VERSION 5.8 ;
BUSBITCHARS "[]" ;
DIVIDERCHAR "/" ;
UNITS
    DATABASE MICRONS 1000 ;
END UNITS

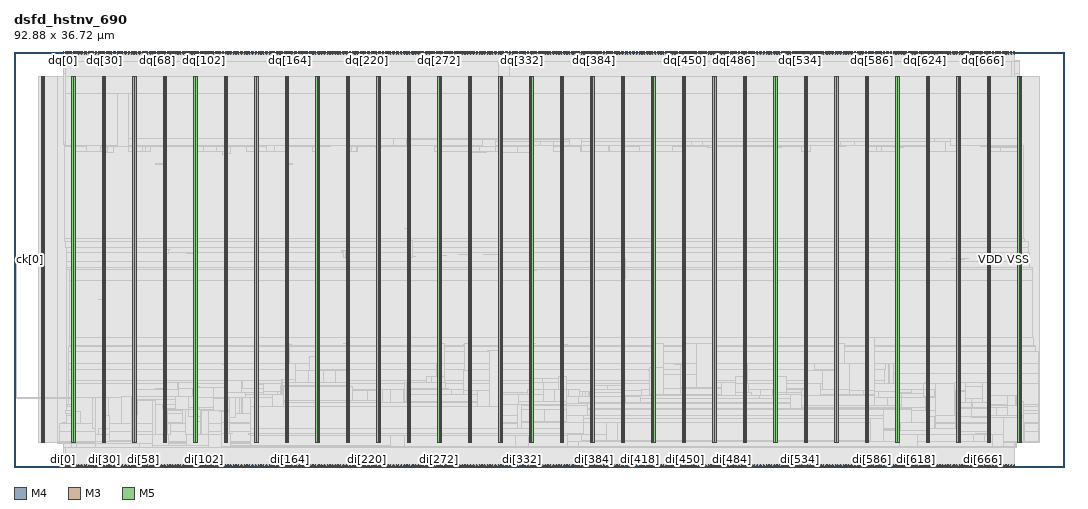
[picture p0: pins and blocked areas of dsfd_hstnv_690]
MACRO dsfd_hstnv_690
  FOREIGN dsfd_hstnv_690 0 0 ;
  CLASS BLOCK ;
  SIZE 92.88 BY 36.72 ;
  PIN ck[0]
    DIRECTION INPUT ;
    USE SIGNAL ;
    PORT
      LAYER M4 ;
        RECT  0 18.384 0.192 18.408 ;
    END
    PORT
      LAYER M4 ;
        RECT  0.156 18.384 0.275 18.408 ;
    END
  END ck[0]
  PIN di[0]
    DIRECTION INPUT ;
    USE SIGNAL ;
    PORT
      LAYER M3 ;
        RECT  4.356 0 4.374 0.144 ;
    END
  END di[0]
  PIN di[100]
    DIRECTION INPUT ;
    USE SIGNAL ;
    PORT
      LAYER M3 ;
        RECT  16.596 0 16.614 0.144 ;
    END
  END di[100]
  PIN di[101]
    DIRECTION INPUT ;
    USE SIGNAL ;
    PORT
      LAYER M5 ;
        RECT  16.704 0 16.728 0.192 ;
    END
  END di[101]
  PIN di[102]
    DIRECTION INPUT ;
    USE SIGNAL ;
    PORT
      LAYER M3 ;
        RECT  16.812 0 16.83 0.144 ;
    END
  END di[102]
  PIN di[103]
    DIRECTION INPUT ;
    USE SIGNAL ;
    PORT
      LAYER M5 ;
        RECT  16.944 0 16.968 0.192 ;
    END
  END di[103]
  PIN di[104]
    DIRECTION INPUT ;
    USE SIGNAL ;
    PORT
      LAYER M3 ;
        RECT  17.064 0 17.082 0.144 ;
    END
  END di[104]
  PIN di[105]
    DIRECTION INPUT ;
    USE SIGNAL ;
    PORT
      LAYER M5 ;
        RECT  17.184 0 17.208 0.192 ;
    END
  END di[105]
  PIN di[106]
    DIRECTION INPUT ;
    USE SIGNAL ;
    PORT
      LAYER M3 ;
        RECT  17.316 0 17.334 0.144 ;
    END
  END di[106]
  PIN di[107]
    DIRECTION INPUT ;
    USE SIGNAL ;
    PORT
      LAYER M5 ;
        RECT  17.424 0 17.448 0.192 ;
    END
  END di[107]
  PIN di[108]
    DIRECTION INPUT ;
    USE SIGNAL ;
    PORT
      LAYER M3 ;
        RECT  17.568 0 17.586 0.144 ;
    END
  END di[108]
  PIN di[109]
    DIRECTION INPUT ;
    USE SIGNAL ;
    PORT
      LAYER M5 ;
        RECT  17.664 0 17.688 0.192 ;
    END
  END di[109]
  PIN di[10]
    DIRECTION INPUT ;
    USE SIGNAL ;
    PORT
      LAYER M3 ;
        RECT  5.58 0 5.598 0.144 ;
    END
  END di[10]
  PIN di[110]
    DIRECTION INPUT ;
    USE SIGNAL ;
    PORT
      LAYER M3 ;
        RECT  17.784 0 17.802 0.144 ;
    END
  END di[110]
  PIN di[111]
    DIRECTION INPUT ;
    USE SIGNAL ;
    PORT
      LAYER M5 ;
        RECT  17.904 0 17.928 0.192 ;
    END
  END di[111]
  PIN di[112]
    DIRECTION INPUT ;
    USE SIGNAL ;
    PORT
      LAYER M3 ;
        RECT  18.036 0 18.054 0.144 ;
    END
  END di[112]
  PIN di[113]
    DIRECTION INPUT ;
    USE SIGNAL ;
    PORT
      LAYER M5 ;
        RECT  18.144 0 18.168 0.192 ;
    END
  END di[113]
  PIN di[114]
    DIRECTION INPUT ;
    USE SIGNAL ;
    PORT
      LAYER M3 ;
        RECT  18.288 0 18.306 0.144 ;
    END
  END di[114]
  PIN di[115]
    DIRECTION INPUT ;
    USE SIGNAL ;
    PORT
      LAYER M5 ;
        RECT  18.432 0 18.456 0.192 ;
    END
  END di[115]
  PIN di[116]
    DIRECTION INPUT ;
    USE SIGNAL ;
    PORT
      LAYER M3 ;
        RECT  18.54 0 18.558 0.144 ;
    END
  END di[116]
  PIN di[117]
    DIRECTION INPUT ;
    USE SIGNAL ;
    PORT
      LAYER M5 ;
        RECT  18.672 0 18.696 0.192 ;
    END
  END di[117]
  PIN di[118]
    DIRECTION INPUT ;
    USE SIGNAL ;
    PORT
      LAYER M3 ;
        RECT  18.792 0 18.81 0.144 ;
    END
  END di[118]
  PIN di[119]
    DIRECTION INPUT ;
    USE SIGNAL ;
    PORT
      LAYER M5 ;
        RECT  18.912 0 18.936 0.192 ;
    END
  END di[119]
  PIN di[11]
    DIRECTION INPUT ;
    USE SIGNAL ;
    PORT
      LAYER M5 ;
        RECT  5.712 0 5.736 0.192 ;
    END
  END di[11]
  PIN di[120]
    DIRECTION INPUT ;
    USE SIGNAL ;
    PORT
      LAYER M3 ;
        RECT  19.008 0 19.026 0.144 ;
    END
  END di[120]
  PIN di[121]
    DIRECTION INPUT ;
    USE SIGNAL ;
    PORT
      LAYER M5 ;
        RECT  19.152 0 19.176 0.192 ;
    END
  END di[121]
  PIN di[122]
    DIRECTION INPUT ;
    USE SIGNAL ;
    PORT
      LAYER M3 ;
        RECT  19.26 0 19.278 0.144 ;
    END
  END di[122]
  PIN di[123]
    DIRECTION INPUT ;
    USE SIGNAL ;
    PORT
      LAYER M5 ;
        RECT  19.392 0 19.416 0.192 ;
    END
  END di[123]
  PIN di[124]
    DIRECTION INPUT ;
    USE SIGNAL ;
    PORT
      LAYER M3 ;
        RECT  19.512 0 19.53 0.144 ;
    END
  END di[124]
  PIN di[125]
    DIRECTION INPUT ;
    USE SIGNAL ;
    PORT
      LAYER M5 ;
        RECT  19.632 0 19.656 0.192 ;
    END
  END di[125]
  PIN di[126]
    DIRECTION INPUT ;
    USE SIGNAL ;
    PORT
      LAYER M3 ;
        RECT  19.764 0 19.782 0.144 ;
    END
  END di[126]
  PIN di[127]
    DIRECTION INPUT ;
    USE SIGNAL ;
    PORT
      LAYER M5 ;
        RECT  19.872 0 19.896 0.192 ;
    END
  END di[127]
  PIN di[128]
    DIRECTION INPUT ;
    USE SIGNAL ;
    PORT
      LAYER M3 ;
        RECT  20.016 0 20.034 0.144 ;
    END
  END di[128]
  PIN di[129]
    DIRECTION INPUT ;
    USE SIGNAL ;
    PORT
      LAYER M5 ;
        RECT  20.112 0 20.136 0.192 ;
    END
  END di[129]
  PIN di[12]
    DIRECTION INPUT ;
    USE SIGNAL ;
    PORT
      LAYER M3 ;
        RECT  5.832 0 5.85 0.144 ;
    END
  END di[12]
  PIN di[130]
    DIRECTION INPUT ;
    USE SIGNAL ;
    PORT
      LAYER M3 ;
        RECT  20.232 0 20.25 0.144 ;
    END
  END di[130]
  PIN di[131]
    DIRECTION INPUT ;
    USE SIGNAL ;
    PORT
      LAYER M5 ;
        RECT  20.352 0 20.376 0.192 ;
    END
  END di[131]
  PIN di[132]
    DIRECTION INPUT ;
    USE SIGNAL ;
    PORT
      LAYER M3 ;
        RECT  20.484 0 20.502 0.144 ;
    END
  END di[132]
  PIN di[133]
    DIRECTION INPUT ;
    USE SIGNAL ;
    PORT
      LAYER M5 ;
        RECT  20.592 0 20.616 0.192 ;
    END
  END di[133]
  PIN di[134]
    DIRECTION INPUT ;
    USE SIGNAL ;
    PORT
      LAYER M3 ;
        RECT  20.736 0 20.754 0.144 ;
    END
  END di[134]
  PIN di[135]
    DIRECTION INPUT ;
    USE SIGNAL ;
    PORT
      LAYER M5 ;
        RECT  20.832 0 20.856 0.192 ;
    END
  END di[135]
  PIN di[136]
    DIRECTION INPUT ;
    USE SIGNAL ;
    PORT
      LAYER M3 ;
        RECT  20.988 0 21.006 0.144 ;
    END
  END di[136]
  PIN di[137]
    DIRECTION INPUT ;
    USE SIGNAL ;
    PORT
      LAYER M5 ;
        RECT  21.072 0 21.096 0.192 ;
    END
  END di[137]
  PIN di[138]
    DIRECTION INPUT ;
    USE SIGNAL ;
    PORT
      LAYER M3 ;
        RECT  21.204 0 21.222 0.144 ;
    END
  END di[138]
  PIN di[139]
    DIRECTION INPUT ;
    USE SIGNAL ;
    PORT
      LAYER M5 ;
        RECT  21.36 0 21.384 0.192 ;
    END
  END di[139]
  PIN di[13]
    DIRECTION INPUT ;
    USE SIGNAL ;
    PORT
      LAYER M5 ;
        RECT  5.952 0 5.976 0.192 ;
    END
  END di[13]
  PIN di[140]
    DIRECTION INPUT ;
    USE SIGNAL ;
    PORT
      LAYER M3 ;
        RECT  21.456 0 21.474 0.144 ;
    END
  END di[140]
  PIN di[141]
    DIRECTION INPUT ;
    USE SIGNAL ;
    PORT
      LAYER M5 ;
        RECT  21.6 0 21.624 0.192 ;
    END
  END di[141]
  PIN di[142]
    DIRECTION INPUT ;
    USE SIGNAL ;
    PORT
      LAYER M3 ;
        RECT  21.708 0 21.726 0.144 ;
    END
  END di[142]
  PIN di[143]
    DIRECTION INPUT ;
    USE SIGNAL ;
    PORT
      LAYER M5 ;
        RECT  21.84 0 21.864 0.192 ;
    END
  END di[143]
  PIN di[144]
    DIRECTION INPUT ;
    USE SIGNAL ;
    PORT
      LAYER M3 ;
        RECT  21.96 0 21.978 0.144 ;
    END
  END di[144]
  PIN di[145]
    DIRECTION INPUT ;
    USE SIGNAL ;
    PORT
      LAYER M5 ;
        RECT  22.08 0 22.104 0.192 ;
    END
  END di[145]
  PIN di[146]
    DIRECTION INPUT ;
    USE SIGNAL ;
    PORT
      LAYER M3 ;
        RECT  22.212 0 22.23 0.144 ;
    END
  END di[146]
  PIN di[147]
    DIRECTION INPUT ;
    USE SIGNAL ;
    PORT
      LAYER M5 ;
        RECT  22.32 0 22.344 0.192 ;
    END
  END di[147]
  PIN di[148]
    DIRECTION INPUT ;
    USE SIGNAL ;
    PORT
      LAYER M3 ;
        RECT  22.428 0 22.446 0.144 ;
    END
  END di[148]
  PIN di[149]
    DIRECTION INPUT ;
    USE SIGNAL ;
    PORT
      LAYER M5 ;
        RECT  22.56 0 22.584 0.192 ;
    END
  END di[149]
  PIN di[14]
    DIRECTION INPUT ;
    USE SIGNAL ;
    PORT
      LAYER M3 ;
        RECT  6.084 0 6.102 0.144 ;
    END
  END di[14]
  PIN di[150]
    DIRECTION INPUT ;
    USE SIGNAL ;
    PORT
      LAYER M3 ;
        RECT  22.68 0 22.698 0.144 ;
    END
  END di[150]
  PIN di[151]
    DIRECTION INPUT ;
    USE SIGNAL ;
    PORT
      LAYER M5 ;
        RECT  22.8 0 22.824 0.192 ;
    END
  END di[151]
  PIN di[152]
    DIRECTION INPUT ;
    USE SIGNAL ;
    PORT
      LAYER M3 ;
        RECT  22.932 0 22.95 0.144 ;
    END
  END di[152]
  PIN di[153]
    DIRECTION INPUT ;
    USE SIGNAL ;
    PORT
      LAYER M5 ;
        RECT  23.04 0 23.064 0.192 ;
    END
  END di[153]
  PIN di[154]
    DIRECTION INPUT ;
    USE SIGNAL ;
    PORT
      LAYER M3 ;
        RECT  23.184 0 23.202 0.144 ;
    END
  END di[154]
  PIN di[155]
    DIRECTION INPUT ;
    USE SIGNAL ;
    PORT
      LAYER M5 ;
        RECT  23.28 0 23.304 0.192 ;
    END
  END di[155]
  PIN di[156]
    DIRECTION INPUT ;
    USE SIGNAL ;
    PORT
      LAYER M3 ;
        RECT  23.4 0 23.418 0.144 ;
    END
  END di[156]
  PIN di[157]
    DIRECTION INPUT ;
    USE SIGNAL ;
    PORT
      LAYER M5 ;
        RECT  23.52 0 23.544 0.192 ;
    END
  END di[157]
  PIN di[158]
    DIRECTION INPUT ;
    USE SIGNAL ;
    PORT
      LAYER M3 ;
        RECT  23.652 0 23.67 0.144 ;
    END
  END di[158]
  PIN di[159]
    DIRECTION INPUT ;
    USE SIGNAL ;
    PORT
      LAYER M5 ;
        RECT  23.76 0 23.784 0.192 ;
    END
  END di[159]
  PIN di[15]
    DIRECTION INPUT ;
    USE SIGNAL ;
    PORT
      LAYER M5 ;
        RECT  6.192 0 6.216 0.192 ;
    END
  END di[15]
  PIN di[160]
    DIRECTION INPUT ;
    USE SIGNAL ;
    PORT
      LAYER M3 ;
        RECT  23.904 0 23.922 0.144 ;
    END
  END di[160]
  PIN di[161]
    DIRECTION INPUT ;
    USE SIGNAL ;
    PORT
      LAYER M5 ;
        RECT  24.048 0 24.072 0.192 ;
    END
  END di[161]
  PIN di[162]
    DIRECTION INPUT ;
    USE SIGNAL ;
    PORT
      LAYER M3 ;
        RECT  24.156 0 24.174 0.144 ;
    END
  END di[162]
  PIN di[163]
    DIRECTION INPUT ;
    USE SIGNAL ;
    PORT
      LAYER M5 ;
        RECT  24.288 0 24.312 0.192 ;
    END
  END di[163]
  PIN di[164]
    DIRECTION INPUT ;
    USE SIGNAL ;
    PORT
      LAYER M3 ;
        RECT  24.408 0 24.426 0.144 ;
    END
  END di[164]
  PIN di[165]
    DIRECTION INPUT ;
    USE SIGNAL ;
    PORT
      LAYER M5 ;
        RECT  24.528 0 24.552 0.192 ;
    END
  END di[165]
  PIN di[166]
    DIRECTION INPUT ;
    USE SIGNAL ;
    PORT
      LAYER M3 ;
        RECT  24.624 0 24.642 0.144 ;
    END
  END di[166]
  PIN di[167]
    DIRECTION INPUT ;
    USE SIGNAL ;
    PORT
      LAYER M5 ;
        RECT  24.768 0 24.792 0.192 ;
    END
  END di[167]
  PIN di[168]
    DIRECTION INPUT ;
    USE SIGNAL ;
    PORT
      LAYER M3 ;
        RECT  24.876 0 24.894 0.144 ;
    END
  END di[168]
  PIN di[169]
    DIRECTION INPUT ;
    USE SIGNAL ;
    PORT
      LAYER M5 ;
        RECT  25.008 0 25.032 0.192 ;
    END
  END di[169]
  PIN di[16]
    DIRECTION INPUT ;
    USE SIGNAL ;
    PORT
      LAYER M3 ;
        RECT  6.336 0 6.354 0.144 ;
    END
  END di[16]
  PIN di[170]
    DIRECTION INPUT ;
    USE SIGNAL ;
    PORT
      LAYER M3 ;
        RECT  25.128 0 25.146 0.144 ;
    END
  END di[170]
  PIN di[171]
    DIRECTION INPUT ;
    USE SIGNAL ;
    PORT
      LAYER M5 ;
        RECT  25.248 0 25.272 0.192 ;
    END
  END di[171]
  PIN di[172]
    DIRECTION INPUT ;
    USE SIGNAL ;
    PORT
      LAYER M3 ;
        RECT  25.38 0 25.398 0.144 ;
    END
  END di[172]
  PIN di[173]
    DIRECTION INPUT ;
    USE SIGNAL ;
    PORT
      LAYER M5 ;
        RECT  25.488 0 25.512 0.192 ;
    END
  END di[173]
  PIN di[174]
    DIRECTION INPUT ;
    USE SIGNAL ;
    PORT
      LAYER M3 ;
        RECT  25.632 0 25.65 0.144 ;
    END
  END di[174]
  PIN di[175]
    DIRECTION INPUT ;
    USE SIGNAL ;
    PORT
      LAYER M5 ;
        RECT  25.728 0 25.752 0.192 ;
    END
  END di[175]
  PIN di[176]
    DIRECTION INPUT ;
    USE SIGNAL ;
    PORT
      LAYER M3 ;
        RECT  25.848 0 25.866 0.144 ;
    END
  END di[176]
  PIN di[177]
    DIRECTION INPUT ;
    USE SIGNAL ;
    PORT
      LAYER M5 ;
        RECT  25.968 0 25.992 0.192 ;
    END
  END di[177]
  PIN di[178]
    DIRECTION INPUT ;
    USE SIGNAL ;
    PORT
      LAYER M3 ;
        RECT  26.1 0 26.118 0.144 ;
    END
  END di[178]
  PIN di[179]
    DIRECTION INPUT ;
    USE SIGNAL ;
    PORT
      LAYER M5 ;
        RECT  26.208 0 26.232 0.192 ;
    END
  END di[179]
  PIN di[17]
    DIRECTION INPUT ;
    USE SIGNAL ;
    PORT
      LAYER M5 ;
        RECT  6.432 0 6.456 0.192 ;
    END
  END di[17]
  PIN di[180]
    DIRECTION INPUT ;
    USE SIGNAL ;
    PORT
      LAYER M3 ;
        RECT  26.352 0 26.37 0.144 ;
    END
  END di[180]
  PIN di[181]
    DIRECTION INPUT ;
    USE SIGNAL ;
    PORT
      LAYER M5 ;
        RECT  26.448 0 26.472 0.192 ;
    END
  END di[181]
  PIN di[182]
    DIRECTION INPUT ;
    USE SIGNAL ;
    PORT
      LAYER M3 ;
        RECT  26.604 0 26.622 0.144 ;
    END
  END di[182]
  PIN di[183]
    DIRECTION INPUT ;
    USE SIGNAL ;
    PORT
      LAYER M5 ;
        RECT  26.688 0 26.712 0.192 ;
    END
  END di[183]
  PIN di[184]
    DIRECTION INPUT ;
    USE SIGNAL ;
    PORT
      LAYER M3 ;
        RECT  26.82 0 26.838 0.144 ;
    END
  END di[184]
  PIN di[185]
    DIRECTION INPUT ;
    USE SIGNAL ;
    PORT
      LAYER M5 ;
        RECT  26.976 0 27 0.192 ;
    END
  END di[185]
  PIN di[186]
    DIRECTION INPUT ;
    USE SIGNAL ;
    PORT
      LAYER M3 ;
        RECT  27.072 0 27.09 0.144 ;
    END
  END di[186]
  PIN di[187]
    DIRECTION INPUT ;
    USE SIGNAL ;
    PORT
      LAYER M5 ;
        RECT  27.216 0 27.24 0.192 ;
    END
  END di[187]
  PIN di[188]
    DIRECTION INPUT ;
    USE SIGNAL ;
    PORT
      LAYER M3 ;
        RECT  27.324 0 27.342 0.144 ;
    END
  END di[188]
  PIN di[189]
    DIRECTION INPUT ;
    USE SIGNAL ;
    PORT
      LAYER M5 ;
        RECT  27.456 0 27.48 0.192 ;
    END
  END di[189]
  PIN di[18]
    DIRECTION INPUT ;
    USE SIGNAL ;
    PORT
      LAYER M3 ;
        RECT  6.552 0 6.57 0.144 ;
    END
  END di[18]
  PIN di[190]
    DIRECTION INPUT ;
    USE SIGNAL ;
    PORT
      LAYER M3 ;
        RECT  27.576 0 27.594 0.144 ;
    END
  END di[190]
  PIN di[191]
    DIRECTION INPUT ;
    USE SIGNAL ;
    PORT
      LAYER M5 ;
        RECT  27.696 0 27.72 0.192 ;
    END
  END di[191]
  PIN di[192]
    DIRECTION INPUT ;
    USE SIGNAL ;
    PORT
      LAYER M3 ;
        RECT  27.828 0 27.846 0.144 ;
    END
  END di[192]
  PIN di[193]
    DIRECTION INPUT ;
    USE SIGNAL ;
    PORT
      LAYER M5 ;
        RECT  27.936 0 27.96 0.192 ;
    END
  END di[193]
  PIN di[194]
    DIRECTION INPUT ;
    USE SIGNAL ;
    PORT
      LAYER M3 ;
        RECT  28.044 0 28.062 0.144 ;
    END
  END di[194]
  PIN di[195]
    DIRECTION INPUT ;
    USE SIGNAL ;
    PORT
      LAYER M5 ;
        RECT  28.176 0 28.2 0.192 ;
    END
  END di[195]
  PIN di[196]
    DIRECTION INPUT ;
    USE SIGNAL ;
    PORT
      LAYER M3 ;
        RECT  28.296 0 28.314 0.144 ;
    END
  END di[196]
  PIN di[197]
    DIRECTION INPUT ;
    USE SIGNAL ;
    PORT
      LAYER M5 ;
        RECT  28.416 0 28.44 0.192 ;
    END
  END di[197]
  PIN di[198]
    DIRECTION INPUT ;
    USE SIGNAL ;
    PORT
      LAYER M3 ;
        RECT  28.548 0 28.566 0.144 ;
    END
  END di[198]
  PIN di[199]
    DIRECTION INPUT ;
    USE SIGNAL ;
    PORT
      LAYER M5 ;
        RECT  28.656 0 28.68 0.192 ;
    END
  END di[199]
  PIN di[19]
    DIRECTION INPUT ;
    USE SIGNAL ;
    PORT
      LAYER M5 ;
        RECT  6.672 0 6.696 0.192 ;
    END
  END di[19]
  PIN di[1]
    DIRECTION INPUT ;
    USE SIGNAL ;
    PORT
      LAYER M5 ;
        RECT  4.512 0 4.536 0.192 ;
    END
  END di[1]
  PIN di[200]
    DIRECTION INPUT ;
    USE SIGNAL ;
    PORT
      LAYER M3 ;
        RECT  28.8 0 28.818 0.144 ;
    END
  END di[200]
  PIN di[201]
    DIRECTION INPUT ;
    USE SIGNAL ;
    PORT
      LAYER M5 ;
        RECT  28.896 0 28.92 0.192 ;
    END
  END di[201]
  PIN di[202]
    DIRECTION INPUT ;
    USE SIGNAL ;
    PORT
      LAYER M3 ;
        RECT  29.016 0 29.034 0.144 ;
    END
  END di[202]
  PIN di[203]
    DIRECTION INPUT ;
    USE SIGNAL ;
    PORT
      LAYER M5 ;
        RECT  29.136 0 29.16 0.192 ;
    END
  END di[203]
  PIN di[204]
    DIRECTION INPUT ;
    USE SIGNAL ;
    PORT
      LAYER M3 ;
        RECT  29.268 0 29.286 0.144 ;
    END
  END di[204]
  PIN di[205]
    DIRECTION INPUT ;
    USE SIGNAL ;
    PORT
      LAYER M5 ;
        RECT  29.376 0 29.4 0.192 ;
    END
  END di[205]
  PIN di[206]
    DIRECTION INPUT ;
    USE SIGNAL ;
    PORT
      LAYER M3 ;
        RECT  29.52 0 29.538 0.144 ;
    END
  END di[206]
  PIN di[207]
    DIRECTION INPUT ;
    USE SIGNAL ;
    PORT
      LAYER M5 ;
        RECT  29.664 0 29.688 0.192 ;
    END
  END di[207]
  PIN di[208]
    DIRECTION INPUT ;
    USE SIGNAL ;
    PORT
      LAYER M3 ;
        RECT  29.772 0 29.79 0.144 ;
    END
  END di[208]
  PIN di[209]
    DIRECTION INPUT ;
    USE SIGNAL ;
    PORT
      LAYER M5 ;
        RECT  29.904 0 29.928 0.192 ;
    END
  END di[209]
  PIN di[20]
    DIRECTION INPUT ;
    USE SIGNAL ;
    PORT
      LAYER M3 ;
        RECT  6.804 0 6.822 0.144 ;
    END
  END di[20]
  PIN di[210]
    DIRECTION INPUT ;
    USE SIGNAL ;
    PORT
      LAYER M3 ;
        RECT  30.024 0 30.042 0.144 ;
    END
  END di[210]
  PIN di[211]
    DIRECTION INPUT ;
    USE SIGNAL ;
    PORT
      LAYER M5 ;
        RECT  30.144 0 30.168 0.192 ;
    END
  END di[211]
  PIN di[212]
    DIRECTION INPUT ;
    USE SIGNAL ;
    PORT
      LAYER M3 ;
        RECT  30.24 0 30.258 0.144 ;
    END
  END di[212]
  PIN di[213]
    DIRECTION INPUT ;
    USE SIGNAL ;
    PORT
      LAYER M5 ;
        RECT  30.384 0 30.408 0.192 ;
    END
  END di[213]
  PIN di[214]
    DIRECTION INPUT ;
    USE SIGNAL ;
    PORT
      LAYER M3 ;
        RECT  30.492 0 30.51 0.144 ;
    END
  END di[214]
  PIN di[215]
    DIRECTION INPUT ;
    USE SIGNAL ;
    PORT
      LAYER M5 ;
        RECT  30.624 0 30.648 0.192 ;
    END
  END di[215]
  PIN di[216]
    DIRECTION INPUT ;
    USE SIGNAL ;
    PORT
      LAYER M3 ;
        RECT  30.744 0 30.762 0.144 ;
    END
  END di[216]
  PIN di[217]
    DIRECTION INPUT ;
    USE SIGNAL ;
    PORT
      LAYER M5 ;
        RECT  30.864 0 30.888 0.192 ;
    END
  END di[217]
  PIN di[218]
    DIRECTION INPUT ;
    USE SIGNAL ;
    PORT
      LAYER M3 ;
        RECT  30.996 0 31.014 0.144 ;
    END
  END di[218]
  PIN di[219]
    DIRECTION INPUT ;
    USE SIGNAL ;
    PORT
      LAYER M5 ;
        RECT  31.104 0 31.128 0.192 ;
    END
  END di[219]
  PIN di[21]
    DIRECTION INPUT ;
    USE SIGNAL ;
    PORT
      LAYER M5 ;
        RECT  6.912 0 6.936 0.192 ;
    END
  END di[21]
  PIN di[220]
    DIRECTION INPUT ;
    USE SIGNAL ;
    PORT
      LAYER M3 ;
        RECT  31.248 0 31.266 0.144 ;
    END
  END di[220]
  PIN di[221]
    DIRECTION INPUT ;
    USE SIGNAL ;
    PORT
      LAYER M5 ;
        RECT  31.344 0 31.368 0.192 ;
    END
  END di[221]
  PIN di[222]
    DIRECTION INPUT ;
    USE SIGNAL ;
    PORT
      LAYER M3 ;
        RECT  31.464 0 31.482 0.144 ;
    END
  END di[222]
  PIN di[223]
    DIRECTION INPUT ;
    USE SIGNAL ;
    PORT
      LAYER M5 ;
        RECT  31.584 0 31.608 0.192 ;
    END
  END di[223]
  PIN di[224]
    DIRECTION INPUT ;
    USE SIGNAL ;
    PORT
      LAYER M3 ;
        RECT  31.716 0 31.734 0.144 ;
    END
  END di[224]
  PIN di[225]
    DIRECTION INPUT ;
    USE SIGNAL ;
    PORT
      LAYER M5 ;
        RECT  31.824 0 31.848 0.192 ;
    END
  END di[225]
  PIN di[226]
    DIRECTION INPUT ;
    USE SIGNAL ;
    PORT
      LAYER M3 ;
        RECT  31.968 0 31.986 0.144 ;
    END
  END di[226]
  PIN di[227]
    DIRECTION INPUT ;
    USE SIGNAL ;
    PORT
      LAYER M5 ;
        RECT  32.064 0 32.088 0.192 ;
    END
  END di[227]
  PIN di[228]
    DIRECTION INPUT ;
    USE SIGNAL ;
    PORT
      LAYER M3 ;
        RECT  32.22 0 32.238 0.144 ;
    END
  END di[228]
  PIN di[229]
    DIRECTION INPUT ;
    USE SIGNAL ;
    PORT
      LAYER M5 ;
        RECT  32.304 0 32.328 0.192 ;
    END
  END di[229]
  PIN di[22]
    DIRECTION INPUT ;
    USE SIGNAL ;
    PORT
      LAYER M3 ;
        RECT  7.056 0 7.074 0.144 ;
    END
  END di[22]
  PIN di[230]
    DIRECTION INPUT ;
    USE SIGNAL ;
    PORT
      LAYER M3 ;
        RECT  32.436 0 32.454 0.144 ;
    END
  END di[230]
  PIN di[231]
    DIRECTION INPUT ;
    USE SIGNAL ;
    PORT
      LAYER M5 ;
        RECT  32.592 0 32.616 0.192 ;
    END
  END di[231]
  PIN di[232]
    DIRECTION INPUT ;
    USE SIGNAL ;
    PORT
      LAYER M3 ;
        RECT  32.688 0 32.706 0.144 ;
    END
  END di[232]
  PIN di[233]
    DIRECTION INPUT ;
    USE SIGNAL ;
    PORT
      LAYER M5 ;
        RECT  32.832 0 32.856 0.192 ;
    END
  END di[233]
  PIN di[234]
    DIRECTION INPUT ;
    USE SIGNAL ;
    PORT
      LAYER M3 ;
        RECT  32.94 0 32.958 0.144 ;
    END
  END di[234]
  PIN di[235]
    DIRECTION INPUT ;
    USE SIGNAL ;
    PORT
      LAYER M5 ;
        RECT  33.072 0 33.096 0.192 ;
    END
  END di[235]
  PIN di[236]
    DIRECTION INPUT ;
    USE SIGNAL ;
    PORT
      LAYER M3 ;
        RECT  33.192 0 33.21 0.144 ;
    END
  END di[236]
  PIN di[237]
    DIRECTION INPUT ;
    USE SIGNAL ;
    PORT
      LAYER M5 ;
        RECT  33.312 0 33.336 0.192 ;
    END
  END di[237]
  PIN di[238]
    DIRECTION INPUT ;
    USE SIGNAL ;
    PORT
      LAYER M3 ;
        RECT  33.444 0 33.462 0.144 ;
    END
  END di[238]
  PIN di[239]
    DIRECTION INPUT ;
    USE SIGNAL ;
    PORT
      LAYER M5 ;
        RECT  33.552 0 33.576 0.192 ;
    END
  END di[239]
  PIN di[23]
    DIRECTION INPUT ;
    USE SIGNAL ;
    PORT
      LAYER M5 ;
        RECT  7.2 0 7.224 0.192 ;
    END
  END di[23]
  PIN di[240]
    DIRECTION INPUT ;
    USE SIGNAL ;
    PORT
      LAYER M3 ;
        RECT  33.66 0 33.678 0.144 ;
    END
  END di[240]
  PIN di[241]
    DIRECTION INPUT ;
    USE SIGNAL ;
    PORT
      LAYER M5 ;
        RECT  33.792 0 33.816 0.192 ;
    END
  END di[241]
  PIN di[242]
    DIRECTION INPUT ;
    USE SIGNAL ;
    PORT
      LAYER M3 ;
        RECT  33.912 0 33.93 0.144 ;
    END
  END di[242]
  PIN di[243]
    DIRECTION INPUT ;
    USE SIGNAL ;
    PORT
      LAYER M5 ;
        RECT  34.032 0 34.056 0.192 ;
    END
  END di[243]
  PIN di[244]
    DIRECTION INPUT ;
    USE SIGNAL ;
    PORT
      LAYER M3 ;
        RECT  34.164 0 34.182 0.144 ;
    END
  END di[244]
  PIN di[245]
    DIRECTION INPUT ;
    USE SIGNAL ;
    PORT
      LAYER M5 ;
        RECT  34.272 0 34.296 0.192 ;
    END
  END di[245]
  PIN di[246]
    DIRECTION INPUT ;
    USE SIGNAL ;
    PORT
      LAYER M3 ;
        RECT  34.416 0 34.434 0.144 ;
    END
  END di[246]
  PIN di[247]
    DIRECTION INPUT ;
    USE SIGNAL ;
    PORT
      LAYER M5 ;
        RECT  34.512 0 34.536 0.192 ;
    END
  END di[247]
  PIN di[248]
    DIRECTION INPUT ;
    USE SIGNAL ;
    PORT
      LAYER M3 ;
        RECT  34.632 0 34.65 0.144 ;
    END
  END di[248]
  PIN di[249]
    DIRECTION INPUT ;
    USE SIGNAL ;
    PORT
      LAYER M5 ;
        RECT  34.752 0 34.776 0.192 ;
    END
  END di[249]
  PIN di[24]
    DIRECTION INPUT ;
    USE SIGNAL ;
    PORT
      LAYER M3 ;
        RECT  7.308 0 7.326 0.144 ;
    END
  END di[24]
  PIN di[250]
    DIRECTION INPUT ;
    USE SIGNAL ;
    PORT
      LAYER M3 ;
        RECT  34.884 0 34.902 0.144 ;
    END
  END di[250]
  PIN di[251]
    DIRECTION INPUT ;
    USE SIGNAL ;
    PORT
      LAYER M5 ;
        RECT  34.992 0 35.016 0.192 ;
    END
  END di[251]
  PIN di[252]
    DIRECTION INPUT ;
    USE SIGNAL ;
    PORT
      LAYER M3 ;
        RECT  35.136 0 35.154 0.144 ;
    END
  END di[252]
  PIN di[253]
    DIRECTION INPUT ;
    USE SIGNAL ;
    PORT
      LAYER M5 ;
        RECT  35.28 0 35.304 0.192 ;
    END
  END di[253]
  PIN di[254]
    DIRECTION INPUT ;
    USE SIGNAL ;
    PORT
      LAYER M3 ;
        RECT  35.388 0 35.406 0.144 ;
    END
  END di[254]
  PIN di[255]
    DIRECTION INPUT ;
    USE SIGNAL ;
    PORT
      LAYER M5 ;
        RECT  35.52 0 35.544 0.192 ;
    END
  END di[255]
  PIN di[256]
    DIRECTION INPUT ;
    USE SIGNAL ;
    PORT
      LAYER M3 ;
        RECT  35.64 0 35.658 0.144 ;
    END
  END di[256]
  PIN di[257]
    DIRECTION INPUT ;
    USE SIGNAL ;
    PORT
      LAYER M5 ;
        RECT  35.76 0 35.784 0.192 ;
    END
  END di[257]
  PIN di[258]
    DIRECTION INPUT ;
    USE SIGNAL ;
    PORT
      LAYER M3 ;
        RECT  35.856 0 35.874 0.144 ;
    END
  END di[258]
  PIN di[259]
    DIRECTION INPUT ;
    USE SIGNAL ;
    PORT
      LAYER M5 ;
        RECT  36 0 36.024 0.192 ;
    END
  END di[259]
  PIN di[25]
    DIRECTION INPUT ;
    USE SIGNAL ;
    PORT
      LAYER M5 ;
        RECT  7.44 0 7.464 0.192 ;
    END
  END di[25]
  PIN di[260]
    DIRECTION INPUT ;
    USE SIGNAL ;
    PORT
      LAYER M3 ;
        RECT  36.108 0 36.126 0.144 ;
    END
  END di[260]
  PIN di[261]
    DIRECTION INPUT ;
    USE SIGNAL ;
    PORT
      LAYER M5 ;
        RECT  36.24 0 36.264 0.192 ;
    END
  END di[261]
  PIN di[262]
    DIRECTION INPUT ;
    USE SIGNAL ;
    PORT
      LAYER M3 ;
        RECT  36.36 0 36.378 0.144 ;
    END
  END di[262]
  PIN di[263]
    DIRECTION INPUT ;
    USE SIGNAL ;
    PORT
      LAYER M5 ;
        RECT  36.48 0 36.504 0.192 ;
    END
  END di[263]
  PIN di[264]
    DIRECTION INPUT ;
    USE SIGNAL ;
    PORT
      LAYER M3 ;
        RECT  36.612 0 36.63 0.144 ;
    END
  END di[264]
  PIN di[265]
    DIRECTION INPUT ;
    USE SIGNAL ;
    PORT
      LAYER M5 ;
        RECT  36.72 0 36.744 0.192 ;
    END
  END di[265]
  PIN di[266]
    DIRECTION INPUT ;
    USE SIGNAL ;
    PORT
      LAYER M3 ;
        RECT  36.864 0 36.882 0.144 ;
    END
  END di[266]
  PIN di[267]
    DIRECTION INPUT ;
    USE SIGNAL ;
    PORT
      LAYER M5 ;
        RECT  36.96 0 36.984 0.192 ;
    END
  END di[267]
  PIN di[268]
    DIRECTION INPUT ;
    USE SIGNAL ;
    PORT
      LAYER M3 ;
        RECT  37.08 0 37.098 0.144 ;
    END
  END di[268]
  PIN di[269]
    DIRECTION INPUT ;
    USE SIGNAL ;
    PORT
      LAYER M5 ;
        RECT  37.2 0 37.224 0.192 ;
    END
  END di[269]
  PIN di[26]
    DIRECTION INPUT ;
    USE SIGNAL ;
    PORT
      LAYER M3 ;
        RECT  7.56 0 7.578 0.144 ;
    END
  END di[26]
  PIN di[270]
    DIRECTION INPUT ;
    USE SIGNAL ;
    PORT
      LAYER M3 ;
        RECT  37.332 0 37.35 0.144 ;
    END
  END di[270]
  PIN di[271]
    DIRECTION INPUT ;
    USE SIGNAL ;
    PORT
      LAYER M5 ;
        RECT  37.44 0 37.464 0.192 ;
    END
  END di[271]
  PIN di[272]
    DIRECTION INPUT ;
    USE SIGNAL ;
    PORT
      LAYER M3 ;
        RECT  37.584 0 37.602 0.144 ;
    END
  END di[272]
  PIN di[273]
    DIRECTION INPUT ;
    USE SIGNAL ;
    PORT
      LAYER M5 ;
        RECT  37.68 0 37.704 0.192 ;
    END
  END di[273]
  PIN di[274]
    DIRECTION INPUT ;
    USE SIGNAL ;
    PORT
      LAYER M3 ;
        RECT  37.836 0 37.854 0.144 ;
    END
  END di[274]
  PIN di[275]
    DIRECTION INPUT ;
    USE SIGNAL ;
    PORT
      LAYER M5 ;
        RECT  37.92 0 37.944 0.192 ;
    END
  END di[275]
  PIN di[276]
    DIRECTION INPUT ;
    USE SIGNAL ;
    PORT
      LAYER M3 ;
        RECT  38.052 0 38.07 0.144 ;
    END
  END di[276]
  PIN di[277]
    DIRECTION INPUT ;
    USE SIGNAL ;
    PORT
      LAYER M5 ;
        RECT  38.208 0 38.232 0.192 ;
    END
  END di[277]
  PIN di[278]
    DIRECTION INPUT ;
    USE SIGNAL ;
    PORT
      LAYER M3 ;
        RECT  38.304 0 38.322 0.144 ;
    END
  END di[278]
  PIN di[279]
    DIRECTION INPUT ;
    USE SIGNAL ;
    PORT
      LAYER M5 ;
        RECT  38.448 0 38.472 0.192 ;
    END
  END di[279]
  PIN di[27]
    DIRECTION INPUT ;
    USE SIGNAL ;
    PORT
      LAYER M5 ;
        RECT  7.68 0 7.704 0.192 ;
    END
  END di[27]
  PIN di[280]
    DIRECTION INPUT ;
    USE SIGNAL ;
    PORT
      LAYER M3 ;
        RECT  38.556 0 38.574 0.144 ;
    END
  END di[280]
  PIN di[281]
    DIRECTION INPUT ;
    USE SIGNAL ;
    PORT
      LAYER M5 ;
        RECT  38.688 0 38.712 0.192 ;
    END
  END di[281]
  PIN di[282]
    DIRECTION INPUT ;
    USE SIGNAL ;
    PORT
      LAYER M3 ;
        RECT  38.808 0 38.826 0.144 ;
    END
  END di[282]
  PIN di[283]
    DIRECTION INPUT ;
    USE SIGNAL ;
    PORT
      LAYER M5 ;
        RECT  38.928 0 38.952 0.192 ;
    END
  END di[283]
  PIN di[284]
    DIRECTION INPUT ;
    USE SIGNAL ;
    PORT
      LAYER M3 ;
        RECT  39.06 0 39.078 0.144 ;
    END
  END di[284]
  PIN di[285]
    DIRECTION INPUT ;
    USE SIGNAL ;
    PORT
      LAYER M5 ;
        RECT  39.168 0 39.192 0.192 ;
    END
  END di[285]
  PIN di[286]
    DIRECTION INPUT ;
    USE SIGNAL ;
    PORT
      LAYER M3 ;
        RECT  39.276 0 39.294 0.144 ;
    END
  END di[286]
  PIN di[287]
    DIRECTION INPUT ;
    USE SIGNAL ;
    PORT
      LAYER M5 ;
        RECT  39.408 0 39.432 0.192 ;
    END
  END di[287]
  PIN di[288]
    DIRECTION INPUT ;
    USE SIGNAL ;
    PORT
      LAYER M3 ;
        RECT  39.528 0 39.546 0.144 ;
    END
  END di[288]
  PIN di[289]
    DIRECTION INPUT ;
    USE SIGNAL ;
    PORT
      LAYER M5 ;
        RECT  39.648 0 39.672 0.192 ;
    END
  END di[289]
  PIN di[28]
    DIRECTION INPUT ;
    USE SIGNAL ;
    PORT
      LAYER M3 ;
        RECT  7.776 0 7.794 0.144 ;
    END
  END di[28]
  PIN di[290]
    DIRECTION INPUT ;
    USE SIGNAL ;
    PORT
      LAYER M3 ;
        RECT  39.78 0 39.798 0.144 ;
    END
  END di[290]
  PIN di[291]
    DIRECTION INPUT ;
    USE SIGNAL ;
    PORT
      LAYER M5 ;
        RECT  39.888 0 39.912 0.192 ;
    END
  END di[291]
  PIN di[292]
    DIRECTION INPUT ;
    USE SIGNAL ;
    PORT
      LAYER M3 ;
        RECT  40.032 0 40.05 0.144 ;
    END
  END di[292]
  PIN di[293]
    DIRECTION INPUT ;
    USE SIGNAL ;
    PORT
      LAYER M5 ;
        RECT  40.128 0 40.152 0.192 ;
    END
  END di[293]
  PIN di[294]
    DIRECTION INPUT ;
    USE SIGNAL ;
    PORT
      LAYER M3 ;
        RECT  40.248 0 40.266 0.144 ;
    END
  END di[294]
  PIN di[295]
    DIRECTION INPUT ;
    USE SIGNAL ;
    PORT
      LAYER M5 ;
        RECT  40.368 0 40.392 0.192 ;
    END
  END di[295]
  PIN di[296]
    DIRECTION INPUT ;
    USE SIGNAL ;
    PORT
      LAYER M3 ;
        RECT  40.5 0 40.518 0.144 ;
    END
  END di[296]
  PIN di[297]
    DIRECTION INPUT ;
    USE SIGNAL ;
    PORT
      LAYER M5 ;
        RECT  40.608 0 40.632 0.192 ;
    END
  END di[297]
  PIN di[298]
    DIRECTION INPUT ;
    USE SIGNAL ;
    PORT
      LAYER M3 ;
        RECT  40.752 0 40.77 0.144 ;
    END
  END di[298]
  PIN di[299]
    DIRECTION INPUT ;
    USE SIGNAL ;
    PORT
      LAYER M5 ;
        RECT  40.896 0 40.92 0.192 ;
    END
  END di[299]
  PIN di[29]
    DIRECTION INPUT ;
    USE SIGNAL ;
    PORT
      LAYER M5 ;
        RECT  7.92 0 7.944 0.192 ;
    END
  END di[29]
  PIN di[2]
    DIRECTION INPUT ;
    USE SIGNAL ;
    PORT
      LAYER M3 ;
        RECT  4.608 0 4.626 0.144 ;
    END
  END di[2]
  PIN di[300]
    DIRECTION INPUT ;
    USE SIGNAL ;
    PORT
      LAYER M3 ;
        RECT  41.004 0 41.022 0.144 ;
    END
  END di[300]
  PIN di[301]
    DIRECTION INPUT ;
    USE SIGNAL ;
    PORT
      LAYER M5 ;
        RECT  41.136 0 41.16 0.192 ;
    END
  END di[301]
  PIN di[302]
    DIRECTION INPUT ;
    USE SIGNAL ;
    PORT
      LAYER M3 ;
        RECT  41.256 0 41.274 0.144 ;
    END
  END di[302]
  PIN di[303]
    DIRECTION INPUT ;
    USE SIGNAL ;
    PORT
      LAYER M5 ;
        RECT  41.376 0 41.4 0.192 ;
    END
  END di[303]
  PIN di[304]
    DIRECTION INPUT ;
    USE SIGNAL ;
    PORT
      LAYER M3 ;
        RECT  41.472 0 41.49 0.144 ;
    END
  END di[304]
  PIN di[305]
    DIRECTION INPUT ;
    USE SIGNAL ;
    PORT
      LAYER M5 ;
        RECT  41.616 0 41.64 0.192 ;
    END
  END di[305]
  PIN di[306]
    DIRECTION INPUT ;
    USE SIGNAL ;
    PORT
      LAYER M3 ;
        RECT  41.724 0 41.742 0.144 ;
    END
  END di[306]
  PIN di[307]
    DIRECTION INPUT ;
    USE SIGNAL ;
    PORT
      LAYER M5 ;
        RECT  41.856 0 41.88 0.192 ;
    END
  END di[307]
  PIN di[308]
    DIRECTION INPUT ;
    USE SIGNAL ;
    PORT
      LAYER M3 ;
        RECT  41.976 0 41.994 0.144 ;
    END
  END di[308]
  PIN di[309]
    DIRECTION INPUT ;
    USE SIGNAL ;
    PORT
      LAYER M5 ;
        RECT  42.096 0 42.12 0.192 ;
    END
  END di[309]
  PIN di[30]
    DIRECTION INPUT ;
    USE SIGNAL ;
    PORT
      LAYER M3 ;
        RECT  8.028 0 8.046 0.144 ;
    END
  END di[30]
  PIN di[310]
    DIRECTION INPUT ;
    USE SIGNAL ;
    PORT
      LAYER M3 ;
        RECT  42.228 0 42.246 0.144 ;
    END
  END di[310]
  PIN di[311]
    DIRECTION INPUT ;
    USE SIGNAL ;
    PORT
      LAYER M5 ;
        RECT  42.336 0 42.36 0.192 ;
    END
  END di[311]
  PIN di[312]
    DIRECTION INPUT ;
    USE SIGNAL ;
    PORT
      LAYER M3 ;
        RECT  42.48 0 42.498 0.144 ;
    END
  END di[312]
  PIN di[313]
    DIRECTION INPUT ;
    USE SIGNAL ;
    PORT
      LAYER M5 ;
        RECT  42.576 0 42.6 0.192 ;
    END
  END di[313]
  PIN di[314]
    DIRECTION INPUT ;
    USE SIGNAL ;
    PORT
      LAYER M3 ;
        RECT  42.696 0 42.714 0.144 ;
    END
  END di[314]
  PIN di[315]
    DIRECTION INPUT ;
    USE SIGNAL ;
    PORT
      LAYER M5 ;
        RECT  42.816 0 42.84 0.192 ;
    END
  END di[315]
  PIN di[316]
    DIRECTION INPUT ;
    USE SIGNAL ;
    PORT
      LAYER M3 ;
        RECT  42.948 0 42.966 0.144 ;
    END
  END di[316]
  PIN di[317]
    DIRECTION INPUT ;
    USE SIGNAL ;
    PORT
      LAYER M5 ;
        RECT  43.056 0 43.08 0.192 ;
    END
  END di[317]
  PIN di[318]
    DIRECTION INPUT ;
    USE SIGNAL ;
    PORT
      LAYER M3 ;
        RECT  43.2 0 43.218 0.144 ;
    END
  END di[318]
  PIN di[319]
    DIRECTION INPUT ;
    USE SIGNAL ;
    PORT
      LAYER M5 ;
        RECT  43.296 0 43.32 0.192 ;
    END
  END di[319]
  PIN di[31]
    DIRECTION INPUT ;
    USE SIGNAL ;
    PORT
      LAYER M5 ;
        RECT  8.16 0 8.184 0.192 ;
    END
  END di[31]
  PIN di[320]
    DIRECTION INPUT ;
    USE SIGNAL ;
    PORT
      LAYER M3 ;
        RECT  43.452 0 43.47 0.144 ;
    END
  END di[320]
  PIN di[321]
    DIRECTION INPUT ;
    USE SIGNAL ;
    PORT
      LAYER M5 ;
        RECT  43.536 0 43.56 0.192 ;
    END
  END di[321]
  PIN di[322]
    DIRECTION INPUT ;
    USE SIGNAL ;
    PORT
      LAYER M3 ;
        RECT  43.668 0 43.686 0.144 ;
    END
  END di[322]
  PIN di[323]
    DIRECTION INPUT ;
    USE SIGNAL ;
    PORT
      LAYER M5 ;
        RECT  43.824 0 43.848 0.192 ;
    END
  END di[323]
  PIN di[324]
    DIRECTION INPUT ;
    USE SIGNAL ;
    PORT
      LAYER M3 ;
        RECT  43.92 0 43.938 0.144 ;
    END
  END di[324]
  PIN di[325]
    DIRECTION INPUT ;
    USE SIGNAL ;
    PORT
      LAYER M5 ;
        RECT  44.064 0 44.088 0.192 ;
    END
  END di[325]
  PIN di[326]
    DIRECTION INPUT ;
    USE SIGNAL ;
    PORT
      LAYER M3 ;
        RECT  44.172 0 44.19 0.144 ;
    END
  END di[326]
  PIN di[327]
    DIRECTION INPUT ;
    USE SIGNAL ;
    PORT
      LAYER M5 ;
        RECT  44.304 0 44.328 0.192 ;
    END
  END di[327]
  PIN di[328]
    DIRECTION INPUT ;
    USE SIGNAL ;
    PORT
      LAYER M3 ;
        RECT  44.424 0 44.442 0.144 ;
    END
  END di[328]
  PIN di[329]
    DIRECTION INPUT ;
    USE SIGNAL ;
    PORT
      LAYER M5 ;
        RECT  44.544 0 44.568 0.192 ;
    END
  END di[329]
  PIN di[32]
    DIRECTION INPUT ;
    USE SIGNAL ;
    PORT
      LAYER M3 ;
        RECT  8.28 0 8.298 0.144 ;
    END
  END di[32]
  PIN di[330]
    DIRECTION INPUT ;
    USE SIGNAL ;
    PORT
      LAYER M3 ;
        RECT  44.676 0 44.694 0.144 ;
    END
  END di[330]
  PIN di[331]
    DIRECTION INPUT ;
    USE SIGNAL ;
    PORT
      LAYER M5 ;
        RECT  44.784 0 44.808 0.192 ;
    END
  END di[331]
  PIN di[332]
    DIRECTION INPUT ;
    USE SIGNAL ;
    PORT
      LAYER M3 ;
        RECT  44.892 0 44.91 0.144 ;
    END
  END di[332]
  PIN di[333]
    DIRECTION INPUT ;
    USE SIGNAL ;
    PORT
      LAYER M5 ;
        RECT  45.024 0 45.048 0.192 ;
    END
  END di[333]
  PIN di[334]
    DIRECTION INPUT ;
    USE SIGNAL ;
    PORT
      LAYER M3 ;
        RECT  45.144 0 45.162 0.144 ;
    END
  END di[334]
  PIN di[335]
    DIRECTION INPUT ;
    USE SIGNAL ;
    PORT
      LAYER M5 ;
        RECT  45.264 0 45.288 0.192 ;
    END
  END di[335]
  PIN di[336]
    DIRECTION INPUT ;
    USE SIGNAL ;
    PORT
      LAYER M3 ;
        RECT  45.396 0 45.414 0.144 ;
    END
  END di[336]
  PIN di[337]
    DIRECTION INPUT ;
    USE SIGNAL ;
    PORT
      LAYER M5 ;
        RECT  45.504 0 45.528 0.192 ;
    END
  END di[337]
  PIN di[338]
    DIRECTION INPUT ;
    USE SIGNAL ;
    PORT
      LAYER M3 ;
        RECT  45.648 0 45.666 0.144 ;
    END
  END di[338]
  PIN di[339]
    DIRECTION INPUT ;
    USE SIGNAL ;
    PORT
      LAYER M5 ;
        RECT  45.744 0 45.768 0.192 ;
    END
  END di[339]
  PIN di[33]
    DIRECTION INPUT ;
    USE SIGNAL ;
    PORT
      LAYER M5 ;
        RECT  8.4 0 8.424 0.192 ;
    END
  END di[33]
  PIN di[340]
    DIRECTION INPUT ;
    USE SIGNAL ;
    PORT
      LAYER M3 ;
        RECT  45.864 0 45.882 0.144 ;
    END
  END di[340]
  PIN di[341]
    DIRECTION INPUT ;
    USE SIGNAL ;
    PORT
      LAYER M5 ;
        RECT  45.984 0 46.008 0.192 ;
    END
  END di[341]
  PIN di[342]
    DIRECTION INPUT ;
    USE SIGNAL ;
    PORT
      LAYER M3 ;
        RECT  46.116 0 46.134 0.144 ;
    END
  END di[342]
  PIN di[343]
    DIRECTION INPUT ;
    USE SIGNAL ;
    PORT
      LAYER M5 ;
        RECT  46.224 0 46.248 0.192 ;
    END
  END di[343]
  PIN di[344]
    DIRECTION INPUT ;
    USE SIGNAL ;
    PORT
      LAYER M3 ;
        RECT  46.368 0 46.386 0.144 ;
    END
  END di[344]
  PIN di[345]
    DIRECTION INPUT ;
    USE SIGNAL ;
    PORT
      LAYER M5 ;
        RECT  46.512 0 46.536 0.192 ;
    END
  END di[345]
  PIN di[346]
    DIRECTION INPUT ;
    USE SIGNAL ;
    PORT
      LAYER M3 ;
        RECT  46.62 0 46.638 0.144 ;
    END
  END di[346]
  PIN di[347]
    DIRECTION INPUT ;
    USE SIGNAL ;
    PORT
      LAYER M5 ;
        RECT  46.752 0 46.776 0.192 ;
    END
  END di[347]
  PIN di[348]
    DIRECTION INPUT ;
    USE SIGNAL ;
    PORT
      LAYER M3 ;
        RECT  46.872 0 46.89 0.144 ;
    END
  END di[348]
  PIN di[349]
    DIRECTION INPUT ;
    USE SIGNAL ;
    PORT
      LAYER M5 ;
        RECT  46.992 0 47.016 0.192 ;
    END
  END di[349]
  PIN di[34]
    DIRECTION INPUT ;
    USE SIGNAL ;
    PORT
      LAYER M3 ;
        RECT  8.532 0 8.55 0.144 ;
    END
  END di[34]
  PIN di[350]
    DIRECTION INPUT ;
    USE SIGNAL ;
    PORT
      LAYER M3 ;
        RECT  47.088 0 47.106 0.144 ;
    END
  END di[350]
  PIN di[351]
    DIRECTION INPUT ;
    USE SIGNAL ;
    PORT
      LAYER M5 ;
        RECT  47.232 0 47.256 0.192 ;
    END
  END di[351]
  PIN di[352]
    DIRECTION INPUT ;
    USE SIGNAL ;
    PORT
      LAYER M3 ;
        RECT  47.34 0 47.358 0.144 ;
    END
  END di[352]
  PIN di[353]
    DIRECTION INPUT ;
    USE SIGNAL ;
    PORT
      LAYER M5 ;
        RECT  47.472 0 47.496 0.192 ;
    END
  END di[353]
  PIN di[354]
    DIRECTION INPUT ;
    USE SIGNAL ;
    PORT
      LAYER M3 ;
        RECT  47.592 0 47.61 0.144 ;
    END
  END di[354]
  PIN di[355]
    DIRECTION INPUT ;
    USE SIGNAL ;
    PORT
      LAYER M5 ;
        RECT  47.712 0 47.736 0.192 ;
    END
  END di[355]
  PIN di[356]
    DIRECTION INPUT ;
    USE SIGNAL ;
    PORT
      LAYER M3 ;
        RECT  47.844 0 47.862 0.144 ;
    END
  END di[356]
  PIN di[357]
    DIRECTION INPUT ;
    USE SIGNAL ;
    PORT
      LAYER M5 ;
        RECT  47.952 0 47.976 0.192 ;
    END
  END di[357]
  PIN di[358]
    DIRECTION INPUT ;
    USE SIGNAL ;
    PORT
      LAYER M3 ;
        RECT  48.096 0 48.114 0.144 ;
    END
  END di[358]
  PIN di[359]
    DIRECTION INPUT ;
    USE SIGNAL ;
    PORT
      LAYER M5 ;
        RECT  48.192 0 48.216 0.192 ;
    END
  END di[359]
  PIN di[35]
    DIRECTION INPUT ;
    USE SIGNAL ;
    PORT
      LAYER M5 ;
        RECT  8.64 0 8.664 0.192 ;
    END
  END di[35]
  PIN di[360]
    DIRECTION INPUT ;
    USE SIGNAL ;
    PORT
      LAYER M3 ;
        RECT  48.312 0 48.33 0.144 ;
    END
  END di[360]
  PIN di[361]
    DIRECTION INPUT ;
    USE SIGNAL ;
    PORT
      LAYER M5 ;
        RECT  48.432 0 48.456 0.192 ;
    END
  END di[361]
  PIN di[362]
    DIRECTION INPUT ;
    USE SIGNAL ;
    PORT
      LAYER M3 ;
        RECT  48.564 0 48.582 0.144 ;
    END
  END di[362]
  PIN di[363]
    DIRECTION INPUT ;
    USE SIGNAL ;
    PORT
      LAYER M5 ;
        RECT  48.672 0 48.696 0.192 ;
    END
  END di[363]
  PIN di[364]
    DIRECTION INPUT ;
    USE SIGNAL ;
    PORT
      LAYER M3 ;
        RECT  48.816 0 48.834 0.144 ;
    END
  END di[364]
  PIN di[365]
    DIRECTION INPUT ;
    USE SIGNAL ;
    PORT
      LAYER M5 ;
        RECT  48.912 0 48.936 0.192 ;
    END
  END di[365]
  PIN di[366]
    DIRECTION INPUT ;
    USE SIGNAL ;
    PORT
      LAYER M3 ;
        RECT  49.068 0 49.086 0.144 ;
    END
  END di[366]
  PIN di[367]
    DIRECTION INPUT ;
    USE SIGNAL ;
    PORT
      LAYER M5 ;
        RECT  49.152 0 49.176 0.192 ;
    END
  END di[367]
  PIN di[368]
    DIRECTION INPUT ;
    USE SIGNAL ;
    PORT
      LAYER M3 ;
        RECT  49.284 0 49.302 0.144 ;
    END
  END di[368]
  PIN di[369]
    DIRECTION INPUT ;
    USE SIGNAL ;
    PORT
      LAYER M5 ;
        RECT  49.44 0 49.464 0.192 ;
    END
  END di[369]
  PIN di[36]
    DIRECTION INPUT ;
    USE SIGNAL ;
    PORT
      LAYER M3 ;
        RECT  8.784 0 8.802 0.144 ;
    END
  END di[36]
  PIN di[370]
    DIRECTION INPUT ;
    USE SIGNAL ;
    PORT
      LAYER M3 ;
        RECT  49.536 0 49.554 0.144 ;
    END
  END di[370]
  PIN di[371]
    DIRECTION INPUT ;
    USE SIGNAL ;
    PORT
      LAYER M5 ;
        RECT  49.68 0 49.704 0.192 ;
    END
  END di[371]
  PIN di[372]
    DIRECTION INPUT ;
    USE SIGNAL ;
    PORT
      LAYER M3 ;
        RECT  49.788 0 49.806 0.144 ;
    END
  END di[372]
  PIN di[373]
    DIRECTION INPUT ;
    USE SIGNAL ;
    PORT
      LAYER M5 ;
        RECT  49.92 0 49.944 0.192 ;
    END
  END di[373]
  PIN di[374]
    DIRECTION INPUT ;
    USE SIGNAL ;
    PORT
      LAYER M3 ;
        RECT  50.04 0 50.058 0.144 ;
    END
  END di[374]
  PIN di[375]
    DIRECTION INPUT ;
    USE SIGNAL ;
    PORT
      LAYER M5 ;
        RECT  50.16 0 50.184 0.192 ;
    END
  END di[375]
  PIN di[376]
    DIRECTION INPUT ;
    USE SIGNAL ;
    PORT
      LAYER M3 ;
        RECT  50.292 0 50.31 0.144 ;
    END
  END di[376]
  PIN di[377]
    DIRECTION INPUT ;
    USE SIGNAL ;
    PORT
      LAYER M5 ;
        RECT  50.4 0 50.424 0.192 ;
    END
  END di[377]
  PIN di[378]
    DIRECTION INPUT ;
    USE SIGNAL ;
    PORT
      LAYER M3 ;
        RECT  50.508 0 50.526 0.144 ;
    END
  END di[378]
  PIN di[379]
    DIRECTION INPUT ;
    USE SIGNAL ;
    PORT
      LAYER M5 ;
        RECT  50.64 0 50.664 0.192 ;
    END
  END di[379]
  PIN di[37]
    DIRECTION INPUT ;
    USE SIGNAL ;
    PORT
      LAYER M5 ;
        RECT  8.88 0 8.904 0.192 ;
    END
  END di[37]
  PIN di[380]
    DIRECTION INPUT ;
    USE SIGNAL ;
    PORT
      LAYER M3 ;
        RECT  50.76 0 50.778 0.144 ;
    END
  END di[380]
  PIN di[381]
    DIRECTION INPUT ;
    USE SIGNAL ;
    PORT
      LAYER M5 ;
        RECT  50.88 0 50.904 0.192 ;
    END
  END di[381]
  PIN di[382]
    DIRECTION INPUT ;
    USE SIGNAL ;
    PORT
      LAYER M3 ;
        RECT  51.012 0 51.03 0.144 ;
    END
  END di[382]
  PIN di[383]
    DIRECTION INPUT ;
    USE SIGNAL ;
    PORT
      LAYER M5 ;
        RECT  51.12 0 51.144 0.192 ;
    END
  END di[383]
  PIN di[384]
    DIRECTION INPUT ;
    USE SIGNAL ;
    PORT
      LAYER M3 ;
        RECT  51.264 0 51.282 0.144 ;
    END
  END di[384]
  PIN di[385]
    DIRECTION INPUT ;
    USE SIGNAL ;
    PORT
      LAYER M5 ;
        RECT  51.36 0 51.384 0.192 ;
    END
  END di[385]
  PIN di[386]
    DIRECTION INPUT ;
    USE SIGNAL ;
    PORT
      LAYER M3 ;
        RECT  51.48 0 51.498 0.144 ;
    END
  END di[386]
  PIN di[387]
    DIRECTION INPUT ;
    USE SIGNAL ;
    PORT
      LAYER M5 ;
        RECT  51.6 0 51.624 0.192 ;
    END
  END di[387]
  PIN di[388]
    DIRECTION INPUT ;
    USE SIGNAL ;
    PORT
      LAYER M3 ;
        RECT  51.732 0 51.75 0.144 ;
    END
  END di[388]
  PIN di[389]
    DIRECTION INPUT ;
    USE SIGNAL ;
    PORT
      LAYER M5 ;
        RECT  51.84 0 51.864 0.192 ;
    END
  END di[389]
  PIN di[38]
    DIRECTION INPUT ;
    USE SIGNAL ;
    PORT
      LAYER M3 ;
        RECT  9 0 9.018 0.144 ;
    END
  END di[38]
  PIN di[390]
    DIRECTION INPUT ;
    USE SIGNAL ;
    PORT
      LAYER M3 ;
        RECT  51.984 0 52.002 0.144 ;
    END
  END di[390]
  PIN di[391]
    DIRECTION INPUT ;
    USE SIGNAL ;
    PORT
      LAYER M5 ;
        RECT  52.128 0 52.152 0.192 ;
    END
  END di[391]
  PIN di[392]
    DIRECTION INPUT ;
    USE SIGNAL ;
    PORT
      LAYER M3 ;
        RECT  52.236 0 52.254 0.144 ;
    END
  END di[392]
  PIN di[393]
    DIRECTION INPUT ;
    USE SIGNAL ;
    PORT
      LAYER M5 ;
        RECT  52.368 0 52.392 0.192 ;
    END
  END di[393]
  PIN di[394]
    DIRECTION INPUT ;
    USE SIGNAL ;
    PORT
      LAYER M3 ;
        RECT  52.488 0 52.506 0.144 ;
    END
  END di[394]
  PIN di[395]
    DIRECTION INPUT ;
    USE SIGNAL ;
    PORT
      LAYER M5 ;
        RECT  52.608 0 52.632 0.192 ;
    END
  END di[395]
  PIN di[396]
    DIRECTION INPUT ;
    USE SIGNAL ;
    PORT
      LAYER M3 ;
        RECT  52.704 0 52.722 0.144 ;
    END
  END di[396]
  PIN di[397]
    DIRECTION INPUT ;
    USE SIGNAL ;
    PORT
      LAYER M5 ;
        RECT  52.848 0 52.872 0.192 ;
    END
  END di[397]
  PIN di[398]
    DIRECTION INPUT ;
    USE SIGNAL ;
    PORT
      LAYER M3 ;
        RECT  52.956 0 52.974 0.144 ;
    END
  END di[398]
  PIN di[399]
    DIRECTION INPUT ;
    USE SIGNAL ;
    PORT
      LAYER M5 ;
        RECT  53.088 0 53.112 0.192 ;
    END
  END di[399]
  PIN di[39]
    DIRECTION INPUT ;
    USE SIGNAL ;
    PORT
      LAYER M5 ;
        RECT  9.12 0 9.144 0.192 ;
    END
  END di[39]
  PIN di[3]
    DIRECTION INPUT ;
    USE SIGNAL ;
    PORT
      LAYER M5 ;
        RECT  4.752 0 4.776 0.192 ;
    END
  END di[3]
  PIN di[400]
    DIRECTION INPUT ;
    USE SIGNAL ;
    PORT
      LAYER M3 ;
        RECT  53.208 0 53.226 0.144 ;
    END
  END di[400]
  PIN di[401]
    DIRECTION INPUT ;
    USE SIGNAL ;
    PORT
      LAYER M5 ;
        RECT  53.328 0 53.352 0.192 ;
    END
  END di[401]
  PIN di[402]
    DIRECTION INPUT ;
    USE SIGNAL ;
    PORT
      LAYER M3 ;
        RECT  53.46 0 53.478 0.144 ;
    END
  END di[402]
  PIN di[403]
    DIRECTION INPUT ;
    USE SIGNAL ;
    PORT
      LAYER M5 ;
        RECT  53.568 0 53.592 0.192 ;
    END
  END di[403]
  PIN di[404]
    DIRECTION INPUT ;
    USE SIGNAL ;
    PORT
      LAYER M3 ;
        RECT  53.712 0 53.73 0.144 ;
    END
  END di[404]
  PIN di[405]
    DIRECTION INPUT ;
    USE SIGNAL ;
    PORT
      LAYER M5 ;
        RECT  53.808 0 53.832 0.192 ;
    END
  END di[405]
  PIN di[406]
    DIRECTION INPUT ;
    USE SIGNAL ;
    PORT
      LAYER M3 ;
        RECT  53.928 0 53.946 0.144 ;
    END
  END di[406]
  PIN di[407]
    DIRECTION INPUT ;
    USE SIGNAL ;
    PORT
      LAYER M5 ;
        RECT  54.048 0 54.072 0.192 ;
    END
  END di[407]
  PIN di[408]
    DIRECTION INPUT ;
    USE SIGNAL ;
    PORT
      LAYER M3 ;
        RECT  54.18 0 54.198 0.144 ;
    END
  END di[408]
  PIN di[409]
    DIRECTION INPUT ;
    USE SIGNAL ;
    PORT
      LAYER M5 ;
        RECT  54.288 0 54.312 0.192 ;
    END
  END di[409]
  PIN di[40]
    DIRECTION INPUT ;
    USE SIGNAL ;
    PORT
      LAYER M3 ;
        RECT  9.252 0 9.27 0.144 ;
    END
  END di[40]
  PIN di[410]
    DIRECTION INPUT ;
    USE SIGNAL ;
    PORT
      LAYER M3 ;
        RECT  54.432 0 54.45 0.144 ;
    END
  END di[410]
  PIN di[411]
    DIRECTION INPUT ;
    USE SIGNAL ;
    PORT
      LAYER M5 ;
        RECT  54.528 0 54.552 0.192 ;
    END
  END di[411]
  PIN di[412]
    DIRECTION INPUT ;
    USE SIGNAL ;
    PORT
      LAYER M3 ;
        RECT  54.684 0 54.702 0.144 ;
    END
  END di[412]
  PIN di[413]
    DIRECTION INPUT ;
    USE SIGNAL ;
    PORT
      LAYER M5 ;
        RECT  54.768 0 54.792 0.192 ;
    END
  END di[413]
  PIN di[414]
    DIRECTION INPUT ;
    USE SIGNAL ;
    PORT
      LAYER M3 ;
        RECT  54.9 0 54.918 0.144 ;
    END
  END di[414]
  PIN di[415]
    DIRECTION INPUT ;
    USE SIGNAL ;
    PORT
      LAYER M5 ;
        RECT  55.056 0 55.08 0.192 ;
    END
  END di[415]
  PIN di[416]
    DIRECTION INPUT ;
    USE SIGNAL ;
    PORT
      LAYER M3 ;
        RECT  55.152 0 55.17 0.144 ;
    END
  END di[416]
  PIN di[417]
    DIRECTION INPUT ;
    USE SIGNAL ;
    PORT
      LAYER M5 ;
        RECT  55.296 0 55.32 0.192 ;
    END
  END di[417]
  PIN di[418]
    DIRECTION INPUT ;
    USE SIGNAL ;
    PORT
      LAYER M3 ;
        RECT  55.404 0 55.422 0.144 ;
    END
  END di[418]
  PIN di[419]
    DIRECTION INPUT ;
    USE SIGNAL ;
    PORT
      LAYER M5 ;
        RECT  55.536 0 55.56 0.192 ;
    END
  END di[419]
  PIN di[41]
    DIRECTION INPUT ;
    USE SIGNAL ;
    PORT
      LAYER M5 ;
        RECT  9.36 0 9.384 0.192 ;
    END
  END di[41]
  PIN di[420]
    DIRECTION INPUT ;
    USE SIGNAL ;
    PORT
      LAYER M3 ;
        RECT  55.656 0 55.674 0.144 ;
    END
  END di[420]
  PIN di[421]
    DIRECTION INPUT ;
    USE SIGNAL ;
    PORT
      LAYER M5 ;
        RECT  55.776 0 55.8 0.192 ;
    END
  END di[421]
  PIN di[422]
    DIRECTION INPUT ;
    USE SIGNAL ;
    PORT
      LAYER M3 ;
        RECT  55.908 0 55.926 0.144 ;
    END
  END di[422]
  PIN di[423]
    DIRECTION INPUT ;
    USE SIGNAL ;
    PORT
      LAYER M5 ;
        RECT  56.016 0 56.04 0.192 ;
    END
  END di[423]
  PIN di[424]
    DIRECTION INPUT ;
    USE SIGNAL ;
    PORT
      LAYER M3 ;
        RECT  56.124 0 56.142 0.144 ;
    END
  END di[424]
  PIN di[425]
    DIRECTION INPUT ;
    USE SIGNAL ;
    PORT
      LAYER M5 ;
        RECT  56.256 0 56.28 0.192 ;
    END
  END di[425]
  PIN di[426]
    DIRECTION INPUT ;
    USE SIGNAL ;
    PORT
      LAYER M3 ;
        RECT  56.376 0 56.394 0.144 ;
    END
  END di[426]
  PIN di[427]
    DIRECTION INPUT ;
    USE SIGNAL ;
    PORT
      LAYER M5 ;
        RECT  56.496 0 56.52 0.192 ;
    END
  END di[427]
  PIN di[428]
    DIRECTION INPUT ;
    USE SIGNAL ;
    PORT
      LAYER M3 ;
        RECT  56.628 0 56.646 0.144 ;
    END
  END di[428]
  PIN di[429]
    DIRECTION INPUT ;
    USE SIGNAL ;
    PORT
      LAYER M5 ;
        RECT  56.736 0 56.76 0.192 ;
    END
  END di[429]
  PIN di[42]
    DIRECTION INPUT ;
    USE SIGNAL ;
    PORT
      LAYER M3 ;
        RECT  9.504 0 9.522 0.144 ;
    END
  END di[42]
  PIN di[430]
    DIRECTION INPUT ;
    USE SIGNAL ;
    PORT
      LAYER M3 ;
        RECT  56.88 0 56.898 0.144 ;
    END
  END di[430]
  PIN di[431]
    DIRECTION INPUT ;
    USE SIGNAL ;
    PORT
      LAYER M5 ;
        RECT  56.976 0 57 0.192 ;
    END
  END di[431]
  PIN di[432]
    DIRECTION INPUT ;
    USE SIGNAL ;
    PORT
      LAYER M3 ;
        RECT  57.096 0 57.114 0.144 ;
    END
  END di[432]
  PIN di[433]
    DIRECTION INPUT ;
    USE SIGNAL ;
    PORT
      LAYER M5 ;
        RECT  57.216 0 57.24 0.192 ;
    END
  END di[433]
  PIN di[434]
    DIRECTION INPUT ;
    USE SIGNAL ;
    PORT
      LAYER M3 ;
        RECT  57.348 0 57.366 0.144 ;
    END
  END di[434]
  PIN di[435]
    DIRECTION INPUT ;
    USE SIGNAL ;
    PORT
      LAYER M5 ;
        RECT  57.456 0 57.48 0.192 ;
    END
  END di[435]
  PIN di[436]
    DIRECTION INPUT ;
    USE SIGNAL ;
    PORT
      LAYER M3 ;
        RECT  57.6 0 57.618 0.144 ;
    END
  END di[436]
  PIN di[437]
    DIRECTION INPUT ;
    USE SIGNAL ;
    PORT
      LAYER M5 ;
        RECT  57.744 0 57.768 0.192 ;
    END
  END di[437]
  PIN di[438]
    DIRECTION INPUT ;
    USE SIGNAL ;
    PORT
      LAYER M3 ;
        RECT  57.852 0 57.87 0.144 ;
    END
  END di[438]
  PIN di[439]
    DIRECTION INPUT ;
    USE SIGNAL ;
    PORT
      LAYER M5 ;
        RECT  57.984 0 58.008 0.192 ;
    END
  END di[439]
  PIN di[43]
    DIRECTION INPUT ;
    USE SIGNAL ;
    PORT
      LAYER M5 ;
        RECT  9.6 0 9.624 0.192 ;
    END
  END di[43]
  PIN di[440]
    DIRECTION INPUT ;
    USE SIGNAL ;
    PORT
      LAYER M3 ;
        RECT  58.104 0 58.122 0.144 ;
    END
  END di[440]
  PIN di[441]
    DIRECTION INPUT ;
    USE SIGNAL ;
    PORT
      LAYER M5 ;
        RECT  58.224 0 58.248 0.192 ;
    END
  END di[441]
  PIN di[442]
    DIRECTION INPUT ;
    USE SIGNAL ;
    PORT
      LAYER M3 ;
        RECT  58.32 0 58.338 0.144 ;
    END
  END di[442]
  PIN di[443]
    DIRECTION INPUT ;
    USE SIGNAL ;
    PORT
      LAYER M5 ;
        RECT  58.464 0 58.488 0.192 ;
    END
  END di[443]
  PIN di[444]
    DIRECTION INPUT ;
    USE SIGNAL ;
    PORT
      LAYER M3 ;
        RECT  58.572 0 58.59 0.144 ;
    END
  END di[444]
  PIN di[445]
    DIRECTION INPUT ;
    USE SIGNAL ;
    PORT
      LAYER M5 ;
        RECT  58.704 0 58.728 0.192 ;
    END
  END di[445]
  PIN di[446]
    DIRECTION INPUT ;
    USE SIGNAL ;
    PORT
      LAYER M3 ;
        RECT  58.824 0 58.842 0.144 ;
    END
  END di[446]
  PIN di[447]
    DIRECTION INPUT ;
    USE SIGNAL ;
    PORT
      LAYER M5 ;
        RECT  58.944 0 58.968 0.192 ;
    END
  END di[447]
  PIN di[448]
    DIRECTION INPUT ;
    USE SIGNAL ;
    PORT
      LAYER M3 ;
        RECT  59.076 0 59.094 0.144 ;
    END
  END di[448]
  PIN di[449]
    DIRECTION INPUT ;
    USE SIGNAL ;
    PORT
      LAYER M5 ;
        RECT  59.184 0 59.208 0.192 ;
    END
  END di[449]
  PIN di[44]
    DIRECTION INPUT ;
    USE SIGNAL ;
    PORT
      LAYER M3 ;
        RECT  9.756 0 9.774 0.144 ;
    END
  END di[44]
  PIN di[450]
    DIRECTION INPUT ;
    USE SIGNAL ;
    PORT
      LAYER M3 ;
        RECT  59.328 0 59.346 0.144 ;
    END
  END di[450]
  PIN di[451]
    DIRECTION INPUT ;
    USE SIGNAL ;
    PORT
      LAYER M5 ;
        RECT  59.424 0 59.448 0.192 ;
    END
  END di[451]
  PIN di[452]
    DIRECTION INPUT ;
    USE SIGNAL ;
    PORT
      LAYER M3 ;
        RECT  59.544 0 59.562 0.144 ;
    END
  END di[452]
  PIN di[453]
    DIRECTION INPUT ;
    USE SIGNAL ;
    PORT
      LAYER M5 ;
        RECT  59.664 0 59.688 0.192 ;
    END
  END di[453]
  PIN di[454]
    DIRECTION INPUT ;
    USE SIGNAL ;
    PORT
      LAYER M3 ;
        RECT  59.796 0 59.814 0.144 ;
    END
  END di[454]
  PIN di[455]
    DIRECTION INPUT ;
    USE SIGNAL ;
    PORT
      LAYER M5 ;
        RECT  59.904 0 59.928 0.192 ;
    END
  END di[455]
  PIN di[456]
    DIRECTION INPUT ;
    USE SIGNAL ;
    PORT
      LAYER M3 ;
        RECT  60.048 0 60.066 0.144 ;
    END
  END di[456]
  PIN di[457]
    DIRECTION INPUT ;
    USE SIGNAL ;
    PORT
      LAYER M5 ;
        RECT  60.144 0 60.168 0.192 ;
    END
  END di[457]
  PIN di[458]
    DIRECTION INPUT ;
    USE SIGNAL ;
    PORT
      LAYER M3 ;
        RECT  60.3 0 60.318 0.144 ;
    END
  END di[458]
  PIN di[459]
    DIRECTION INPUT ;
    USE SIGNAL ;
    PORT
      LAYER M5 ;
        RECT  60.384 0 60.408 0.192 ;
    END
  END di[459]
  PIN di[45]
    DIRECTION INPUT ;
    USE SIGNAL ;
    PORT
      LAYER M5 ;
        RECT  9.84 0 9.864 0.192 ;
    END
  END di[45]
  PIN di[460]
    DIRECTION INPUT ;
    USE SIGNAL ;
    PORT
      LAYER M3 ;
        RECT  60.516 0 60.534 0.144 ;
    END
  END di[460]
  PIN di[461]
    DIRECTION INPUT ;
    USE SIGNAL ;
    PORT
      LAYER M5 ;
        RECT  60.672 0 60.696 0.192 ;
    END
  END di[461]
  PIN di[462]
    DIRECTION INPUT ;
    USE SIGNAL ;
    PORT
      LAYER M3 ;
        RECT  60.768 0 60.786 0.144 ;
    END
  END di[462]
  PIN di[463]
    DIRECTION INPUT ;
    USE SIGNAL ;
    PORT
      LAYER M5 ;
        RECT  60.912 0 60.936 0.192 ;
    END
  END di[463]
  PIN di[464]
    DIRECTION INPUT ;
    USE SIGNAL ;
    PORT
      LAYER M3 ;
        RECT  61.02 0 61.038 0.144 ;
    END
  END di[464]
  PIN di[465]
    DIRECTION INPUT ;
    USE SIGNAL ;
    PORT
      LAYER M5 ;
        RECT  61.152 0 61.176 0.192 ;
    END
  END di[465]
  PIN di[466]
    DIRECTION INPUT ;
    USE SIGNAL ;
    PORT
      LAYER M3 ;
        RECT  61.272 0 61.29 0.144 ;
    END
  END di[466]
  PIN di[467]
    DIRECTION INPUT ;
    USE SIGNAL ;
    PORT
      LAYER M5 ;
        RECT  61.392 0 61.416 0.192 ;
    END
  END di[467]
  PIN di[468]
    DIRECTION INPUT ;
    USE SIGNAL ;
    PORT
      LAYER M3 ;
        RECT  61.524 0 61.542 0.144 ;
    END
  END di[468]
  PIN di[469]
    DIRECTION INPUT ;
    USE SIGNAL ;
    PORT
      LAYER M5 ;
        RECT  61.632 0 61.656 0.192 ;
    END
  END di[469]
  PIN di[46]
    DIRECTION INPUT ;
    USE SIGNAL ;
    PORT
      LAYER M3 ;
        RECT  9.972 0 9.99 0.144 ;
    END
  END di[46]
  PIN di[470]
    DIRECTION INPUT ;
    USE SIGNAL ;
    PORT
      LAYER M3 ;
        RECT  61.74 0 61.758 0.144 ;
    END
  END di[470]
  PIN di[471]
    DIRECTION INPUT ;
    USE SIGNAL ;
    PORT
      LAYER M5 ;
        RECT  61.872 0 61.896 0.192 ;
    END
  END di[471]
  PIN di[472]
    DIRECTION INPUT ;
    USE SIGNAL ;
    PORT
      LAYER M3 ;
        RECT  61.992 0 62.01 0.144 ;
    END
  END di[472]
  PIN di[473]
    DIRECTION INPUT ;
    USE SIGNAL ;
    PORT
      LAYER M5 ;
        RECT  62.112 0 62.136 0.192 ;
    END
  END di[473]
  PIN di[474]
    DIRECTION INPUT ;
    USE SIGNAL ;
    PORT
      LAYER M3 ;
        RECT  62.244 0 62.262 0.144 ;
    END
  END di[474]
  PIN di[475]
    DIRECTION INPUT ;
    USE SIGNAL ;
    PORT
      LAYER M5 ;
        RECT  62.352 0 62.376 0.192 ;
    END
  END di[475]
  PIN di[476]
    DIRECTION INPUT ;
    USE SIGNAL ;
    PORT
      LAYER M3 ;
        RECT  62.496 0 62.514 0.144 ;
    END
  END di[476]
  PIN di[477]
    DIRECTION INPUT ;
    USE SIGNAL ;
    PORT
      LAYER M5 ;
        RECT  62.592 0 62.616 0.192 ;
    END
  END di[477]
  PIN di[478]
    DIRECTION INPUT ;
    USE SIGNAL ;
    PORT
      LAYER M3 ;
        RECT  62.712 0 62.73 0.144 ;
    END
  END di[478]
  PIN di[479]
    DIRECTION INPUT ;
    USE SIGNAL ;
    PORT
      LAYER M5 ;
        RECT  62.832 0 62.856 0.192 ;
    END
  END di[479]
  PIN di[47]
    DIRECTION INPUT ;
    USE SIGNAL ;
    PORT
      LAYER M5 ;
        RECT  10.128 0 10.152 0.192 ;
    END
  END di[47]
  PIN di[480]
    DIRECTION INPUT ;
    USE SIGNAL ;
    PORT
      LAYER M3 ;
        RECT  62.964 0 62.982 0.144 ;
    END
  END di[480]
  PIN di[481]
    DIRECTION INPUT ;
    USE SIGNAL ;
    PORT
      LAYER M5 ;
        RECT  63.072 0 63.096 0.192 ;
    END
  END di[481]
  PIN di[482]
    DIRECTION INPUT ;
    USE SIGNAL ;
    PORT
      LAYER M3 ;
        RECT  63.216 0 63.234 0.144 ;
    END
  END di[482]
  PIN di[483]
    DIRECTION INPUT ;
    USE SIGNAL ;
    PORT
      LAYER M5 ;
        RECT  63.36 0 63.384 0.192 ;
    END
  END di[483]
  PIN di[484]
    DIRECTION INPUT ;
    USE SIGNAL ;
    PORT
      LAYER M3 ;
        RECT  63.468 0 63.486 0.144 ;
    END
  END di[484]
  PIN di[485]
    DIRECTION INPUT ;
    USE SIGNAL ;
    PORT
      LAYER M5 ;
        RECT  63.6 0 63.624 0.192 ;
    END
  END di[485]
  PIN di[486]
    DIRECTION INPUT ;
    USE SIGNAL ;
    PORT
      LAYER M3 ;
        RECT  63.72 0 63.738 0.144 ;
    END
  END di[486]
  PIN di[487]
    DIRECTION INPUT ;
    USE SIGNAL ;
    PORT
      LAYER M5 ;
        RECT  63.84 0 63.864 0.192 ;
    END
  END di[487]
  PIN di[488]
    DIRECTION INPUT ;
    USE SIGNAL ;
    PORT
      LAYER M3 ;
        RECT  63.936 0 63.954 0.144 ;
    END
  END di[488]
  PIN di[489]
    DIRECTION INPUT ;
    USE SIGNAL ;
    PORT
      LAYER M5 ;
        RECT  64.08 0 64.104 0.192 ;
    END
  END di[489]
  PIN di[48]
    DIRECTION INPUT ;
    USE SIGNAL ;
    PORT
      LAYER M3 ;
        RECT  10.224 0 10.242 0.144 ;
    END
  END di[48]
  PIN di[490]
    DIRECTION INPUT ;
    USE SIGNAL ;
    PORT
      LAYER M3 ;
        RECT  64.188 0 64.206 0.144 ;
    END
  END di[490]
  PIN di[491]
    DIRECTION INPUT ;
    USE SIGNAL ;
    PORT
      LAYER M5 ;
        RECT  64.32 0 64.344 0.192 ;
    END
  END di[491]
  PIN di[492]
    DIRECTION INPUT ;
    USE SIGNAL ;
    PORT
      LAYER M3 ;
        RECT  64.44 0 64.458 0.144 ;
    END
  END di[492]
  PIN di[493]
    DIRECTION INPUT ;
    USE SIGNAL ;
    PORT
      LAYER M5 ;
        RECT  64.56 0 64.584 0.192 ;
    END
  END di[493]
  PIN di[494]
    DIRECTION INPUT ;
    USE SIGNAL ;
    PORT
      LAYER M3 ;
        RECT  64.692 0 64.71 0.144 ;
    END
  END di[494]
  PIN di[495]
    DIRECTION INPUT ;
    USE SIGNAL ;
    PORT
      LAYER M5 ;
        RECT  64.8 0 64.824 0.192 ;
    END
  END di[495]
  PIN di[496]
    DIRECTION INPUT ;
    USE SIGNAL ;
    PORT
      LAYER M3 ;
        RECT  64.944 0 64.962 0.144 ;
    END
  END di[496]
  PIN di[497]
    DIRECTION INPUT ;
    USE SIGNAL ;
    PORT
      LAYER M5 ;
        RECT  65.04 0 65.064 0.192 ;
    END
  END di[497]
  PIN di[498]
    DIRECTION INPUT ;
    USE SIGNAL ;
    PORT
      LAYER M3 ;
        RECT  65.16 0 65.178 0.144 ;
    END
  END di[498]
  PIN di[499]
    DIRECTION INPUT ;
    USE SIGNAL ;
    PORT
      LAYER M5 ;
        RECT  65.28 0 65.304 0.192 ;
    END
  END di[499]
  PIN di[49]
    DIRECTION INPUT ;
    USE SIGNAL ;
    PORT
      LAYER M5 ;
        RECT  10.368 0 10.392 0.192 ;
    END
  END di[49]
  PIN di[4]
    DIRECTION INPUT ;
    USE SIGNAL ;
    PORT
      LAYER M3 ;
        RECT  4.86 0 4.878 0.144 ;
    END
  END di[4]
  PIN di[500]
    DIRECTION INPUT ;
    USE SIGNAL ;
    PORT
      LAYER M3 ;
        RECT  65.412 0 65.43 0.144 ;
    END
  END di[500]
  PIN di[501]
    DIRECTION INPUT ;
    USE SIGNAL ;
    PORT
      LAYER M5 ;
        RECT  65.52 0 65.544 0.192 ;
    END
  END di[501]
  PIN di[502]
    DIRECTION INPUT ;
    USE SIGNAL ;
    PORT
      LAYER M3 ;
        RECT  65.664 0 65.682 0.144 ;
    END
  END di[502]
  PIN di[503]
    DIRECTION INPUT ;
    USE SIGNAL ;
    PORT
      LAYER M5 ;
        RECT  65.76 0 65.784 0.192 ;
    END
  END di[503]
  PIN di[504]
    DIRECTION INPUT ;
    USE SIGNAL ;
    PORT
      LAYER M3 ;
        RECT  65.916 0 65.934 0.144 ;
    END
  END di[504]
  PIN di[505]
    DIRECTION INPUT ;
    USE SIGNAL ;
    PORT
      LAYER M5 ;
        RECT  66 0 66.024 0.192 ;
    END
  END di[505]
  PIN di[506]
    DIRECTION INPUT ;
    USE SIGNAL ;
    PORT
      LAYER M3 ;
        RECT  66.132 0 66.15 0.144 ;
    END
  END di[506]
  PIN di[507]
    DIRECTION INPUT ;
    USE SIGNAL ;
    PORT
      LAYER M5 ;
        RECT  66.288 0 66.312 0.192 ;
    END
  END di[507]
  PIN di[508]
    DIRECTION INPUT ;
    USE SIGNAL ;
    PORT
      LAYER M3 ;
        RECT  66.384 0 66.402 0.144 ;
    END
  END di[508]
  PIN di[509]
    DIRECTION INPUT ;
    USE SIGNAL ;
    PORT
      LAYER M5 ;
        RECT  66.528 0 66.552 0.192 ;
    END
  END di[509]
  PIN di[50]
    DIRECTION INPUT ;
    USE SIGNAL ;
    PORT
      LAYER M3 ;
        RECT  10.476 0 10.494 0.144 ;
    END
  END di[50]
  PIN di[510]
    DIRECTION INPUT ;
    USE SIGNAL ;
    PORT
      LAYER M3 ;
        RECT  66.636 0 66.654 0.144 ;
    END
  END di[510]
  PIN di[511]
    DIRECTION INPUT ;
    USE SIGNAL ;
    PORT
      LAYER M5 ;
        RECT  66.768 0 66.792 0.192 ;
    END
  END di[511]
  PIN di[512]
    DIRECTION INPUT ;
    USE SIGNAL ;
    PORT
      LAYER M3 ;
        RECT  66.888 0 66.906 0.144 ;
    END
  END di[512]
  PIN di[513]
    DIRECTION INPUT ;
    USE SIGNAL ;
    PORT
      LAYER M5 ;
        RECT  67.008 0 67.032 0.192 ;
    END
  END di[513]
  PIN di[514]
    DIRECTION INPUT ;
    USE SIGNAL ;
    PORT
      LAYER M3 ;
        RECT  67.14 0 67.158 0.144 ;
    END
  END di[514]
  PIN di[515]
    DIRECTION INPUT ;
    USE SIGNAL ;
    PORT
      LAYER M5 ;
        RECT  67.248 0 67.272 0.192 ;
    END
  END di[515]
  PIN di[516]
    DIRECTION INPUT ;
    USE SIGNAL ;
    PORT
      LAYER M3 ;
        RECT  67.356 0 67.374 0.144 ;
    END
  END di[516]
  PIN di[517]
    DIRECTION INPUT ;
    USE SIGNAL ;
    PORT
      LAYER M5 ;
        RECT  67.488 0 67.512 0.192 ;
    END
  END di[517]
  PIN di[518]
    DIRECTION INPUT ;
    USE SIGNAL ;
    PORT
      LAYER M3 ;
        RECT  67.608 0 67.626 0.144 ;
    END
  END di[518]
  PIN di[519]
    DIRECTION INPUT ;
    USE SIGNAL ;
    PORT
      LAYER M5 ;
        RECT  67.728 0 67.752 0.192 ;
    END
  END di[519]
  PIN di[51]
    DIRECTION INPUT ;
    USE SIGNAL ;
    PORT
      LAYER M5 ;
        RECT  10.608 0 10.632 0.192 ;
    END
  END di[51]
  PIN di[520]
    DIRECTION INPUT ;
    USE SIGNAL ;
    PORT
      LAYER M3 ;
        RECT  67.86 0 67.878 0.144 ;
    END
  END di[520]
  PIN di[521]
    DIRECTION INPUT ;
    USE SIGNAL ;
    PORT
      LAYER M5 ;
        RECT  67.968 0 67.992 0.192 ;
    END
  END di[521]
  PIN di[522]
    DIRECTION INPUT ;
    USE SIGNAL ;
    PORT
      LAYER M3 ;
        RECT  68.112 0 68.13 0.144 ;
    END
  END di[522]
  PIN di[523]
    DIRECTION INPUT ;
    USE SIGNAL ;
    PORT
      LAYER M5 ;
        RECT  68.208 0 68.232 0.192 ;
    END
  END di[523]
  PIN di[524]
    DIRECTION INPUT ;
    USE SIGNAL ;
    PORT
      LAYER M3 ;
        RECT  68.328 0 68.346 0.144 ;
    END
  END di[524]
  PIN di[525]
    DIRECTION INPUT ;
    USE SIGNAL ;
    PORT
      LAYER M5 ;
        RECT  68.448 0 68.472 0.192 ;
    END
  END di[525]
  PIN di[526]
    DIRECTION INPUT ;
    USE SIGNAL ;
    PORT
      LAYER M3 ;
        RECT  68.58 0 68.598 0.144 ;
    END
  END di[526]
  PIN di[527]
    DIRECTION INPUT ;
    USE SIGNAL ;
    PORT
      LAYER M5 ;
        RECT  68.688 0 68.712 0.192 ;
    END
  END di[527]
  PIN di[528]
    DIRECTION INPUT ;
    USE SIGNAL ;
    PORT
      LAYER M3 ;
        RECT  68.832 0 68.85 0.144 ;
    END
  END di[528]
  PIN di[529]
    DIRECTION INPUT ;
    USE SIGNAL ;
    PORT
      LAYER M5 ;
        RECT  68.976 0 69 0.192 ;
    END
  END di[529]
  PIN di[52]
    DIRECTION INPUT ;
    USE SIGNAL ;
    PORT
      LAYER M3 ;
        RECT  10.728 0 10.746 0.144 ;
    END
  END di[52]
  PIN di[530]
    DIRECTION INPUT ;
    USE SIGNAL ;
    PORT
      LAYER M3 ;
        RECT  69.084 0 69.102 0.144 ;
    END
  END di[530]
  PIN di[531]
    DIRECTION INPUT ;
    USE SIGNAL ;
    PORT
      LAYER M5 ;
        RECT  69.216 0 69.24 0.192 ;
    END
  END di[531]
  PIN di[532]
    DIRECTION INPUT ;
    USE SIGNAL ;
    PORT
      LAYER M3 ;
        RECT  69.336 0 69.354 0.144 ;
    END
  END di[532]
  PIN di[533]
    DIRECTION INPUT ;
    USE SIGNAL ;
    PORT
      LAYER M5 ;
        RECT  69.456 0 69.48 0.192 ;
    END
  END di[533]
  PIN di[534]
    DIRECTION INPUT ;
    USE SIGNAL ;
    PORT
      LAYER M3 ;
        RECT  69.552 0 69.57 0.144 ;
    END
  END di[534]
  PIN di[535]
    DIRECTION INPUT ;
    USE SIGNAL ;
    PORT
      LAYER M5 ;
        RECT  69.696 0 69.72 0.192 ;
    END
  END di[535]
  PIN di[536]
    DIRECTION INPUT ;
    USE SIGNAL ;
    PORT
      LAYER M3 ;
        RECT  69.804 0 69.822 0.144 ;
    END
  END di[536]
  PIN di[537]
    DIRECTION INPUT ;
    USE SIGNAL ;
    PORT
      LAYER M5 ;
        RECT  69.936 0 69.96 0.192 ;
    END
  END di[537]
  PIN di[538]
    DIRECTION INPUT ;
    USE SIGNAL ;
    PORT
      LAYER M3 ;
        RECT  70.056 0 70.074 0.144 ;
    END
  END di[538]
  PIN di[539]
    DIRECTION INPUT ;
    USE SIGNAL ;
    PORT
      LAYER M5 ;
        RECT  70.176 0 70.2 0.192 ;
    END
  END di[539]
  PIN di[53]
    DIRECTION INPUT ;
    USE SIGNAL ;
    PORT
      LAYER M5 ;
        RECT  10.848 0 10.872 0.192 ;
    END
  END di[53]
  PIN di[540]
    DIRECTION INPUT ;
    USE SIGNAL ;
    PORT
      LAYER M3 ;
        RECT  70.308 0 70.326 0.144 ;
    END
  END di[540]
  PIN di[541]
    DIRECTION INPUT ;
    USE SIGNAL ;
    PORT
      LAYER M5 ;
        RECT  70.416 0 70.44 0.192 ;
    END
  END di[541]
  PIN di[542]
    DIRECTION INPUT ;
    USE SIGNAL ;
    PORT
      LAYER M3 ;
        RECT  70.56 0 70.578 0.144 ;
    END
  END di[542]
  PIN di[543]
    DIRECTION INPUT ;
    USE SIGNAL ;
    PORT
      LAYER M5 ;
        RECT  70.656 0 70.68 0.192 ;
    END
  END di[543]
  PIN di[544]
    DIRECTION INPUT ;
    USE SIGNAL ;
    PORT
      LAYER M3 ;
        RECT  70.776 0 70.794 0.144 ;
    END
  END di[544]
  PIN di[545]
    DIRECTION INPUT ;
    USE SIGNAL ;
    PORT
      LAYER M5 ;
        RECT  70.896 0 70.92 0.192 ;
    END
  END di[545]
  PIN di[546]
    DIRECTION INPUT ;
    USE SIGNAL ;
    PORT
      LAYER M3 ;
        RECT  71.028 0 71.046 0.144 ;
    END
  END di[546]
  PIN di[547]
    DIRECTION INPUT ;
    USE SIGNAL ;
    PORT
      LAYER M5 ;
        RECT  71.136 0 71.16 0.192 ;
    END
  END di[547]
  PIN di[548]
    DIRECTION INPUT ;
    USE SIGNAL ;
    PORT
      LAYER M3 ;
        RECT  71.28 0 71.298 0.144 ;
    END
  END di[548]
  PIN di[549]
    DIRECTION INPUT ;
    USE SIGNAL ;
    PORT
      LAYER M5 ;
        RECT  71.376 0 71.4 0.192 ;
    END
  END di[549]
  PIN di[54]
    DIRECTION INPUT ;
    USE SIGNAL ;
    PORT
      LAYER M3 ;
        RECT  10.98 0 10.998 0.144 ;
    END
  END di[54]
  PIN di[550]
    DIRECTION INPUT ;
    USE SIGNAL ;
    PORT
      LAYER M3 ;
        RECT  71.532 0 71.55 0.144 ;
    END
  END di[550]
  PIN di[551]
    DIRECTION INPUT ;
    USE SIGNAL ;
    PORT
      LAYER M5 ;
        RECT  71.616 0 71.64 0.192 ;
    END
  END di[551]
  PIN di[552]
    DIRECTION INPUT ;
    USE SIGNAL ;
    PORT
      LAYER M3 ;
        RECT  71.748 0 71.766 0.144 ;
    END
  END di[552]
  PIN di[553]
    DIRECTION INPUT ;
    USE SIGNAL ;
    PORT
      LAYER M5 ;
        RECT  71.904 0 71.928 0.192 ;
    END
  END di[553]
  PIN di[554]
    DIRECTION INPUT ;
    USE SIGNAL ;
    PORT
      LAYER M3 ;
        RECT  72 0 72.018 0.144 ;
    END
  END di[554]
  PIN di[555]
    DIRECTION INPUT ;
    USE SIGNAL ;
    PORT
      LAYER M5 ;
        RECT  72.144 0 72.168 0.192 ;
    END
  END di[555]
  PIN di[556]
    DIRECTION INPUT ;
    USE SIGNAL ;
    PORT
      LAYER M3 ;
        RECT  72.252 0 72.27 0.144 ;
    END
  END di[556]
  PIN di[557]
    DIRECTION INPUT ;
    USE SIGNAL ;
    PORT
      LAYER M5 ;
        RECT  72.384 0 72.408 0.192 ;
    END
  END di[557]
  PIN di[558]
    DIRECTION INPUT ;
    USE SIGNAL ;
    PORT
      LAYER M3 ;
        RECT  72.504 0 72.522 0.144 ;
    END
  END di[558]
  PIN di[559]
    DIRECTION INPUT ;
    USE SIGNAL ;
    PORT
      LAYER M5 ;
        RECT  72.624 0 72.648 0.192 ;
    END
  END di[559]
  PIN di[55]
    DIRECTION INPUT ;
    USE SIGNAL ;
    PORT
      LAYER M5 ;
        RECT  11.088 0 11.112 0.192 ;
    END
  END di[55]
  PIN di[560]
    DIRECTION INPUT ;
    USE SIGNAL ;
    PORT
      LAYER M3 ;
        RECT  72.756 0 72.774 0.144 ;
    END
  END di[560]
  PIN di[561]
    DIRECTION INPUT ;
    USE SIGNAL ;
    PORT
      LAYER M5 ;
        RECT  72.864 0 72.888 0.192 ;
    END
  END di[561]
  PIN di[562]
    DIRECTION INPUT ;
    USE SIGNAL ;
    PORT
      LAYER M3 ;
        RECT  72.972 0 72.99 0.144 ;
    END
  END di[562]
  PIN di[563]
    DIRECTION INPUT ;
    USE SIGNAL ;
    PORT
      LAYER M5 ;
        RECT  73.104 0 73.128 0.192 ;
    END
  END di[563]
  PIN di[564]
    DIRECTION INPUT ;
    USE SIGNAL ;
    PORT
      LAYER M3 ;
        RECT  73.224 0 73.242 0.144 ;
    END
  END di[564]
  PIN di[565]
    DIRECTION INPUT ;
    USE SIGNAL ;
    PORT
      LAYER M5 ;
        RECT  73.344 0 73.368 0.192 ;
    END
  END di[565]
  PIN di[566]
    DIRECTION INPUT ;
    USE SIGNAL ;
    PORT
      LAYER M3 ;
        RECT  73.476 0 73.494 0.144 ;
    END
  END di[566]
  PIN di[567]
    DIRECTION INPUT ;
    USE SIGNAL ;
    PORT
      LAYER M5 ;
        RECT  73.584 0 73.608 0.192 ;
    END
  END di[567]
  PIN di[568]
    DIRECTION INPUT ;
    USE SIGNAL ;
    PORT
      LAYER M3 ;
        RECT  73.728 0 73.746 0.144 ;
    END
  END di[568]
  PIN di[569]
    DIRECTION INPUT ;
    USE SIGNAL ;
    PORT
      LAYER M5 ;
        RECT  73.824 0 73.848 0.192 ;
    END
  END di[569]
  PIN di[56]
    DIRECTION INPUT ;
    USE SIGNAL ;
    PORT
      LAYER M3 ;
        RECT  11.196 0 11.214 0.144 ;
    END
  END di[56]
  PIN di[570]
    DIRECTION INPUT ;
    USE SIGNAL ;
    PORT
      LAYER M3 ;
        RECT  73.944 0 73.962 0.144 ;
    END
  END di[570]
  PIN di[571]
    DIRECTION INPUT ;
    USE SIGNAL ;
    PORT
      LAYER M5 ;
        RECT  74.064 0 74.088 0.192 ;
    END
  END di[571]
  PIN di[572]
    DIRECTION INPUT ;
    USE SIGNAL ;
    PORT
      LAYER M3 ;
        RECT  74.196 0 74.214 0.144 ;
    END
  END di[572]
  PIN di[573]
    DIRECTION INPUT ;
    USE SIGNAL ;
    PORT
      LAYER M5 ;
        RECT  74.304 0 74.328 0.192 ;
    END
  END di[573]
  PIN di[574]
    DIRECTION INPUT ;
    USE SIGNAL ;
    PORT
      LAYER M3 ;
        RECT  74.448 0 74.466 0.144 ;
    END
  END di[574]
  PIN di[575]
    DIRECTION INPUT ;
    USE SIGNAL ;
    PORT
      LAYER M5 ;
        RECT  74.592 0 74.616 0.192 ;
    END
  END di[575]
  PIN di[576]
    DIRECTION INPUT ;
    USE SIGNAL ;
    PORT
      LAYER M3 ;
        RECT  74.7 0 74.718 0.144 ;
    END
  END di[576]
  PIN di[577]
    DIRECTION INPUT ;
    USE SIGNAL ;
    PORT
      LAYER M5 ;
        RECT  74.832 0 74.856 0.192 ;
    END
  END di[577]
  PIN di[578]
    DIRECTION INPUT ;
    USE SIGNAL ;
    PORT
      LAYER M3 ;
        RECT  74.952 0 74.97 0.144 ;
    END
  END di[578]
  PIN di[579]
    DIRECTION INPUT ;
    USE SIGNAL ;
    PORT
      LAYER M5 ;
        RECT  75.072 0 75.096 0.192 ;
    END
  END di[579]
  PIN di[57]
    DIRECTION INPUT ;
    USE SIGNAL ;
    PORT
      LAYER M5 ;
        RECT  11.328 0 11.352 0.192 ;
    END
  END di[57]
  PIN di[580]
    DIRECTION INPUT ;
    USE SIGNAL ;
    PORT
      LAYER M3 ;
        RECT  75.168 0 75.186 0.144 ;
    END
  END di[580]
  PIN di[581]
    DIRECTION INPUT ;
    USE SIGNAL ;
    PORT
      LAYER M5 ;
        RECT  75.312 0 75.336 0.192 ;
    END
  END di[581]
  PIN di[582]
    DIRECTION INPUT ;
    USE SIGNAL ;
    PORT
      LAYER M3 ;
        RECT  75.42 0 75.438 0.144 ;
    END
  END di[582]
  PIN di[583]
    DIRECTION INPUT ;
    USE SIGNAL ;
    PORT
      LAYER M5 ;
        RECT  75.552 0 75.576 0.192 ;
    END
  END di[583]
  PIN di[584]
    DIRECTION INPUT ;
    USE SIGNAL ;
    PORT
      LAYER M3 ;
        RECT  75.672 0 75.69 0.144 ;
    END
  END di[584]
  PIN di[585]
    DIRECTION INPUT ;
    USE SIGNAL ;
    PORT
      LAYER M5 ;
        RECT  75.792 0 75.816 0.192 ;
    END
  END di[585]
  PIN di[586]
    DIRECTION INPUT ;
    USE SIGNAL ;
    PORT
      LAYER M3 ;
        RECT  75.924 0 75.942 0.144 ;
    END
  END di[586]
  PIN di[587]
    DIRECTION INPUT ;
    USE SIGNAL ;
    PORT
      LAYER M5 ;
        RECT  76.032 0 76.056 0.192 ;
    END
  END di[587]
  PIN di[588]
    DIRECTION INPUT ;
    USE SIGNAL ;
    PORT
      LAYER M3 ;
        RECT  76.176 0 76.194 0.144 ;
    END
  END di[588]
  PIN di[589]
    DIRECTION INPUT ;
    USE SIGNAL ;
    PORT
      LAYER M5 ;
        RECT  76.272 0 76.296 0.192 ;
    END
  END di[589]
  PIN di[58]
    DIRECTION INPUT ;
    USE SIGNAL ;
    PORT
      LAYER M3 ;
        RECT  11.448 0 11.466 0.144 ;
    END
  END di[58]
  PIN di[590]
    DIRECTION INPUT ;
    USE SIGNAL ;
    PORT
      LAYER M3 ;
        RECT  76.392 0 76.41 0.144 ;
    END
  END di[590]
  PIN di[591]
    DIRECTION INPUT ;
    USE SIGNAL ;
    PORT
      LAYER M5 ;
        RECT  76.512 0 76.536 0.192 ;
    END
  END di[591]
  PIN di[592]
    DIRECTION INPUT ;
    USE SIGNAL ;
    PORT
      LAYER M3 ;
        RECT  76.644 0 76.662 0.144 ;
    END
  END di[592]
  PIN di[593]
    DIRECTION INPUT ;
    USE SIGNAL ;
    PORT
      LAYER M5 ;
        RECT  76.752 0 76.776 0.192 ;
    END
  END di[593]
  PIN di[594]
    DIRECTION INPUT ;
    USE SIGNAL ;
    PORT
      LAYER M3 ;
        RECT  76.896 0 76.914 0.144 ;
    END
  END di[594]
  PIN di[595]
    DIRECTION INPUT ;
    USE SIGNAL ;
    PORT
      LAYER M5 ;
        RECT  76.992 0 77.016 0.192 ;
    END
  END di[595]
  PIN di[596]
    DIRECTION INPUT ;
    USE SIGNAL ;
    PORT
      LAYER M3 ;
        RECT  77.148 0 77.166 0.144 ;
    END
  END di[596]
  PIN di[597]
    DIRECTION INPUT ;
    USE SIGNAL ;
    PORT
      LAYER M5 ;
        RECT  77.232 0 77.256 0.192 ;
    END
  END di[597]
  PIN di[598]
    DIRECTION INPUT ;
    USE SIGNAL ;
    PORT
      LAYER M3 ;
        RECT  77.364 0 77.382 0.144 ;
    END
  END di[598]
  PIN di[599]
    DIRECTION INPUT ;
    USE SIGNAL ;
    PORT
      LAYER M5 ;
        RECT  77.52 0 77.544 0.192 ;
    END
  END di[599]
  PIN di[59]
    DIRECTION INPUT ;
    USE SIGNAL ;
    PORT
      LAYER M5 ;
        RECT  11.568 0 11.592 0.192 ;
    END
  END di[59]
  PIN di[5]
    DIRECTION INPUT ;
    USE SIGNAL ;
    PORT
      LAYER M5 ;
        RECT  4.992 0 5.016 0.192 ;
    END
  END di[5]
  PIN di[600]
    DIRECTION INPUT ;
    USE SIGNAL ;
    PORT
      LAYER M3 ;
        RECT  77.616 0 77.634 0.144 ;
    END
  END di[600]
  PIN di[601]
    DIRECTION INPUT ;
    USE SIGNAL ;
    PORT
      LAYER M5 ;
        RECT  77.76 0 77.784 0.192 ;
    END
  END di[601]
  PIN di[602]
    DIRECTION INPUT ;
    USE SIGNAL ;
    PORT
      LAYER M3 ;
        RECT  77.868 0 77.886 0.144 ;
    END
  END di[602]
  PIN di[603]
    DIRECTION INPUT ;
    USE SIGNAL ;
    PORT
      LAYER M5 ;
        RECT  78 0 78.024 0.192 ;
    END
  END di[603]
  PIN di[604]
    DIRECTION INPUT ;
    USE SIGNAL ;
    PORT
      LAYER M3 ;
        RECT  78.12 0 78.138 0.144 ;
    END
  END di[604]
  PIN di[605]
    DIRECTION INPUT ;
    USE SIGNAL ;
    PORT
      LAYER M5 ;
        RECT  78.24 0 78.264 0.192 ;
    END
  END di[605]
  PIN di[606]
    DIRECTION INPUT ;
    USE SIGNAL ;
    PORT
      LAYER M3 ;
        RECT  78.372 0 78.39 0.144 ;
    END
  END di[606]
  PIN di[607]
    DIRECTION INPUT ;
    USE SIGNAL ;
    PORT
      LAYER M5 ;
        RECT  78.48 0 78.504 0.192 ;
    END
  END di[607]
  PIN di[608]
    DIRECTION INPUT ;
    USE SIGNAL ;
    PORT
      LAYER M3 ;
        RECT  78.588 0 78.606 0.144 ;
    END
  END di[608]
  PIN di[609]
    DIRECTION INPUT ;
    USE SIGNAL ;
    PORT
      LAYER M5 ;
        RECT  78.72 0 78.744 0.192 ;
    END
  END di[609]
  PIN di[60]
    DIRECTION INPUT ;
    USE SIGNAL ;
    PORT
      LAYER M3 ;
        RECT  11.7 0 11.718 0.144 ;
    END
  END di[60]
  PIN di[610]
    DIRECTION INPUT ;
    USE SIGNAL ;
    PORT
      LAYER M3 ;
        RECT  78.84 0 78.858 0.144 ;
    END
  END di[610]
  PIN di[611]
    DIRECTION INPUT ;
    USE SIGNAL ;
    PORT
      LAYER M5 ;
        RECT  78.96 0 78.984 0.192 ;
    END
  END di[611]
  PIN di[612]
    DIRECTION INPUT ;
    USE SIGNAL ;
    PORT
      LAYER M3 ;
        RECT  79.092 0 79.11 0.144 ;
    END
  END di[612]
  PIN di[613]
    DIRECTION INPUT ;
    USE SIGNAL ;
    PORT
      LAYER M5 ;
        RECT  79.2 0 79.224 0.192 ;
    END
  END di[613]
  PIN di[614]
    DIRECTION INPUT ;
    USE SIGNAL ;
    PORT
      LAYER M3 ;
        RECT  79.344 0 79.362 0.144 ;
    END
  END di[614]
  PIN di[615]
    DIRECTION INPUT ;
    USE SIGNAL ;
    PORT
      LAYER M5 ;
        RECT  79.44 0 79.464 0.192 ;
    END
  END di[615]
  PIN di[616]
    DIRECTION INPUT ;
    USE SIGNAL ;
    PORT
      LAYER M3 ;
        RECT  79.56 0 79.578 0.144 ;
    END
  END di[616]
  PIN di[617]
    DIRECTION INPUT ;
    USE SIGNAL ;
    PORT
      LAYER M5 ;
        RECT  79.68 0 79.704 0.192 ;
    END
  END di[617]
  PIN di[618]
    DIRECTION INPUT ;
    USE SIGNAL ;
    PORT
      LAYER M3 ;
        RECT  79.812 0 79.83 0.144 ;
    END
  END di[618]
  PIN di[619]
    DIRECTION INPUT ;
    USE SIGNAL ;
    PORT
      LAYER M5 ;
        RECT  79.92 0 79.944 0.192 ;
    END
  END di[619]
  PIN di[61]
    DIRECTION INPUT ;
    USE SIGNAL ;
    PORT
      LAYER M5 ;
        RECT  11.808 0 11.832 0.192 ;
    END
  END di[61]
  PIN di[620]
    DIRECTION INPUT ;
    USE SIGNAL ;
    PORT
      LAYER M3 ;
        RECT  80.064 0 80.082 0.144 ;
    END
  END di[620]
  PIN di[621]
    DIRECTION INPUT ;
    USE SIGNAL ;
    PORT
      LAYER M5 ;
        RECT  80.208 0 80.232 0.192 ;
    END
  END di[621]
  PIN di[622]
    DIRECTION INPUT ;
    USE SIGNAL ;
    PORT
      LAYER M3 ;
        RECT  80.316 0 80.334 0.144 ;
    END
  END di[622]
  PIN di[623]
    DIRECTION INPUT ;
    USE SIGNAL ;
    PORT
      LAYER M5 ;
        RECT  80.448 0 80.472 0.192 ;
    END
  END di[623]
  PIN di[624]
    DIRECTION INPUT ;
    USE SIGNAL ;
    PORT
      LAYER M3 ;
        RECT  80.568 0 80.586 0.144 ;
    END
  END di[624]
  PIN di[625]
    DIRECTION INPUT ;
    USE SIGNAL ;
    PORT
      LAYER M5 ;
        RECT  80.688 0 80.712 0.192 ;
    END
  END di[625]
  PIN di[626]
    DIRECTION INPUT ;
    USE SIGNAL ;
    PORT
      LAYER M3 ;
        RECT  80.784 0 80.802 0.144 ;
    END
  END di[626]
  PIN di[627]
    DIRECTION INPUT ;
    USE SIGNAL ;
    PORT
      LAYER M5 ;
        RECT  80.928 0 80.952 0.192 ;
    END
  END di[627]
  PIN di[628]
    DIRECTION INPUT ;
    USE SIGNAL ;
    PORT
      LAYER M3 ;
        RECT  81.036 0 81.054 0.144 ;
    END
  END di[628]
  PIN di[629]
    DIRECTION INPUT ;
    USE SIGNAL ;
    PORT
      LAYER M5 ;
        RECT  81.168 0 81.192 0.192 ;
    END
  END di[629]
  PIN di[62]
    DIRECTION INPUT ;
    USE SIGNAL ;
    PORT
      LAYER M3 ;
        RECT  11.952 0 11.97 0.144 ;
    END
  END di[62]
  PIN di[630]
    DIRECTION INPUT ;
    USE SIGNAL ;
    PORT
      LAYER M3 ;
        RECT  81.288 0 81.306 0.144 ;
    END
  END di[630]
  PIN di[631]
    DIRECTION INPUT ;
    USE SIGNAL ;
    PORT
      LAYER M5 ;
        RECT  81.408 0 81.432 0.192 ;
    END
  END di[631]
  PIN di[632]
    DIRECTION INPUT ;
    USE SIGNAL ;
    PORT
      LAYER M3 ;
        RECT  81.54 0 81.558 0.144 ;
    END
  END di[632]
  PIN di[633]
    DIRECTION INPUT ;
    USE SIGNAL ;
    PORT
      LAYER M5 ;
        RECT  81.648 0 81.672 0.192 ;
    END
  END di[633]
  PIN di[634]
    DIRECTION INPUT ;
    USE SIGNAL ;
    PORT
      LAYER M3 ;
        RECT  81.792 0 81.81 0.144 ;
    END
  END di[634]
  PIN di[635]
    DIRECTION INPUT ;
    USE SIGNAL ;
    PORT
      LAYER M5 ;
        RECT  81.888 0 81.912 0.192 ;
    END
  END di[635]
  PIN di[636]
    DIRECTION INPUT ;
    USE SIGNAL ;
    PORT
      LAYER M3 ;
        RECT  82.008 0 82.026 0.144 ;
    END
  END di[636]
  PIN di[637]
    DIRECTION INPUT ;
    USE SIGNAL ;
    PORT
      LAYER M5 ;
        RECT  82.128 0 82.152 0.192 ;
    END
  END di[637]
  PIN di[638]
    DIRECTION INPUT ;
    USE SIGNAL ;
    PORT
      LAYER M3 ;
        RECT  82.26 0 82.278 0.144 ;
    END
  END di[638]
  PIN di[639]
    DIRECTION INPUT ;
    USE SIGNAL ;
    PORT
      LAYER M5 ;
        RECT  82.368 0 82.392 0.192 ;
    END
  END di[639]
  PIN di[63]
    DIRECTION INPUT ;
    USE SIGNAL ;
    PORT
      LAYER M5 ;
        RECT  12.048 0 12.072 0.192 ;
    END
  END di[63]
  PIN di[640]
    DIRECTION INPUT ;
    USE SIGNAL ;
    PORT
      LAYER M3 ;
        RECT  82.512 0 82.53 0.144 ;
    END
  END di[640]
  PIN di[641]
    DIRECTION INPUT ;
    USE SIGNAL ;
    PORT
      LAYER M5 ;
        RECT  82.608 0 82.632 0.192 ;
    END
  END di[641]
  PIN di[642]
    DIRECTION INPUT ;
    USE SIGNAL ;
    PORT
      LAYER M3 ;
        RECT  82.764 0 82.782 0.144 ;
    END
  END di[642]
  PIN di[643]
    DIRECTION INPUT ;
    USE SIGNAL ;
    PORT
      LAYER M5 ;
        RECT  82.848 0 82.872 0.192 ;
    END
  END di[643]
  PIN di[644]
    DIRECTION INPUT ;
    USE SIGNAL ;
    PORT
      LAYER M3 ;
        RECT  82.98 0 82.998 0.144 ;
    END
  END di[644]
  PIN di[645]
    DIRECTION INPUT ;
    USE SIGNAL ;
    PORT
      LAYER M5 ;
        RECT  83.136 0 83.16 0.192 ;
    END
  END di[645]
  PIN di[646]
    DIRECTION INPUT ;
    USE SIGNAL ;
    PORT
      LAYER M3 ;
        RECT  83.232 0 83.25 0.144 ;
    END
  END di[646]
  PIN di[647]
    DIRECTION INPUT ;
    USE SIGNAL ;
    PORT
      LAYER M5 ;
        RECT  83.376 0 83.4 0.192 ;
    END
  END di[647]
  PIN di[648]
    DIRECTION INPUT ;
    USE SIGNAL ;
    PORT
      LAYER M3 ;
        RECT  83.484 0 83.502 0.144 ;
    END
  END di[648]
  PIN di[649]
    DIRECTION INPUT ;
    USE SIGNAL ;
    PORT
      LAYER M5 ;
        RECT  83.616 0 83.64 0.192 ;
    END
  END di[649]
  PIN di[64]
    DIRECTION INPUT ;
    USE SIGNAL ;
    PORT
      LAYER M3 ;
        RECT  12.168 0 12.186 0.144 ;
    END
  END di[64]
  PIN di[650]
    DIRECTION INPUT ;
    USE SIGNAL ;
    PORT
      LAYER M3 ;
        RECT  83.736 0 83.754 0.144 ;
    END
  END di[650]
  PIN di[651]
    DIRECTION INPUT ;
    USE SIGNAL ;
    PORT
      LAYER M5 ;
        RECT  83.856 0 83.88 0.192 ;
    END
  END di[651]
  PIN di[652]
    DIRECTION INPUT ;
    USE SIGNAL ;
    PORT
      LAYER M3 ;
        RECT  83.988 0 84.006 0.144 ;
    END
  END di[652]
  PIN di[653]
    DIRECTION INPUT ;
    USE SIGNAL ;
    PORT
      LAYER M5 ;
        RECT  84.096 0 84.12 0.192 ;
    END
  END di[653]
  PIN di[654]
    DIRECTION INPUT ;
    USE SIGNAL ;
    PORT
      LAYER M3 ;
        RECT  84.204 0 84.222 0.144 ;
    END
  END di[654]
  PIN di[655]
    DIRECTION INPUT ;
    USE SIGNAL ;
    PORT
      LAYER M5 ;
        RECT  84.336 0 84.36 0.192 ;
    END
  END di[655]
  PIN di[656]
    DIRECTION INPUT ;
    USE SIGNAL ;
    PORT
      LAYER M3 ;
        RECT  84.456 0 84.474 0.144 ;
    END
  END di[656]
  PIN di[657]
    DIRECTION INPUT ;
    USE SIGNAL ;
    PORT
      LAYER M5 ;
        RECT  84.576 0 84.6 0.192 ;
    END
  END di[657]
  PIN di[658]
    DIRECTION INPUT ;
    USE SIGNAL ;
    PORT
      LAYER M3 ;
        RECT  84.708 0 84.726 0.144 ;
    END
  END di[658]
  PIN di[659]
    DIRECTION INPUT ;
    USE SIGNAL ;
    PORT
      LAYER M5 ;
        RECT  84.816 0 84.84 0.192 ;
    END
  END di[659]
  PIN di[65]
    DIRECTION INPUT ;
    USE SIGNAL ;
    PORT
      LAYER M5 ;
        RECT  12.288 0 12.312 0.192 ;
    END
  END di[65]
  PIN di[660]
    DIRECTION INPUT ;
    USE SIGNAL ;
    PORT
      LAYER M3 ;
        RECT  84.96 0 84.978 0.144 ;
    END
  END di[660]
  PIN di[661]
    DIRECTION INPUT ;
    USE SIGNAL ;
    PORT
      LAYER M5 ;
        RECT  85.056 0 85.08 0.192 ;
    END
  END di[661]
  PIN di[662]
    DIRECTION INPUT ;
    USE SIGNAL ;
    PORT
      LAYER M3 ;
        RECT  85.176 0 85.194 0.144 ;
    END
  END di[662]
  PIN di[663]
    DIRECTION INPUT ;
    USE SIGNAL ;
    PORT
      LAYER M5 ;
        RECT  85.296 0 85.32 0.192 ;
    END
  END di[663]
  PIN di[664]
    DIRECTION INPUT ;
    USE SIGNAL ;
    PORT
      LAYER M3 ;
        RECT  85.428 0 85.446 0.144 ;
    END
  END di[664]
  PIN di[665]
    DIRECTION INPUT ;
    USE SIGNAL ;
    PORT
      LAYER M5 ;
        RECT  85.536 0 85.56 0.192 ;
    END
  END di[665]
  PIN di[666]
    DIRECTION INPUT ;
    USE SIGNAL ;
    PORT
      LAYER M3 ;
        RECT  85.68 0 85.698 0.144 ;
    END
  END di[666]
  PIN di[667]
    DIRECTION INPUT ;
    USE SIGNAL ;
    PORT
      LAYER M5 ;
        RECT  85.824 0 85.848 0.192 ;
    END
  END di[667]
  PIN di[668]
    DIRECTION INPUT ;
    USE SIGNAL ;
    PORT
      LAYER M3 ;
        RECT  85.932 0 85.95 0.144 ;
    END
  END di[668]
  PIN di[669]
    DIRECTION INPUT ;
    USE SIGNAL ;
    PORT
      LAYER M5 ;
        RECT  86.064 0 86.088 0.192 ;
    END
  END di[669]
  PIN di[66]
    DIRECTION INPUT ;
    USE SIGNAL ;
    PORT
      LAYER M3 ;
        RECT  12.42 0 12.438 0.144 ;
    END
  END di[66]
  PIN di[670]
    DIRECTION INPUT ;
    USE SIGNAL ;
    PORT
      LAYER M3 ;
        RECT  86.184 0 86.202 0.144 ;
    END
  END di[670]
  PIN di[671]
    DIRECTION INPUT ;
    USE SIGNAL ;
    PORT
      LAYER M5 ;
        RECT  86.304 0 86.328 0.192 ;
    END
  END di[671]
  PIN di[672]
    DIRECTION INPUT ;
    USE SIGNAL ;
    PORT
      LAYER M3 ;
        RECT  86.4 0 86.418 0.144 ;
    END
  END di[672]
  PIN di[673]
    DIRECTION INPUT ;
    USE SIGNAL ;
    PORT
      LAYER M5 ;
        RECT  86.544 0 86.568 0.192 ;
    END
  END di[673]
  PIN di[674]
    DIRECTION INPUT ;
    USE SIGNAL ;
    PORT
      LAYER M3 ;
        RECT  86.652 0 86.67 0.144 ;
    END
  END di[674]
  PIN di[675]
    DIRECTION INPUT ;
    USE SIGNAL ;
    PORT
      LAYER M5 ;
        RECT  86.784 0 86.808 0.192 ;
    END
  END di[675]
  PIN di[676]
    DIRECTION INPUT ;
    USE SIGNAL ;
    PORT
      LAYER M3 ;
        RECT  86.904 0 86.922 0.144 ;
    END
  END di[676]
  PIN di[677]
    DIRECTION INPUT ;
    USE SIGNAL ;
    PORT
      LAYER M5 ;
        RECT  87.024 0 87.048 0.192 ;
    END
  END di[677]
  PIN di[678]
    DIRECTION INPUT ;
    USE SIGNAL ;
    PORT
      LAYER M3 ;
        RECT  87.156 0 87.174 0.144 ;
    END
  END di[678]
  PIN di[679]
    DIRECTION INPUT ;
    USE SIGNAL ;
    PORT
      LAYER M5 ;
        RECT  87.264 0 87.288 0.192 ;
    END
  END di[679]
  PIN di[67]
    DIRECTION INPUT ;
    USE SIGNAL ;
    PORT
      LAYER M5 ;
        RECT  12.528 0 12.552 0.192 ;
    END
  END di[67]
  PIN di[680]
    DIRECTION INPUT ;
    USE SIGNAL ;
    PORT
      LAYER M3 ;
        RECT  87.408 0 87.426 0.144 ;
    END
  END di[680]
  PIN di[681]
    DIRECTION INPUT ;
    USE SIGNAL ;
    PORT
      LAYER M5 ;
        RECT  87.504 0 87.528 0.192 ;
    END
  END di[681]
  PIN di[682]
    DIRECTION INPUT ;
    USE SIGNAL ;
    PORT
      LAYER M3 ;
        RECT  87.624 0 87.642 0.144 ;
    END
  END di[682]
  PIN di[683]
    DIRECTION INPUT ;
    USE SIGNAL ;
    PORT
      LAYER M5 ;
        RECT  87.744 0 87.768 0.192 ;
    END
  END di[683]
  PIN di[684]
    DIRECTION INPUT ;
    USE SIGNAL ;
    PORT
      LAYER M3 ;
        RECT  87.876 0 87.894 0.144 ;
    END
  END di[684]
  PIN di[685]
    DIRECTION INPUT ;
    USE SIGNAL ;
    PORT
      LAYER M5 ;
        RECT  87.984 0 88.008 0.192 ;
    END
  END di[685]
  PIN di[686]
    DIRECTION INPUT ;
    USE SIGNAL ;
    PORT
      LAYER M3 ;
        RECT  88.128 0 88.146 0.144 ;
    END
  END di[686]
  PIN di[687]
    DIRECTION INPUT ;
    USE SIGNAL ;
    PORT
      LAYER M5 ;
        RECT  88.224 0 88.248 0.192 ;
    END
  END di[687]
  PIN di[688]
    DIRECTION INPUT ;
    USE SIGNAL ;
    PORT
      LAYER M3 ;
        RECT  88.38 0 88.398 0.144 ;
    END
  END di[688]
  PIN di[689]
    DIRECTION INPUT ;
    USE SIGNAL ;
    PORT
      LAYER M5 ;
        RECT  88.464 0 88.488 0.192 ;
    END
  END di[689]
  PIN di[68]
    DIRECTION INPUT ;
    USE SIGNAL ;
    PORT
      LAYER M3 ;
        RECT  12.672 0 12.69 0.144 ;
    END
  END di[68]
  PIN di[69]
    DIRECTION INPUT ;
    USE SIGNAL ;
    PORT
      LAYER M5 ;
        RECT  12.816 0 12.84 0.192 ;
    END
  END di[69]
  PIN di[6]
    DIRECTION INPUT ;
    USE SIGNAL ;
    PORT
      LAYER M3 ;
        RECT  5.112 0 5.13 0.144 ;
    END
  END di[6]
  PIN di[70]
    DIRECTION INPUT ;
    USE SIGNAL ;
    PORT
      LAYER M3 ;
        RECT  12.924 0 12.942 0.144 ;
    END
  END di[70]
  PIN di[71]
    DIRECTION INPUT ;
    USE SIGNAL ;
    PORT
      LAYER M5 ;
        RECT  13.056 0 13.08 0.192 ;
    END
  END di[71]
  PIN di[72]
    DIRECTION INPUT ;
    USE SIGNAL ;
    PORT
      LAYER M3 ;
        RECT  13.176 0 13.194 0.144 ;
    END
  END di[72]
  PIN di[73]
    DIRECTION INPUT ;
    USE SIGNAL ;
    PORT
      LAYER M5 ;
        RECT  13.296 0 13.32 0.192 ;
    END
  END di[73]
  PIN di[74]
    DIRECTION INPUT ;
    USE SIGNAL ;
    PORT
      LAYER M3 ;
        RECT  13.392 0 13.41 0.144 ;
    END
  END di[74]
  PIN di[75]
    DIRECTION INPUT ;
    USE SIGNAL ;
    PORT
      LAYER M5 ;
        RECT  13.536 0 13.56 0.192 ;
    END
  END di[75]
  PIN di[76]
    DIRECTION INPUT ;
    USE SIGNAL ;
    PORT
      LAYER M3 ;
        RECT  13.644 0 13.662 0.144 ;
    END
  END di[76]
  PIN di[77]
    DIRECTION INPUT ;
    USE SIGNAL ;
    PORT
      LAYER M5 ;
        RECT  13.776 0 13.8 0.192 ;
    END
  END di[77]
  PIN di[78]
    DIRECTION INPUT ;
    USE SIGNAL ;
    PORT
      LAYER M3 ;
        RECT  13.896 0 13.914 0.144 ;
    END
  END di[78]
  PIN di[79]
    DIRECTION INPUT ;
    USE SIGNAL ;
    PORT
      LAYER M5 ;
        RECT  14.016 0 14.04 0.192 ;
    END
  END di[79]
  PIN di[7]
    DIRECTION INPUT ;
    USE SIGNAL ;
    PORT
      LAYER M5 ;
        RECT  5.232 0 5.256 0.192 ;
    END
  END di[7]
  PIN di[80]
    DIRECTION INPUT ;
    USE SIGNAL ;
    PORT
      LAYER M3 ;
        RECT  14.148 0 14.166 0.144 ;
    END
  END di[80]
  PIN di[81]
    DIRECTION INPUT ;
    USE SIGNAL ;
    PORT
      LAYER M5 ;
        RECT  14.256 0 14.28 0.192 ;
    END
  END di[81]
  PIN di[82]
    DIRECTION INPUT ;
    USE SIGNAL ;
    PORT
      LAYER M3 ;
        RECT  14.4 0 14.418 0.144 ;
    END
  END di[82]
  PIN di[83]
    DIRECTION INPUT ;
    USE SIGNAL ;
    PORT
      LAYER M5 ;
        RECT  14.496 0 14.52 0.192 ;
    END
  END di[83]
  PIN di[84]
    DIRECTION INPUT ;
    USE SIGNAL ;
    PORT
      LAYER M3 ;
        RECT  14.616 0 14.634 0.144 ;
    END
  END di[84]
  PIN di[85]
    DIRECTION INPUT ;
    USE SIGNAL ;
    PORT
      LAYER M5 ;
        RECT  14.736 0 14.76 0.192 ;
    END
  END di[85]
  PIN di[86]
    DIRECTION INPUT ;
    USE SIGNAL ;
    PORT
      LAYER M3 ;
        RECT  14.868 0 14.886 0.144 ;
    END
  END di[86]
  PIN di[87]
    DIRECTION INPUT ;
    USE SIGNAL ;
    PORT
      LAYER M5 ;
        RECT  14.976 0 15 0.192 ;
    END
  END di[87]
  PIN di[88]
    DIRECTION INPUT ;
    USE SIGNAL ;
    PORT
      LAYER M3 ;
        RECT  15.12 0 15.138 0.144 ;
    END
  END di[88]
  PIN di[89]
    DIRECTION INPUT ;
    USE SIGNAL ;
    PORT
      LAYER M5 ;
        RECT  15.216 0 15.24 0.192 ;
    END
  END di[89]
  PIN di[8]
    DIRECTION INPUT ;
    USE SIGNAL ;
    PORT
      LAYER M3 ;
        RECT  5.364 0 5.382 0.144 ;
    END
  END di[8]
  PIN di[90]
    DIRECTION INPUT ;
    USE SIGNAL ;
    PORT
      LAYER M3 ;
        RECT  15.372 0 15.39 0.144 ;
    END
  END di[90]
  PIN di[91]
    DIRECTION INPUT ;
    USE SIGNAL ;
    PORT
      LAYER M5 ;
        RECT  15.456 0 15.48 0.192 ;
    END
  END di[91]
  PIN di[92]
    DIRECTION INPUT ;
    USE SIGNAL ;
    PORT
      LAYER M3 ;
        RECT  15.588 0 15.606 0.144 ;
    END
  END di[92]
  PIN di[93]
    DIRECTION INPUT ;
    USE SIGNAL ;
    PORT
      LAYER M5 ;
        RECT  15.744 0 15.768 0.192 ;
    END
  END di[93]
  PIN di[94]
    DIRECTION INPUT ;
    USE SIGNAL ;
    PORT
      LAYER M3 ;
        RECT  15.84 0 15.858 0.144 ;
    END
  END di[94]
  PIN di[95]
    DIRECTION INPUT ;
    USE SIGNAL ;
    PORT
      LAYER M5 ;
        RECT  15.984 0 16.008 0.192 ;
    END
  END di[95]
  PIN di[96]
    DIRECTION INPUT ;
    USE SIGNAL ;
    PORT
      LAYER M3 ;
        RECT  16.092 0 16.11 0.144 ;
    END
  END di[96]
  PIN di[97]
    DIRECTION INPUT ;
    USE SIGNAL ;
    PORT
      LAYER M5 ;
        RECT  16.224 0 16.248 0.192 ;
    END
  END di[97]
  PIN di[98]
    DIRECTION INPUT ;
    USE SIGNAL ;
    PORT
      LAYER M3 ;
        RECT  16.344 0 16.362 0.144 ;
    END
  END di[98]
  PIN di[99]
    DIRECTION INPUT ;
    USE SIGNAL ;
    PORT
      LAYER M5 ;
        RECT  16.464 0 16.488 0.192 ;
    END
  END di[99]
  PIN di[9]
    DIRECTION INPUT ;
    USE SIGNAL ;
    PORT
      LAYER M5 ;
        RECT  5.472 0 5.496 0.192 ;
    END
  END di[9]
  PIN dq[0]
    DIRECTION OUTPUT ;
    USE SIGNAL ;
    PORT
      LAYER M3 ;
        RECT  4.356 36.576 4.374 36.72 ;
    END
  END dq[0]
  PIN dq[100]
    DIRECTION OUTPUT ;
    USE SIGNAL ;
    PORT
      LAYER M3 ;
        RECT  16.596 36.576 16.614 36.72 ;
    END
  END dq[100]
  PIN dq[101]
    DIRECTION OUTPUT ;
    USE SIGNAL ;
    PORT
      LAYER M5 ;
        RECT  16.704 36.528 16.728 36.72 ;
    END
  END dq[101]
  PIN dq[102]
    DIRECTION OUTPUT ;
    USE SIGNAL ;
    PORT
      LAYER M3 ;
        RECT  16.812 36.576 16.83 36.72 ;
    END
  END dq[102]
  PIN dq[103]
    DIRECTION OUTPUT ;
    USE SIGNAL ;
    PORT
      LAYER M5 ;
        RECT  16.944 36.528 16.968 36.72 ;
    END
  END dq[103]
  PIN dq[104]
    DIRECTION OUTPUT ;
    USE SIGNAL ;
    PORT
      LAYER M3 ;
        RECT  17.064 36.576 17.082 36.72 ;
    END
  END dq[104]
  PIN dq[105]
    DIRECTION OUTPUT ;
    USE SIGNAL ;
    PORT
      LAYER M5 ;
        RECT  17.184 36.528 17.208 36.72 ;
    END
  END dq[105]
  PIN dq[106]
    DIRECTION OUTPUT ;
    USE SIGNAL ;
    PORT
      LAYER M3 ;
        RECT  17.316 36.576 17.334 36.72 ;
    END
  END dq[106]
  PIN dq[107]
    DIRECTION OUTPUT ;
    USE SIGNAL ;
    PORT
      LAYER M5 ;
        RECT  17.424 36.528 17.448 36.72 ;
    END
  END dq[107]
  PIN dq[108]
    DIRECTION OUTPUT ;
    USE SIGNAL ;
    PORT
      LAYER M3 ;
        RECT  17.568 36.576 17.586 36.72 ;
    END
  END dq[108]
  PIN dq[109]
    DIRECTION OUTPUT ;
    USE SIGNAL ;
    PORT
      LAYER M5 ;
        RECT  17.664 36.528 17.688 36.72 ;
    END
  END dq[109]
  PIN dq[10]
    DIRECTION OUTPUT ;
    USE SIGNAL ;
    PORT
      LAYER M3 ;
        RECT  5.58 36.576 5.598 36.72 ;
    END
  END dq[10]
  PIN dq[110]
    DIRECTION OUTPUT ;
    USE SIGNAL ;
    PORT
      LAYER M3 ;
        RECT  17.784 36.576 17.802 36.72 ;
    END
  END dq[110]
  PIN dq[111]
    DIRECTION OUTPUT ;
    USE SIGNAL ;
    PORT
      LAYER M5 ;
        RECT  17.904 36.528 17.928 36.72 ;
    END
  END dq[111]
  PIN dq[112]
    DIRECTION OUTPUT ;
    USE SIGNAL ;
    PORT
      LAYER M3 ;
        RECT  18.036 36.576 18.054 36.72 ;
    END
  END dq[112]
  PIN dq[113]
    DIRECTION OUTPUT ;
    USE SIGNAL ;
    PORT
      LAYER M5 ;
        RECT  18.144 36.528 18.168 36.72 ;
    END
  END dq[113]
  PIN dq[114]
    DIRECTION OUTPUT ;
    USE SIGNAL ;
    PORT
      LAYER M3 ;
        RECT  18.288 36.576 18.306 36.72 ;
    END
  END dq[114]
  PIN dq[115]
    DIRECTION OUTPUT ;
    USE SIGNAL ;
    PORT
      LAYER M5 ;
        RECT  18.432 36.528 18.456 36.72 ;
    END
  END dq[115]
  PIN dq[116]
    DIRECTION OUTPUT ;
    USE SIGNAL ;
    PORT
      LAYER M3 ;
        RECT  18.54 36.576 18.558 36.72 ;
    END
  END dq[116]
  PIN dq[117]
    DIRECTION OUTPUT ;
    USE SIGNAL ;
    PORT
      LAYER M5 ;
        RECT  18.672 36.528 18.696 36.72 ;
    END
  END dq[117]
  PIN dq[118]
    DIRECTION OUTPUT ;
    USE SIGNAL ;
    PORT
      LAYER M3 ;
        RECT  18.792 36.576 18.81 36.72 ;
    END
  END dq[118]
  PIN dq[119]
    DIRECTION OUTPUT ;
    USE SIGNAL ;
    PORT
      LAYER M5 ;
        RECT  18.912 36.528 18.936 36.72 ;
    END
  END dq[119]
  PIN dq[11]
    DIRECTION OUTPUT ;
    USE SIGNAL ;
    PORT
      LAYER M5 ;
        RECT  5.712 36.528 5.736 36.72 ;
    END
  END dq[11]
  PIN dq[120]
    DIRECTION OUTPUT ;
    USE SIGNAL ;
    PORT
      LAYER M3 ;
        RECT  19.008 36.576 19.026 36.72 ;
    END
  END dq[120]
  PIN dq[121]
    DIRECTION OUTPUT ;
    USE SIGNAL ;
    PORT
      LAYER M5 ;
        RECT  19.152 36.528 19.176 36.72 ;
    END
  END dq[121]
  PIN dq[122]
    DIRECTION OUTPUT ;
    USE SIGNAL ;
    PORT
      LAYER M3 ;
        RECT  19.26 36.576 19.278 36.72 ;
    END
  END dq[122]
  PIN dq[123]
    DIRECTION OUTPUT ;
    USE SIGNAL ;
    PORT
      LAYER M5 ;
        RECT  19.392 36.528 19.416 36.72 ;
    END
  END dq[123]
  PIN dq[124]
    DIRECTION OUTPUT ;
    USE SIGNAL ;
    PORT
      LAYER M3 ;
        RECT  19.512 36.576 19.53 36.72 ;
    END
  END dq[124]
  PIN dq[125]
    DIRECTION OUTPUT ;
    USE SIGNAL ;
    PORT
      LAYER M5 ;
        RECT  19.632 36.528 19.656 36.72 ;
    END
  END dq[125]
  PIN dq[126]
    DIRECTION OUTPUT ;
    USE SIGNAL ;
    PORT
      LAYER M3 ;
        RECT  19.764 36.576 19.782 36.72 ;
    END
  END dq[126]
  PIN dq[127]
    DIRECTION OUTPUT ;
    USE SIGNAL ;
    PORT
      LAYER M5 ;
        RECT  19.872 36.528 19.896 36.72 ;
    END
  END dq[127]
  PIN dq[128]
    DIRECTION OUTPUT ;
    USE SIGNAL ;
    PORT
      LAYER M3 ;
        RECT  20.016 36.576 20.034 36.72 ;
    END
  END dq[128]
  PIN dq[129]
    DIRECTION OUTPUT ;
    USE SIGNAL ;
    PORT
      LAYER M5 ;
        RECT  20.112 36.528 20.136 36.72 ;
    END
  END dq[129]
  PIN dq[12]
    DIRECTION OUTPUT ;
    USE SIGNAL ;
    PORT
      LAYER M3 ;
        RECT  5.832 36.576 5.85 36.72 ;
    END
  END dq[12]
  PIN dq[130]
    DIRECTION OUTPUT ;
    USE SIGNAL ;
    PORT
      LAYER M3 ;
        RECT  20.232 36.576 20.25 36.72 ;
    END
  END dq[130]
  PIN dq[131]
    DIRECTION OUTPUT ;
    USE SIGNAL ;
    PORT
      LAYER M5 ;
        RECT  20.352 36.528 20.376 36.72 ;
    END
  END dq[131]
  PIN dq[132]
    DIRECTION OUTPUT ;
    USE SIGNAL ;
    PORT
      LAYER M3 ;
        RECT  20.484 36.576 20.502 36.72 ;
    END
  END dq[132]
  PIN dq[133]
    DIRECTION OUTPUT ;
    USE SIGNAL ;
    PORT
      LAYER M5 ;
        RECT  20.592 36.528 20.616 36.72 ;
    END
  END dq[133]
  PIN dq[134]
    DIRECTION OUTPUT ;
    USE SIGNAL ;
    PORT
      LAYER M3 ;
        RECT  20.736 36.576 20.754 36.72 ;
    END
  END dq[134]
  PIN dq[135]
    DIRECTION OUTPUT ;
    USE SIGNAL ;
    PORT
      LAYER M5 ;
        RECT  20.832 36.528 20.856 36.72 ;
    END
  END dq[135]
  PIN dq[136]
    DIRECTION OUTPUT ;
    USE SIGNAL ;
    PORT
      LAYER M3 ;
        RECT  20.988 36.576 21.006 36.72 ;
    END
  END dq[136]
  PIN dq[137]
    DIRECTION OUTPUT ;
    USE SIGNAL ;
    PORT
      LAYER M5 ;
        RECT  21.072 36.528 21.096 36.72 ;
    END
  END dq[137]
  PIN dq[138]
    DIRECTION OUTPUT ;
    USE SIGNAL ;
    PORT
      LAYER M3 ;
        RECT  21.204 36.576 21.222 36.72 ;
    END
  END dq[138]
  PIN dq[139]
    DIRECTION OUTPUT ;
    USE SIGNAL ;
    PORT
      LAYER M5 ;
        RECT  21.36 36.528 21.384 36.72 ;
    END
  END dq[139]
  PIN dq[13]
    DIRECTION OUTPUT ;
    USE SIGNAL ;
    PORT
      LAYER M5 ;
        RECT  5.952 36.528 5.976 36.72 ;
    END
  END dq[13]
  PIN dq[140]
    DIRECTION OUTPUT ;
    USE SIGNAL ;
    PORT
      LAYER M3 ;
        RECT  21.456 36.576 21.474 36.72 ;
    END
  END dq[140]
  PIN dq[141]
    DIRECTION OUTPUT ;
    USE SIGNAL ;
    PORT
      LAYER M5 ;
        RECT  21.6 36.528 21.624 36.72 ;
    END
  END dq[141]
  PIN dq[142]
    DIRECTION OUTPUT ;
    USE SIGNAL ;
    PORT
      LAYER M3 ;
        RECT  21.708 36.576 21.726 36.72 ;
    END
  END dq[142]
  PIN dq[143]
    DIRECTION OUTPUT ;
    USE SIGNAL ;
    PORT
      LAYER M5 ;
        RECT  21.84 36.528 21.864 36.72 ;
    END
  END dq[143]
  PIN dq[144]
    DIRECTION OUTPUT ;
    USE SIGNAL ;
    PORT
      LAYER M3 ;
        RECT  21.96 36.576 21.978 36.72 ;
    END
  END dq[144]
  PIN dq[145]
    DIRECTION OUTPUT ;
    USE SIGNAL ;
    PORT
      LAYER M5 ;
        RECT  22.08 36.528 22.104 36.72 ;
    END
  END dq[145]
  PIN dq[146]
    DIRECTION OUTPUT ;
    USE SIGNAL ;
    PORT
      LAYER M3 ;
        RECT  22.212 36.576 22.23 36.72 ;
    END
  END dq[146]
  PIN dq[147]
    DIRECTION OUTPUT ;
    USE SIGNAL ;
    PORT
      LAYER M5 ;
        RECT  22.32 36.528 22.344 36.72 ;
    END
  END dq[147]
  PIN dq[148]
    DIRECTION OUTPUT ;
    USE SIGNAL ;
    PORT
      LAYER M3 ;
        RECT  22.428 36.576 22.446 36.72 ;
    END
  END dq[148]
  PIN dq[149]
    DIRECTION OUTPUT ;
    USE SIGNAL ;
    PORT
      LAYER M5 ;
        RECT  22.56 36.528 22.584 36.72 ;
    END
  END dq[149]
  PIN dq[14]
    DIRECTION OUTPUT ;
    USE SIGNAL ;
    PORT
      LAYER M3 ;
        RECT  6.084 36.576 6.102 36.72 ;
    END
  END dq[14]
  PIN dq[150]
    DIRECTION OUTPUT ;
    USE SIGNAL ;
    PORT
      LAYER M3 ;
        RECT  22.68 36.576 22.698 36.72 ;
    END
  END dq[150]
  PIN dq[151]
    DIRECTION OUTPUT ;
    USE SIGNAL ;
    PORT
      LAYER M5 ;
        RECT  22.8 36.528 22.824 36.72 ;
    END
  END dq[151]
  PIN dq[152]
    DIRECTION OUTPUT ;
    USE SIGNAL ;
    PORT
      LAYER M3 ;
        RECT  22.932 36.576 22.95 36.72 ;
    END
  END dq[152]
  PIN dq[153]
    DIRECTION OUTPUT ;
    USE SIGNAL ;
    PORT
      LAYER M5 ;
        RECT  23.04 36.528 23.064 36.72 ;
    END
  END dq[153]
  PIN dq[154]
    DIRECTION OUTPUT ;
    USE SIGNAL ;
    PORT
      LAYER M3 ;
        RECT  23.184 36.576 23.202 36.72 ;
    END
  END dq[154]
  PIN dq[155]
    DIRECTION OUTPUT ;
    USE SIGNAL ;
    PORT
      LAYER M5 ;
        RECT  23.28 36.528 23.304 36.72 ;
    END
  END dq[155]
  PIN dq[156]
    DIRECTION OUTPUT ;
    USE SIGNAL ;
    PORT
      LAYER M3 ;
        RECT  23.4 36.576 23.418 36.72 ;
    END
  END dq[156]
  PIN dq[157]
    DIRECTION OUTPUT ;
    USE SIGNAL ;
    PORT
      LAYER M5 ;
        RECT  23.52 36.528 23.544 36.72 ;
    END
  END dq[157]
  PIN dq[158]
    DIRECTION OUTPUT ;
    USE SIGNAL ;
    PORT
      LAYER M3 ;
        RECT  23.652 36.576 23.67 36.72 ;
    END
  END dq[158]
  PIN dq[159]
    DIRECTION OUTPUT ;
    USE SIGNAL ;
    PORT
      LAYER M5 ;
        RECT  23.76 36.528 23.784 36.72 ;
    END
  END dq[159]
  PIN dq[15]
    DIRECTION OUTPUT ;
    USE SIGNAL ;
    PORT
      LAYER M5 ;
        RECT  6.192 36.528 6.216 36.72 ;
    END
  END dq[15]
  PIN dq[160]
    DIRECTION OUTPUT ;
    USE SIGNAL ;
    PORT
      LAYER M3 ;
        RECT  23.904 36.576 23.922 36.72 ;
    END
  END dq[160]
  PIN dq[161]
    DIRECTION OUTPUT ;
    USE SIGNAL ;
    PORT
      LAYER M5 ;
        RECT  24.048 36.528 24.072 36.72 ;
    END
  END dq[161]
  PIN dq[162]
    DIRECTION OUTPUT ;
    USE SIGNAL ;
    PORT
      LAYER M3 ;
        RECT  24.156 36.576 24.174 36.72 ;
    END
  END dq[162]
  PIN dq[163]
    DIRECTION OUTPUT ;
    USE SIGNAL ;
    PORT
      LAYER M5 ;
        RECT  24.288 36.528 24.312 36.72 ;
    END
  END dq[163]
  PIN dq[164]
    DIRECTION OUTPUT ;
    USE SIGNAL ;
    PORT
      LAYER M3 ;
        RECT  24.408 36.576 24.426 36.72 ;
    END
  END dq[164]
  PIN dq[165]
    DIRECTION OUTPUT ;
    USE SIGNAL ;
    PORT
      LAYER M5 ;
        RECT  24.528 36.528 24.552 36.72 ;
    END
  END dq[165]
  PIN dq[166]
    DIRECTION OUTPUT ;
    USE SIGNAL ;
    PORT
      LAYER M3 ;
        RECT  24.624 36.576 24.642 36.72 ;
    END
  END dq[166]
  PIN dq[167]
    DIRECTION OUTPUT ;
    USE SIGNAL ;
    PORT
      LAYER M5 ;
        RECT  24.768 36.528 24.792 36.72 ;
    END
  END dq[167]
  PIN dq[168]
    DIRECTION OUTPUT ;
    USE SIGNAL ;
    PORT
      LAYER M3 ;
        RECT  24.876 36.576 24.894 36.72 ;
    END
  END dq[168]
  PIN dq[169]
    DIRECTION OUTPUT ;
    USE SIGNAL ;
    PORT
      LAYER M5 ;
        RECT  25.008 36.528 25.032 36.72 ;
    END
  END dq[169]
  PIN dq[16]
    DIRECTION OUTPUT ;
    USE SIGNAL ;
    PORT
      LAYER M3 ;
        RECT  6.336 36.576 6.354 36.72 ;
    END
  END dq[16]
  PIN dq[170]
    DIRECTION OUTPUT ;
    USE SIGNAL ;
    PORT
      LAYER M3 ;
        RECT  25.128 36.576 25.146 36.72 ;
    END
  END dq[170]
  PIN dq[171]
    DIRECTION OUTPUT ;
    USE SIGNAL ;
    PORT
      LAYER M5 ;
        RECT  25.248 36.528 25.272 36.72 ;
    END
  END dq[171]
  PIN dq[172]
    DIRECTION OUTPUT ;
    USE SIGNAL ;
    PORT
      LAYER M3 ;
        RECT  25.38 36.576 25.398 36.72 ;
    END
  END dq[172]
  PIN dq[173]
    DIRECTION OUTPUT ;
    USE SIGNAL ;
    PORT
      LAYER M5 ;
        RECT  25.488 36.528 25.512 36.72 ;
    END
  END dq[173]
  PIN dq[174]
    DIRECTION OUTPUT ;
    USE SIGNAL ;
    PORT
      LAYER M3 ;
        RECT  25.632 36.576 25.65 36.72 ;
    END
  END dq[174]
  PIN dq[175]
    DIRECTION OUTPUT ;
    USE SIGNAL ;
    PORT
      LAYER M5 ;
        RECT  25.728 36.528 25.752 36.72 ;
    END
  END dq[175]
  PIN dq[176]
    DIRECTION OUTPUT ;
    USE SIGNAL ;
    PORT
      LAYER M3 ;
        RECT  25.848 36.576 25.866 36.72 ;
    END
  END dq[176]
  PIN dq[177]
    DIRECTION OUTPUT ;
    USE SIGNAL ;
    PORT
      LAYER M5 ;
        RECT  25.968 36.528 25.992 36.72 ;
    END
  END dq[177]
  PIN dq[178]
    DIRECTION OUTPUT ;
    USE SIGNAL ;
    PORT
      LAYER M3 ;
        RECT  26.1 36.576 26.118 36.72 ;
    END
  END dq[178]
  PIN dq[179]
    DIRECTION OUTPUT ;
    USE SIGNAL ;
    PORT
      LAYER M5 ;
        RECT  26.208 36.528 26.232 36.72 ;
    END
  END dq[179]
  PIN dq[17]
    DIRECTION OUTPUT ;
    USE SIGNAL ;
    PORT
      LAYER M5 ;
        RECT  6.432 36.528 6.456 36.72 ;
    END
  END dq[17]
  PIN dq[180]
    DIRECTION OUTPUT ;
    USE SIGNAL ;
    PORT
      LAYER M3 ;
        RECT  26.352 36.576 26.37 36.72 ;
    END
  END dq[180]
  PIN dq[181]
    DIRECTION OUTPUT ;
    USE SIGNAL ;
    PORT
      LAYER M5 ;
        RECT  26.448 36.528 26.472 36.72 ;
    END
  END dq[181]
  PIN dq[182]
    DIRECTION OUTPUT ;
    USE SIGNAL ;
    PORT
      LAYER M3 ;
        RECT  26.604 36.576 26.622 36.72 ;
    END
  END dq[182]
  PIN dq[183]
    DIRECTION OUTPUT ;
    USE SIGNAL ;
    PORT
      LAYER M5 ;
        RECT  26.688 36.528 26.712 36.72 ;
    END
  END dq[183]
  PIN dq[184]
    DIRECTION OUTPUT ;
    USE SIGNAL ;
    PORT
      LAYER M3 ;
        RECT  26.82 36.576 26.838 36.72 ;
    END
  END dq[184]
  PIN dq[185]
    DIRECTION OUTPUT ;
    USE SIGNAL ;
    PORT
      LAYER M5 ;
        RECT  26.976 36.528 27 36.72 ;
    END
  END dq[185]
  PIN dq[186]
    DIRECTION OUTPUT ;
    USE SIGNAL ;
    PORT
      LAYER M3 ;
        RECT  27.072 36.576 27.09 36.72 ;
    END
  END dq[186]
  PIN dq[187]
    DIRECTION OUTPUT ;
    USE SIGNAL ;
    PORT
      LAYER M5 ;
        RECT  27.216 36.528 27.24 36.72 ;
    END
  END dq[187]
  PIN dq[188]
    DIRECTION OUTPUT ;
    USE SIGNAL ;
    PORT
      LAYER M3 ;
        RECT  27.324 36.576 27.342 36.72 ;
    END
  END dq[188]
  PIN dq[189]
    DIRECTION OUTPUT ;
    USE SIGNAL ;
    PORT
      LAYER M5 ;
        RECT  27.456 36.528 27.48 36.72 ;
    END
  END dq[189]
  PIN dq[18]
    DIRECTION OUTPUT ;
    USE SIGNAL ;
    PORT
      LAYER M3 ;
        RECT  6.552 36.576 6.57 36.72 ;
    END
  END dq[18]
  PIN dq[190]
    DIRECTION OUTPUT ;
    USE SIGNAL ;
    PORT
      LAYER M3 ;
        RECT  27.576 36.576 27.594 36.72 ;
    END
  END dq[190]
  PIN dq[191]
    DIRECTION OUTPUT ;
    USE SIGNAL ;
    PORT
      LAYER M5 ;
        RECT  27.696 36.528 27.72 36.72 ;
    END
  END dq[191]
  PIN dq[192]
    DIRECTION OUTPUT ;
    USE SIGNAL ;
    PORT
      LAYER M3 ;
        RECT  27.828 36.576 27.846 36.72 ;
    END
  END dq[192]
  PIN dq[193]
    DIRECTION OUTPUT ;
    USE SIGNAL ;
    PORT
      LAYER M5 ;
        RECT  27.936 36.528 27.96 36.72 ;
    END
  END dq[193]
  PIN dq[194]
    DIRECTION OUTPUT ;
    USE SIGNAL ;
    PORT
      LAYER M3 ;
        RECT  28.044 36.576 28.062 36.72 ;
    END
  END dq[194]
  PIN dq[195]
    DIRECTION OUTPUT ;
    USE SIGNAL ;
    PORT
      LAYER M5 ;
        RECT  28.176 36.528 28.2 36.72 ;
    END
  END dq[195]
  PIN dq[196]
    DIRECTION OUTPUT ;
    USE SIGNAL ;
    PORT
      LAYER M3 ;
        RECT  28.296 36.576 28.314 36.72 ;
    END
  END dq[196]
  PIN dq[197]
    DIRECTION OUTPUT ;
    USE SIGNAL ;
    PORT
      LAYER M5 ;
        RECT  28.416 36.528 28.44 36.72 ;
    END
  END dq[197]
  PIN dq[198]
    DIRECTION OUTPUT ;
    USE SIGNAL ;
    PORT
      LAYER M3 ;
        RECT  28.548 36.576 28.566 36.72 ;
    END
  END dq[198]
  PIN dq[199]
    DIRECTION OUTPUT ;
    USE SIGNAL ;
    PORT
      LAYER M5 ;
        RECT  28.656 36.528 28.68 36.72 ;
    END
  END dq[199]
  PIN dq[19]
    DIRECTION OUTPUT ;
    USE SIGNAL ;
    PORT
      LAYER M5 ;
        RECT  6.672 36.528 6.696 36.72 ;
    END
  END dq[19]
  PIN dq[1]
    DIRECTION OUTPUT ;
    USE SIGNAL ;
    PORT
      LAYER M5 ;
        RECT  4.512 36.528 4.536 36.72 ;
    END
  END dq[1]
  PIN dq[200]
    DIRECTION OUTPUT ;
    USE SIGNAL ;
    PORT
      LAYER M3 ;
        RECT  28.8 36.576 28.818 36.72 ;
    END
  END dq[200]
  PIN dq[201]
    DIRECTION OUTPUT ;
    USE SIGNAL ;
    PORT
      LAYER M5 ;
        RECT  28.896 36.528 28.92 36.72 ;
    END
  END dq[201]
  PIN dq[202]
    DIRECTION OUTPUT ;
    USE SIGNAL ;
    PORT
      LAYER M3 ;
        RECT  29.016 36.576 29.034 36.72 ;
    END
  END dq[202]
  PIN dq[203]
    DIRECTION OUTPUT ;
    USE SIGNAL ;
    PORT
      LAYER M5 ;
        RECT  29.136 36.528 29.16 36.72 ;
    END
  END dq[203]
  PIN dq[204]
    DIRECTION OUTPUT ;
    USE SIGNAL ;
    PORT
      LAYER M3 ;
        RECT  29.268 36.576 29.286 36.72 ;
    END
  END dq[204]
  PIN dq[205]
    DIRECTION OUTPUT ;
    USE SIGNAL ;
    PORT
      LAYER M5 ;
        RECT  29.376 36.528 29.4 36.72 ;
    END
  END dq[205]
  PIN dq[206]
    DIRECTION OUTPUT ;
    USE SIGNAL ;
    PORT
      LAYER M3 ;
        RECT  29.52 36.576 29.538 36.72 ;
    END
  END dq[206]
  PIN dq[207]
    DIRECTION OUTPUT ;
    USE SIGNAL ;
    PORT
      LAYER M5 ;
        RECT  29.664 36.528 29.688 36.72 ;
    END
  END dq[207]
  PIN dq[208]
    DIRECTION OUTPUT ;
    USE SIGNAL ;
    PORT
      LAYER M3 ;
        RECT  29.772 36.576 29.79 36.72 ;
    END
  END dq[208]
  PIN dq[209]
    DIRECTION OUTPUT ;
    USE SIGNAL ;
    PORT
      LAYER M5 ;
        RECT  29.904 36.528 29.928 36.72 ;
    END
  END dq[209]
  PIN dq[20]
    DIRECTION OUTPUT ;
    USE SIGNAL ;
    PORT
      LAYER M3 ;
        RECT  6.804 36.576 6.822 36.72 ;
    END
  END dq[20]
  PIN dq[210]
    DIRECTION OUTPUT ;
    USE SIGNAL ;
    PORT
      LAYER M3 ;
        RECT  30.024 36.576 30.042 36.72 ;
    END
  END dq[210]
  PIN dq[211]
    DIRECTION OUTPUT ;
    USE SIGNAL ;
    PORT
      LAYER M5 ;
        RECT  30.144 36.528 30.168 36.72 ;
    END
  END dq[211]
  PIN dq[212]
    DIRECTION OUTPUT ;
    USE SIGNAL ;
    PORT
      LAYER M3 ;
        RECT  30.24 36.576 30.258 36.72 ;
    END
  END dq[212]
  PIN dq[213]
    DIRECTION OUTPUT ;
    USE SIGNAL ;
    PORT
      LAYER M5 ;
        RECT  30.384 36.528 30.408 36.72 ;
    END
  END dq[213]
  PIN dq[214]
    DIRECTION OUTPUT ;
    USE SIGNAL ;
    PORT
      LAYER M3 ;
        RECT  30.492 36.576 30.51 36.72 ;
    END
  END dq[214]
  PIN dq[215]
    DIRECTION OUTPUT ;
    USE SIGNAL ;
    PORT
      LAYER M5 ;
        RECT  30.624 36.528 30.648 36.72 ;
    END
  END dq[215]
  PIN dq[216]
    DIRECTION OUTPUT ;
    USE SIGNAL ;
    PORT
      LAYER M3 ;
        RECT  30.744 36.576 30.762 36.72 ;
    END
  END dq[216]
  PIN dq[217]
    DIRECTION OUTPUT ;
    USE SIGNAL ;
    PORT
      LAYER M5 ;
        RECT  30.864 36.528 30.888 36.72 ;
    END
  END dq[217]
  PIN dq[218]
    DIRECTION OUTPUT ;
    USE SIGNAL ;
    PORT
      LAYER M3 ;
        RECT  30.996 36.576 31.014 36.72 ;
    END
  END dq[218]
  PIN dq[219]
    DIRECTION OUTPUT ;
    USE SIGNAL ;
    PORT
      LAYER M5 ;
        RECT  31.104 36.528 31.128 36.72 ;
    END
  END dq[219]
  PIN dq[21]
    DIRECTION OUTPUT ;
    USE SIGNAL ;
    PORT
      LAYER M5 ;
        RECT  6.912 36.528 6.936 36.72 ;
    END
  END dq[21]
  PIN dq[220]
    DIRECTION OUTPUT ;
    USE SIGNAL ;
    PORT
      LAYER M3 ;
        RECT  31.248 36.576 31.266 36.72 ;
    END
  END dq[220]
  PIN dq[221]
    DIRECTION OUTPUT ;
    USE SIGNAL ;
    PORT
      LAYER M5 ;
        RECT  31.344 36.528 31.368 36.72 ;
    END
  END dq[221]
  PIN dq[222]
    DIRECTION OUTPUT ;
    USE SIGNAL ;
    PORT
      LAYER M3 ;
        RECT  31.464 36.576 31.482 36.72 ;
    END
  END dq[222]
  PIN dq[223]
    DIRECTION OUTPUT ;
    USE SIGNAL ;
    PORT
      LAYER M5 ;
        RECT  31.584 36.528 31.608 36.72 ;
    END
  END dq[223]
  PIN dq[224]
    DIRECTION OUTPUT ;
    USE SIGNAL ;
    PORT
      LAYER M3 ;
        RECT  31.716 36.576 31.734 36.72 ;
    END
  END dq[224]
  PIN dq[225]
    DIRECTION OUTPUT ;
    USE SIGNAL ;
    PORT
      LAYER M5 ;
        RECT  31.824 36.528 31.848 36.72 ;
    END
  END dq[225]
  PIN dq[226]
    DIRECTION OUTPUT ;
    USE SIGNAL ;
    PORT
      LAYER M3 ;
        RECT  31.968 36.576 31.986 36.72 ;
    END
  END dq[226]
  PIN dq[227]
    DIRECTION OUTPUT ;
    USE SIGNAL ;
    PORT
      LAYER M5 ;
        RECT  32.064 36.528 32.088 36.72 ;
    END
  END dq[227]
  PIN dq[228]
    DIRECTION OUTPUT ;
    USE SIGNAL ;
    PORT
      LAYER M3 ;
        RECT  32.22 36.576 32.238 36.72 ;
    END
  END dq[228]
  PIN dq[229]
    DIRECTION OUTPUT ;
    USE SIGNAL ;
    PORT
      LAYER M5 ;
        RECT  32.304 36.528 32.328 36.72 ;
    END
  END dq[229]
  PIN dq[22]
    DIRECTION OUTPUT ;
    USE SIGNAL ;
    PORT
      LAYER M3 ;
        RECT  7.056 36.576 7.074 36.72 ;
    END
  END dq[22]
  PIN dq[230]
    DIRECTION OUTPUT ;
    USE SIGNAL ;
    PORT
      LAYER M3 ;
        RECT  32.436 36.576 32.454 36.72 ;
    END
  END dq[230]
  PIN dq[231]
    DIRECTION OUTPUT ;
    USE SIGNAL ;
    PORT
      LAYER M5 ;
        RECT  32.592 36.528 32.616 36.72 ;
    END
  END dq[231]
  PIN dq[232]
    DIRECTION OUTPUT ;
    USE SIGNAL ;
    PORT
      LAYER M3 ;
        RECT  32.688 36.576 32.706 36.72 ;
    END
  END dq[232]
  PIN dq[233]
    DIRECTION OUTPUT ;
    USE SIGNAL ;
    PORT
      LAYER M5 ;
        RECT  32.832 36.528 32.856 36.72 ;
    END
  END dq[233]
  PIN dq[234]
    DIRECTION OUTPUT ;
    USE SIGNAL ;
    PORT
      LAYER M3 ;
        RECT  32.94 36.576 32.958 36.72 ;
    END
  END dq[234]
  PIN dq[235]
    DIRECTION OUTPUT ;
    USE SIGNAL ;
    PORT
      LAYER M5 ;
        RECT  33.072 36.528 33.096 36.72 ;
    END
  END dq[235]
  PIN dq[236]
    DIRECTION OUTPUT ;
    USE SIGNAL ;
    PORT
      LAYER M3 ;
        RECT  33.192 36.576 33.21 36.72 ;
    END
  END dq[236]
  PIN dq[237]
    DIRECTION OUTPUT ;
    USE SIGNAL ;
    PORT
      LAYER M5 ;
        RECT  33.312 36.528 33.336 36.72 ;
    END
  END dq[237]
  PIN dq[238]
    DIRECTION OUTPUT ;
    USE SIGNAL ;
    PORT
      LAYER M3 ;
        RECT  33.444 36.576 33.462 36.72 ;
    END
  END dq[238]
  PIN dq[239]
    DIRECTION OUTPUT ;
    USE SIGNAL ;
    PORT
      LAYER M5 ;
        RECT  33.552 36.528 33.576 36.72 ;
    END
  END dq[239]
  PIN dq[23]
    DIRECTION OUTPUT ;
    USE SIGNAL ;
    PORT
      LAYER M5 ;
        RECT  7.2 36.528 7.224 36.72 ;
    END
  END dq[23]
  PIN dq[240]
    DIRECTION OUTPUT ;
    USE SIGNAL ;
    PORT
      LAYER M3 ;
        RECT  33.66 36.576 33.678 36.72 ;
    END
  END dq[240]
  PIN dq[241]
    DIRECTION OUTPUT ;
    USE SIGNAL ;
    PORT
      LAYER M5 ;
        RECT  33.792 36.528 33.816 36.72 ;
    END
  END dq[241]
  PIN dq[242]
    DIRECTION OUTPUT ;
    USE SIGNAL ;
    PORT
      LAYER M3 ;
        RECT  33.912 36.576 33.93 36.72 ;
    END
  END dq[242]
  PIN dq[243]
    DIRECTION OUTPUT ;
    USE SIGNAL ;
    PORT
      LAYER M5 ;
        RECT  34.032 36.528 34.056 36.72 ;
    END
  END dq[243]
  PIN dq[244]
    DIRECTION OUTPUT ;
    USE SIGNAL ;
    PORT
      LAYER M3 ;
        RECT  34.164 36.576 34.182 36.72 ;
    END
  END dq[244]
  PIN dq[245]
    DIRECTION OUTPUT ;
    USE SIGNAL ;
    PORT
      LAYER M5 ;
        RECT  34.272 36.528 34.296 36.72 ;
    END
  END dq[245]
  PIN dq[246]
    DIRECTION OUTPUT ;
    USE SIGNAL ;
    PORT
      LAYER M3 ;
        RECT  34.416 36.576 34.434 36.72 ;
    END
  END dq[246]
  PIN dq[247]
    DIRECTION OUTPUT ;
    USE SIGNAL ;
    PORT
      LAYER M5 ;
        RECT  34.512 36.528 34.536 36.72 ;
    END
  END dq[247]
  PIN dq[248]
    DIRECTION OUTPUT ;
    USE SIGNAL ;
    PORT
      LAYER M3 ;
        RECT  34.632 36.576 34.65 36.72 ;
    END
  END dq[248]
  PIN dq[249]
    DIRECTION OUTPUT ;
    USE SIGNAL ;
    PORT
      LAYER M5 ;
        RECT  34.752 36.528 34.776 36.72 ;
    END
  END dq[249]
  PIN dq[24]
    DIRECTION OUTPUT ;
    USE SIGNAL ;
    PORT
      LAYER M3 ;
        RECT  7.308 36.576 7.326 36.72 ;
    END
  END dq[24]
  PIN dq[250]
    DIRECTION OUTPUT ;
    USE SIGNAL ;
    PORT
      LAYER M3 ;
        RECT  34.884 36.576 34.902 36.72 ;
    END
  END dq[250]
  PIN dq[251]
    DIRECTION OUTPUT ;
    USE SIGNAL ;
    PORT
      LAYER M5 ;
        RECT  34.992 36.528 35.016 36.72 ;
    END
  END dq[251]
  PIN dq[252]
    DIRECTION OUTPUT ;
    USE SIGNAL ;
    PORT
      LAYER M3 ;
        RECT  35.136 36.576 35.154 36.72 ;
    END
  END dq[252]
  PIN dq[253]
    DIRECTION OUTPUT ;
    USE SIGNAL ;
    PORT
      LAYER M5 ;
        RECT  35.28 36.528 35.304 36.72 ;
    END
  END dq[253]
  PIN dq[254]
    DIRECTION OUTPUT ;
    USE SIGNAL ;
    PORT
      LAYER M3 ;
        RECT  35.388 36.576 35.406 36.72 ;
    END
  END dq[254]
  PIN dq[255]
    DIRECTION OUTPUT ;
    USE SIGNAL ;
    PORT
      LAYER M5 ;
        RECT  35.52 36.528 35.544 36.72 ;
    END
  END dq[255]
  PIN dq[256]
    DIRECTION OUTPUT ;
    USE SIGNAL ;
    PORT
      LAYER M3 ;
        RECT  35.64 36.576 35.658 36.72 ;
    END
  END dq[256]
  PIN dq[257]
    DIRECTION OUTPUT ;
    USE SIGNAL ;
    PORT
      LAYER M5 ;
        RECT  35.76 36.528 35.784 36.72 ;
    END
  END dq[257]
  PIN dq[258]
    DIRECTION OUTPUT ;
    USE SIGNAL ;
    PORT
      LAYER M3 ;
        RECT  35.856 36.576 35.874 36.72 ;
    END
  END dq[258]
  PIN dq[259]
    DIRECTION OUTPUT ;
    USE SIGNAL ;
    PORT
      LAYER M5 ;
        RECT  36 36.528 36.024 36.72 ;
    END
  END dq[259]
  PIN dq[25]
    DIRECTION OUTPUT ;
    USE SIGNAL ;
    PORT
      LAYER M5 ;
        RECT  7.44 36.528 7.464 36.72 ;
    END
  END dq[25]
  PIN dq[260]
    DIRECTION OUTPUT ;
    USE SIGNAL ;
    PORT
      LAYER M3 ;
        RECT  36.108 36.576 36.126 36.72 ;
    END
  END dq[260]
  PIN dq[261]
    DIRECTION OUTPUT ;
    USE SIGNAL ;
    PORT
      LAYER M5 ;
        RECT  36.24 36.528 36.264 36.72 ;
    END
  END dq[261]
  PIN dq[262]
    DIRECTION OUTPUT ;
    USE SIGNAL ;
    PORT
      LAYER M3 ;
        RECT  36.36 36.576 36.378 36.72 ;
    END
  END dq[262]
  PIN dq[263]
    DIRECTION OUTPUT ;
    USE SIGNAL ;
    PORT
      LAYER M5 ;
        RECT  36.48 36.528 36.504 36.72 ;
    END
  END dq[263]
  PIN dq[264]
    DIRECTION OUTPUT ;
    USE SIGNAL ;
    PORT
      LAYER M3 ;
        RECT  36.612 36.576 36.63 36.72 ;
    END
  END dq[264]
  PIN dq[265]
    DIRECTION OUTPUT ;
    USE SIGNAL ;
    PORT
      LAYER M5 ;
        RECT  36.72 36.528 36.744 36.72 ;
    END
  END dq[265]
  PIN dq[266]
    DIRECTION OUTPUT ;
    USE SIGNAL ;
    PORT
      LAYER M3 ;
        RECT  36.864 36.576 36.882 36.72 ;
    END
  END dq[266]
  PIN dq[267]
    DIRECTION OUTPUT ;
    USE SIGNAL ;
    PORT
      LAYER M5 ;
        RECT  36.96 36.528 36.984 36.72 ;
    END
  END dq[267]
  PIN dq[268]
    DIRECTION OUTPUT ;
    USE SIGNAL ;
    PORT
      LAYER M3 ;
        RECT  37.08 36.576 37.098 36.72 ;
    END
  END dq[268]
  PIN dq[269]
    DIRECTION OUTPUT ;
    USE SIGNAL ;
    PORT
      LAYER M5 ;
        RECT  37.2 36.528 37.224 36.72 ;
    END
  END dq[269]
  PIN dq[26]
    DIRECTION OUTPUT ;
    USE SIGNAL ;
    PORT
      LAYER M3 ;
        RECT  7.56 36.576 7.578 36.72 ;
    END
  END dq[26]
  PIN dq[270]
    DIRECTION OUTPUT ;
    USE SIGNAL ;
    PORT
      LAYER M3 ;
        RECT  37.332 36.576 37.35 36.72 ;
    END
  END dq[270]
  PIN dq[271]
    DIRECTION OUTPUT ;
    USE SIGNAL ;
    PORT
      LAYER M5 ;
        RECT  37.44 36.528 37.464 36.72 ;
    END
  END dq[271]
  PIN dq[272]
    DIRECTION OUTPUT ;
    USE SIGNAL ;
    PORT
      LAYER M3 ;
        RECT  37.584 36.576 37.602 36.72 ;
    END
  END dq[272]
  PIN dq[273]
    DIRECTION OUTPUT ;
    USE SIGNAL ;
    PORT
      LAYER M5 ;
        RECT  37.68 36.528 37.704 36.72 ;
    END
  END dq[273]
  PIN dq[274]
    DIRECTION OUTPUT ;
    USE SIGNAL ;
    PORT
      LAYER M3 ;
        RECT  37.836 36.576 37.854 36.72 ;
    END
  END dq[274]
  PIN dq[275]
    DIRECTION OUTPUT ;
    USE SIGNAL ;
    PORT
      LAYER M5 ;
        RECT  37.92 36.528 37.944 36.72 ;
    END
  END dq[275]
  PIN dq[276]
    DIRECTION OUTPUT ;
    USE SIGNAL ;
    PORT
      LAYER M3 ;
        RECT  38.052 36.576 38.07 36.72 ;
    END
  END dq[276]
  PIN dq[277]
    DIRECTION OUTPUT ;
    USE SIGNAL ;
    PORT
      LAYER M5 ;
        RECT  38.208 36.528 38.232 36.72 ;
    END
  END dq[277]
  PIN dq[278]
    DIRECTION OUTPUT ;
    USE SIGNAL ;
    PORT
      LAYER M3 ;
        RECT  38.304 36.576 38.322 36.72 ;
    END
  END dq[278]
  PIN dq[279]
    DIRECTION OUTPUT ;
    USE SIGNAL ;
    PORT
      LAYER M5 ;
        RECT  38.448 36.528 38.472 36.72 ;
    END
  END dq[279]
  PIN dq[27]
    DIRECTION OUTPUT ;
    USE SIGNAL ;
    PORT
      LAYER M5 ;
        RECT  7.68 36.528 7.704 36.72 ;
    END
  END dq[27]
  PIN dq[280]
    DIRECTION OUTPUT ;
    USE SIGNAL ;
    PORT
      LAYER M3 ;
        RECT  38.556 36.576 38.574 36.72 ;
    END
  END dq[280]
  PIN dq[281]
    DIRECTION OUTPUT ;
    USE SIGNAL ;
    PORT
      LAYER M5 ;
        RECT  38.688 36.528 38.712 36.72 ;
    END
  END dq[281]
  PIN dq[282]
    DIRECTION OUTPUT ;
    USE SIGNAL ;
    PORT
      LAYER M3 ;
        RECT  38.808 36.576 38.826 36.72 ;
    END
  END dq[282]
  PIN dq[283]
    DIRECTION OUTPUT ;
    USE SIGNAL ;
    PORT
      LAYER M5 ;
        RECT  38.928 36.528 38.952 36.72 ;
    END
  END dq[283]
  PIN dq[284]
    DIRECTION OUTPUT ;
    USE SIGNAL ;
    PORT
      LAYER M3 ;
        RECT  39.06 36.576 39.078 36.72 ;
    END
  END dq[284]
  PIN dq[285]
    DIRECTION OUTPUT ;
    USE SIGNAL ;
    PORT
      LAYER M5 ;
        RECT  39.168 36.528 39.192 36.72 ;
    END
  END dq[285]
  PIN dq[286]
    DIRECTION OUTPUT ;
    USE SIGNAL ;
    PORT
      LAYER M3 ;
        RECT  39.276 36.576 39.294 36.72 ;
    END
  END dq[286]
  PIN dq[287]
    DIRECTION OUTPUT ;
    USE SIGNAL ;
    PORT
      LAYER M5 ;
        RECT  39.408 36.528 39.432 36.72 ;
    END
  END dq[287]
  PIN dq[288]
    DIRECTION OUTPUT ;
    USE SIGNAL ;
    PORT
      LAYER M3 ;
        RECT  39.528 36.576 39.546 36.72 ;
    END
  END dq[288]
  PIN dq[289]
    DIRECTION OUTPUT ;
    USE SIGNAL ;
    PORT
      LAYER M5 ;
        RECT  39.648 36.528 39.672 36.72 ;
    END
  END dq[289]
  PIN dq[28]
    DIRECTION OUTPUT ;
    USE SIGNAL ;
    PORT
      LAYER M3 ;
        RECT  7.776 36.576 7.794 36.72 ;
    END
  END dq[28]
  PIN dq[290]
    DIRECTION OUTPUT ;
    USE SIGNAL ;
    PORT
      LAYER M3 ;
        RECT  39.78 36.576 39.798 36.72 ;
    END
  END dq[290]
  PIN dq[291]
    DIRECTION OUTPUT ;
    USE SIGNAL ;
    PORT
      LAYER M5 ;
        RECT  39.888 36.528 39.912 36.72 ;
    END
  END dq[291]
  PIN dq[292]
    DIRECTION OUTPUT ;
    USE SIGNAL ;
    PORT
      LAYER M3 ;
        RECT  40.032 36.576 40.05 36.72 ;
    END
  END dq[292]
  PIN dq[293]
    DIRECTION OUTPUT ;
    USE SIGNAL ;
    PORT
      LAYER M5 ;
        RECT  40.128 36.528 40.152 36.72 ;
    END
  END dq[293]
  PIN dq[294]
    DIRECTION OUTPUT ;
    USE SIGNAL ;
    PORT
      LAYER M3 ;
        RECT  40.248 36.576 40.266 36.72 ;
    END
  END dq[294]
  PIN dq[295]
    DIRECTION OUTPUT ;
    USE SIGNAL ;
    PORT
      LAYER M5 ;
        RECT  40.368 36.528 40.392 36.72 ;
    END
  END dq[295]
  PIN dq[296]
    DIRECTION OUTPUT ;
    USE SIGNAL ;
    PORT
      LAYER M3 ;
        RECT  40.5 36.576 40.518 36.72 ;
    END
  END dq[296]
  PIN dq[297]
    DIRECTION OUTPUT ;
    USE SIGNAL ;
    PORT
      LAYER M5 ;
        RECT  40.608 36.528 40.632 36.72 ;
    END
  END dq[297]
  PIN dq[298]
    DIRECTION OUTPUT ;
    USE SIGNAL ;
    PORT
      LAYER M3 ;
        RECT  40.752 36.576 40.77 36.72 ;
    END
  END dq[298]
  PIN dq[299]
    DIRECTION OUTPUT ;
    USE SIGNAL ;
    PORT
      LAYER M5 ;
        RECT  40.896 36.528 40.92 36.72 ;
    END
  END dq[299]
  PIN dq[29]
    DIRECTION OUTPUT ;
    USE SIGNAL ;
    PORT
      LAYER M5 ;
        RECT  7.92 36.528 7.944 36.72 ;
    END
  END dq[29]
  PIN dq[2]
    DIRECTION OUTPUT ;
    USE SIGNAL ;
    PORT
      LAYER M3 ;
        RECT  4.608 36.576 4.626 36.72 ;
    END
  END dq[2]
  PIN dq[300]
    DIRECTION OUTPUT ;
    USE SIGNAL ;
    PORT
      LAYER M3 ;
        RECT  41.004 36.576 41.022 36.72 ;
    END
  END dq[300]
  PIN dq[301]
    DIRECTION OUTPUT ;
    USE SIGNAL ;
    PORT
      LAYER M5 ;
        RECT  41.136 36.528 41.16 36.72 ;
    END
  END dq[301]
  PIN dq[302]
    DIRECTION OUTPUT ;
    USE SIGNAL ;
    PORT
      LAYER M3 ;
        RECT  41.256 36.576 41.274 36.72 ;
    END
  END dq[302]
  PIN dq[303]
    DIRECTION OUTPUT ;
    USE SIGNAL ;
    PORT
      LAYER M5 ;
        RECT  41.376 36.528 41.4 36.72 ;
    END
  END dq[303]
  PIN dq[304]
    DIRECTION OUTPUT ;
    USE SIGNAL ;
    PORT
      LAYER M3 ;
        RECT  41.472 36.576 41.49 36.72 ;
    END
  END dq[304]
  PIN dq[305]
    DIRECTION OUTPUT ;
    USE SIGNAL ;
    PORT
      LAYER M5 ;
        RECT  41.616 36.528 41.64 36.72 ;
    END
  END dq[305]
  PIN dq[306]
    DIRECTION OUTPUT ;
    USE SIGNAL ;
    PORT
      LAYER M3 ;
        RECT  41.724 36.576 41.742 36.72 ;
    END
  END dq[306]
  PIN dq[307]
    DIRECTION OUTPUT ;
    USE SIGNAL ;
    PORT
      LAYER M5 ;
        RECT  41.856 36.528 41.88 36.72 ;
    END
  END dq[307]
  PIN dq[308]
    DIRECTION OUTPUT ;
    USE SIGNAL ;
    PORT
      LAYER M3 ;
        RECT  41.976 36.576 41.994 36.72 ;
    END
  END dq[308]
  PIN dq[309]
    DIRECTION OUTPUT ;
    USE SIGNAL ;
    PORT
      LAYER M5 ;
        RECT  42.096 36.528 42.12 36.72 ;
    END
  END dq[309]
  PIN dq[30]
    DIRECTION OUTPUT ;
    USE SIGNAL ;
    PORT
      LAYER M3 ;
        RECT  8.028 36.576 8.046 36.72 ;
    END
  END dq[30]
  PIN dq[310]
    DIRECTION OUTPUT ;
    USE SIGNAL ;
    PORT
      LAYER M3 ;
        RECT  42.228 36.576 42.246 36.72 ;
    END
  END dq[310]
  PIN dq[311]
    DIRECTION OUTPUT ;
    USE SIGNAL ;
    PORT
      LAYER M5 ;
        RECT  42.336 36.528 42.36 36.72 ;
    END
  END dq[311]
  PIN dq[312]
    DIRECTION OUTPUT ;
    USE SIGNAL ;
    PORT
      LAYER M3 ;
        RECT  42.48 36.576 42.498 36.72 ;
    END
  END dq[312]
  PIN dq[313]
    DIRECTION OUTPUT ;
    USE SIGNAL ;
    PORT
      LAYER M5 ;
        RECT  42.576 36.528 42.6 36.72 ;
    END
  END dq[313]
  PIN dq[314]
    DIRECTION OUTPUT ;
    USE SIGNAL ;
    PORT
      LAYER M3 ;
        RECT  42.696 36.576 42.714 36.72 ;
    END
  END dq[314]
  PIN dq[315]
    DIRECTION OUTPUT ;
    USE SIGNAL ;
    PORT
      LAYER M5 ;
        RECT  42.816 36.528 42.84 36.72 ;
    END
  END dq[315]
  PIN dq[316]
    DIRECTION OUTPUT ;
    USE SIGNAL ;
    PORT
      LAYER M3 ;
        RECT  42.948 36.576 42.966 36.72 ;
    END
  END dq[316]
  PIN dq[317]
    DIRECTION OUTPUT ;
    USE SIGNAL ;
    PORT
      LAYER M5 ;
        RECT  43.056 36.528 43.08 36.72 ;
    END
  END dq[317]
  PIN dq[318]
    DIRECTION OUTPUT ;
    USE SIGNAL ;
    PORT
      LAYER M3 ;
        RECT  43.2 36.576 43.218 36.72 ;
    END
  END dq[318]
  PIN dq[319]
    DIRECTION OUTPUT ;
    USE SIGNAL ;
    PORT
      LAYER M5 ;
        RECT  43.296 36.528 43.32 36.72 ;
    END
  END dq[319]
  PIN dq[31]
    DIRECTION OUTPUT ;
    USE SIGNAL ;
    PORT
      LAYER M5 ;
        RECT  8.16 36.528 8.184 36.72 ;
    END
  END dq[31]
  PIN dq[320]
    DIRECTION OUTPUT ;
    USE SIGNAL ;
    PORT
      LAYER M3 ;
        RECT  43.452 36.576 43.47 36.72 ;
    END
  END dq[320]
  PIN dq[321]
    DIRECTION OUTPUT ;
    USE SIGNAL ;
    PORT
      LAYER M5 ;
        RECT  43.536 36.528 43.56 36.72 ;
    END
  END dq[321]
  PIN dq[322]
    DIRECTION OUTPUT ;
    USE SIGNAL ;
    PORT
      LAYER M3 ;
        RECT  43.668 36.576 43.686 36.72 ;
    END
  END dq[322]
  PIN dq[323]
    DIRECTION OUTPUT ;
    USE SIGNAL ;
    PORT
      LAYER M5 ;
        RECT  43.824 36.528 43.848 36.72 ;
    END
  END dq[323]
  PIN dq[324]
    DIRECTION OUTPUT ;
    USE SIGNAL ;
    PORT
      LAYER M3 ;
        RECT  43.92 36.576 43.938 36.72 ;
    END
  END dq[324]
  PIN dq[325]
    DIRECTION OUTPUT ;
    USE SIGNAL ;
    PORT
      LAYER M5 ;
        RECT  44.064 36.528 44.088 36.72 ;
    END
  END dq[325]
  PIN dq[326]
    DIRECTION OUTPUT ;
    USE SIGNAL ;
    PORT
      LAYER M3 ;
        RECT  44.172 36.576 44.19 36.72 ;
    END
  END dq[326]
  PIN dq[327]
    DIRECTION OUTPUT ;
    USE SIGNAL ;
    PORT
      LAYER M5 ;
        RECT  44.304 36.528 44.328 36.72 ;
    END
  END dq[327]
  PIN dq[328]
    DIRECTION OUTPUT ;
    USE SIGNAL ;
    PORT
      LAYER M3 ;
        RECT  44.424 36.576 44.442 36.72 ;
    END
  END dq[328]
  PIN dq[329]
    DIRECTION OUTPUT ;
    USE SIGNAL ;
    PORT
      LAYER M5 ;
        RECT  44.544 36.528 44.568 36.72 ;
    END
  END dq[329]
  PIN dq[32]
    DIRECTION OUTPUT ;
    USE SIGNAL ;
    PORT
      LAYER M3 ;
        RECT  8.28 36.576 8.298 36.72 ;
    END
  END dq[32]
  PIN dq[330]
    DIRECTION OUTPUT ;
    USE SIGNAL ;
    PORT
      LAYER M3 ;
        RECT  44.676 36.576 44.694 36.72 ;
    END
  END dq[330]
  PIN dq[331]
    DIRECTION OUTPUT ;
    USE SIGNAL ;
    PORT
      LAYER M5 ;
        RECT  44.784 36.528 44.808 36.72 ;
    END
  END dq[331]
  PIN dq[332]
    DIRECTION OUTPUT ;
    USE SIGNAL ;
    PORT
      LAYER M3 ;
        RECT  44.892 36.576 44.91 36.72 ;
    END
  END dq[332]
  PIN dq[333]
    DIRECTION OUTPUT ;
    USE SIGNAL ;
    PORT
      LAYER M5 ;
        RECT  45.024 36.528 45.048 36.72 ;
    END
  END dq[333]
  PIN dq[334]
    DIRECTION OUTPUT ;
    USE SIGNAL ;
    PORT
      LAYER M3 ;
        RECT  45.144 36.576 45.162 36.72 ;
    END
  END dq[334]
  PIN dq[335]
    DIRECTION OUTPUT ;
    USE SIGNAL ;
    PORT
      LAYER M5 ;
        RECT  45.264 36.528 45.288 36.72 ;
    END
  END dq[335]
  PIN dq[336]
    DIRECTION OUTPUT ;
    USE SIGNAL ;
    PORT
      LAYER M3 ;
        RECT  45.396 36.576 45.414 36.72 ;
    END
  END dq[336]
  PIN dq[337]
    DIRECTION OUTPUT ;
    USE SIGNAL ;
    PORT
      LAYER M5 ;
        RECT  45.504 36.528 45.528 36.72 ;
    END
  END dq[337]
  PIN dq[338]
    DIRECTION OUTPUT ;
    USE SIGNAL ;
    PORT
      LAYER M3 ;
        RECT  45.648 36.576 45.666 36.72 ;
    END
  END dq[338]
  PIN dq[339]
    DIRECTION OUTPUT ;
    USE SIGNAL ;
    PORT
      LAYER M5 ;
        RECT  45.744 36.528 45.768 36.72 ;
    END
  END dq[339]
  PIN dq[33]
    DIRECTION OUTPUT ;
    USE SIGNAL ;
    PORT
      LAYER M5 ;
        RECT  8.4 36.528 8.424 36.72 ;
    END
  END dq[33]
  PIN dq[340]
    DIRECTION OUTPUT ;
    USE SIGNAL ;
    PORT
      LAYER M3 ;
        RECT  45.864 36.576 45.882 36.72 ;
    END
  END dq[340]
  PIN dq[341]
    DIRECTION OUTPUT ;
    USE SIGNAL ;
    PORT
      LAYER M5 ;
        RECT  45.984 36.528 46.008 36.72 ;
    END
  END dq[341]
  PIN dq[342]
    DIRECTION OUTPUT ;
    USE SIGNAL ;
    PORT
      LAYER M3 ;
        RECT  46.116 36.576 46.134 36.72 ;
    END
  END dq[342]
  PIN dq[343]
    DIRECTION OUTPUT ;
    USE SIGNAL ;
    PORT
      LAYER M5 ;
        RECT  46.224 36.528 46.248 36.72 ;
    END
  END dq[343]
  PIN dq[344]
    DIRECTION OUTPUT ;
    USE SIGNAL ;
    PORT
      LAYER M3 ;
        RECT  46.368 36.576 46.386 36.72 ;
    END
  END dq[344]
  PIN dq[345]
    DIRECTION OUTPUT ;
    USE SIGNAL ;
    PORT
      LAYER M5 ;
        RECT  46.512 36.528 46.536 36.72 ;
    END
  END dq[345]
  PIN dq[346]
    DIRECTION OUTPUT ;
    USE SIGNAL ;
    PORT
      LAYER M3 ;
        RECT  46.62 36.576 46.638 36.72 ;
    END
  END dq[346]
  PIN dq[347]
    DIRECTION OUTPUT ;
    USE SIGNAL ;
    PORT
      LAYER M5 ;
        RECT  46.752 36.528 46.776 36.72 ;
    END
  END dq[347]
  PIN dq[348]
    DIRECTION OUTPUT ;
    USE SIGNAL ;
    PORT
      LAYER M3 ;
        RECT  46.872 36.576 46.89 36.72 ;
    END
  END dq[348]
  PIN dq[349]
    DIRECTION OUTPUT ;
    USE SIGNAL ;
    PORT
      LAYER M5 ;
        RECT  46.992 36.528 47.016 36.72 ;
    END
  END dq[349]
  PIN dq[34]
    DIRECTION OUTPUT ;
    USE SIGNAL ;
    PORT
      LAYER M3 ;
        RECT  8.532 36.576 8.55 36.72 ;
    END
  END dq[34]
  PIN dq[350]
    DIRECTION OUTPUT ;
    USE SIGNAL ;
    PORT
      LAYER M3 ;
        RECT  47.088 36.576 47.106 36.72 ;
    END
  END dq[350]
  PIN dq[351]
    DIRECTION OUTPUT ;
    USE SIGNAL ;
    PORT
      LAYER M5 ;
        RECT  47.232 36.528 47.256 36.72 ;
    END
  END dq[351]
  PIN dq[352]
    DIRECTION OUTPUT ;
    USE SIGNAL ;
    PORT
      LAYER M3 ;
        RECT  47.34 36.576 47.358 36.72 ;
    END
  END dq[352]
  PIN dq[353]
    DIRECTION OUTPUT ;
    USE SIGNAL ;
    PORT
      LAYER M5 ;
        RECT  47.472 36.528 47.496 36.72 ;
    END
  END dq[353]
  PIN dq[354]
    DIRECTION OUTPUT ;
    USE SIGNAL ;
    PORT
      LAYER M3 ;
        RECT  47.592 36.576 47.61 36.72 ;
    END
  END dq[354]
  PIN dq[355]
    DIRECTION OUTPUT ;
    USE SIGNAL ;
    PORT
      LAYER M5 ;
        RECT  47.712 36.528 47.736 36.72 ;
    END
  END dq[355]
  PIN dq[356]
    DIRECTION OUTPUT ;
    USE SIGNAL ;
    PORT
      LAYER M3 ;
        RECT  47.844 36.576 47.862 36.72 ;
    END
  END dq[356]
  PIN dq[357]
    DIRECTION OUTPUT ;
    USE SIGNAL ;
    PORT
      LAYER M5 ;
        RECT  47.952 36.528 47.976 36.72 ;
    END
  END dq[357]
  PIN dq[358]
    DIRECTION OUTPUT ;
    USE SIGNAL ;
    PORT
      LAYER M3 ;
        RECT  48.096 36.576 48.114 36.72 ;
    END
  END dq[358]
  PIN dq[359]
    DIRECTION OUTPUT ;
    USE SIGNAL ;
    PORT
      LAYER M5 ;
        RECT  48.192 36.528 48.216 36.72 ;
    END
  END dq[359]
  PIN dq[35]
    DIRECTION OUTPUT ;
    USE SIGNAL ;
    PORT
      LAYER M5 ;
        RECT  8.64 36.528 8.664 36.72 ;
    END
  END dq[35]
  PIN dq[360]
    DIRECTION OUTPUT ;
    USE SIGNAL ;
    PORT
      LAYER M3 ;
        RECT  48.312 36.576 48.33 36.72 ;
    END
  END dq[360]
  PIN dq[361]
    DIRECTION OUTPUT ;
    USE SIGNAL ;
    PORT
      LAYER M5 ;
        RECT  48.432 36.528 48.456 36.72 ;
    END
  END dq[361]
  PIN dq[362]
    DIRECTION OUTPUT ;
    USE SIGNAL ;
    PORT
      LAYER M3 ;
        RECT  48.564 36.576 48.582 36.72 ;
    END
  END dq[362]
  PIN dq[363]
    DIRECTION OUTPUT ;
    USE SIGNAL ;
    PORT
      LAYER M5 ;
        RECT  48.672 36.528 48.696 36.72 ;
    END
  END dq[363]
  PIN dq[364]
    DIRECTION OUTPUT ;
    USE SIGNAL ;
    PORT
      LAYER M3 ;
        RECT  48.816 36.576 48.834 36.72 ;
    END
  END dq[364]
  PIN dq[365]
    DIRECTION OUTPUT ;
    USE SIGNAL ;
    PORT
      LAYER M5 ;
        RECT  48.912 36.528 48.936 36.72 ;
    END
  END dq[365]
  PIN dq[366]
    DIRECTION OUTPUT ;
    USE SIGNAL ;
    PORT
      LAYER M3 ;
        RECT  49.068 36.576 49.086 36.72 ;
    END
  END dq[366]
  PIN dq[367]
    DIRECTION OUTPUT ;
    USE SIGNAL ;
    PORT
      LAYER M5 ;
        RECT  49.152 36.528 49.176 36.72 ;
    END
  END dq[367]
  PIN dq[368]
    DIRECTION OUTPUT ;
    USE SIGNAL ;
    PORT
      LAYER M3 ;
        RECT  49.284 36.576 49.302 36.72 ;
    END
  END dq[368]
  PIN dq[369]
    DIRECTION OUTPUT ;
    USE SIGNAL ;
    PORT
      LAYER M5 ;
        RECT  49.44 36.528 49.464 36.72 ;
    END
  END dq[369]
  PIN dq[36]
    DIRECTION OUTPUT ;
    USE SIGNAL ;
    PORT
      LAYER M3 ;
        RECT  8.784 36.576 8.802 36.72 ;
    END
  END dq[36]
  PIN dq[370]
    DIRECTION OUTPUT ;
    USE SIGNAL ;
    PORT
      LAYER M3 ;
        RECT  49.536 36.576 49.554 36.72 ;
    END
  END dq[370]
  PIN dq[371]
    DIRECTION OUTPUT ;
    USE SIGNAL ;
    PORT
      LAYER M5 ;
        RECT  49.68 36.528 49.704 36.72 ;
    END
  END dq[371]
  PIN dq[372]
    DIRECTION OUTPUT ;
    USE SIGNAL ;
    PORT
      LAYER M3 ;
        RECT  49.788 36.576 49.806 36.72 ;
    END
  END dq[372]
  PIN dq[373]
    DIRECTION OUTPUT ;
    USE SIGNAL ;
    PORT
      LAYER M5 ;
        RECT  49.92 36.528 49.944 36.72 ;
    END
  END dq[373]
  PIN dq[374]
    DIRECTION OUTPUT ;
    USE SIGNAL ;
    PORT
      LAYER M3 ;
        RECT  50.04 36.576 50.058 36.72 ;
    END
  END dq[374]
  PIN dq[375]
    DIRECTION OUTPUT ;
    USE SIGNAL ;
    PORT
      LAYER M5 ;
        RECT  50.16 36.528 50.184 36.72 ;
    END
  END dq[375]
  PIN dq[376]
    DIRECTION OUTPUT ;
    USE SIGNAL ;
    PORT
      LAYER M3 ;
        RECT  50.292 36.576 50.31 36.72 ;
    END
  END dq[376]
  PIN dq[377]
    DIRECTION OUTPUT ;
    USE SIGNAL ;
    PORT
      LAYER M5 ;
        RECT  50.4 36.528 50.424 36.72 ;
    END
  END dq[377]
  PIN dq[378]
    DIRECTION OUTPUT ;
    USE SIGNAL ;
    PORT
      LAYER M3 ;
        RECT  50.508 36.576 50.526 36.72 ;
    END
  END dq[378]
  PIN dq[379]
    DIRECTION OUTPUT ;
    USE SIGNAL ;
    PORT
      LAYER M5 ;
        RECT  50.64 36.528 50.664 36.72 ;
    END
  END dq[379]
  PIN dq[37]
    DIRECTION OUTPUT ;
    USE SIGNAL ;
    PORT
      LAYER M5 ;
        RECT  8.88 36.528 8.904 36.72 ;
    END
  END dq[37]
  PIN dq[380]
    DIRECTION OUTPUT ;
    USE SIGNAL ;
    PORT
      LAYER M3 ;
        RECT  50.76 36.576 50.778 36.72 ;
    END
  END dq[380]
  PIN dq[381]
    DIRECTION OUTPUT ;
    USE SIGNAL ;
    PORT
      LAYER M5 ;
        RECT  50.88 36.528 50.904 36.72 ;
    END
  END dq[381]
  PIN dq[382]
    DIRECTION OUTPUT ;
    USE SIGNAL ;
    PORT
      LAYER M3 ;
        RECT  51.012 36.576 51.03 36.72 ;
    END
  END dq[382]
  PIN dq[383]
    DIRECTION OUTPUT ;
    USE SIGNAL ;
    PORT
      LAYER M5 ;
        RECT  51.12 36.528 51.144 36.72 ;
    END
  END dq[383]
  PIN dq[384]
    DIRECTION OUTPUT ;
    USE SIGNAL ;
    PORT
      LAYER M3 ;
        RECT  51.264 36.576 51.282 36.72 ;
    END
  END dq[384]
  PIN dq[385]
    DIRECTION OUTPUT ;
    USE SIGNAL ;
    PORT
      LAYER M5 ;
        RECT  51.36 36.528 51.384 36.72 ;
    END
  END dq[385]
  PIN dq[386]
    DIRECTION OUTPUT ;
    USE SIGNAL ;
    PORT
      LAYER M3 ;
        RECT  51.48 36.576 51.498 36.72 ;
    END
  END dq[386]
  PIN dq[387]
    DIRECTION OUTPUT ;
    USE SIGNAL ;
    PORT
      LAYER M5 ;
        RECT  51.6 36.528 51.624 36.72 ;
    END
  END dq[387]
  PIN dq[388]
    DIRECTION OUTPUT ;
    USE SIGNAL ;
    PORT
      LAYER M3 ;
        RECT  51.732 36.576 51.75 36.72 ;
    END
  END dq[388]
  PIN dq[389]
    DIRECTION OUTPUT ;
    USE SIGNAL ;
    PORT
      LAYER M5 ;
        RECT  51.84 36.528 51.864 36.72 ;
    END
  END dq[389]
  PIN dq[38]
    DIRECTION OUTPUT ;
    USE SIGNAL ;
    PORT
      LAYER M3 ;
        RECT  9 36.576 9.018 36.72 ;
    END
  END dq[38]
  PIN dq[390]
    DIRECTION OUTPUT ;
    USE SIGNAL ;
    PORT
      LAYER M3 ;
        RECT  51.984 36.576 52.002 36.72 ;
    END
  END dq[390]
  PIN dq[391]
    DIRECTION OUTPUT ;
    USE SIGNAL ;
    PORT
      LAYER M5 ;
        RECT  52.128 36.528 52.152 36.72 ;
    END
  END dq[391]
  PIN dq[392]
    DIRECTION OUTPUT ;
    USE SIGNAL ;
    PORT
      LAYER M3 ;
        RECT  52.236 36.576 52.254 36.72 ;
    END
  END dq[392]
  PIN dq[393]
    DIRECTION OUTPUT ;
    USE SIGNAL ;
    PORT
      LAYER M5 ;
        RECT  52.368 36.528 52.392 36.72 ;
    END
  END dq[393]
  PIN dq[394]
    DIRECTION OUTPUT ;
    USE SIGNAL ;
    PORT
      LAYER M3 ;
        RECT  52.488 36.576 52.506 36.72 ;
    END
  END dq[394]
  PIN dq[395]
    DIRECTION OUTPUT ;
    USE SIGNAL ;
    PORT
      LAYER M5 ;
        RECT  52.608 36.528 52.632 36.72 ;
    END
  END dq[395]
  PIN dq[396]
    DIRECTION OUTPUT ;
    USE SIGNAL ;
    PORT
      LAYER M3 ;
        RECT  52.704 36.576 52.722 36.72 ;
    END
  END dq[396]
  PIN dq[397]
    DIRECTION OUTPUT ;
    USE SIGNAL ;
    PORT
      LAYER M5 ;
        RECT  52.848 36.528 52.872 36.72 ;
    END
  END dq[397]
  PIN dq[398]
    DIRECTION OUTPUT ;
    USE SIGNAL ;
    PORT
      LAYER M3 ;
        RECT  52.956 36.576 52.974 36.72 ;
    END
  END dq[398]
  PIN dq[399]
    DIRECTION OUTPUT ;
    USE SIGNAL ;
    PORT
      LAYER M5 ;
        RECT  53.088 36.528 53.112 36.72 ;
    END
  END dq[399]
  PIN dq[39]
    DIRECTION OUTPUT ;
    USE SIGNAL ;
    PORT
      LAYER M5 ;
        RECT  9.12 36.528 9.144 36.72 ;
    END
  END dq[39]
  PIN dq[3]
    DIRECTION OUTPUT ;
    USE SIGNAL ;
    PORT
      LAYER M5 ;
        RECT  4.752 36.528 4.776 36.72 ;
    END
  END dq[3]
  PIN dq[400]
    DIRECTION OUTPUT ;
    USE SIGNAL ;
    PORT
      LAYER M3 ;
        RECT  53.208 36.576 53.226 36.72 ;
    END
  END dq[400]
  PIN dq[401]
    DIRECTION OUTPUT ;
    USE SIGNAL ;
    PORT
      LAYER M5 ;
        RECT  53.328 36.528 53.352 36.72 ;
    END
  END dq[401]
  PIN dq[402]
    DIRECTION OUTPUT ;
    USE SIGNAL ;
    PORT
      LAYER M3 ;
        RECT  53.46 36.576 53.478 36.72 ;
    END
  END dq[402]
  PIN dq[403]
    DIRECTION OUTPUT ;
    USE SIGNAL ;
    PORT
      LAYER M5 ;
        RECT  53.568 36.528 53.592 36.72 ;
    END
  END dq[403]
  PIN dq[404]
    DIRECTION OUTPUT ;
    USE SIGNAL ;
    PORT
      LAYER M3 ;
        RECT  53.712 36.576 53.73 36.72 ;
    END
    PORT
      LAYER M3 ;
        RECT  53.676 36.588 53.802 36.653 ;
    END
  END dq[404]
  PIN dq[405]
    DIRECTION OUTPUT ;
    USE SIGNAL ;
    PORT
      LAYER M5 ;
        RECT  53.808 36.528 53.832 36.72 ;
    END
  END dq[405]
  PIN dq[406]
    DIRECTION OUTPUT ;
    USE SIGNAL ;
    PORT
      LAYER M3 ;
        RECT  53.928 36.576 53.946 36.72 ;
    END
  END dq[406]
  PIN dq[407]
    DIRECTION OUTPUT ;
    USE SIGNAL ;
    PORT
      LAYER M5 ;
        RECT  54.048 36.528 54.072 36.72 ;
    END
  END dq[407]
  PIN dq[408]
    DIRECTION OUTPUT ;
    USE SIGNAL ;
    PORT
      LAYER M3 ;
        RECT  54.18 36.576 54.198 36.72 ;
    END
  END dq[408]
  PIN dq[409]
    DIRECTION OUTPUT ;
    USE SIGNAL ;
    PORT
      LAYER M5 ;
        RECT  54.288 36.528 54.312 36.72 ;
    END
  END dq[409]
  PIN dq[40]
    DIRECTION OUTPUT ;
    USE SIGNAL ;
    PORT
      LAYER M3 ;
        RECT  9.252 36.576 9.27 36.72 ;
    END
  END dq[40]
  PIN dq[410]
    DIRECTION OUTPUT ;
    USE SIGNAL ;
    PORT
      LAYER M3 ;
        RECT  54.432 36.576 54.45 36.72 ;
    END
  END dq[410]
  PIN dq[411]
    DIRECTION OUTPUT ;
    USE SIGNAL ;
    PORT
      LAYER M5 ;
        RECT  54.528 36.528 54.552 36.72 ;
    END
  END dq[411]
  PIN dq[412]
    DIRECTION OUTPUT ;
    USE SIGNAL ;
    PORT
      LAYER M3 ;
        RECT  54.684 36.576 54.702 36.72 ;
    END
  END dq[412]
  PIN dq[413]
    DIRECTION OUTPUT ;
    USE SIGNAL ;
    PORT
      LAYER M5 ;
        RECT  54.768 36.528 54.792 36.72 ;
    END
  END dq[413]
  PIN dq[414]
    DIRECTION OUTPUT ;
    USE SIGNAL ;
    PORT
      LAYER M3 ;
        RECT  54.9 36.576 54.918 36.72 ;
    END
  END dq[414]
  PIN dq[415]
    DIRECTION OUTPUT ;
    USE SIGNAL ;
    PORT
      LAYER M5 ;
        RECT  55.056 36.528 55.08 36.72 ;
    END
  END dq[415]
  PIN dq[416]
    DIRECTION OUTPUT ;
    USE SIGNAL ;
    PORT
      LAYER M3 ;
        RECT  55.152 36.576 55.17 36.72 ;
    END
  END dq[416]
  PIN dq[417]
    DIRECTION OUTPUT ;
    USE SIGNAL ;
    PORT
      LAYER M5 ;
        RECT  55.296 36.528 55.32 36.72 ;
    END
  END dq[417]
  PIN dq[418]
    DIRECTION OUTPUT ;
    USE SIGNAL ;
    PORT
      LAYER M3 ;
        RECT  55.404 36.576 55.422 36.72 ;
    END
  END dq[418]
  PIN dq[419]
    DIRECTION OUTPUT ;
    USE SIGNAL ;
    PORT
      LAYER M5 ;
        RECT  55.536 36.528 55.56 36.72 ;
    END
  END dq[419]
  PIN dq[41]
    DIRECTION OUTPUT ;
    USE SIGNAL ;
    PORT
      LAYER M5 ;
        RECT  9.36 36.528 9.384 36.72 ;
    END
  END dq[41]
  PIN dq[420]
    DIRECTION OUTPUT ;
    USE SIGNAL ;
    PORT
      LAYER M3 ;
        RECT  55.656 36.576 55.674 36.72 ;
    END
  END dq[420]
  PIN dq[421]
    DIRECTION OUTPUT ;
    USE SIGNAL ;
    PORT
      LAYER M5 ;
        RECT  55.776 36.528 55.8 36.72 ;
    END
  END dq[421]
  PIN dq[422]
    DIRECTION OUTPUT ;
    USE SIGNAL ;
    PORT
      LAYER M3 ;
        RECT  55.908 36.576 55.926 36.72 ;
    END
  END dq[422]
  PIN dq[423]
    DIRECTION OUTPUT ;
    USE SIGNAL ;
    PORT
      LAYER M5 ;
        RECT  56.016 36.528 56.04 36.72 ;
    END
  END dq[423]
  PIN dq[424]
    DIRECTION OUTPUT ;
    USE SIGNAL ;
    PORT
      LAYER M3 ;
        RECT  56.124 36.576 56.142 36.72 ;
    END
  END dq[424]
  PIN dq[425]
    DIRECTION OUTPUT ;
    USE SIGNAL ;
    PORT
      LAYER M5 ;
        RECT  56.256 36.528 56.28 36.72 ;
    END
  END dq[425]
  PIN dq[426]
    DIRECTION OUTPUT ;
    USE SIGNAL ;
    PORT
      LAYER M3 ;
        RECT  56.376 36.576 56.394 36.72 ;
    END
  END dq[426]
  PIN dq[427]
    DIRECTION OUTPUT ;
    USE SIGNAL ;
    PORT
      LAYER M5 ;
        RECT  56.496 36.528 56.52 36.72 ;
    END
  END dq[427]
  PIN dq[428]
    DIRECTION OUTPUT ;
    USE SIGNAL ;
    PORT
      LAYER M3 ;
        RECT  56.628 36.576 56.646 36.72 ;
    END
  END dq[428]
  PIN dq[429]
    DIRECTION OUTPUT ;
    USE SIGNAL ;
    PORT
      LAYER M5 ;
        RECT  56.736 36.528 56.76 36.72 ;
    END
  END dq[429]
  PIN dq[42]
    DIRECTION OUTPUT ;
    USE SIGNAL ;
    PORT
      LAYER M3 ;
        RECT  9.504 36.576 9.522 36.72 ;
    END
  END dq[42]
  PIN dq[430]
    DIRECTION OUTPUT ;
    USE SIGNAL ;
    PORT
      LAYER M3 ;
        RECT  56.88 36.576 56.898 36.72 ;
    END
  END dq[430]
  PIN dq[431]
    DIRECTION OUTPUT ;
    USE SIGNAL ;
    PORT
      LAYER M5 ;
        RECT  56.976 36.528 57 36.72 ;
    END
  END dq[431]
  PIN dq[432]
    DIRECTION OUTPUT ;
    USE SIGNAL ;
    PORT
      LAYER M3 ;
        RECT  57.096 36.576 57.114 36.72 ;
    END
  END dq[432]
  PIN dq[433]
    DIRECTION OUTPUT ;
    USE SIGNAL ;
    PORT
      LAYER M5 ;
        RECT  57.216 36.528 57.24 36.72 ;
    END
  END dq[433]
  PIN dq[434]
    DIRECTION OUTPUT ;
    USE SIGNAL ;
    PORT
      LAYER M3 ;
        RECT  57.348 36.576 57.366 36.72 ;
    END
  END dq[434]
  PIN dq[435]
    DIRECTION OUTPUT ;
    USE SIGNAL ;
    PORT
      LAYER M5 ;
        RECT  57.456 36.528 57.48 36.72 ;
    END
  END dq[435]
  PIN dq[436]
    DIRECTION OUTPUT ;
    USE SIGNAL ;
    PORT
      LAYER M3 ;
        RECT  57.6 36.576 57.618 36.72 ;
    END
  END dq[436]
  PIN dq[437]
    DIRECTION OUTPUT ;
    USE SIGNAL ;
    PORT
      LAYER M5 ;
        RECT  57.744 36.528 57.768 36.72 ;
    END
  END dq[437]
  PIN dq[438]
    DIRECTION OUTPUT ;
    USE SIGNAL ;
    PORT
      LAYER M3 ;
        RECT  57.852 36.576 57.87 36.72 ;
    END
  END dq[438]
  PIN dq[439]
    DIRECTION OUTPUT ;
    USE SIGNAL ;
    PORT
      LAYER M5 ;
        RECT  57.984 36.528 58.008 36.72 ;
    END
  END dq[439]
  PIN dq[43]
    DIRECTION OUTPUT ;
    USE SIGNAL ;
    PORT
      LAYER M5 ;
        RECT  9.6 36.528 9.624 36.72 ;
    END
  END dq[43]
  PIN dq[440]
    DIRECTION OUTPUT ;
    USE SIGNAL ;
    PORT
      LAYER M3 ;
        RECT  58.104 36.576 58.122 36.72 ;
    END
  END dq[440]
  PIN dq[441]
    DIRECTION OUTPUT ;
    USE SIGNAL ;
    PORT
      LAYER M5 ;
        RECT  58.224 36.528 58.248 36.72 ;
    END
  END dq[441]
  PIN dq[442]
    DIRECTION OUTPUT ;
    USE SIGNAL ;
    PORT
      LAYER M3 ;
        RECT  58.32 36.576 58.338 36.72 ;
    END
  END dq[442]
  PIN dq[443]
    DIRECTION OUTPUT ;
    USE SIGNAL ;
    PORT
      LAYER M5 ;
        RECT  58.464 36.528 58.488 36.72 ;
    END
  END dq[443]
  PIN dq[444]
    DIRECTION OUTPUT ;
    USE SIGNAL ;
    PORT
      LAYER M3 ;
        RECT  58.572 36.576 58.59 36.72 ;
    END
  END dq[444]
  PIN dq[445]
    DIRECTION OUTPUT ;
    USE SIGNAL ;
    PORT
      LAYER M5 ;
        RECT  58.704 36.528 58.728 36.72 ;
    END
  END dq[445]
  PIN dq[446]
    DIRECTION OUTPUT ;
    USE SIGNAL ;
    PORT
      LAYER M3 ;
        RECT  58.824 36.576 58.842 36.72 ;
    END
  END dq[446]
  PIN dq[447]
    DIRECTION OUTPUT ;
    USE SIGNAL ;
    PORT
      LAYER M5 ;
        RECT  58.944 36.528 58.968 36.72 ;
    END
  END dq[447]
  PIN dq[448]
    DIRECTION OUTPUT ;
    USE SIGNAL ;
    PORT
      LAYER M3 ;
        RECT  59.076 36.576 59.094 36.72 ;
    END
  END dq[448]
  PIN dq[449]
    DIRECTION OUTPUT ;
    USE SIGNAL ;
    PORT
      LAYER M5 ;
        RECT  59.184 36.528 59.208 36.72 ;
    END
  END dq[449]
  PIN dq[44]
    DIRECTION OUTPUT ;
    USE SIGNAL ;
    PORT
      LAYER M3 ;
        RECT  9.756 36.576 9.774 36.72 ;
    END
  END dq[44]
  PIN dq[450]
    DIRECTION OUTPUT ;
    USE SIGNAL ;
    PORT
      LAYER M3 ;
        RECT  59.328 36.576 59.346 36.72 ;
    END
  END dq[450]
  PIN dq[451]
    DIRECTION OUTPUT ;
    USE SIGNAL ;
    PORT
      LAYER M5 ;
        RECT  59.424 36.528 59.448 36.72 ;
    END
  END dq[451]
  PIN dq[452]
    DIRECTION OUTPUT ;
    USE SIGNAL ;
    PORT
      LAYER M3 ;
        RECT  59.544 36.576 59.562 36.72 ;
    END
  END dq[452]
  PIN dq[453]
    DIRECTION OUTPUT ;
    USE SIGNAL ;
    PORT
      LAYER M5 ;
        RECT  59.664 36.528 59.688 36.72 ;
    END
  END dq[453]
  PIN dq[454]
    DIRECTION OUTPUT ;
    USE SIGNAL ;
    PORT
      LAYER M3 ;
        RECT  59.796 36.576 59.814 36.72 ;
    END
  END dq[454]
  PIN dq[455]
    DIRECTION OUTPUT ;
    USE SIGNAL ;
    PORT
      LAYER M5 ;
        RECT  59.904 36.528 59.928 36.72 ;
    END
  END dq[455]
  PIN dq[456]
    DIRECTION OUTPUT ;
    USE SIGNAL ;
    PORT
      LAYER M3 ;
        RECT  60.048 36.576 60.066 36.72 ;
    END
  END dq[456]
  PIN dq[457]
    DIRECTION OUTPUT ;
    USE SIGNAL ;
    PORT
      LAYER M5 ;
        RECT  60.144 36.528 60.168 36.72 ;
    END
  END dq[457]
  PIN dq[458]
    DIRECTION OUTPUT ;
    USE SIGNAL ;
    PORT
      LAYER M3 ;
        RECT  60.3 36.576 60.318 36.72 ;
    END
  END dq[458]
  PIN dq[459]
    DIRECTION OUTPUT ;
    USE SIGNAL ;
    PORT
      LAYER M5 ;
        RECT  60.384 36.528 60.408 36.72 ;
    END
  END dq[459]
  PIN dq[45]
    DIRECTION OUTPUT ;
    USE SIGNAL ;
    PORT
      LAYER M5 ;
        RECT  9.84 36.528 9.864 36.72 ;
    END
  END dq[45]
  PIN dq[460]
    DIRECTION OUTPUT ;
    USE SIGNAL ;
    PORT
      LAYER M3 ;
        RECT  60.516 36.576 60.534 36.72 ;
    END
  END dq[460]
  PIN dq[461]
    DIRECTION OUTPUT ;
    USE SIGNAL ;
    PORT
      LAYER M5 ;
        RECT  60.672 36.528 60.696 36.72 ;
    END
  END dq[461]
  PIN dq[462]
    DIRECTION OUTPUT ;
    USE SIGNAL ;
    PORT
      LAYER M3 ;
        RECT  60.768 36.576 60.786 36.72 ;
    END
  END dq[462]
  PIN dq[463]
    DIRECTION OUTPUT ;
    USE SIGNAL ;
    PORT
      LAYER M5 ;
        RECT  60.912 36.528 60.936 36.72 ;
    END
  END dq[463]
  PIN dq[464]
    DIRECTION OUTPUT ;
    USE SIGNAL ;
    PORT
      LAYER M3 ;
        RECT  61.02 36.576 61.038 36.72 ;
    END
  END dq[464]
  PIN dq[465]
    DIRECTION OUTPUT ;
    USE SIGNAL ;
    PORT
      LAYER M5 ;
        RECT  61.152 36.528 61.176 36.72 ;
    END
  END dq[465]
  PIN dq[466]
    DIRECTION OUTPUT ;
    USE SIGNAL ;
    PORT
      LAYER M3 ;
        RECT  61.272 36.576 61.29 36.72 ;
    END
  END dq[466]
  PIN dq[467]
    DIRECTION OUTPUT ;
    USE SIGNAL ;
    PORT
      LAYER M5 ;
        RECT  61.392 36.528 61.416 36.72 ;
    END
  END dq[467]
  PIN dq[468]
    DIRECTION OUTPUT ;
    USE SIGNAL ;
    PORT
      LAYER M3 ;
        RECT  61.524 36.576 61.542 36.72 ;
    END
  END dq[468]
  PIN dq[469]
    DIRECTION OUTPUT ;
    USE SIGNAL ;
    PORT
      LAYER M5 ;
        RECT  61.632 36.528 61.656 36.72 ;
    END
  END dq[469]
  PIN dq[46]
    DIRECTION OUTPUT ;
    USE SIGNAL ;
    PORT
      LAYER M3 ;
        RECT  9.972 36.576 9.99 36.72 ;
    END
  END dq[46]
  PIN dq[470]
    DIRECTION OUTPUT ;
    USE SIGNAL ;
    PORT
      LAYER M3 ;
        RECT  61.74 36.576 61.758 36.72 ;
    END
  END dq[470]
  PIN dq[471]
    DIRECTION OUTPUT ;
    USE SIGNAL ;
    PORT
      LAYER M5 ;
        RECT  61.872 36.528 61.896 36.72 ;
    END
  END dq[471]
  PIN dq[472]
    DIRECTION OUTPUT ;
    USE SIGNAL ;
    PORT
      LAYER M3 ;
        RECT  61.992 36.576 62.01 36.72 ;
    END
  END dq[472]
  PIN dq[473]
    DIRECTION OUTPUT ;
    USE SIGNAL ;
    PORT
      LAYER M5 ;
        RECT  62.112 36.528 62.136 36.72 ;
    END
  END dq[473]
  PIN dq[474]
    DIRECTION OUTPUT ;
    USE SIGNAL ;
    PORT
      LAYER M3 ;
        RECT  62.244 36.576 62.262 36.72 ;
    END
  END dq[474]
  PIN dq[475]
    DIRECTION OUTPUT ;
    USE SIGNAL ;
    PORT
      LAYER M5 ;
        RECT  62.352 36.528 62.376 36.72 ;
    END
  END dq[475]
  PIN dq[476]
    DIRECTION OUTPUT ;
    USE SIGNAL ;
    PORT
      LAYER M3 ;
        RECT  62.496 36.576 62.514 36.72 ;
    END
  END dq[476]
  PIN dq[477]
    DIRECTION OUTPUT ;
    USE SIGNAL ;
    PORT
      LAYER M5 ;
        RECT  62.592 36.528 62.616 36.72 ;
    END
  END dq[477]
  PIN dq[478]
    DIRECTION OUTPUT ;
    USE SIGNAL ;
    PORT
      LAYER M3 ;
        RECT  62.712 36.576 62.73 36.72 ;
    END
  END dq[478]
  PIN dq[479]
    DIRECTION OUTPUT ;
    USE SIGNAL ;
    PORT
      LAYER M5 ;
        RECT  62.832 36.528 62.856 36.72 ;
    END
  END dq[479]
  PIN dq[47]
    DIRECTION OUTPUT ;
    USE SIGNAL ;
    PORT
      LAYER M5 ;
        RECT  10.128 36.528 10.152 36.72 ;
    END
  END dq[47]
  PIN dq[480]
    DIRECTION OUTPUT ;
    USE SIGNAL ;
    PORT
      LAYER M3 ;
        RECT  62.964 36.576 62.982 36.72 ;
    END
  END dq[480]
  PIN dq[481]
    DIRECTION OUTPUT ;
    USE SIGNAL ;
    PORT
      LAYER M5 ;
        RECT  63.072 36.528 63.096 36.72 ;
    END
  END dq[481]
  PIN dq[482]
    DIRECTION OUTPUT ;
    USE SIGNAL ;
    PORT
      LAYER M3 ;
        RECT  63.216 36.576 63.234 36.72 ;
    END
  END dq[482]
  PIN dq[483]
    DIRECTION OUTPUT ;
    USE SIGNAL ;
    PORT
      LAYER M5 ;
        RECT  63.36 36.528 63.384 36.72 ;
    END
  END dq[483]
  PIN dq[484]
    DIRECTION OUTPUT ;
    USE SIGNAL ;
    PORT
      LAYER M3 ;
        RECT  63.468 36.576 63.486 36.72 ;
    END
  END dq[484]
  PIN dq[485]
    DIRECTION OUTPUT ;
    USE SIGNAL ;
    PORT
      LAYER M5 ;
        RECT  63.6 36.528 63.624 36.72 ;
    END
  END dq[485]
  PIN dq[486]
    DIRECTION OUTPUT ;
    USE SIGNAL ;
    PORT
      LAYER M3 ;
        RECT  63.72 36.576 63.738 36.72 ;
    END
  END dq[486]
  PIN dq[487]
    DIRECTION OUTPUT ;
    USE SIGNAL ;
    PORT
      LAYER M5 ;
        RECT  63.84 36.528 63.864 36.72 ;
    END
  END dq[487]
  PIN dq[488]
    DIRECTION OUTPUT ;
    USE SIGNAL ;
    PORT
      LAYER M3 ;
        RECT  63.936 36.576 63.954 36.72 ;
    END
  END dq[488]
  PIN dq[489]
    DIRECTION OUTPUT ;
    USE SIGNAL ;
    PORT
      LAYER M5 ;
        RECT  64.08 36.528 64.104 36.72 ;
    END
  END dq[489]
  PIN dq[48]
    DIRECTION OUTPUT ;
    USE SIGNAL ;
    PORT
      LAYER M3 ;
        RECT  10.224 36.576 10.242 36.72 ;
    END
  END dq[48]
  PIN dq[490]
    DIRECTION OUTPUT ;
    USE SIGNAL ;
    PORT
      LAYER M3 ;
        RECT  64.188 36.576 64.206 36.72 ;
    END
  END dq[490]
  PIN dq[491]
    DIRECTION OUTPUT ;
    USE SIGNAL ;
    PORT
      LAYER M5 ;
        RECT  64.32 36.528 64.344 36.72 ;
    END
  END dq[491]
  PIN dq[492]
    DIRECTION OUTPUT ;
    USE SIGNAL ;
    PORT
      LAYER M3 ;
        RECT  64.44 36.576 64.458 36.72 ;
    END
  END dq[492]
  PIN dq[493]
    DIRECTION OUTPUT ;
    USE SIGNAL ;
    PORT
      LAYER M5 ;
        RECT  64.56 36.528 64.584 36.72 ;
    END
  END dq[493]
  PIN dq[494]
    DIRECTION OUTPUT ;
    USE SIGNAL ;
    PORT
      LAYER M3 ;
        RECT  64.692 36.576 64.71 36.72 ;
    END
  END dq[494]
  PIN dq[495]
    DIRECTION OUTPUT ;
    USE SIGNAL ;
    PORT
      LAYER M5 ;
        RECT  64.8 36.528 64.824 36.72 ;
    END
  END dq[495]
  PIN dq[496]
    DIRECTION OUTPUT ;
    USE SIGNAL ;
    PORT
      LAYER M3 ;
        RECT  64.944 36.576 64.962 36.72 ;
    END
  END dq[496]
  PIN dq[497]
    DIRECTION OUTPUT ;
    USE SIGNAL ;
    PORT
      LAYER M5 ;
        RECT  65.04 36.528 65.064 36.72 ;
    END
  END dq[497]
  PIN dq[498]
    DIRECTION OUTPUT ;
    USE SIGNAL ;
    PORT
      LAYER M3 ;
        RECT  65.16 36.576 65.178 36.72 ;
    END
  END dq[498]
  PIN dq[499]
    DIRECTION OUTPUT ;
    USE SIGNAL ;
    PORT
      LAYER M5 ;
        RECT  65.28 36.528 65.304 36.72 ;
    END
  END dq[499]
  PIN dq[49]
    DIRECTION OUTPUT ;
    USE SIGNAL ;
    PORT
      LAYER M5 ;
        RECT  10.368 36.528 10.392 36.72 ;
    END
  END dq[49]
  PIN dq[4]
    DIRECTION OUTPUT ;
    USE SIGNAL ;
    PORT
      LAYER M3 ;
        RECT  4.86 36.576 4.878 36.72 ;
    END
  END dq[4]
  PIN dq[500]
    DIRECTION OUTPUT ;
    USE SIGNAL ;
    PORT
      LAYER M3 ;
        RECT  65.412 36.576 65.43 36.72 ;
    END
  END dq[500]
  PIN dq[501]
    DIRECTION OUTPUT ;
    USE SIGNAL ;
    PORT
      LAYER M5 ;
        RECT  65.52 36.528 65.544 36.72 ;
    END
  END dq[501]
  PIN dq[502]
    DIRECTION OUTPUT ;
    USE SIGNAL ;
    PORT
      LAYER M3 ;
        RECT  65.664 36.576 65.682 36.72 ;
    END
  END dq[502]
  PIN dq[503]
    DIRECTION OUTPUT ;
    USE SIGNAL ;
    PORT
      LAYER M5 ;
        RECT  65.76 36.528 65.784 36.72 ;
    END
  END dq[503]
  PIN dq[504]
    DIRECTION OUTPUT ;
    USE SIGNAL ;
    PORT
      LAYER M3 ;
        RECT  65.916 36.576 65.934 36.72 ;
    END
  END dq[504]
  PIN dq[505]
    DIRECTION OUTPUT ;
    USE SIGNAL ;
    PORT
      LAYER M5 ;
        RECT  66 36.528 66.024 36.72 ;
    END
  END dq[505]
  PIN dq[506]
    DIRECTION OUTPUT ;
    USE SIGNAL ;
    PORT
      LAYER M3 ;
        RECT  66.132 36.576 66.15 36.72 ;
    END
  END dq[506]
  PIN dq[507]
    DIRECTION OUTPUT ;
    USE SIGNAL ;
    PORT
      LAYER M5 ;
        RECT  66.288 36.528 66.312 36.72 ;
    END
  END dq[507]
  PIN dq[508]
    DIRECTION OUTPUT ;
    USE SIGNAL ;
    PORT
      LAYER M3 ;
        RECT  66.384 36.576 66.402 36.72 ;
    END
  END dq[508]
  PIN dq[509]
    DIRECTION OUTPUT ;
    USE SIGNAL ;
    PORT
      LAYER M5 ;
        RECT  66.528 36.528 66.552 36.72 ;
    END
  END dq[509]
  PIN dq[50]
    DIRECTION OUTPUT ;
    USE SIGNAL ;
    PORT
      LAYER M3 ;
        RECT  10.476 36.576 10.494 36.72 ;
    END
  END dq[50]
  PIN dq[510]
    DIRECTION OUTPUT ;
    USE SIGNAL ;
    PORT
      LAYER M3 ;
        RECT  66.636 36.576 66.654 36.72 ;
    END
  END dq[510]
  PIN dq[511]
    DIRECTION OUTPUT ;
    USE SIGNAL ;
    PORT
      LAYER M5 ;
        RECT  66.768 36.528 66.792 36.72 ;
    END
  END dq[511]
  PIN dq[512]
    DIRECTION OUTPUT ;
    USE SIGNAL ;
    PORT
      LAYER M3 ;
        RECT  66.888 36.576 66.906 36.72 ;
    END
  END dq[512]
  PIN dq[513]
    DIRECTION OUTPUT ;
    USE SIGNAL ;
    PORT
      LAYER M5 ;
        RECT  67.008 36.528 67.032 36.72 ;
    END
  END dq[513]
  PIN dq[514]
    DIRECTION OUTPUT ;
    USE SIGNAL ;
    PORT
      LAYER M3 ;
        RECT  67.14 36.576 67.158 36.72 ;
    END
  END dq[514]
  PIN dq[515]
    DIRECTION OUTPUT ;
    USE SIGNAL ;
    PORT
      LAYER M5 ;
        RECT  67.248 36.528 67.272 36.72 ;
    END
  END dq[515]
  PIN dq[516]
    DIRECTION OUTPUT ;
    USE SIGNAL ;
    PORT
      LAYER M3 ;
        RECT  67.356 36.576 67.374 36.72 ;
    END
  END dq[516]
  PIN dq[517]
    DIRECTION OUTPUT ;
    USE SIGNAL ;
    PORT
      LAYER M5 ;
        RECT  67.488 36.528 67.512 36.72 ;
    END
  END dq[517]
  PIN dq[518]
    DIRECTION OUTPUT ;
    USE SIGNAL ;
    PORT
      LAYER M3 ;
        RECT  67.608 36.576 67.626 36.72 ;
    END
  END dq[518]
  PIN dq[519]
    DIRECTION OUTPUT ;
    USE SIGNAL ;
    PORT
      LAYER M5 ;
        RECT  67.728 36.528 67.752 36.72 ;
    END
  END dq[519]
  PIN dq[51]
    DIRECTION OUTPUT ;
    USE SIGNAL ;
    PORT
      LAYER M5 ;
        RECT  10.608 36.528 10.632 36.72 ;
    END
  END dq[51]
  PIN dq[520]
    DIRECTION OUTPUT ;
    USE SIGNAL ;
    PORT
      LAYER M3 ;
        RECT  67.86 36.576 67.878 36.72 ;
    END
  END dq[520]
  PIN dq[521]
    DIRECTION OUTPUT ;
    USE SIGNAL ;
    PORT
      LAYER M5 ;
        RECT  67.968 36.528 67.992 36.72 ;
    END
  END dq[521]
  PIN dq[522]
    DIRECTION OUTPUT ;
    USE SIGNAL ;
    PORT
      LAYER M3 ;
        RECT  68.112 36.576 68.13 36.72 ;
    END
  END dq[522]
  PIN dq[523]
    DIRECTION OUTPUT ;
    USE SIGNAL ;
    PORT
      LAYER M5 ;
        RECT  68.208 36.528 68.232 36.72 ;
    END
  END dq[523]
  PIN dq[524]
    DIRECTION OUTPUT ;
    USE SIGNAL ;
    PORT
      LAYER M3 ;
        RECT  68.328 36.576 68.346 36.72 ;
    END
  END dq[524]
  PIN dq[525]
    DIRECTION OUTPUT ;
    USE SIGNAL ;
    PORT
      LAYER M5 ;
        RECT  68.448 36.528 68.472 36.72 ;
    END
  END dq[525]
  PIN dq[526]
    DIRECTION OUTPUT ;
    USE SIGNAL ;
    PORT
      LAYER M3 ;
        RECT  68.58 36.576 68.598 36.72 ;
    END
  END dq[526]
  PIN dq[527]
    DIRECTION OUTPUT ;
    USE SIGNAL ;
    PORT
      LAYER M5 ;
        RECT  68.688 36.528 68.712 36.72 ;
    END
  END dq[527]
  PIN dq[528]
    DIRECTION OUTPUT ;
    USE SIGNAL ;
    PORT
      LAYER M3 ;
        RECT  68.832 36.576 68.85 36.72 ;
    END
  END dq[528]
  PIN dq[529]
    DIRECTION OUTPUT ;
    USE SIGNAL ;
    PORT
      LAYER M5 ;
        RECT  68.976 36.528 69 36.72 ;
    END
  END dq[529]
  PIN dq[52]
    DIRECTION OUTPUT ;
    USE SIGNAL ;
    PORT
      LAYER M3 ;
        RECT  10.728 36.576 10.746 36.72 ;
    END
  END dq[52]
  PIN dq[530]
    DIRECTION OUTPUT ;
    USE SIGNAL ;
    PORT
      LAYER M3 ;
        RECT  69.084 36.576 69.102 36.72 ;
    END
  END dq[530]
  PIN dq[531]
    DIRECTION OUTPUT ;
    USE SIGNAL ;
    PORT
      LAYER M5 ;
        RECT  69.216 36.528 69.24 36.72 ;
    END
  END dq[531]
  PIN dq[532]
    DIRECTION OUTPUT ;
    USE SIGNAL ;
    PORT
      LAYER M3 ;
        RECT  69.336 36.576 69.354 36.72 ;
    END
  END dq[532]
  PIN dq[533]
    DIRECTION OUTPUT ;
    USE SIGNAL ;
    PORT
      LAYER M5 ;
        RECT  69.456 36.528 69.48 36.72 ;
    END
  END dq[533]
  PIN dq[534]
    DIRECTION OUTPUT ;
    USE SIGNAL ;
    PORT
      LAYER M3 ;
        RECT  69.552 36.576 69.57 36.72 ;
    END
  END dq[534]
  PIN dq[535]
    DIRECTION OUTPUT ;
    USE SIGNAL ;
    PORT
      LAYER M5 ;
        RECT  69.696 36.528 69.72 36.72 ;
    END
  END dq[535]
  PIN dq[536]
    DIRECTION OUTPUT ;
    USE SIGNAL ;
    PORT
      LAYER M3 ;
        RECT  69.804 36.576 69.822 36.72 ;
    END
  END dq[536]
  PIN dq[537]
    DIRECTION OUTPUT ;
    USE SIGNAL ;
    PORT
      LAYER M5 ;
        RECT  69.936 36.528 69.96 36.72 ;
    END
  END dq[537]
  PIN dq[538]
    DIRECTION OUTPUT ;
    USE SIGNAL ;
    PORT
      LAYER M3 ;
        RECT  70.056 36.576 70.074 36.72 ;
    END
  END dq[538]
  PIN dq[539]
    DIRECTION OUTPUT ;
    USE SIGNAL ;
    PORT
      LAYER M5 ;
        RECT  70.176 36.528 70.2 36.72 ;
    END
  END dq[539]
  PIN dq[53]
    DIRECTION OUTPUT ;
    USE SIGNAL ;
    PORT
      LAYER M5 ;
        RECT  10.848 36.528 10.872 36.72 ;
    END
  END dq[53]
  PIN dq[540]
    DIRECTION OUTPUT ;
    USE SIGNAL ;
    PORT
      LAYER M3 ;
        RECT  70.308 36.576 70.326 36.72 ;
    END
  END dq[540]
  PIN dq[541]
    DIRECTION OUTPUT ;
    USE SIGNAL ;
    PORT
      LAYER M5 ;
        RECT  70.416 36.528 70.44 36.72 ;
    END
  END dq[541]
  PIN dq[542]
    DIRECTION OUTPUT ;
    USE SIGNAL ;
    PORT
      LAYER M3 ;
        RECT  70.56 36.576 70.578 36.72 ;
    END
  END dq[542]
  PIN dq[543]
    DIRECTION OUTPUT ;
    USE SIGNAL ;
    PORT
      LAYER M5 ;
        RECT  70.656 36.528 70.68 36.72 ;
    END
  END dq[543]
  PIN dq[544]
    DIRECTION OUTPUT ;
    USE SIGNAL ;
    PORT
      LAYER M3 ;
        RECT  70.776 36.576 70.794 36.72 ;
    END
  END dq[544]
  PIN dq[545]
    DIRECTION OUTPUT ;
    USE SIGNAL ;
    PORT
      LAYER M5 ;
        RECT  70.896 36.528 70.92 36.72 ;
    END
  END dq[545]
  PIN dq[546]
    DIRECTION OUTPUT ;
    USE SIGNAL ;
    PORT
      LAYER M3 ;
        RECT  71.028 36.576 71.046 36.72 ;
    END
  END dq[546]
  PIN dq[547]
    DIRECTION OUTPUT ;
    USE SIGNAL ;
    PORT
      LAYER M5 ;
        RECT  71.136 36.528 71.16 36.72 ;
    END
  END dq[547]
  PIN dq[548]
    DIRECTION OUTPUT ;
    USE SIGNAL ;
    PORT
      LAYER M3 ;
        RECT  71.28 36.576 71.298 36.72 ;
    END
  END dq[548]
  PIN dq[549]
    DIRECTION OUTPUT ;
    USE SIGNAL ;
    PORT
      LAYER M5 ;
        RECT  71.376 36.528 71.4 36.72 ;
    END
  END dq[549]
  PIN dq[54]
    DIRECTION OUTPUT ;
    USE SIGNAL ;
    PORT
      LAYER M3 ;
        RECT  10.98 36.576 10.998 36.72 ;
    END
  END dq[54]
  PIN dq[550]
    DIRECTION OUTPUT ;
    USE SIGNAL ;
    PORT
      LAYER M3 ;
        RECT  71.532 36.576 71.55 36.72 ;
    END
  END dq[550]
  PIN dq[551]
    DIRECTION OUTPUT ;
    USE SIGNAL ;
    PORT
      LAYER M5 ;
        RECT  71.616 36.528 71.64 36.72 ;
    END
  END dq[551]
  PIN dq[552]
    DIRECTION OUTPUT ;
    USE SIGNAL ;
    PORT
      LAYER M3 ;
        RECT  71.748 36.576 71.766 36.72 ;
    END
  END dq[552]
  PIN dq[553]
    DIRECTION OUTPUT ;
    USE SIGNAL ;
    PORT
      LAYER M5 ;
        RECT  71.904 36.528 71.928 36.72 ;
    END
  END dq[553]
  PIN dq[554]
    DIRECTION OUTPUT ;
    USE SIGNAL ;
    PORT
      LAYER M3 ;
        RECT  72 36.576 72.018 36.72 ;
    END
  END dq[554]
  PIN dq[555]
    DIRECTION OUTPUT ;
    USE SIGNAL ;
    PORT
      LAYER M5 ;
        RECT  72.144 36.528 72.168 36.72 ;
    END
  END dq[555]
  PIN dq[556]
    DIRECTION OUTPUT ;
    USE SIGNAL ;
    PORT
      LAYER M3 ;
        RECT  72.252 36.576 72.27 36.72 ;
    END
  END dq[556]
  PIN dq[557]
    DIRECTION OUTPUT ;
    USE SIGNAL ;
    PORT
      LAYER M5 ;
        RECT  72.384 36.528 72.408 36.72 ;
    END
  END dq[557]
  PIN dq[558]
    DIRECTION OUTPUT ;
    USE SIGNAL ;
    PORT
      LAYER M3 ;
        RECT  72.504 36.576 72.522 36.72 ;
    END
  END dq[558]
  PIN dq[559]
    DIRECTION OUTPUT ;
    USE SIGNAL ;
    PORT
      LAYER M5 ;
        RECT  72.624 36.528 72.648 36.72 ;
    END
  END dq[559]
  PIN dq[55]
    DIRECTION OUTPUT ;
    USE SIGNAL ;
    PORT
      LAYER M5 ;
        RECT  11.088 36.528 11.112 36.72 ;
    END
  END dq[55]
  PIN dq[560]
    DIRECTION OUTPUT ;
    USE SIGNAL ;
    PORT
      LAYER M3 ;
        RECT  72.756 36.576 72.774 36.72 ;
    END
  END dq[560]
  PIN dq[561]
    DIRECTION OUTPUT ;
    USE SIGNAL ;
    PORT
      LAYER M5 ;
        RECT  72.864 36.528 72.888 36.72 ;
    END
  END dq[561]
  PIN dq[562]
    DIRECTION OUTPUT ;
    USE SIGNAL ;
    PORT
      LAYER M3 ;
        RECT  72.972 36.576 72.99 36.72 ;
    END
  END dq[562]
  PIN dq[563]
    DIRECTION OUTPUT ;
    USE SIGNAL ;
    PORT
      LAYER M5 ;
        RECT  73.104 36.528 73.128 36.72 ;
    END
  END dq[563]
  PIN dq[564]
    DIRECTION OUTPUT ;
    USE SIGNAL ;
    PORT
      LAYER M3 ;
        RECT  73.224 36.576 73.242 36.72 ;
    END
  END dq[564]
  PIN dq[565]
    DIRECTION OUTPUT ;
    USE SIGNAL ;
    PORT
      LAYER M5 ;
        RECT  73.344 36.528 73.368 36.72 ;
    END
  END dq[565]
  PIN dq[566]
    DIRECTION OUTPUT ;
    USE SIGNAL ;
    PORT
      LAYER M3 ;
        RECT  73.476 36.576 73.494 36.72 ;
    END
  END dq[566]
  PIN dq[567]
    DIRECTION OUTPUT ;
    USE SIGNAL ;
    PORT
      LAYER M5 ;
        RECT  73.584 36.528 73.608 36.72 ;
    END
  END dq[567]
  PIN dq[568]
    DIRECTION OUTPUT ;
    USE SIGNAL ;
    PORT
      LAYER M3 ;
        RECT  73.728 36.576 73.746 36.72 ;
    END
  END dq[568]
  PIN dq[569]
    DIRECTION OUTPUT ;
    USE SIGNAL ;
    PORT
      LAYER M5 ;
        RECT  73.824 36.528 73.848 36.72 ;
    END
  END dq[569]
  PIN dq[56]
    DIRECTION OUTPUT ;
    USE SIGNAL ;
    PORT
      LAYER M3 ;
        RECT  11.196 36.576 11.214 36.72 ;
    END
  END dq[56]
  PIN dq[570]
    DIRECTION OUTPUT ;
    USE SIGNAL ;
    PORT
      LAYER M3 ;
        RECT  73.944 36.576 73.962 36.72 ;
    END
  END dq[570]
  PIN dq[571]
    DIRECTION OUTPUT ;
    USE SIGNAL ;
    PORT
      LAYER M5 ;
        RECT  74.064 36.528 74.088 36.72 ;
    END
  END dq[571]
  PIN dq[572]
    DIRECTION OUTPUT ;
    USE SIGNAL ;
    PORT
      LAYER M3 ;
        RECT  74.196 36.576 74.214 36.72 ;
    END
  END dq[572]
  PIN dq[573]
    DIRECTION OUTPUT ;
    USE SIGNAL ;
    PORT
      LAYER M5 ;
        RECT  74.304 36.528 74.328 36.72 ;
    END
  END dq[573]
  PIN dq[574]
    DIRECTION OUTPUT ;
    USE SIGNAL ;
    PORT
      LAYER M3 ;
        RECT  74.448 36.576 74.466 36.72 ;
    END
  END dq[574]
  PIN dq[575]
    DIRECTION OUTPUT ;
    USE SIGNAL ;
    PORT
      LAYER M5 ;
        RECT  74.592 36.528 74.616 36.72 ;
    END
  END dq[575]
  PIN dq[576]
    DIRECTION OUTPUT ;
    USE SIGNAL ;
    PORT
      LAYER M3 ;
        RECT  74.7 36.576 74.718 36.72 ;
    END
  END dq[576]
  PIN dq[577]
    DIRECTION OUTPUT ;
    USE SIGNAL ;
    PORT
      LAYER M5 ;
        RECT  74.832 36.528 74.856 36.72 ;
    END
  END dq[577]
  PIN dq[578]
    DIRECTION OUTPUT ;
    USE SIGNAL ;
    PORT
      LAYER M3 ;
        RECT  74.952 36.576 74.97 36.72 ;
    END
  END dq[578]
  PIN dq[579]
    DIRECTION OUTPUT ;
    USE SIGNAL ;
    PORT
      LAYER M5 ;
        RECT  75.072 36.528 75.096 36.72 ;
    END
  END dq[579]
  PIN dq[57]
    DIRECTION OUTPUT ;
    USE SIGNAL ;
    PORT
      LAYER M5 ;
        RECT  11.328 36.528 11.352 36.72 ;
    END
  END dq[57]
  PIN dq[580]
    DIRECTION OUTPUT ;
    USE SIGNAL ;
    PORT
      LAYER M3 ;
        RECT  75.168 36.576 75.186 36.72 ;
    END
  END dq[580]
  PIN dq[581]
    DIRECTION OUTPUT ;
    USE SIGNAL ;
    PORT
      LAYER M5 ;
        RECT  75.312 36.528 75.336 36.72 ;
    END
  END dq[581]
  PIN dq[582]
    DIRECTION OUTPUT ;
    USE SIGNAL ;
    PORT
      LAYER M3 ;
        RECT  75.42 36.576 75.438 36.72 ;
    END
  END dq[582]
  PIN dq[583]
    DIRECTION OUTPUT ;
    USE SIGNAL ;
    PORT
      LAYER M5 ;
        RECT  75.552 36.528 75.576 36.72 ;
    END
  END dq[583]
  PIN dq[584]
    DIRECTION OUTPUT ;
    USE SIGNAL ;
    PORT
      LAYER M3 ;
        RECT  75.672 36.576 75.69 36.72 ;
    END
  END dq[584]
  PIN dq[585]
    DIRECTION OUTPUT ;
    USE SIGNAL ;
    PORT
      LAYER M5 ;
        RECT  75.792 36.528 75.816 36.72 ;
    END
  END dq[585]
  PIN dq[586]
    DIRECTION OUTPUT ;
    USE SIGNAL ;
    PORT
      LAYER M3 ;
        RECT  75.924 36.576 75.942 36.72 ;
    END
  END dq[586]
  PIN dq[587]
    DIRECTION OUTPUT ;
    USE SIGNAL ;
    PORT
      LAYER M5 ;
        RECT  76.032 36.528 76.056 36.72 ;
    END
  END dq[587]
  PIN dq[588]
    DIRECTION OUTPUT ;
    USE SIGNAL ;
    PORT
      LAYER M3 ;
        RECT  76.176 36.576 76.194 36.72 ;
    END
  END dq[588]
  PIN dq[589]
    DIRECTION OUTPUT ;
    USE SIGNAL ;
    PORT
      LAYER M5 ;
        RECT  76.272 36.528 76.296 36.72 ;
    END
  END dq[589]
  PIN dq[58]
    DIRECTION OUTPUT ;
    USE SIGNAL ;
    PORT
      LAYER M3 ;
        RECT  11.448 36.576 11.466 36.72 ;
    END
  END dq[58]
  PIN dq[590]
    DIRECTION OUTPUT ;
    USE SIGNAL ;
    PORT
      LAYER M3 ;
        RECT  76.392 36.576 76.41 36.72 ;
    END
  END dq[590]
  PIN dq[591]
    DIRECTION OUTPUT ;
    USE SIGNAL ;
    PORT
      LAYER M5 ;
        RECT  76.512 36.528 76.536 36.72 ;
    END
  END dq[591]
  PIN dq[592]
    DIRECTION OUTPUT ;
    USE SIGNAL ;
    PORT
      LAYER M3 ;
        RECT  76.644 36.576 76.662 36.72 ;
    END
  END dq[592]
  PIN dq[593]
    DIRECTION OUTPUT ;
    USE SIGNAL ;
    PORT
      LAYER M5 ;
        RECT  76.752 36.528 76.776 36.72 ;
    END
  END dq[593]
  PIN dq[594]
    DIRECTION OUTPUT ;
    USE SIGNAL ;
    PORT
      LAYER M3 ;
        RECT  76.896 36.576 76.914 36.72 ;
    END
  END dq[594]
  PIN dq[595]
    DIRECTION OUTPUT ;
    USE SIGNAL ;
    PORT
      LAYER M5 ;
        RECT  76.992 36.528 77.016 36.72 ;
    END
  END dq[595]
  PIN dq[596]
    DIRECTION OUTPUT ;
    USE SIGNAL ;
    PORT
      LAYER M3 ;
        RECT  77.148 36.576 77.166 36.72 ;
    END
  END dq[596]
  PIN dq[597]
    DIRECTION OUTPUT ;
    USE SIGNAL ;
    PORT
      LAYER M5 ;
        RECT  77.232 36.528 77.256 36.72 ;
    END
  END dq[597]
  PIN dq[598]
    DIRECTION OUTPUT ;
    USE SIGNAL ;
    PORT
      LAYER M3 ;
        RECT  77.364 36.576 77.382 36.72 ;
    END
  END dq[598]
  PIN dq[599]
    DIRECTION OUTPUT ;
    USE SIGNAL ;
    PORT
      LAYER M5 ;
        RECT  77.52 36.528 77.544 36.72 ;
    END
  END dq[599]
  PIN dq[59]
    DIRECTION OUTPUT ;
    USE SIGNAL ;
    PORT
      LAYER M5 ;
        RECT  11.568 36.528 11.592 36.72 ;
    END
  END dq[59]
  PIN dq[5]
    DIRECTION OUTPUT ;
    USE SIGNAL ;
    PORT
      LAYER M5 ;
        RECT  4.992 36.528 5.016 36.72 ;
    END
  END dq[5]
  PIN dq[600]
    DIRECTION OUTPUT ;
    USE SIGNAL ;
    PORT
      LAYER M3 ;
        RECT  77.616 36.576 77.634 36.72 ;
    END
  END dq[600]
  PIN dq[601]
    DIRECTION OUTPUT ;
    USE SIGNAL ;
    PORT
      LAYER M5 ;
        RECT  77.76 36.528 77.784 36.72 ;
    END
  END dq[601]
  PIN dq[602]
    DIRECTION OUTPUT ;
    USE SIGNAL ;
    PORT
      LAYER M3 ;
        RECT  77.868 36.576 77.886 36.72 ;
    END
  END dq[602]
  PIN dq[603]
    DIRECTION OUTPUT ;
    USE SIGNAL ;
    PORT
      LAYER M5 ;
        RECT  78 36.528 78.024 36.72 ;
    END
  END dq[603]
  PIN dq[604]
    DIRECTION OUTPUT ;
    USE SIGNAL ;
    PORT
      LAYER M3 ;
        RECT  78.12 36.576 78.138 36.72 ;
    END
  END dq[604]
  PIN dq[605]
    DIRECTION OUTPUT ;
    USE SIGNAL ;
    PORT
      LAYER M5 ;
        RECT  78.24 36.528 78.264 36.72 ;
    END
  END dq[605]
  PIN dq[606]
    DIRECTION OUTPUT ;
    USE SIGNAL ;
    PORT
      LAYER M3 ;
        RECT  78.372 36.576 78.39 36.72 ;
    END
  END dq[606]
  PIN dq[607]
    DIRECTION OUTPUT ;
    USE SIGNAL ;
    PORT
      LAYER M5 ;
        RECT  78.48 36.528 78.504 36.72 ;
    END
  END dq[607]
  PIN dq[608]
    DIRECTION OUTPUT ;
    USE SIGNAL ;
    PORT
      LAYER M3 ;
        RECT  78.588 36.576 78.606 36.72 ;
    END
  END dq[608]
  PIN dq[609]
    DIRECTION OUTPUT ;
    USE SIGNAL ;
    PORT
      LAYER M5 ;
        RECT  78.72 36.528 78.744 36.72 ;
    END
  END dq[609]
  PIN dq[60]
    DIRECTION OUTPUT ;
    USE SIGNAL ;
    PORT
      LAYER M3 ;
        RECT  11.7 36.576 11.718 36.72 ;
    END
  END dq[60]
  PIN dq[610]
    DIRECTION OUTPUT ;
    USE SIGNAL ;
    PORT
      LAYER M3 ;
        RECT  78.84 36.576 78.858 36.72 ;
    END
  END dq[610]
  PIN dq[611]
    DIRECTION OUTPUT ;
    USE SIGNAL ;
    PORT
      LAYER M5 ;
        RECT  78.96 36.528 78.984 36.72 ;
    END
  END dq[611]
  PIN dq[612]
    DIRECTION OUTPUT ;
    USE SIGNAL ;
    PORT
      LAYER M3 ;
        RECT  79.092 36.576 79.11 36.72 ;
    END
  END dq[612]
  PIN dq[613]
    DIRECTION OUTPUT ;
    USE SIGNAL ;
    PORT
      LAYER M5 ;
        RECT  79.2 36.528 79.224 36.72 ;
    END
  END dq[613]
  PIN dq[614]
    DIRECTION OUTPUT ;
    USE SIGNAL ;
    PORT
      LAYER M3 ;
        RECT  79.344 36.576 79.362 36.72 ;
    END
  END dq[614]
  PIN dq[615]
    DIRECTION OUTPUT ;
    USE SIGNAL ;
    PORT
      LAYER M5 ;
        RECT  79.44 36.528 79.464 36.72 ;
    END
  END dq[615]
  PIN dq[616]
    DIRECTION OUTPUT ;
    USE SIGNAL ;
    PORT
      LAYER M3 ;
        RECT  79.56 36.576 79.578 36.72 ;
    END
  END dq[616]
  PIN dq[617]
    DIRECTION OUTPUT ;
    USE SIGNAL ;
    PORT
      LAYER M5 ;
        RECT  79.68 36.528 79.704 36.72 ;
    END
  END dq[617]
  PIN dq[618]
    DIRECTION OUTPUT ;
    USE SIGNAL ;
    PORT
      LAYER M3 ;
        RECT  79.812 36.576 79.83 36.72 ;
    END
  END dq[618]
  PIN dq[619]
    DIRECTION OUTPUT ;
    USE SIGNAL ;
    PORT
      LAYER M5 ;
        RECT  79.92 36.528 79.944 36.72 ;
    END
  END dq[619]
  PIN dq[61]
    DIRECTION OUTPUT ;
    USE SIGNAL ;
    PORT
      LAYER M5 ;
        RECT  11.808 36.528 11.832 36.72 ;
    END
  END dq[61]
  PIN dq[620]
    DIRECTION OUTPUT ;
    USE SIGNAL ;
    PORT
      LAYER M3 ;
        RECT  80.064 36.576 80.082 36.72 ;
    END
  END dq[620]
  PIN dq[621]
    DIRECTION OUTPUT ;
    USE SIGNAL ;
    PORT
      LAYER M5 ;
        RECT  80.208 36.528 80.232 36.72 ;
    END
  END dq[621]
  PIN dq[622]
    DIRECTION OUTPUT ;
    USE SIGNAL ;
    PORT
      LAYER M3 ;
        RECT  80.316 36.576 80.334 36.72 ;
    END
    PORT
      LAYER M3 ;
        RECT  80.244 36.588 80.37 36.653 ;
    END
  END dq[622]
  PIN dq[623]
    DIRECTION OUTPUT ;
    USE SIGNAL ;
    PORT
      LAYER M5 ;
        RECT  80.448 36.528 80.472 36.72 ;
    END
  END dq[623]
  PIN dq[624]
    DIRECTION OUTPUT ;
    USE SIGNAL ;
    PORT
      LAYER M3 ;
        RECT  80.568 36.576 80.586 36.72 ;
    END
  END dq[624]
  PIN dq[625]
    DIRECTION OUTPUT ;
    USE SIGNAL ;
    PORT
      LAYER M5 ;
        RECT  80.688 36.528 80.712 36.72 ;
    END
  END dq[625]
  PIN dq[626]
    DIRECTION OUTPUT ;
    USE SIGNAL ;
    PORT
      LAYER M3 ;
        RECT  80.784 36.576 80.802 36.72 ;
    END
  END dq[626]
  PIN dq[627]
    DIRECTION OUTPUT ;
    USE SIGNAL ;
    PORT
      LAYER M5 ;
        RECT  80.928 36.528 80.952 36.72 ;
    END
  END dq[627]
  PIN dq[628]
    DIRECTION OUTPUT ;
    USE SIGNAL ;
    PORT
      LAYER M3 ;
        RECT  81.036 36.576 81.054 36.72 ;
    END
  END dq[628]
  PIN dq[629]
    DIRECTION OUTPUT ;
    USE SIGNAL ;
    PORT
      LAYER M5 ;
        RECT  81.168 36.528 81.192 36.72 ;
    END
  END dq[629]
  PIN dq[62]
    DIRECTION OUTPUT ;
    USE SIGNAL ;
    PORT
      LAYER M3 ;
        RECT  11.952 36.576 11.97 36.72 ;
    END
  END dq[62]
  PIN dq[630]
    DIRECTION OUTPUT ;
    USE SIGNAL ;
    PORT
      LAYER M3 ;
        RECT  81.288 36.576 81.306 36.72 ;
    END
  END dq[630]
  PIN dq[631]
    DIRECTION OUTPUT ;
    USE SIGNAL ;
    PORT
      LAYER M5 ;
        RECT  81.408 36.528 81.432 36.72 ;
    END
  END dq[631]
  PIN dq[632]
    DIRECTION OUTPUT ;
    USE SIGNAL ;
    PORT
      LAYER M3 ;
        RECT  81.54 36.576 81.558 36.72 ;
    END
  END dq[632]
  PIN dq[633]
    DIRECTION OUTPUT ;
    USE SIGNAL ;
    PORT
      LAYER M5 ;
        RECT  81.648 36.528 81.672 36.72 ;
    END
  END dq[633]
  PIN dq[634]
    DIRECTION OUTPUT ;
    USE SIGNAL ;
    PORT
      LAYER M3 ;
        RECT  81.792 36.576 81.81 36.72 ;
    END
  END dq[634]
  PIN dq[635]
    DIRECTION OUTPUT ;
    USE SIGNAL ;
    PORT
      LAYER M5 ;
        RECT  81.888 36.528 81.912 36.72 ;
    END
  END dq[635]
  PIN dq[636]
    DIRECTION OUTPUT ;
    USE SIGNAL ;
    PORT
      LAYER M3 ;
        RECT  82.008 36.576 82.026 36.72 ;
    END
  END dq[636]
  PIN dq[637]
    DIRECTION OUTPUT ;
    USE SIGNAL ;
    PORT
      LAYER M5 ;
        RECT  82.128 36.528 82.152 36.72 ;
    END
  END dq[637]
  PIN dq[638]
    DIRECTION OUTPUT ;
    USE SIGNAL ;
    PORT
      LAYER M3 ;
        RECT  82.26 36.576 82.278 36.72 ;
    END
  END dq[638]
  PIN dq[639]
    DIRECTION OUTPUT ;
    USE SIGNAL ;
    PORT
      LAYER M5 ;
        RECT  82.368 36.528 82.392 36.72 ;
    END
  END dq[639]
  PIN dq[63]
    DIRECTION OUTPUT ;
    USE SIGNAL ;
    PORT
      LAYER M5 ;
        RECT  12.048 36.528 12.072 36.72 ;
    END
  END dq[63]
  PIN dq[640]
    DIRECTION OUTPUT ;
    USE SIGNAL ;
    PORT
      LAYER M3 ;
        RECT  82.512 36.576 82.53 36.72 ;
    END
  END dq[640]
  PIN dq[641]
    DIRECTION OUTPUT ;
    USE SIGNAL ;
    PORT
      LAYER M5 ;
        RECT  82.608 36.528 82.632 36.72 ;
    END
  END dq[641]
  PIN dq[642]
    DIRECTION OUTPUT ;
    USE SIGNAL ;
    PORT
      LAYER M3 ;
        RECT  82.764 36.576 82.782 36.72 ;
    END
  END dq[642]
  PIN dq[643]
    DIRECTION OUTPUT ;
    USE SIGNAL ;
    PORT
      LAYER M5 ;
        RECT  82.848 36.528 82.872 36.72 ;
    END
  END dq[643]
  PIN dq[644]
    DIRECTION OUTPUT ;
    USE SIGNAL ;
    PORT
      LAYER M3 ;
        RECT  82.98 36.576 82.998 36.72 ;
    END
  END dq[644]
  PIN dq[645]
    DIRECTION OUTPUT ;
    USE SIGNAL ;
    PORT
      LAYER M5 ;
        RECT  83.136 36.528 83.16 36.72 ;
    END
  END dq[645]
  PIN dq[646]
    DIRECTION OUTPUT ;
    USE SIGNAL ;
    PORT
      LAYER M3 ;
        RECT  83.232 36.576 83.25 36.72 ;
    END
  END dq[646]
  PIN dq[647]
    DIRECTION OUTPUT ;
    USE SIGNAL ;
    PORT
      LAYER M5 ;
        RECT  83.376 36.528 83.4 36.72 ;
    END
  END dq[647]
  PIN dq[648]
    DIRECTION OUTPUT ;
    USE SIGNAL ;
    PORT
      LAYER M3 ;
        RECT  83.484 36.576 83.502 36.72 ;
    END
  END dq[648]
  PIN dq[649]
    DIRECTION OUTPUT ;
    USE SIGNAL ;
    PORT
      LAYER M5 ;
        RECT  83.616 36.528 83.64 36.72 ;
    END
  END dq[649]
  PIN dq[64]
    DIRECTION OUTPUT ;
    USE SIGNAL ;
    PORT
      LAYER M3 ;
        RECT  12.168 36.576 12.186 36.72 ;
    END
  END dq[64]
  PIN dq[650]
    DIRECTION OUTPUT ;
    USE SIGNAL ;
    PORT
      LAYER M3 ;
        RECT  83.736 36.576 83.754 36.72 ;
    END
  END dq[650]
  PIN dq[651]
    DIRECTION OUTPUT ;
    USE SIGNAL ;
    PORT
      LAYER M5 ;
        RECT  83.856 36.528 83.88 36.72 ;
    END
  END dq[651]
  PIN dq[652]
    DIRECTION OUTPUT ;
    USE SIGNAL ;
    PORT
      LAYER M3 ;
        RECT  83.988 36.576 84.006 36.72 ;
    END
  END dq[652]
  PIN dq[653]
    DIRECTION OUTPUT ;
    USE SIGNAL ;
    PORT
      LAYER M5 ;
        RECT  84.096 36.528 84.12 36.72 ;
    END
  END dq[653]
  PIN dq[654]
    DIRECTION OUTPUT ;
    USE SIGNAL ;
    PORT
      LAYER M3 ;
        RECT  84.204 36.576 84.222 36.72 ;
    END
  END dq[654]
  PIN dq[655]
    DIRECTION OUTPUT ;
    USE SIGNAL ;
    PORT
      LAYER M5 ;
        RECT  84.336 36.528 84.36 36.72 ;
    END
  END dq[655]
  PIN dq[656]
    DIRECTION OUTPUT ;
    USE SIGNAL ;
    PORT
      LAYER M3 ;
        RECT  84.456 36.576 84.474 36.72 ;
    END
  END dq[656]
  PIN dq[657]
    DIRECTION OUTPUT ;
    USE SIGNAL ;
    PORT
      LAYER M5 ;
        RECT  84.576 36.528 84.6 36.72 ;
    END
  END dq[657]
  PIN dq[658]
    DIRECTION OUTPUT ;
    USE SIGNAL ;
    PORT
      LAYER M3 ;
        RECT  84.708 36.576 84.726 36.72 ;
    END
  END dq[658]
  PIN dq[659]
    DIRECTION OUTPUT ;
    USE SIGNAL ;
    PORT
      LAYER M5 ;
        RECT  84.816 36.528 84.84 36.72 ;
    END
  END dq[659]
  PIN dq[65]
    DIRECTION OUTPUT ;
    USE SIGNAL ;
    PORT
      LAYER M5 ;
        RECT  12.288 36.528 12.312 36.72 ;
    END
  END dq[65]
  PIN dq[660]
    DIRECTION OUTPUT ;
    USE SIGNAL ;
    PORT
      LAYER M3 ;
        RECT  84.96 36.576 84.978 36.72 ;
    END
  END dq[660]
  PIN dq[661]
    DIRECTION OUTPUT ;
    USE SIGNAL ;
    PORT
      LAYER M5 ;
        RECT  85.056 36.528 85.08 36.72 ;
    END
  END dq[661]
  PIN dq[662]
    DIRECTION OUTPUT ;
    USE SIGNAL ;
    PORT
      LAYER M3 ;
        RECT  85.176 36.576 85.194 36.72 ;
    END
  END dq[662]
  PIN dq[663]
    DIRECTION OUTPUT ;
    USE SIGNAL ;
    PORT
      LAYER M5 ;
        RECT  85.296 36.528 85.32 36.72 ;
    END
  END dq[663]
  PIN dq[664]
    DIRECTION OUTPUT ;
    USE SIGNAL ;
    PORT
      LAYER M3 ;
        RECT  85.428 36.576 85.446 36.72 ;
    END
  END dq[664]
  PIN dq[665]
    DIRECTION OUTPUT ;
    USE SIGNAL ;
    PORT
      LAYER M5 ;
        RECT  85.536 36.528 85.56 36.72 ;
    END
  END dq[665]
  PIN dq[666]
    DIRECTION OUTPUT ;
    USE SIGNAL ;
    PORT
      LAYER M3 ;
        RECT  85.68 36.576 85.698 36.72 ;
    END
  END dq[666]
  PIN dq[667]
    DIRECTION OUTPUT ;
    USE SIGNAL ;
    PORT
      LAYER M5 ;
        RECT  85.824 36.528 85.848 36.72 ;
    END
  END dq[667]
  PIN dq[668]
    DIRECTION OUTPUT ;
    USE SIGNAL ;
    PORT
      LAYER M3 ;
        RECT  85.932 36.576 85.95 36.72 ;
    END
  END dq[668]
  PIN dq[669]
    DIRECTION OUTPUT ;
    USE SIGNAL ;
    PORT
      LAYER M5 ;
        RECT  86.064 36.528 86.088 36.72 ;
    END
  END dq[669]
  PIN dq[66]
    DIRECTION OUTPUT ;
    USE SIGNAL ;
    PORT
      LAYER M3 ;
        RECT  12.42 36.576 12.438 36.72 ;
    END
  END dq[66]
  PIN dq[670]
    DIRECTION OUTPUT ;
    USE SIGNAL ;
    PORT
      LAYER M3 ;
        RECT  86.184 36.576 86.202 36.72 ;
    END
  END dq[670]
  PIN dq[671]
    DIRECTION OUTPUT ;
    USE SIGNAL ;
    PORT
      LAYER M5 ;
        RECT  86.304 36.528 86.328 36.72 ;
    END
  END dq[671]
  PIN dq[672]
    DIRECTION OUTPUT ;
    USE SIGNAL ;
    PORT
      LAYER M3 ;
        RECT  86.4 36.576 86.418 36.72 ;
    END
  END dq[672]
  PIN dq[673]
    DIRECTION OUTPUT ;
    USE SIGNAL ;
    PORT
      LAYER M5 ;
        RECT  86.544 36.528 86.568 36.72 ;
    END
  END dq[673]
  PIN dq[674]
    DIRECTION OUTPUT ;
    USE SIGNAL ;
    PORT
      LAYER M3 ;
        RECT  86.652 36.576 86.67 36.72 ;
    END
  END dq[674]
  PIN dq[675]
    DIRECTION OUTPUT ;
    USE SIGNAL ;
    PORT
      LAYER M5 ;
        RECT  86.784 36.528 86.808 36.72 ;
    END
  END dq[675]
  PIN dq[676]
    DIRECTION OUTPUT ;
    USE SIGNAL ;
    PORT
      LAYER M3 ;
        RECT  86.904 36.576 86.922 36.72 ;
    END
  END dq[676]
  PIN dq[677]
    DIRECTION OUTPUT ;
    USE SIGNAL ;
    PORT
      LAYER M5 ;
        RECT  87.024 36.528 87.048 36.72 ;
    END
  END dq[677]
  PIN dq[678]
    DIRECTION OUTPUT ;
    USE SIGNAL ;
    PORT
      LAYER M3 ;
        RECT  87.156 36.576 87.174 36.72 ;
    END
  END dq[678]
  PIN dq[679]
    DIRECTION OUTPUT ;
    USE SIGNAL ;
    PORT
      LAYER M5 ;
        RECT  87.264 36.528 87.288 36.72 ;
    END
  END dq[679]
  PIN dq[67]
    DIRECTION OUTPUT ;
    USE SIGNAL ;
    PORT
      LAYER M5 ;
        RECT  12.528 36.528 12.552 36.72 ;
    END
  END dq[67]
  PIN dq[680]
    DIRECTION OUTPUT ;
    USE SIGNAL ;
    PORT
      LAYER M3 ;
        RECT  87.408 36.576 87.426 36.72 ;
    END
  END dq[680]
  PIN dq[681]
    DIRECTION OUTPUT ;
    USE SIGNAL ;
    PORT
      LAYER M5 ;
        RECT  87.504 36.528 87.528 36.72 ;
    END
  END dq[681]
  PIN dq[682]
    DIRECTION OUTPUT ;
    USE SIGNAL ;
    PORT
      LAYER M3 ;
        RECT  87.624 36.576 87.642 36.72 ;
    END
  END dq[682]
  PIN dq[683]
    DIRECTION OUTPUT ;
    USE SIGNAL ;
    PORT
      LAYER M5 ;
        RECT  87.744 36.528 87.768 36.72 ;
    END
  END dq[683]
  PIN dq[684]
    DIRECTION OUTPUT ;
    USE SIGNAL ;
    PORT
      LAYER M3 ;
        RECT  87.876 36.576 87.894 36.72 ;
    END
  END dq[684]
  PIN dq[685]
    DIRECTION OUTPUT ;
    USE SIGNAL ;
    PORT
      LAYER M5 ;
        RECT  87.984 36.528 88.008 36.72 ;
    END
  END dq[685]
  PIN dq[686]
    DIRECTION OUTPUT ;
    USE SIGNAL ;
    PORT
      LAYER M3 ;
        RECT  88.128 36.576 88.146 36.72 ;
    END
  END dq[686]
  PIN dq[687]
    DIRECTION OUTPUT ;
    USE SIGNAL ;
    PORT
      LAYER M5 ;
        RECT  88.224 36.528 88.248 36.72 ;
    END
  END dq[687]
  PIN dq[688]
    DIRECTION OUTPUT ;
    USE SIGNAL ;
    PORT
      LAYER M3 ;
        RECT  88.38 36.576 88.398 36.72 ;
    END
  END dq[688]
  PIN dq[689]
    DIRECTION OUTPUT ;
    USE SIGNAL ;
    PORT
      LAYER M5 ;
        RECT  88.464 36.528 88.488 36.72 ;
    END
  END dq[689]
  PIN dq[68]
    DIRECTION OUTPUT ;
    USE SIGNAL ;
    PORT
      LAYER M3 ;
        RECT  12.672 36.576 12.69 36.72 ;
    END
  END dq[68]
  PIN dq[69]
    DIRECTION OUTPUT ;
    USE SIGNAL ;
    PORT
      LAYER M5 ;
        RECT  12.816 36.528 12.84 36.72 ;
    END
  END dq[69]
  PIN dq[6]
    DIRECTION OUTPUT ;
    USE SIGNAL ;
    PORT
      LAYER M3 ;
        RECT  5.112 36.576 5.13 36.72 ;
    END
  END dq[6]
  PIN dq[70]
    DIRECTION OUTPUT ;
    USE SIGNAL ;
    PORT
      LAYER M3 ;
        RECT  12.924 36.576 12.942 36.72 ;
    END
  END dq[70]
  PIN dq[71]
    DIRECTION OUTPUT ;
    USE SIGNAL ;
    PORT
      LAYER M5 ;
        RECT  13.056 36.528 13.08 36.72 ;
    END
  END dq[71]
  PIN dq[72]
    DIRECTION OUTPUT ;
    USE SIGNAL ;
    PORT
      LAYER M3 ;
        RECT  13.176 36.576 13.194 36.72 ;
    END
  END dq[72]
  PIN dq[73]
    DIRECTION OUTPUT ;
    USE SIGNAL ;
    PORT
      LAYER M5 ;
        RECT  13.296 36.528 13.32 36.72 ;
    END
  END dq[73]
  PIN dq[74]
    DIRECTION OUTPUT ;
    USE SIGNAL ;
    PORT
      LAYER M3 ;
        RECT  13.392 36.576 13.41 36.72 ;
    END
  END dq[74]
  PIN dq[75]
    DIRECTION OUTPUT ;
    USE SIGNAL ;
    PORT
      LAYER M5 ;
        RECT  13.536 36.528 13.56 36.72 ;
    END
  END dq[75]
  PIN dq[76]
    DIRECTION OUTPUT ;
    USE SIGNAL ;
    PORT
      LAYER M3 ;
        RECT  13.644 36.576 13.662 36.72 ;
    END
  END dq[76]
  PIN dq[77]
    DIRECTION OUTPUT ;
    USE SIGNAL ;
    PORT
      LAYER M5 ;
        RECT  13.776 36.528 13.8 36.72 ;
    END
  END dq[77]
  PIN dq[78]
    DIRECTION OUTPUT ;
    USE SIGNAL ;
    PORT
      LAYER M3 ;
        RECT  13.896 36.576 13.914 36.72 ;
    END
  END dq[78]
  PIN dq[79]
    DIRECTION OUTPUT ;
    USE SIGNAL ;
    PORT
      LAYER M5 ;
        RECT  14.016 36.528 14.04 36.72 ;
    END
  END dq[79]
  PIN dq[7]
    DIRECTION OUTPUT ;
    USE SIGNAL ;
    PORT
      LAYER M5 ;
        RECT  5.232 36.528 5.256 36.72 ;
    END
  END dq[7]
  PIN dq[80]
    DIRECTION OUTPUT ;
    USE SIGNAL ;
    PORT
      LAYER M3 ;
        RECT  14.148 36.576 14.166 36.72 ;
    END
  END dq[80]
  PIN dq[81]
    DIRECTION OUTPUT ;
    USE SIGNAL ;
    PORT
      LAYER M5 ;
        RECT  14.256 36.528 14.28 36.72 ;
    END
  END dq[81]
  PIN dq[82]
    DIRECTION OUTPUT ;
    USE SIGNAL ;
    PORT
      LAYER M3 ;
        RECT  14.4 36.576 14.418 36.72 ;
    END
  END dq[82]
  PIN dq[83]
    DIRECTION OUTPUT ;
    USE SIGNAL ;
    PORT
      LAYER M5 ;
        RECT  14.496 36.528 14.52 36.72 ;
    END
  END dq[83]
  PIN dq[84]
    DIRECTION OUTPUT ;
    USE SIGNAL ;
    PORT
      LAYER M3 ;
        RECT  14.616 36.576 14.634 36.72 ;
    END
  END dq[84]
  PIN dq[85]
    DIRECTION OUTPUT ;
    USE SIGNAL ;
    PORT
      LAYER M5 ;
        RECT  14.736 36.528 14.76 36.72 ;
    END
  END dq[85]
  PIN dq[86]
    DIRECTION OUTPUT ;
    USE SIGNAL ;
    PORT
      LAYER M3 ;
        RECT  14.868 36.576 14.886 36.72 ;
    END
  END dq[86]
  PIN dq[87]
    DIRECTION OUTPUT ;
    USE SIGNAL ;
    PORT
      LAYER M5 ;
        RECT  14.976 36.528 15 36.72 ;
    END
  END dq[87]
  PIN dq[88]
    DIRECTION OUTPUT ;
    USE SIGNAL ;
    PORT
      LAYER M3 ;
        RECT  15.12 36.576 15.138 36.72 ;
    END
  END dq[88]
  PIN dq[89]
    DIRECTION OUTPUT ;
    USE SIGNAL ;
    PORT
      LAYER M5 ;
        RECT  15.216 36.528 15.24 36.72 ;
    END
  END dq[89]
  PIN dq[8]
    DIRECTION OUTPUT ;
    USE SIGNAL ;
    PORT
      LAYER M3 ;
        RECT  5.364 36.576 5.382 36.72 ;
    END
  END dq[8]
  PIN dq[90]
    DIRECTION OUTPUT ;
    USE SIGNAL ;
    PORT
      LAYER M3 ;
        RECT  15.372 36.576 15.39 36.72 ;
    END
  END dq[90]
  PIN dq[91]
    DIRECTION OUTPUT ;
    USE SIGNAL ;
    PORT
      LAYER M5 ;
        RECT  15.456 36.528 15.48 36.72 ;
    END
  END dq[91]
  PIN dq[92]
    DIRECTION OUTPUT ;
    USE SIGNAL ;
    PORT
      LAYER M3 ;
        RECT  15.588 36.576 15.606 36.72 ;
    END
  END dq[92]
  PIN dq[93]
    DIRECTION OUTPUT ;
    USE SIGNAL ;
    PORT
      LAYER M5 ;
        RECT  15.744 36.528 15.768 36.72 ;
    END
  END dq[93]
  PIN dq[94]
    DIRECTION OUTPUT ;
    USE SIGNAL ;
    PORT
      LAYER M3 ;
        RECT  15.84 36.576 15.858 36.72 ;
    END
  END dq[94]
  PIN dq[95]
    DIRECTION OUTPUT ;
    USE SIGNAL ;
    PORT
      LAYER M5 ;
        RECT  15.984 36.528 16.008 36.72 ;
    END
  END dq[95]
  PIN dq[96]
    DIRECTION OUTPUT ;
    USE SIGNAL ;
    PORT
      LAYER M3 ;
        RECT  16.092 36.576 16.11 36.72 ;
    END
  END dq[96]
  PIN dq[97]
    DIRECTION OUTPUT ;
    USE SIGNAL ;
    PORT
      LAYER M5 ;
        RECT  16.224 36.528 16.248 36.72 ;
    END
  END dq[97]
  PIN dq[98]
    DIRECTION OUTPUT ;
    USE SIGNAL ;
    PORT
      LAYER M3 ;
        RECT  16.344 36.576 16.362 36.72 ;
    END
  END dq[98]
  PIN dq[99]
    DIRECTION OUTPUT ;
    USE SIGNAL ;
    PORT
      LAYER M5 ;
        RECT  16.464 36.528 16.488 36.72 ;
    END
  END dq[99]
  PIN dq[9]
    DIRECTION OUTPUT ;
    USE SIGNAL ;
    PORT
      LAYER M5 ;
        RECT  5.472 36.528 5.496 36.72 ;
    END
  END dq[9]
  PIN VDD
    DIRECTION INOUT ;
    USE POWER ;
    PORT
      LAYER M5 ;
        RECT  88.992 2.151 89.112 34.569 ;
        RECT  86.292 2.151 86.412 34.569 ;
        RECT  83.592 2.151 83.712 34.569 ;
        RECT  80.892 2.151 81.012 34.569 ;
        RECT  78.192 2.151 78.312 34.569 ;
        RECT  75.492 2.151 75.612 34.569 ;
        RECT  72.792 2.151 72.912 34.569 ;
        RECT  70.092 2.151 70.212 34.569 ;
        RECT  67.392 2.151 67.512 34.569 ;
        RECT  64.692 2.151 64.812 34.569 ;
        RECT  61.992 2.151 62.112 34.569 ;
        RECT  59.292 2.151 59.412 34.569 ;
        RECT  56.592 2.151 56.712 34.569 ;
        RECT  53.892 2.151 54.012 34.569 ;
        RECT  51.192 2.151 51.312 34.569 ;
        RECT  48.492 2.151 48.612 34.569 ;
        RECT  45.792 2.151 45.912 34.569 ;
        RECT  43.092 2.151 43.212 34.569 ;
        RECT  40.392 2.151 40.512 34.569 ;
        RECT  37.692 2.151 37.812 34.569 ;
        RECT  34.992 2.151 35.112 34.569 ;
        RECT  32.292 2.151 32.412 34.569 ;
        RECT  29.592 2.151 29.712 34.569 ;
        RECT  26.892 2.151 27.012 34.569 ;
        RECT  24.192 2.151 24.312 34.569 ;
        RECT  21.492 2.151 21.612 34.569 ;
        RECT  18.792 2.151 18.912 34.569 ;
        RECT  16.092 2.151 16.212 34.569 ;
        RECT  13.392 2.151 13.512 34.569 ;
        RECT  10.692 2.151 10.812 34.569 ;
        RECT  7.992 2.151 8.112 34.569 ;
        RECT  5.292 2.151 5.412 34.569 ;
        RECT  2.592 2.151 2.712 34.569 ;
    END
  END VDD
  PIN VSS
    DIRECTION INOUT ;
    USE GROUND ;
    PORT
      LAYER M5 ;
        RECT  88.8 2.137 88.92 34.583 ;
        RECT  86.1 2.137 86.22 34.583 ;
        RECT  83.4 2.137 83.52 34.583 ;
        RECT  80.7 2.137 80.82 34.583 ;
        RECT  78 2.137 78.12 34.583 ;
        RECT  75.3 2.137 75.42 34.583 ;
        RECT  72.6 2.137 72.72 34.583 ;
        RECT  69.9 2.137 70.02 34.583 ;
        RECT  67.2 2.137 67.32 34.583 ;
        RECT  64.5 2.137 64.62 34.583 ;
        RECT  61.8 2.137 61.92 34.583 ;
        RECT  59.1 2.137 59.22 34.583 ;
        RECT  56.4 2.137 56.52 34.583 ;
        RECT  53.7 2.137 53.82 34.583 ;
        RECT  51 2.137 51.12 34.583 ;
        RECT  48.3 2.137 48.42 34.583 ;
        RECT  45.6 2.137 45.72 34.583 ;
        RECT  42.9 2.137 43.02 34.583 ;
        RECT  40.2 2.137 40.32 34.583 ;
        RECT  37.5 2.137 37.62 34.583 ;
        RECT  34.8 2.137 34.92 34.583 ;
        RECT  32.1 2.137 32.22 34.583 ;
        RECT  29.4 2.137 29.52 34.583 ;
        RECT  26.7 2.137 26.82 34.583 ;
        RECT  24 2.137 24.12 34.583 ;
        RECT  21.3 2.137 21.42 34.583 ;
        RECT  18.6 2.137 18.72 34.583 ;
        RECT  15.9 2.137 16.02 34.583 ;
        RECT  13.2 2.137 13.32 34.583 ;
        RECT  10.5 2.137 10.62 34.583 ;
        RECT  7.8 2.137 7.92 34.583 ;
        RECT  5.1 2.137 5.22 34.583 ;
        RECT  2.4 2.137 2.52 34.583 ;
    END
  END VSS
  # OT_OBS_CLOSED layer=M5 d_um=1.536 added=132
  OBS
    LAYER RVTN ;
     RECT  2.16 2.16 90.72 2.295 ;
     RECT  2.16 2.565 90.72 2.835 ;
     RECT  2.16 3.105 90.72 3.375 ;
     RECT  2.16 3.645 90.72 3.915 ;
     RECT  2.16 4.185 90.72 4.455 ;
     RECT  2.16 4.725 90.72 4.995 ;
     RECT  2.16 5.265 90.72 5.535 ;
     RECT  2.16 5.805 90.72 6.075 ;
     RECT  2.16 6.345 90.72 6.615 ;
     RECT  2.16 6.885 90.72 7.155 ;
     RECT  2.16 7.425 90.72 7.695 ;
     RECT  2.16 7.965 90.72 8.235 ;
     RECT  2.16 8.505 90.72 8.775 ;
     RECT  2.16 9.045 90.72 9.315 ;
     RECT  2.16 9.585 90.72 9.855 ;
     RECT  2.16 10.125 90.72 10.395 ;
     RECT  2.16 10.665 90.72 10.935 ;
     RECT  2.16 11.205 90.72 11.475 ;
     RECT  2.16 11.745 90.72 12.015 ;
     RECT  2.16 12.285 90.72 12.555 ;
     RECT  2.16 12.825 90.72 13.095 ;
     RECT  2.16 13.365 90.72 13.635 ;
     RECT  2.16 13.905 90.72 14.175 ;
     RECT  2.16 14.445 90.72 14.715 ;
     RECT  2.16 14.985 90.72 15.255 ;
     RECT  2.16 15.525 90.72 15.795 ;
     RECT  2.16 16.065 90.72 16.335 ;
     RECT  2.16 16.605 90.72 16.875 ;
     RECT  2.16 17.145 90.72 17.415 ;
     RECT  2.16 17.685 90.72 17.955 ;
     RECT  2.16 18.225 90.72 18.495 ;
     RECT  2.16 18.765 90.72 19.035 ;
     RECT  2.16 19.305 90.72 19.575 ;
     RECT  2.16 19.845 90.72 20.115 ;
     RECT  2.16 20.385 90.72 20.655 ;
     RECT  2.16 20.925 90.72 21.195 ;
     RECT  2.16 21.465 90.72 21.735 ;
     RECT  2.16 22.005 90.72 22.275 ;
     RECT  2.16 22.545 90.72 22.815 ;
     RECT  2.16 23.085 90.72 23.355 ;
     RECT  2.16 23.625 90.72 23.895 ;
     RECT  2.16 24.165 90.72 24.435 ;
     RECT  2.16 24.705 90.72 24.975 ;
     RECT  2.16 25.245 90.72 25.515 ;
     RECT  2.16 25.785 90.72 26.055 ;
     RECT  2.16 26.325 90.72 26.595 ;
     RECT  2.16 26.865 90.72 27.135 ;
     RECT  2.16 27.405 90.72 27.675 ;
     RECT  2.16 27.945 90.72 28.215 ;
     RECT  2.16 28.485 90.72 28.755 ;
     RECT  2.16 29.025 90.72 29.295 ;
     RECT  2.16 29.565 90.72 29.835 ;
     RECT  2.16 30.105 90.72 30.375 ;
     RECT  2.16 30.645 90.72 30.915 ;
     RECT  2.16 31.185 90.72 31.455 ;
     RECT  2.16 31.725 90.72 31.995 ;
     RECT  2.16 32.265 90.72 32.535 ;
     RECT  2.16 32.805 90.72 33.075 ;
     RECT  2.16 33.345 90.72 33.615 ;
     RECT  2.16 33.885 90.72 34.155 ;
     RECT  2.16 34.425 90.72 34.56 ;
    LAYER RVTP ;
     RECT  2.16 2.295 90.72 2.565 ;
     RECT  2.16 2.835 90.72 3.105 ;
     RECT  2.16 3.375 90.72 3.645 ;
     RECT  2.16 3.915 90.72 4.185 ;
     RECT  2.16 4.455 90.72 4.725 ;
     RECT  2.16 4.995 90.72 5.265 ;
     RECT  2.16 5.535 90.72 5.805 ;
     RECT  2.16 6.075 90.72 6.345 ;
     RECT  2.16 6.615 90.72 6.885 ;
     RECT  2.16 7.155 90.72 7.425 ;
     RECT  2.16 7.695 90.72 7.965 ;
     RECT  2.16 8.235 90.72 8.505 ;
     RECT  2.16 8.775 90.72 9.045 ;
     RECT  2.16 9.315 90.72 9.585 ;
     RECT  2.16 9.855 90.72 10.125 ;
     RECT  2.16 10.395 90.72 10.665 ;
     RECT  2.16 10.935 90.72 11.205 ;
     RECT  2.16 11.475 90.72 11.745 ;
     RECT  2.16 12.015 90.72 12.285 ;
     RECT  2.16 12.555 90.72 12.825 ;
     RECT  2.16 13.095 90.72 13.365 ;
     RECT  2.16 13.635 90.72 13.905 ;
     RECT  2.16 14.175 90.72 14.445 ;
     RECT  2.16 14.715 90.72 14.985 ;
     RECT  2.16 15.255 90.72 15.525 ;
     RECT  2.16 15.795 90.72 16.065 ;
     RECT  2.16 16.335 90.72 16.605 ;
     RECT  2.16 16.875 90.72 17.145 ;
     RECT  2.16 17.415 90.72 17.685 ;
     RECT  2.16 17.955 90.72 18.225 ;
     RECT  2.16 18.495 90.72 18.765 ;
     RECT  2.16 19.035 90.72 19.305 ;
     RECT  2.16 19.575 90.72 19.845 ;
     RECT  2.16 20.115 90.72 20.385 ;
     RECT  2.16 20.655 90.72 20.925 ;
     RECT  2.16 21.195 90.72 21.465 ;
     RECT  2.16 21.735 90.72 22.005 ;
     RECT  2.16 22.275 90.72 22.545 ;
     RECT  2.16 22.815 90.72 23.085 ;
     RECT  2.16 23.355 90.72 23.625 ;
     RECT  2.16 23.895 90.72 24.165 ;
     RECT  2.16 24.435 90.72 24.705 ;
     RECT  2.16 24.975 90.72 25.245 ;
     RECT  2.16 25.515 90.72 25.785 ;
     RECT  2.16 26.055 90.72 26.325 ;
     RECT  2.16 26.595 90.72 26.865 ;
     RECT  2.16 27.135 90.72 27.405 ;
     RECT  2.16 27.675 90.72 27.945 ;
     RECT  2.16 28.215 90.72 28.485 ;
     RECT  2.16 28.755 90.72 29.025 ;
     RECT  2.16 29.295 90.72 29.565 ;
     RECT  2.16 29.835 90.72 30.105 ;
     RECT  2.16 30.375 90.72 30.645 ;
     RECT  2.16 30.915 90.72 31.185 ;
     RECT  2.16 31.455 90.72 31.725 ;
     RECT  2.16 31.995 90.72 32.265 ;
     RECT  2.16 32.535 90.72 32.805 ;
     RECT  2.16 33.075 90.72 33.345 ;
     RECT  2.16 33.615 90.72 33.885 ;
     RECT  2.16 34.155 90.72 34.425 ;
    LAYER M1 ;
     RECT  2.16 2.151 90.72 34.569 ;
    LAYER M2 ;
     RECT  2.16 2.151 3.847 34.569 ;
     RECT  3.847 2.106 4.603 34.569 ;
     RECT  4.603 2.106 4.891 34.794 ;
     RECT  4.891 1.728 5.135 34.794 ;
     RECT  5.251 0.144 5.387 0.162 ;
     RECT  6.079 35.901 6.287 35.919 ;
     RECT  5.135 2.151 7.771 34.569 ;
     RECT  7.771 1.728 8.159 34.569 ;
     RECT  8.023 0.144 8.195 0.162 ;
     RECT  8.527 35.901 9.203 35.919 ;
     RECT  8.159 2.151 10.651 34.569 ;
     RECT  10.471 35.982 10.723 36 ;
     RECT  10.903 0.144 11.003 0.162 ;
     RECT  10.903 1.152 11.183 1.17 ;
     RECT  11.191 1.224 11.291 1.242 ;
     RECT  10.723 35.901 11.291 36 ;
     RECT  10.651 2.106 11.435 34.569 ;
     RECT  11.291 35.901 12.407 35.919 ;
     RECT  13.387 0.144 13.559 0.162 ;
     RECT  13.387 35.901 13.639 35.919 ;
     RECT  13.639 35.901 13.847 35.964 ;
     RECT  13.847 35.946 14.495 35.964 ;
     RECT  11.435 2.151 14.647 34.569 ;
     RECT  14.647 2.106 14.783 34.569 ;
     RECT  14.611 35.901 14.927 35.919 ;
     RECT  14.783 2.151 16.087 34.569 ;
     RECT  16.087 1.728 17.051 34.569 ;
     RECT  17.051 2.151 17.311 34.569 ;
     RECT  17.311 2.151 17.663 34.794 ;
     RECT  17.663 2.151 18.023 34.758 ;
     RECT  18.571 0.144 18.751 0.162 ;
     RECT  18.679 36.558 18.779 36.648 ;
     RECT  18.779 36.558 19.003 36.576 ;
     RECT  18.751 0.144 19.031 0.234 ;
     RECT  19.031 0.144 19.355 0.162 ;
     RECT  19.183 1.152 19.355 1.17 ;
     RECT  19.003 35.901 19.543 36.576 ;
     RECT  19.543 35.901 19.643 36.648 ;
     RECT  19.643 35.901 20.479 35.919 ;
     RECT  20.407 0.144 20.507 0.162 ;
     RECT  20.479 35.901 20.579 35.964 ;
     RECT  20.579 35.946 20.903 35.964 ;
     RECT  21.271 0.144 22.523 0.162 ;
     RECT  22.207 35.946 22.991 35.964 ;
     RECT  23.179 35.901 23.855 35.919 ;
     RECT  18.023 2.151 24.403 34.569 ;
     RECT  24.403 1.728 24.719 34.569 ;
     RECT  24.719 2.151 25.123 34.569 ;
     RECT  25.123 2.151 25.375 34.794 ;
     RECT  25.375 2.151 25.547 34.839 ;
     RECT  25.519 36.558 25.619 36.648 ;
     RECT  25.619 36.558 25.655 36.576 ;
     RECT  25.547 2.151 26.239 34.794 ;
     RECT  26.239 2.106 26.699 34.794 ;
     RECT  26.563 0.144 27.059 0.162 ;
     RECT  26.699 2.151 27.059 34.794 ;
     RECT  27.571 35.901 27.823 35.919 ;
     RECT  27.059 2.151 28.039 34.569 ;
     RECT  28.039 0.144 28.139 0.162 ;
     RECT  28.039 2.151 28.247 34.794 ;
     RECT  27.823 35.901 28.283 35.964 ;
     RECT  28.283 35.946 28.751 35.964 ;
     RECT  28.247 2.151 29.335 34.569 ;
     RECT  29.371 0.144 29.543 0.162 ;
     RECT  30.019 0.576 31.055 0.594 ;
     RECT  29.335 2.151 31.171 34.794 ;
     RECT  31.171 2.151 31.271 34.884 ;
     RECT  31.271 2.151 31.307 34.839 ;
     RECT  31.307 2.151 31.459 34.794 ;
     RECT  31.459 1.728 32.063 34.794 ;
     RECT  31.711 0.144 32.243 0.162 ;
     RECT  32.063 2.151 32.863 34.794 ;
     RECT  32.863 2.151 32.963 34.839 ;
     RECT  32.963 2.151 32.999 34.794 ;
     RECT  33.187 0.144 33.287 0.162 ;
     RECT  32.999 2.151 34.879 34.569 ;
     RECT  34.879 1.728 35.159 34.65 ;
     RECT  35.159 1.728 35.375 34.569 ;
     RECT  35.779 0.144 35.879 0.162 ;
     RECT  35.375 2.151 36.787 34.569 ;
     RECT  35.131 35.901 36.959 35.919 ;
     RECT  36.787 2.106 37.391 34.569 ;
     RECT  37.391 2.151 37.435 34.569 ;
     RECT  37.435 0.144 37.607 0.162 ;
     RECT  37.435 2.151 37.607 34.65 ;
     RECT  37.831 35.901 38.435 35.919 ;
     RECT  40.243 0.144 40.595 0.162 ;
     RECT  37.607 2.151 40.747 34.569 ;
     RECT  40.747 1.728 41.135 34.569 ;
     RECT  41.135 2.151 41.719 34.569 ;
     RECT  41.719 0.144 41.855 0.162 ;
     RECT  41.719 2.151 41.971 34.794 ;
     RECT  41.971 1.728 42.179 34.794 ;
     RECT  40.243 35.901 42.215 35.919 ;
     RECT  42.179 1.728 42.359 34.758 ;
     RECT  42.359 2.151 42.943 34.758 ;
     RECT  42.943 2.151 43.259 34.794 ;
     RECT  42.871 0.144 43.763 0.162 ;
     RECT  43.259 2.151 43.915 34.569 ;
     RECT  43.915 1.728 44.555 34.569 ;
     RECT  44.555 2.151 44.671 34.569 ;
     RECT  44.671 2.151 44.879 34.794 ;
     RECT  44.887 0.144 44.987 0.162 ;
     RECT  43.195 35.901 45.239 35.919 ;
     RECT  44.879 2.151 45.643 34.569 ;
     RECT  45.643 2.151 45.779 34.65 ;
     RECT  45.779 2.151 46.111 34.569 ;
     RECT  46.111 1.656 46.211 34.569 ;
     RECT  45.859 0.144 46.463 0.162 ;
     RECT  46.111 35.901 47.399 35.919 ;
     RECT  46.211 2.151 48.199 34.569 ;
     RECT  48.199 2.151 48.335 34.65 ;
     RECT  48.235 0.144 48.659 0.162 ;
     RECT  49.783 35.901 50.423 35.919 ;
     RECT  48.335 2.151 51.007 34.569 ;
     RECT  51.007 0.144 51.179 0.162 ;
     RECT  51.007 2.151 51.179 34.65 ;
     RECT  51.727 35.901 53.087 35.919 ;
     RECT  53.671 36.558 53.807 36.648 ;
     RECT  53.707 0.144 53.879 0.162 ;
     RECT  51.179 2.151 53.923 34.569 ;
     RECT  53.923 1.728 54.059 34.794 ;
     RECT  54.059 1.728 54.527 34.569 ;
     RECT  54.527 2.151 55.291 34.569 ;
     RECT  55.291 2.151 55.391 34.758 ;
     RECT  55.147 35.901 55.463 35.919 ;
     RECT  55.391 2.151 56.623 34.569 ;
     RECT  56.623 2.151 56.875 34.794 ;
     RECT  56.875 2.151 57.011 34.839 ;
     RECT  56.623 0.144 57.191 0.162 ;
     RECT  57.011 2.151 57.803 34.794 ;
     RECT  57.343 35.901 57.947 35.919 ;
     RECT  57.803 2.151 59.071 34.569 ;
     RECT  59.071 2.07 59.323 34.569 ;
     RECT  59.323 2.07 59.791 34.794 ;
     RECT  59.791 1.728 59.819 34.794 ;
     RECT  59.819 1.728 60.035 34.569 ;
     RECT  59.791 35.901 60.215 35.919 ;
     RECT  60.035 1.8 60.647 34.569 ;
     RECT  60.647 2.151 61.735 34.569 ;
     RECT  61.987 35.901 62.447 35.919 ;
     RECT  63.715 35.901 64.139 35.919 ;
     RECT  64.183 35.982 64.319 36 ;
     RECT  61.735 2.151 64.687 34.794 ;
     RECT  64.687 2.151 64.795 34.839 ;
     RECT  64.795 1.728 64.931 34.839 ;
     RECT  64.931 1.728 64.967 34.569 ;
     RECT  64.183 0.144 65.507 0.162 ;
     RECT  64.939 35.901 65.831 35.919 ;
     RECT  64.967 2.151 66.631 34.569 ;
     RECT  66.631 1.728 67.351 34.569 ;
     RECT  67.351 1.728 67.379 34.758 ;
     RECT  67.351 0.144 67.451 0.162 ;
     RECT  67.379 2.106 67.811 34.758 ;
     RECT  67.811 2.106 68.575 34.569 ;
     RECT  68.323 35.901 68.675 35.919 ;
     RECT  68.827 36.018 69.071 36.036 ;
     RECT  69.079 0.144 69.179 0.162 ;
     RECT  68.575 2.106 69.539 34.794 ;
     RECT  69.539 2.106 70.555 34.569 ;
     RECT  70.555 1.728 71.275 34.569 ;
     RECT  71.275 1.728 71.375 34.794 ;
     RECT  71.375 2.151 71.455 34.794 ;
     RECT  71.455 2.151 71.555 34.884 ;
     RECT  71.555 2.151 71.591 34.839 ;
     RECT  71.743 35.901 73.931 35.919 ;
     RECT  73.939 0.144 74.039 0.162 ;
     RECT  71.591 2.151 74.191 34.569 ;
     RECT  74.443 36.018 74.903 36.036 ;
     RECT  74.191 2.151 75.127 34.794 ;
     RECT  75.127 2.106 75.163 34.794 ;
     RECT  75.163 1.728 75.263 34.794 ;
     RECT  75.415 0.144 75.659 0.162 ;
     RECT  75.263 2.151 77.359 34.794 ;
     RECT  77.359 2.151 77.459 34.884 ;
     RECT  75.919 35.901 77.495 35.919 ;
     RECT  77.611 36.558 77.647 36.576 ;
     RECT  77.459 2.151 78.115 34.569 ;
     RECT  77.647 36.558 78.251 36.648 ;
     RECT  78.115 1.728 78.791 34.569 ;
     RECT  78.791 2.151 78.835 34.569 ;
     RECT  78.367 35.946 79.087 36.036 ;
     RECT  78.367 0.576 79.331 0.594 ;
     RECT  79.087 35.901 79.331 36.036 ;
     RECT  79.331 35.901 79.583 36 ;
     RECT  79.583 35.982 80.239 36 ;
     RECT  78.835 2.151 80.303 34.794 ;
     RECT  80.239 35.982 80.375 36.648 ;
     RECT  80.779 0.144 80.879 0.162 ;
     RECT  80.303 2.151 81.031 34.569 ;
     RECT  80.563 35.901 81.283 35.964 ;
     RECT  81.283 35.901 82.247 36.036 ;
     RECT  82.247 36.018 82.895 36.036 ;
     RECT  81.031 2.151 83.075 34.794 ;
     RECT  83.075 2.151 83.227 34.569 ;
     RECT  83.479 35.901 83.731 35.919 ;
     RECT  83.227 1.728 83.983 34.569 ;
     RECT  83.983 1.728 84.083 34.794 ;
     RECT  84.083 1.8 84.191 34.794 ;
     RECT  83.371 0.144 84.335 0.162 ;
     RECT  83.731 35.901 84.443 35.964 ;
     RECT  84.443 35.901 84.551 35.919 ;
     RECT  84.703 0.576 85.523 0.594 ;
     RECT  84.191 2.151 86.539 34.794 ;
     RECT  86.539 2.106 86.639 34.794 ;
     RECT  85.747 0.144 86.747 0.162 ;
     RECT  86.639 2.151 86.747 34.794 ;
     RECT  86.395 35.946 86.899 35.964 ;
     RECT  86.899 35.901 87.871 35.964 ;
     RECT  87.871 35.901 87.935 36.036 ;
     RECT  86.747 2.151 88.015 34.569 ;
     RECT  87.935 36.018 88.043 36.036 ;
     RECT  88.015 2.151 88.123 34.758 ;
     RECT  88.123 2.151 88.295 34.839 ;
     RECT  88.295 2.151 88.799 34.794 ;
     RECT  88.799 2.151 90.72 34.569 ;
    LAYER M3 ;
     RECT  4.374 0.108 4.608 0.144 ;
     RECT  4.626 0.108 4.86 0.144 ;
     RECT  4.878 0.108 5.112 0.144 ;
     RECT  5.13 0.108 5.364 0.144 ;
     RECT  5.382 0.108 5.58 0.144 ;
     RECT  5.598 0.108 5.832 0.144 ;
     RECT  5.85 0.108 6.084 0.144 ;
     RECT  6.102 0.108 6.336 0.144 ;
     RECT  6.354 0.108 6.552 0.144 ;
     RECT  6.57 0.108 6.804 0.144 ;
     RECT  6.822 0.108 7.056 0.144 ;
     RECT  7.074 0.108 7.308 0.144 ;
     RECT  7.326 0.108 7.56 0.144 ;
     RECT  7.578 0.108 7.776 0.144 ;
     RECT  7.794 0.108 8.028 0.144 ;
     RECT  8.046 0.108 8.28 0.144 ;
     RECT  8.298 0.108 8.532 0.144 ;
     RECT  8.55 0.108 8.784 0.144 ;
     RECT  8.802 0.108 9 0.144 ;
     RECT  9.018 0.108 9.252 0.144 ;
     RECT  9.27 0.108 9.504 0.144 ;
     RECT  9.522 0.108 9.756 0.144 ;
     RECT  9.774 0.108 9.972 0.144 ;
     RECT  9.99 0.108 10.224 0.144 ;
     RECT  10.242 0.108 10.476 0.144 ;
     RECT  10.494 0.108 10.728 0.144 ;
     RECT  10.746 0.108 10.98 0.144 ;
     RECT  10.998 0.108 11.196 0.144 ;
     RECT  11.214 0.108 11.448 0.144 ;
     RECT  11.466 0.108 11.7 0.144 ;
     RECT  11.718 0.108 11.952 0.144 ;
     RECT  11.97 0.108 12.168 0.144 ;
     RECT  12.186 0.108 12.42 0.144 ;
     RECT  12.438 0.108 12.672 0.144 ;
     RECT  12.69 0.108 12.924 0.144 ;
     RECT  12.942 0.108 13.176 0.144 ;
     RECT  13.194 0.108 13.392 0.144 ;
     RECT  13.41 0.108 13.644 0.144 ;
     RECT  13.662 0.108 13.896 0.144 ;
     RECT  13.914 0.108 14.148 0.144 ;
     RECT  14.166 0.108 14.4 0.144 ;
     RECT  14.418 0.108 14.616 0.144 ;
     RECT  14.634 0.108 14.868 0.144 ;
     RECT  14.886 0.108 15.12 0.144 ;
     RECT  15.138 0.108 15.372 0.144 ;
     RECT  15.39 0.108 15.588 0.144 ;
     RECT  15.606 0.108 15.84 0.144 ;
     RECT  15.858 0.108 16.092 0.144 ;
     RECT  16.11 0.108 16.344 0.144 ;
     RECT  16.362 0.108 16.596 0.144 ;
     RECT  16.614 0.108 16.812 0.144 ;
     RECT  16.83 0.108 17.064 0.144 ;
     RECT  17.082 0.108 17.316 0.144 ;
     RECT  17.334 0.108 17.568 0.144 ;
     RECT  17.586 0.108 17.784 0.144 ;
     RECT  17.802 0.108 18.036 0.144 ;
     RECT  18.054 0.108 18.288 0.144 ;
     RECT  18.306 0.108 18.54 0.144 ;
     RECT  18.558 0.108 18.792 0.144 ;
     RECT  18.81 0.108 19.008 0.144 ;
     RECT  19.026 0.108 19.26 0.144 ;
     RECT  19.278 0.108 19.512 0.144 ;
     RECT  19.53 0.108 19.764 0.144 ;
     RECT  19.782 0.108 20.016 0.144 ;
     RECT  20.034 0.108 20.232 0.144 ;
     RECT  20.25 0.108 20.484 0.144 ;
     RECT  20.502 0.108 20.736 0.144 ;
     RECT  20.754 0.108 20.988 0.144 ;
     RECT  21.006 0.108 21.204 0.144 ;
     RECT  21.222 0.108 21.456 0.144 ;
     RECT  21.474 0.108 21.708 0.144 ;
     RECT  21.726 0.108 21.96 0.144 ;
     RECT  21.978 0.108 22.212 0.144 ;
     RECT  22.23 0.108 22.428 0.144 ;
     RECT  22.446 0.108 22.68 0.144 ;
     RECT  22.698 0.108 22.932 0.144 ;
     RECT  22.95 0.108 23.184 0.144 ;
     RECT  23.202 0.108 23.4 0.144 ;
     RECT  23.418 0.108 23.652 0.144 ;
     RECT  23.67 0.108 23.904 0.144 ;
     RECT  23.922 0.108 24.156 0.144 ;
     RECT  24.174 0.108 24.408 0.144 ;
     RECT  24.426 0.108 24.624 0.144 ;
     RECT  24.642 0.108 24.876 0.144 ;
     RECT  24.894 0.108 25.128 0.144 ;
     RECT  25.146 0.108 25.38 0.144 ;
     RECT  25.398 0.108 25.632 0.144 ;
     RECT  25.65 0.108 25.848 0.144 ;
     RECT  25.866 0.108 26.1 0.144 ;
     RECT  26.118 0.108 26.352 0.144 ;
     RECT  26.37 0.108 26.604 0.144 ;
     RECT  26.622 0.108 26.82 0.144 ;
     RECT  26.838 0.108 27.072 0.144 ;
     RECT  27.09 0.108 27.324 0.144 ;
     RECT  27.342 0.108 27.576 0.144 ;
     RECT  27.594 0.108 27.828 0.144 ;
     RECT  27.846 0.108 28.044 0.144 ;
     RECT  28.062 0.108 28.296 0.144 ;
     RECT  28.314 0.108 28.548 0.144 ;
     RECT  28.566 0.108 28.8 0.144 ;
     RECT  28.818 0.108 29.016 0.144 ;
     RECT  29.034 0.108 29.268 0.144 ;
     RECT  29.286 0.108 29.52 0.144 ;
     RECT  29.538 0.108 29.772 0.144 ;
     RECT  29.79 0.108 30.024 0.144 ;
     RECT  30.042 0.108 30.24 0.144 ;
     RECT  30.258 0.108 30.492 0.144 ;
     RECT  30.51 0.108 30.744 0.144 ;
     RECT  30.762 0.108 30.996 0.144 ;
     RECT  31.014 0.108 31.248 0.144 ;
     RECT  31.266 0.108 31.464 0.144 ;
     RECT  31.482 0.108 31.716 0.144 ;
     RECT  31.734 0.108 31.968 0.144 ;
     RECT  31.986 0.108 32.22 0.144 ;
     RECT  32.238 0.108 32.436 0.144 ;
     RECT  32.454 0.108 32.688 0.144 ;
     RECT  32.706 0.108 32.94 0.144 ;
     RECT  32.958 0.108 33.192 0.144 ;
     RECT  33.21 0.108 33.444 0.144 ;
     RECT  33.462 0.108 33.66 0.144 ;
     RECT  33.678 0.108 33.912 0.144 ;
     RECT  33.93 0.108 34.164 0.144 ;
     RECT  34.182 0.108 34.416 0.144 ;
     RECT  34.434 0.108 34.632 0.144 ;
     RECT  34.65 0.108 34.884 0.144 ;
     RECT  34.902 0.108 35.136 0.144 ;
     RECT  35.154 0.108 35.388 0.144 ;
     RECT  35.406 0.108 35.64 0.144 ;
     RECT  35.658 0.108 35.856 0.144 ;
     RECT  35.874 0.108 36.108 0.144 ;
     RECT  36.126 0.108 36.36 0.144 ;
     RECT  36.378 0.108 36.612 0.144 ;
     RECT  36.63 0.108 36.864 0.144 ;
     RECT  36.882 0.108 37.08 0.144 ;
     RECT  37.098 0.108 37.332 0.144 ;
     RECT  37.35 0.108 37.584 0.144 ;
     RECT  37.602 0.108 37.836 0.144 ;
     RECT  37.854 0.108 38.052 0.144 ;
     RECT  38.07 0.108 38.304 0.144 ;
     RECT  38.322 0.108 38.556 0.144 ;
     RECT  38.574 0.108 38.808 0.144 ;
     RECT  38.826 0.108 39.06 0.144 ;
     RECT  39.078 0.108 39.276 0.144 ;
     RECT  39.294 0.108 39.528 0.144 ;
     RECT  39.546 0.108 39.78 0.144 ;
     RECT  39.798 0.108 40.032 0.144 ;
     RECT  40.05 0.108 40.248 0.144 ;
     RECT  40.266 0.108 40.5 0.144 ;
     RECT  40.518 0.108 40.752 0.144 ;
     RECT  40.77 0.108 41.004 0.144 ;
     RECT  41.022 0.108 41.256 0.144 ;
     RECT  41.274 0.108 41.472 0.144 ;
     RECT  41.49 0.108 41.724 0.144 ;
     RECT  41.742 0.108 41.976 0.144 ;
     RECT  41.994 0.108 42.228 0.144 ;
     RECT  42.246 0.108 42.48 0.144 ;
     RECT  42.498 0.108 42.696 0.144 ;
     RECT  42.714 0.108 42.948 0.144 ;
     RECT  42.966 0.108 43.2 0.144 ;
     RECT  43.218 0.108 43.452 0.144 ;
     RECT  43.47 0.108 43.668 0.144 ;
     RECT  43.686 0.108 43.92 0.144 ;
     RECT  43.938 0.108 44.172 0.144 ;
     RECT  44.19 0.108 44.424 0.144 ;
     RECT  44.442 0.108 44.676 0.144 ;
     RECT  44.694 0.108 44.892 0.144 ;
     RECT  44.91 0.108 45.144 0.144 ;
     RECT  45.162 0.108 45.396 0.144 ;
     RECT  45.414 0.108 45.648 0.144 ;
     RECT  45.666 0.108 45.864 0.144 ;
     RECT  45.882 0.108 46.116 0.144 ;
     RECT  46.134 0.108 46.368 0.144 ;
     RECT  46.386 0.108 46.62 0.144 ;
     RECT  46.638 0.108 46.872 0.144 ;
     RECT  46.89 0.108 47.088 0.144 ;
     RECT  47.106 0.108 47.34 0.144 ;
     RECT  47.358 0.108 47.592 0.144 ;
     RECT  47.61 0.108 47.844 0.144 ;
     RECT  47.862 0.108 48.096 0.144 ;
     RECT  48.114 0.108 48.312 0.144 ;
     RECT  48.33 0.108 48.564 0.144 ;
     RECT  48.582 0.108 48.816 0.144 ;
     RECT  48.834 0.108 49.068 0.144 ;
     RECT  49.086 0.108 49.284 0.144 ;
     RECT  49.302 0.108 49.536 0.144 ;
     RECT  49.554 0.108 49.788 0.144 ;
     RECT  49.806 0.108 50.04 0.144 ;
     RECT  50.058 0.108 50.292 0.144 ;
     RECT  50.31 0.108 50.508 0.144 ;
     RECT  50.526 0.108 50.76 0.144 ;
     RECT  50.778 0.108 51.012 0.144 ;
     RECT  51.03 0.108 51.264 0.144 ;
     RECT  51.282 0.108 51.48 0.144 ;
     RECT  51.498 0.108 51.732 0.144 ;
     RECT  51.75 0.108 51.984 0.144 ;
     RECT  52.002 0.108 52.236 0.144 ;
     RECT  52.254 0.108 52.488 0.144 ;
     RECT  52.506 0.108 52.704 0.144 ;
     RECT  52.722 0.108 52.956 0.144 ;
     RECT  52.974 0.108 53.208 0.144 ;
     RECT  53.226 0.108 53.46 0.144 ;
     RECT  53.478 0.108 53.712 0.144 ;
     RECT  53.73 0.108 53.928 0.144 ;
     RECT  53.946 0.108 54.18 0.144 ;
     RECT  54.198 0.108 54.432 0.144 ;
     RECT  54.45 0.108 54.684 0.144 ;
     RECT  54.702 0.108 54.9 0.144 ;
     RECT  54.918 0.108 55.152 0.144 ;
     RECT  55.17 0.108 55.404 0.144 ;
     RECT  55.422 0.108 55.656 0.144 ;
     RECT  55.674 0.108 55.908 0.144 ;
     RECT  55.926 0.108 56.124 0.144 ;
     RECT  56.142 0.108 56.376 0.144 ;
     RECT  56.394 0.108 56.628 0.144 ;
     RECT  56.646 0.108 56.88 0.144 ;
     RECT  56.898 0.108 57.096 0.144 ;
     RECT  57.114 0.108 57.348 0.144 ;
     RECT  57.366 0.108 57.6 0.144 ;
     RECT  57.618 0.108 57.852 0.144 ;
     RECT  57.87 0.108 58.104 0.144 ;
     RECT  58.122 0.108 58.32 0.144 ;
     RECT  58.338 0.108 58.572 0.144 ;
     RECT  58.59 0.108 58.824 0.144 ;
     RECT  58.842 0.108 59.076 0.144 ;
     RECT  59.094 0.108 59.328 0.144 ;
     RECT  59.346 0.108 59.544 0.144 ;
     RECT  59.562 0.108 59.796 0.144 ;
     RECT  59.814 0.108 60.048 0.144 ;
     RECT  60.066 0.108 60.3 0.144 ;
     RECT  60.318 0.108 60.516 0.144 ;
     RECT  60.534 0.108 60.768 0.144 ;
     RECT  60.786 0.108 61.02 0.144 ;
     RECT  61.038 0.108 61.272 0.144 ;
     RECT  61.29 0.108 61.524 0.144 ;
     RECT  61.542 0.108 61.74 0.144 ;
     RECT  61.758 0.108 61.992 0.144 ;
     RECT  62.01 0.108 62.244 0.144 ;
     RECT  62.262 0.108 62.496 0.144 ;
     RECT  62.514 0.108 62.712 0.144 ;
     RECT  62.73 0.108 62.964 0.144 ;
     RECT  62.982 0.108 63.216 0.144 ;
     RECT  63.234 0.108 63.468 0.144 ;
     RECT  63.486 0.108 63.72 0.144 ;
     RECT  63.738 0.108 63.936 0.144 ;
     RECT  63.954 0.108 64.188 0.144 ;
     RECT  64.206 0.108 64.44 0.144 ;
     RECT  64.458 0.108 64.692 0.144 ;
     RECT  64.71 0.108 64.944 0.144 ;
     RECT  64.962 0.108 65.16 0.144 ;
     RECT  65.178 0.108 65.412 0.144 ;
     RECT  65.43 0.108 65.664 0.144 ;
     RECT  65.682 0.108 65.916 0.144 ;
     RECT  65.934 0.108 66.132 0.144 ;
     RECT  66.15 0.108 66.384 0.144 ;
     RECT  66.402 0.108 66.636 0.144 ;
     RECT  66.654 0.108 66.888 0.144 ;
     RECT  66.906 0.108 67.14 0.144 ;
     RECT  67.158 0.108 67.356 0.144 ;
     RECT  67.374 0.108 67.608 0.144 ;
     RECT  67.626 0.108 67.86 0.144 ;
     RECT  67.878 0.108 68.112 0.144 ;
     RECT  68.13 0.108 68.328 0.144 ;
     RECT  68.346 0.108 68.58 0.144 ;
     RECT  68.598 0.108 68.832 0.144 ;
     RECT  68.85 0.108 69.084 0.144 ;
     RECT  69.102 0.108 69.336 0.144 ;
     RECT  69.354 0.108 69.552 0.144 ;
     RECT  69.57 0.108 69.804 0.144 ;
     RECT  69.822 0.108 70.056 0.144 ;
     RECT  70.074 0.108 70.308 0.144 ;
     RECT  70.326 0.108 70.56 0.144 ;
     RECT  70.578 0.108 70.776 0.144 ;
     RECT  70.794 0.108 71.028 0.144 ;
     RECT  71.046 0.108 71.28 0.144 ;
     RECT  71.298 0.108 71.532 0.144 ;
     RECT  71.55 0.108 71.748 0.144 ;
     RECT  71.766 0.108 72 0.144 ;
     RECT  72.018 0.108 72.252 0.144 ;
     RECT  72.27 0.108 72.504 0.144 ;
     RECT  72.522 0.108 72.756 0.144 ;
     RECT  72.774 0.108 72.972 0.144 ;
     RECT  72.99 0.108 73.224 0.144 ;
     RECT  73.242 0.108 73.476 0.144 ;
     RECT  73.494 0.108 73.728 0.144 ;
     RECT  73.746 0.108 73.944 0.144 ;
     RECT  73.962 0.108 74.196 0.144 ;
     RECT  74.214 0.108 74.448 0.144 ;
     RECT  74.466 0.108 74.7 0.144 ;
     RECT  74.718 0.108 74.952 0.144 ;
     RECT  74.97 0.108 75.168 0.144 ;
     RECT  75.186 0.108 75.42 0.144 ;
     RECT  75.438 0.108 75.672 0.144 ;
     RECT  75.69 0.108 75.924 0.144 ;
     RECT  75.942 0.108 76.176 0.144 ;
     RECT  76.194 0.108 76.392 0.144 ;
     RECT  76.41 0.108 76.644 0.144 ;
     RECT  76.662 0.108 76.896 0.144 ;
     RECT  76.914 0.108 77.148 0.144 ;
     RECT  77.166 0.108 77.364 0.144 ;
     RECT  77.382 0.108 77.616 0.144 ;
     RECT  77.634 0.108 77.868 0.144 ;
     RECT  77.886 0.108 78.12 0.144 ;
     RECT  78.138 0.108 78.372 0.144 ;
     RECT  78.39 0.108 78.588 0.144 ;
     RECT  78.606 0.108 78.84 0.144 ;
     RECT  78.858 0.108 79.092 0.144 ;
     RECT  79.11 0.108 79.344 0.144 ;
     RECT  79.362 0.108 79.56 0.144 ;
     RECT  79.578 0.108 79.812 0.144 ;
     RECT  79.83 0.108 80.064 0.144 ;
     RECT  80.082 0.108 80.316 0.144 ;
     RECT  80.334 0.108 80.568 0.144 ;
     RECT  80.586 0.108 80.784 0.144 ;
     RECT  80.802 0.108 81.036 0.144 ;
     RECT  81.054 0.108 81.288 0.144 ;
     RECT  81.306 0.108 81.54 0.144 ;
     RECT  81.558 0.108 81.792 0.144 ;
     RECT  81.81 0.108 82.008 0.144 ;
     RECT  82.026 0.108 82.26 0.144 ;
     RECT  82.278 0.108 82.512 0.144 ;
     RECT  82.53 0.108 82.764 0.144 ;
     RECT  82.782 0.108 82.98 0.144 ;
     RECT  82.998 0.108 83.232 0.144 ;
     RECT  83.25 0.108 83.484 0.144 ;
     RECT  83.502 0.108 83.736 0.144 ;
     RECT  83.754 0.108 83.988 0.144 ;
     RECT  84.006 0.108 84.204 0.144 ;
     RECT  84.222 0.108 84.456 0.144 ;
     RECT  84.474 0.108 84.708 0.144 ;
     RECT  84.726 0.108 84.96 0.144 ;
     RECT  84.978 0.108 85.176 0.144 ;
     RECT  85.194 0.108 85.428 0.144 ;
     RECT  85.446 0.108 85.68 0.144 ;
     RECT  85.698 0.108 85.932 0.144 ;
     RECT  85.95 0.108 86.184 0.144 ;
     RECT  86.202 0.108 86.4 0.144 ;
     RECT  86.418 0.108 86.652 0.144 ;
     RECT  86.67 0.108 86.904 0.144 ;
     RECT  86.922 0.108 87.156 0.144 ;
     RECT  87.174 0.108 87.408 0.144 ;
     RECT  87.426 0.108 87.624 0.144 ;
     RECT  87.642 0.108 87.876 0.144 ;
     RECT  87.894 0.108 88.128 0.144 ;
     RECT  88.146 0.108 88.38 0.144 ;
     RECT  4.356 0.144 88.398 0.221 ;
     RECT  4.356 0.221 72.99 0.317 ;
     RECT  4.356 0.317 37.458 0.557 ;
     RECT  36.612 0.557 37.458 1.723 ;
     RECT  38.304 0.317 72.99 1.723 ;
     RECT  73.728 0.221 88.398 1.723 ;
     RECT  4.356 0.557 35.802 2.101 ;
     RECT  36.612 1.723 88.65 2.143 ;
     RECT  3.852 2.101 35.802 2.191 ;
     RECT  36.612 2.143 88.905 2.191 ;
     RECT  3.852 2.191 90.018 2.227 ;
     RECT  3.852 2.227 90.594 2.255 ;
     RECT  2.415 2.143 2.505 2.413 ;
     RECT  4.068 2.255 90.594 3.181 ;
     RECT  4.032 3.181 90.594 3.839 ;
     RECT  4.248 3.839 90.594 3.911 ;
     RECT  4.644 3.911 90.594 4.765 ;
     RECT  4.572 4.765 90.594 4.955 ;
     RECT  4.644 4.955 90.594 5.369 ;
     RECT  4.716 5.369 90.594 5.495 ;
     RECT  4.824 5.495 90.594 7.349 ;
     RECT  4.824 7.349 77.022 7.691 ;
     RECT  77.76 7.349 90.594 8.303 ;
     RECT  4.824 7.691 76.986 8.581 ;
     RECT  4.824 8.581 77.058 9.121 ;
     RECT  77.796 8.303 90.594 9.121 ;
     RECT  4.824 9.121 90.594 10.193 ;
     RECT  4.824 10.193 90.378 10.625 ;
     RECT  4.932 10.625 90.378 10.733 ;
     RECT  4.932 10.733 90.162 11.435 ;
     RECT  4.932 11.435 90.054 16.537 ;
     RECT  4.896 16.537 90.054 17.491 ;
     RECT  4.608 17.491 90.054 17.681 ;
     RECT  4.608 17.681 89.838 18.185 ;
     RECT  4.608 18.185 89.802 18.995 ;
     RECT  4.608 18.995 89.73 19.381 ;
     RECT  4.572 19.381 89.73 19.913 ;
     RECT  4.572 19.913 89.406 19.921 ;
     RECT  4.5 19.921 89.406 20.183 ;
     RECT  4.5 20.183 89.262 28.445 ;
     RECT  4.5 28.445 89.097 28.561 ;
     RECT  4.356 28.561 89.097 28.715 ;
     RECT  2.415 2.413 2.697 34.307 ;
     RECT  28.224 28.715 89.097 34.307 ;
     RECT  2.415 34.307 2.505 34.577 ;
     RECT  4.356 28.715 27.342 34.771 ;
     RECT  28.224 34.307 88.974 34.771 ;
     RECT  4.356 34.771 88.974 35.933 ;
     RECT  4.356 35.933 88.398 36.576 ;
     RECT  4.374 36.576 4.608 36.588 ;
     RECT  4.626 36.576 4.86 36.588 ;
     RECT  4.878 36.576 5.112 36.588 ;
     RECT  5.13 36.576 5.364 36.588 ;
     RECT  5.382 36.576 5.58 36.588 ;
     RECT  5.598 36.576 5.832 36.588 ;
     RECT  5.85 36.576 6.084 36.588 ;
     RECT  6.102 36.576 6.336 36.588 ;
     RECT  6.354 36.576 6.552 36.588 ;
     RECT  6.57 36.576 6.804 36.588 ;
     RECT  6.822 36.576 7.056 36.588 ;
     RECT  7.074 36.576 7.308 36.588 ;
     RECT  7.326 36.576 7.56 36.588 ;
     RECT  7.578 36.576 7.776 36.588 ;
     RECT  7.794 36.576 8.028 36.588 ;
     RECT  8.046 36.576 8.28 36.588 ;
     RECT  8.298 36.576 8.532 36.588 ;
     RECT  8.55 36.576 8.784 36.588 ;
     RECT  8.802 36.576 9 36.588 ;
     RECT  9.018 36.576 9.252 36.588 ;
     RECT  9.27 36.576 9.504 36.588 ;
     RECT  9.522 36.576 9.756 36.588 ;
     RECT  9.774 36.576 9.972 36.588 ;
     RECT  9.99 36.576 10.224 36.588 ;
     RECT  10.242 36.576 10.476 36.588 ;
     RECT  10.494 36.576 10.728 36.588 ;
     RECT  10.746 36.576 10.98 36.588 ;
     RECT  10.998 36.576 11.196 36.588 ;
     RECT  11.214 36.576 11.448 36.588 ;
     RECT  11.466 36.576 11.7 36.588 ;
     RECT  11.718 36.576 11.952 36.588 ;
     RECT  11.97 36.576 12.168 36.588 ;
     RECT  12.186 36.576 12.42 36.588 ;
     RECT  12.438 36.576 12.672 36.588 ;
     RECT  12.69 36.576 12.924 36.588 ;
     RECT  12.942 36.576 13.176 36.588 ;
     RECT  13.194 36.576 13.392 36.588 ;
     RECT  13.41 36.576 13.644 36.588 ;
     RECT  13.662 36.576 13.896 36.588 ;
     RECT  13.914 36.576 14.148 36.588 ;
     RECT  14.166 36.576 14.4 36.588 ;
     RECT  14.418 36.576 14.616 36.588 ;
     RECT  14.634 36.576 14.868 36.588 ;
     RECT  14.886 36.576 15.12 36.588 ;
     RECT  15.138 36.576 15.372 36.588 ;
     RECT  15.39 36.576 15.588 36.588 ;
     RECT  15.606 36.576 15.84 36.588 ;
     RECT  15.858 36.576 16.092 36.588 ;
     RECT  16.11 36.576 16.344 36.588 ;
     RECT  16.362 36.576 16.596 36.588 ;
     RECT  16.614 36.576 16.812 36.588 ;
     RECT  16.83 36.576 17.064 36.588 ;
     RECT  17.082 36.576 17.316 36.588 ;
     RECT  17.334 36.576 17.568 36.588 ;
     RECT  17.586 36.576 17.784 36.588 ;
     RECT  17.802 36.576 18.036 36.588 ;
     RECT  18.054 36.576 18.288 36.588 ;
     RECT  18.306 36.576 18.54 36.588 ;
     RECT  18.558 36.576 18.792 36.588 ;
     RECT  18.81 36.576 19.008 36.588 ;
     RECT  19.026 36.576 19.26 36.588 ;
     RECT  19.278 36.576 19.512 36.588 ;
     RECT  19.53 36.576 19.764 36.588 ;
     RECT  19.782 36.576 20.016 36.588 ;
     RECT  20.034 36.576 20.232 36.588 ;
     RECT  20.25 36.576 20.484 36.588 ;
     RECT  20.502 36.576 20.736 36.588 ;
     RECT  20.754 36.576 20.988 36.588 ;
     RECT  21.006 36.576 21.204 36.588 ;
     RECT  21.222 36.576 21.456 36.588 ;
     RECT  21.474 36.576 21.708 36.588 ;
     RECT  21.726 36.576 21.96 36.588 ;
     RECT  21.978 36.576 22.212 36.588 ;
     RECT  22.23 36.576 22.428 36.588 ;
     RECT  22.446 36.576 22.68 36.588 ;
     RECT  22.698 36.576 22.932 36.588 ;
     RECT  22.95 36.576 23.184 36.588 ;
     RECT  23.202 36.576 23.4 36.588 ;
     RECT  23.418 36.576 23.652 36.588 ;
     RECT  23.67 36.576 23.904 36.588 ;
     RECT  23.922 36.576 24.156 36.588 ;
     RECT  24.174 36.576 24.408 36.588 ;
     RECT  24.426 36.576 24.624 36.588 ;
     RECT  24.642 36.576 24.876 36.588 ;
     RECT  24.894 36.576 25.128 36.588 ;
     RECT  25.146 36.576 25.38 36.588 ;
     RECT  25.398 36.576 25.632 36.588 ;
     RECT  25.65 36.576 25.848 36.588 ;
     RECT  25.866 36.576 26.1 36.588 ;
     RECT  26.118 36.576 26.352 36.588 ;
     RECT  26.37 36.576 26.604 36.588 ;
     RECT  26.622 36.576 26.82 36.588 ;
     RECT  26.838 36.576 27.072 36.588 ;
     RECT  27.09 36.576 27.324 36.588 ;
     RECT  27.342 36.576 27.576 36.588 ;
     RECT  27.594 36.576 27.828 36.588 ;
     RECT  27.846 36.576 28.044 36.588 ;
     RECT  28.062 36.576 28.296 36.588 ;
     RECT  28.314 36.576 28.548 36.588 ;
     RECT  28.566 36.576 28.8 36.588 ;
     RECT  28.818 36.576 29.016 36.588 ;
     RECT  29.034 36.576 29.268 36.588 ;
     RECT  29.286 36.576 29.52 36.588 ;
     RECT  29.538 36.576 29.772 36.588 ;
     RECT  29.79 36.576 30.024 36.588 ;
     RECT  30.042 36.576 30.24 36.588 ;
     RECT  30.258 36.576 30.492 36.588 ;
     RECT  30.51 36.576 30.744 36.588 ;
     RECT  30.762 36.576 30.996 36.588 ;
     RECT  31.014 36.576 31.248 36.588 ;
     RECT  31.266 36.576 31.464 36.588 ;
     RECT  31.482 36.576 31.716 36.588 ;
     RECT  31.734 36.576 31.968 36.588 ;
     RECT  31.986 36.576 32.22 36.588 ;
     RECT  32.238 36.576 32.436 36.588 ;
     RECT  32.454 36.576 32.688 36.588 ;
     RECT  32.706 36.576 32.94 36.588 ;
     RECT  32.958 36.576 33.192 36.588 ;
     RECT  33.21 36.576 33.444 36.588 ;
     RECT  33.462 36.576 33.66 36.588 ;
     RECT  33.678 36.576 33.912 36.588 ;
     RECT  33.93 36.576 34.164 36.588 ;
     RECT  34.182 36.576 34.416 36.588 ;
     RECT  34.434 36.576 34.632 36.588 ;
     RECT  34.65 36.576 34.884 36.588 ;
     RECT  34.902 36.576 35.136 36.588 ;
     RECT  35.154 36.576 35.388 36.588 ;
     RECT  35.406 36.576 35.64 36.588 ;
     RECT  35.658 36.576 35.856 36.588 ;
     RECT  35.874 36.576 36.108 36.588 ;
     RECT  36.126 36.576 36.36 36.588 ;
     RECT  36.378 36.576 36.612 36.588 ;
     RECT  36.63 36.576 36.864 36.588 ;
     RECT  36.882 36.576 37.08 36.588 ;
     RECT  37.098 36.576 37.332 36.588 ;
     RECT  37.35 36.576 37.584 36.588 ;
     RECT  37.602 36.576 37.836 36.588 ;
     RECT  37.854 36.576 38.052 36.588 ;
     RECT  38.07 36.576 38.304 36.588 ;
     RECT  38.322 36.576 38.556 36.588 ;
     RECT  38.574 36.576 38.808 36.588 ;
     RECT  38.826 36.576 39.06 36.588 ;
     RECT  39.078 36.576 39.276 36.588 ;
     RECT  39.294 36.576 39.528 36.588 ;
     RECT  39.546 36.576 39.78 36.588 ;
     RECT  39.798 36.576 40.032 36.588 ;
     RECT  40.05 36.576 40.248 36.588 ;
     RECT  40.266 36.576 40.5 36.588 ;
     RECT  40.518 36.576 40.752 36.588 ;
     RECT  40.77 36.576 41.004 36.588 ;
     RECT  41.022 36.576 41.256 36.588 ;
     RECT  41.274 36.576 41.472 36.588 ;
     RECT  41.49 36.576 41.724 36.588 ;
     RECT  41.742 36.576 41.976 36.588 ;
     RECT  41.994 36.576 42.228 36.588 ;
     RECT  42.246 36.576 42.48 36.588 ;
     RECT  42.498 36.576 42.696 36.588 ;
     RECT  42.714 36.576 42.948 36.588 ;
     RECT  42.966 36.576 43.2 36.588 ;
     RECT  43.218 36.576 43.452 36.588 ;
     RECT  43.47 36.576 43.668 36.588 ;
     RECT  43.686 36.576 43.92 36.588 ;
     RECT  43.938 36.576 44.172 36.588 ;
     RECT  44.19 36.576 44.424 36.588 ;
     RECT  44.442 36.576 44.676 36.588 ;
     RECT  44.694 36.576 44.892 36.588 ;
     RECT  44.91 36.576 45.144 36.588 ;
     RECT  45.162 36.576 45.396 36.588 ;
     RECT  45.414 36.576 45.648 36.588 ;
     RECT  45.666 36.576 45.864 36.588 ;
     RECT  45.882 36.576 46.116 36.588 ;
     RECT  46.134 36.576 46.368 36.588 ;
     RECT  46.386 36.576 46.62 36.588 ;
     RECT  46.638 36.576 46.872 36.588 ;
     RECT  46.89 36.576 47.088 36.588 ;
     RECT  47.106 36.576 47.34 36.588 ;
     RECT  47.358 36.576 47.592 36.588 ;
     RECT  47.61 36.576 47.844 36.588 ;
     RECT  47.862 36.576 48.096 36.588 ;
     RECT  48.114 36.576 48.312 36.588 ;
     RECT  48.33 36.576 48.564 36.588 ;
     RECT  48.582 36.576 48.816 36.588 ;
     RECT  48.834 36.576 49.068 36.588 ;
     RECT  49.086 36.576 49.284 36.588 ;
     RECT  49.302 36.576 49.536 36.588 ;
     RECT  49.554 36.576 49.788 36.588 ;
     RECT  49.806 36.576 50.04 36.588 ;
     RECT  50.058 36.576 50.292 36.588 ;
     RECT  50.31 36.576 50.508 36.588 ;
     RECT  50.526 36.576 50.76 36.588 ;
     RECT  50.778 36.576 51.012 36.588 ;
     RECT  51.03 36.576 51.264 36.588 ;
     RECT  51.282 36.576 51.48 36.588 ;
     RECT  51.498 36.576 51.732 36.588 ;
     RECT  51.75 36.576 51.984 36.588 ;
     RECT  52.002 36.576 52.236 36.588 ;
     RECT  52.254 36.576 52.488 36.588 ;
     RECT  52.506 36.576 52.704 36.588 ;
     RECT  52.722 36.576 52.956 36.588 ;
     RECT  52.974 36.576 53.208 36.588 ;
     RECT  53.226 36.576 53.46 36.588 ;
     RECT  53.478 36.576 53.712 36.588 ;
     RECT  53.73 36.576 53.928 36.588 ;
     RECT  53.946 36.576 54.18 36.588 ;
     RECT  54.198 36.576 54.432 36.588 ;
     RECT  54.45 36.576 54.684 36.588 ;
     RECT  54.702 36.576 54.9 36.588 ;
     RECT  54.918 36.576 55.152 36.588 ;
     RECT  55.17 36.576 55.404 36.588 ;
     RECT  55.422 36.576 55.656 36.588 ;
     RECT  55.674 36.576 55.908 36.588 ;
     RECT  55.926 36.576 56.124 36.588 ;
     RECT  56.142 36.576 56.376 36.588 ;
     RECT  56.394 36.576 56.628 36.588 ;
     RECT  56.646 36.576 56.88 36.588 ;
     RECT  56.898 36.576 57.096 36.588 ;
     RECT  57.114 36.576 57.348 36.588 ;
     RECT  57.366 36.576 57.6 36.588 ;
     RECT  57.618 36.576 57.852 36.588 ;
     RECT  57.87 36.576 58.104 36.588 ;
     RECT  58.122 36.576 58.32 36.588 ;
     RECT  58.338 36.576 58.572 36.588 ;
     RECT  58.59 36.576 58.824 36.588 ;
     RECT  58.842 36.576 59.076 36.588 ;
     RECT  59.094 36.576 59.328 36.588 ;
     RECT  59.346 36.576 59.544 36.588 ;
     RECT  59.562 36.576 59.796 36.588 ;
     RECT  59.814 36.576 60.048 36.588 ;
     RECT  60.066 36.576 60.3 36.588 ;
     RECT  60.318 36.576 60.516 36.588 ;
     RECT  60.534 36.576 60.768 36.588 ;
     RECT  60.786 36.576 61.02 36.588 ;
     RECT  61.038 36.576 61.272 36.588 ;
     RECT  61.29 36.576 61.524 36.588 ;
     RECT  61.542 36.576 61.74 36.588 ;
     RECT  61.758 36.576 61.992 36.588 ;
     RECT  62.01 36.576 62.244 36.588 ;
     RECT  62.262 36.576 62.496 36.588 ;
     RECT  62.514 36.576 62.712 36.588 ;
     RECT  62.73 36.576 62.964 36.588 ;
     RECT  62.982 36.576 63.216 36.588 ;
     RECT  63.234 36.576 63.468 36.588 ;
     RECT  63.486 36.576 63.72 36.588 ;
     RECT  63.738 36.576 63.936 36.588 ;
     RECT  63.954 36.576 64.188 36.588 ;
     RECT  64.206 36.576 64.44 36.588 ;
     RECT  64.458 36.576 64.692 36.588 ;
     RECT  64.71 36.576 64.944 36.588 ;
     RECT  64.962 36.576 65.16 36.588 ;
     RECT  65.178 36.576 65.412 36.588 ;
     RECT  65.43 36.576 65.664 36.588 ;
     RECT  65.682 36.576 65.916 36.588 ;
     RECT  65.934 36.576 66.132 36.588 ;
     RECT  66.15 36.576 66.384 36.588 ;
     RECT  66.402 36.576 66.636 36.588 ;
     RECT  66.654 36.576 66.888 36.588 ;
     RECT  66.906 36.576 67.14 36.588 ;
     RECT  67.158 36.576 67.356 36.588 ;
     RECT  67.374 36.576 67.608 36.588 ;
     RECT  67.626 36.576 67.86 36.588 ;
     RECT  67.878 36.576 68.112 36.588 ;
     RECT  68.13 36.576 68.328 36.588 ;
     RECT  68.346 36.576 68.58 36.588 ;
     RECT  68.598 36.576 68.832 36.588 ;
     RECT  68.85 36.576 69.084 36.588 ;
     RECT  69.102 36.576 69.336 36.588 ;
     RECT  69.354 36.576 69.552 36.588 ;
     RECT  69.57 36.576 69.804 36.588 ;
     RECT  69.822 36.576 70.056 36.588 ;
     RECT  70.074 36.576 70.308 36.588 ;
     RECT  70.326 36.576 70.56 36.588 ;
     RECT  70.578 36.576 70.776 36.588 ;
     RECT  70.794 36.576 71.028 36.588 ;
     RECT  71.046 36.576 71.28 36.588 ;
     RECT  71.298 36.576 71.532 36.588 ;
     RECT  71.55 36.576 71.748 36.588 ;
     RECT  71.766 36.576 72 36.588 ;
     RECT  72.018 36.576 72.252 36.588 ;
     RECT  72.27 36.576 72.504 36.588 ;
     RECT  72.522 36.576 72.756 36.588 ;
     RECT  72.774 36.576 72.972 36.588 ;
     RECT  72.99 36.576 73.224 36.588 ;
     RECT  73.242 36.576 73.476 36.588 ;
     RECT  73.494 36.576 73.728 36.588 ;
     RECT  73.746 36.576 73.944 36.588 ;
     RECT  73.962 36.576 74.196 36.588 ;
     RECT  74.214 36.576 74.448 36.588 ;
     RECT  74.466 36.576 74.7 36.588 ;
     RECT  74.718 36.576 74.952 36.588 ;
     RECT  74.97 36.576 75.168 36.588 ;
     RECT  75.186 36.576 75.42 36.588 ;
     RECT  75.438 36.576 75.672 36.588 ;
     RECT  75.69 36.576 75.924 36.588 ;
     RECT  75.942 36.576 76.176 36.588 ;
     RECT  76.194 36.576 76.392 36.588 ;
     RECT  76.41 36.576 76.644 36.588 ;
     RECT  76.662 36.576 76.896 36.588 ;
     RECT  76.914 36.576 77.148 36.588 ;
     RECT  77.166 36.576 77.364 36.588 ;
     RECT  77.382 36.576 77.616 36.588 ;
     RECT  77.634 36.576 77.868 36.588 ;
     RECT  77.886 36.576 78.12 36.588 ;
     RECT  78.138 36.576 78.372 36.588 ;
     RECT  78.39 36.576 78.588 36.588 ;
     RECT  78.606 36.576 78.84 36.588 ;
     RECT  78.858 36.576 79.092 36.588 ;
     RECT  79.11 36.576 79.344 36.588 ;
     RECT  79.362 36.576 79.56 36.588 ;
     RECT  79.578 36.576 79.812 36.588 ;
     RECT  79.83 36.576 80.064 36.588 ;
     RECT  80.082 36.576 80.316 36.588 ;
     RECT  80.334 36.576 80.568 36.588 ;
     RECT  80.586 36.576 80.784 36.588 ;
     RECT  80.802 36.576 81.036 36.588 ;
     RECT  81.054 36.576 81.288 36.588 ;
     RECT  81.306 36.576 81.54 36.588 ;
     RECT  81.558 36.576 81.792 36.588 ;
     RECT  81.81 36.576 82.008 36.588 ;
     RECT  82.026 36.576 82.26 36.588 ;
     RECT  82.278 36.576 82.512 36.588 ;
     RECT  82.53 36.576 82.764 36.588 ;
     RECT  82.782 36.576 82.98 36.588 ;
     RECT  82.998 36.576 83.232 36.588 ;
     RECT  83.25 36.576 83.484 36.588 ;
     RECT  83.502 36.576 83.736 36.588 ;
     RECT  83.754 36.576 83.988 36.588 ;
     RECT  84.006 36.576 84.204 36.588 ;
     RECT  84.222 36.576 84.456 36.588 ;
     RECT  84.474 36.576 84.708 36.588 ;
     RECT  84.726 36.576 84.96 36.588 ;
     RECT  84.978 36.576 85.176 36.588 ;
     RECT  85.194 36.576 85.428 36.588 ;
     RECT  85.446 36.576 85.68 36.588 ;
     RECT  85.698 36.576 85.932 36.588 ;
     RECT  85.95 36.576 86.184 36.588 ;
     RECT  86.202 36.576 86.4 36.588 ;
     RECT  86.418 36.576 86.652 36.588 ;
     RECT  86.67 36.576 86.904 36.588 ;
     RECT  86.922 36.576 87.156 36.588 ;
     RECT  87.174 36.576 87.408 36.588 ;
     RECT  87.426 36.576 87.624 36.588 ;
     RECT  87.642 36.576 87.876 36.588 ;
     RECT  87.894 36.576 88.128 36.588 ;
     RECT  88.146 36.576 88.38 36.588 ;
     RECT  18.684 36.588 18.774 36.653 ;
     RECT  19.548 36.588 19.638 36.653 ;
     RECT  25.524 36.588 25.614 36.653 ;
     RECT  77.652 36.588 77.868 36.653 ;
     RECT  77.886 36.588 78.12 36.653 ;
     RECT  78.138 36.588 78.246 36.653 ;
    LAYER M4 ;
     RECT  0.229 6.096 2.408 6.12 ;
     RECT  2.408 2.148 2.512 34.572 ;
     RECT  2.512 2.418 2.704 34.302 ;
     RECT  4.237 3.84 4.633 3.864 ;
     RECT  4.501 28.32 4.741 28.344 ;
     RECT  4.481 1.728 5.108 1.752 ;
     RECT  4.633 3.84 5.108 4.536 ;
     RECT  2.704 6.096 5.108 6.12 ;
     RECT  4.741 28.32 5.108 29.256 ;
     RECT  4.981 31.2 5.108 31.224 ;
     RECT  5.108 1.728 5.221 34.572 ;
     RECT  5.221 1.728 5.404 34.728 ;
     RECT  5.404 34.704 5.461 34.728 ;
     RECT  5.404 18.432 5.465 18.456 ;
     RECT  5.404 1.728 5.507 2.088 ;
     RECT  5.404 31.2 5.555 31.368 ;
     RECT  5.461 34.704 5.555 34.824 ;
     RECT  5.555 34.8 5.603 34.824 ;
     RECT  5.507 1.728 5.669 1.752 ;
     RECT  5.404 32.448 5.681 32.472 ;
     RECT  5.669 1.152 5.753 1.752 ;
     RECT  5.555 31.2 5.753 31.224 ;
     RECT  5.404 28.32 6.421 28.488 ;
     RECT  6.661 35.904 6.869 35.928 ;
     RECT  6.421 27.888 6.901 28.488 ;
     RECT  5.404 3.84 6.973 6.12 ;
     RECT  6.973 3.408 7.189 6.12 ;
     RECT  5.753 1.728 7.409 1.752 ;
     RECT  7.429 32.448 7.669 32.472 ;
     RECT  7.189 2.88 7.808 6.12 ;
     RECT  7.513 14.832 7.808 14.856 ;
     RECT  6.901 27.888 7.808 29.064 ;
     RECT  7.669 32.448 7.808 33.288 ;
     RECT  7.621 34.704 7.808 34.728 ;
     RECT  7.808 2.016 7.955 34.728 ;
     RECT  7.955 2.016 7.985 34.68 ;
     RECT  7.985 2.256 8.104 34.68 ;
     RECT  8.104 34.56 8.237 34.68 ;
     RECT  8.237 34.56 8.281 34.584 ;
     RECT  8.149 0.192 8.291 0.216 ;
     RECT  8.104 2.256 8.317 6.12 ;
     RECT  8.557 1.104 8.675 1.128 ;
     RECT  8.104 27.84 8.777 28.488 ;
     RECT  8.317 2.256 9.109 2.328 ;
     RECT  8.777 28.32 9.317 28.488 ;
     RECT  8.317 3.84 9.529 6.12 ;
     RECT  8.629 35.904 9.589 35.928 ;
     RECT  9.589 35.904 10.109 35.976 ;
     RECT  9.317 28.32 10.117 28.344 ;
     RECT  9.529 3.84 10.357 6.264 ;
     RECT  10.357 3.408 10.465 6.264 ;
     RECT  9.109 1.728 10.508 2.328 ;
     RECT  10.465 3.312 10.508 6.264 ;
     RECT  10.117 27.888 10.508 28.344 ;
     RECT  9.829 33.024 10.508 33.048 ;
     RECT  10.508 1.728 10.804 34.572 ;
     RECT  10.804 34.56 10.837 34.572 ;
     RECT  10.837 34.56 10.924 34.68 ;
     RECT  10.924 34.56 10.945 34.584 ;
     RECT  10.804 1.728 11.225 2.088 ;
     RECT  10.109 35.904 11.225 35.928 ;
     RECT  10.804 33.024 11.405 33.048 ;
     RECT  10.804 27.888 11.657 29.064 ;
     RECT  11.225 1.728 12.013 1.752 ;
     RECT  11.657 27.888 12.053 28.488 ;
     RECT  12.013 1.152 12.097 1.752 ;
     RECT  10.804 3.84 12.277 6.888 ;
     RECT  12.277 2.88 12.492 6.888 ;
     RECT  12.517 35.904 12.805 35.928 ;
     RECT  12.805 35.328 12.809 35.928 ;
     RECT  12.809 35.328 13.061 35.352 ;
     RECT  12.097 1.728 13.208 1.752 ;
     RECT  12.492 2.88 13.208 6.936 ;
     RECT  12.553 26.784 13.208 26.808 ;
     RECT  12.053 28.368 13.208 28.488 ;
     RECT  11.797 31.296 13.208 31.32 ;
     RECT  13.208 1.728 13.504 34.728 ;
     RECT  13.504 1.728 13.619 3.864 ;
     RECT  13.504 18.912 13.637 19.272 ;
     RECT  13.504 34.56 13.645 34.728 ;
     RECT  13.525 0.192 13.667 0.216 ;
     RECT  13.645 34.704 13.667 34.728 ;
     RECT  13.619 2.88 13.817 3.864 ;
     RECT  13.637 19.248 13.817 19.272 ;
     RECT  13.619 1.728 14.545 1.896 ;
     RECT  13.504 5.088 14.545 7.464 ;
     RECT  13.504 28.416 14.861 29.064 ;
     RECT  13.817 3.84 14.929 3.864 ;
     RECT  14.545 5.088 14.929 7.224 ;
     RECT  14.861 28.416 14.965 28.488 ;
     RECT  14.929 3.84 15.205 7.224 ;
     RECT  14.965 28.368 15.205 28.488 ;
     RECT  14.545 1.728 15.908 1.752 ;
     RECT  15.205 2.88 15.908 7.224 ;
     RECT  15.289 18.864 15.908 18.888 ;
     RECT  15.205 28.32 15.908 28.488 ;
     RECT  15.908 1.728 15.973 34.572 ;
     RECT  15.973 1.728 16.204 34.728 ;
     RECT  16.204 34.656 16.355 34.728 ;
     RECT  16.204 1.728 16.445 7.128 ;
     RECT  16.355 34.656 16.517 34.68 ;
     RECT  16.445 1.728 16.547 7.032 ;
     RECT  16.547 2.88 17.219 7.032 ;
     RECT  16.204 27.888 17.345 29.064 ;
     RECT  15.733 35.904 17.453 35.928 ;
     RECT  17.653 0.576 17.845 0.6 ;
     RECT  16.547 1.728 17.845 1.752 ;
     RECT  17.845 0.576 17.939 1.752 ;
     RECT  17.939 1.728 18.179 1.752 ;
     RECT  18.373 2.148 18.421 2.28 ;
     RECT  17.219 3.84 18.421 7.032 ;
     RECT  17.345 27.888 18.421 28.488 ;
     RECT  18.421 2.148 18.608 7.032 ;
     RECT  18.421 9.072 18.608 9.096 ;
     RECT  18.421 27.696 18.608 28.488 ;
     RECT  18.469 34.8 18.608 34.824 ;
     RECT  18.469 0.288 18.707 0.312 ;
     RECT  18.608 2.148 18.904 34.824 ;
     RECT  18.901 0.192 19.043 0.216 ;
     RECT  18.904 34.8 19.043 34.824 ;
     RECT  18.904 3.936 19.091 6.84 ;
     RECT  18.904 2.88 19.109 2.952 ;
     RECT  18.904 27.696 19.181 28.872 ;
     RECT  19.109 2.928 19.325 2.952 ;
     RECT  19.181 28.32 19.469 28.872 ;
     RECT  19.091 4.368 19.613 6.84 ;
     RECT  19.469 28.32 19.685 28.488 ;
     RECT  19.613 4.752 19.969 6.84 ;
     RECT  19.969 4.752 20.108 6.888 ;
     RECT  20.108 4.752 20.195 7.608 ;
     RECT  19.381 1.728 20.341 1.8 ;
     RECT  19.685 28.32 20.581 28.44 ;
     RECT  20.581 27.888 20.821 28.44 ;
     RECT  20.341 1.728 20.905 1.848 ;
     RECT  20.725 2.88 20.905 3 ;
     RECT  20.905 1.728 21.109 3 ;
     RECT  20.195 4.752 21.109 6.936 ;
     RECT  20.821 27.888 21.157 28.488 ;
     RECT  21.109 1.728 21.308 6.936 ;
     RECT  21.157 27.888 21.308 28.968 ;
     RECT  20.101 33.024 21.308 33.048 ;
     RECT  21.157 34.8 21.308 34.824 ;
     RECT  21.157 0.192 21.395 0.216 ;
     RECT  21.308 1.728 21.395 34.824 ;
     RECT  21.395 1.728 21.412 34.572 ;
     RECT  21.412 1.728 21.604 34.302 ;
     RECT  21.604 27.888 21.845 28.968 ;
     RECT  21.589 35.904 22.061 35.928 ;
     RECT  21.604 1.728 22.067 7.32 ;
     RECT  21.604 33.024 22.745 33.048 ;
     RECT  21.845 27.888 23.029 28.872 ;
     RECT  22.067 1.728 23.321 6.648 ;
     RECT  23.372 0.144 23.459 0.168 ;
     RECT  23.321 2.016 23.569 6.648 ;
     RECT  23.569 2.016 23.701 7.224 ;
     RECT  23.509 35.904 23.753 35.928 ;
     RECT  23.701 2.016 24.008 7.704 ;
     RECT  23.929 17.904 24.008 17.928 ;
     RECT  23.029 27.888 24.008 29.064 ;
     RECT  23.749 31.2 24.008 31.224 ;
     RECT  24.008 2.016 24.037 34.572 ;
     RECT  24.037 2.016 24.277 34.824 ;
     RECT  24.277 2.016 24.304 34.92 ;
     RECT  24.304 10.8 24.419 10.872 ;
     RECT  24.304 34.8 24.419 34.92 ;
     RECT  24.419 34.896 24.467 34.92 ;
     RECT  24.304 33.024 24.473 33.048 ;
     RECT  24.304 2.016 24.497 9.144 ;
     RECT  24.419 10.8 24.509 10.824 ;
     RECT  24.304 31.2 24.545 31.224 ;
     RECT  24.497 1.728 24.553 9.144 ;
     RECT  24.553 1.728 24.581 7.8 ;
     RECT  24.304 26.784 24.653 26.808 ;
     RECT  24.581 2.4 24.947 7.8 ;
     RECT  24.757 35.328 24.997 35.352 ;
     RECT  24.997 35.328 25.013 35.928 ;
     RECT  24.304 18.96 25.229 18.984 ;
     RECT  25.34 0.144 25.427 0.168 ;
     RECT  24.553 9.12 25.445 9.144 ;
     RECT  25.013 35.904 25.477 35.928 ;
     RECT  25.573 0.528 25.661 0.552 ;
     RECT  24.947 2.4 25.717 7.704 ;
     RECT  25.717 1.728 25.981 7.704 ;
     RECT  25.477 35.904 25.985 35.976 ;
     RECT  24.304 28.32 26.437 28.488 ;
     RECT  26.437 27.888 26.581 28.488 ;
     RECT  26.197 35.328 26.581 35.352 ;
     RECT  26.581 34.8 26.597 35.352 ;
     RECT  25.981 1.728 26.708 8.568 ;
     RECT  26.053 9.696 26.708 9.72 ;
     RECT  26.581 27.888 26.708 29.064 ;
     RECT  26.597 34.8 26.708 34.824 ;
     RECT  26.708 1.728 27.004 34.824 ;
     RECT  27.004 27.888 27.065 28.488 ;
     RECT  26.581 0.192 27.155 0.216 ;
     RECT  27.004 34.8 27.155 34.824 ;
     RECT  27.004 8.544 27.347 8.568 ;
     RECT  27.065 28.32 27.677 28.488 ;
     RECT  27.677 28.368 28.037 28.488 ;
     RECT  27.004 1.728 28.073 7.272 ;
     RECT  28.073 2.256 28.165 7.272 ;
     RECT  28.037 28.416 28.165 28.488 ;
     RECT  27.925 35.904 28.469 35.928 ;
     RECT  28.165 28.416 28.645 28.872 ;
     RECT  28.933 19.104 29.149 19.128 ;
     RECT  28.165 2.256 29.269 7.464 ;
     RECT  28.429 8.544 29.269 8.568 ;
     RECT  29.125 35.328 29.269 35.352 ;
     RECT  29.149 18.528 29.329 19.128 ;
     RECT  29.269 2.256 29.365 8.568 ;
     RECT  29.365 1.728 29.408 8.568 ;
     RECT  29.149 10.896 29.408 10.92 ;
     RECT  29.329 18.432 29.408 19.128 ;
     RECT  28.645 28.416 29.408 29.064 ;
     RECT  29.269 34.8 29.408 35.352 ;
     RECT  29.408 1.728 29.585 35.352 ;
     RECT  29.585 1.728 29.704 34.824 ;
     RECT  29.653 0.192 29.843 0.216 ;
     RECT  29.704 34.8 29.843 34.824 ;
     RECT  29.704 1.728 29.953 7.128 ;
     RECT  29.953 3.936 29.973 7.128 ;
     RECT  29.704 27.888 30.305 29.064 ;
     RECT  30.305 27.888 30.377 28.488 ;
     RECT  29.953 1.728 30.737 2.904 ;
     RECT  30.737 1.728 31.277 2.328 ;
     RECT  31.196 0.144 31.283 0.168 ;
     RECT  29.973 3.936 31.333 6.888 ;
     RECT  31.093 35.904 31.573 35.928 ;
     RECT  31.277 2.148 31.916 2.328 ;
     RECT  31.333 3.408 31.916 6.888 ;
     RECT  31.573 35.904 31.925 35.976 ;
     RECT  30.377 28.32 31.957 28.488 ;
     RECT  31.909 0.192 32.099 0.312 ;
     RECT  31.957 34.8 32.099 34.824 ;
     RECT  31.916 2.148 32.108 6.888 ;
     RECT  31.957 28.272 32.108 28.488 ;
     RECT  32.108 2.148 32.212 34.572 ;
     RECT  32.099 0.288 32.339 0.312 ;
     RECT  32.212 2.148 32.404 34.302 ;
     RECT  32.404 28.272 32.537 28.488 ;
     RECT  32.404 2.148 32.581 6.84 ;
     RECT  31.925 35.904 33.061 35.928 ;
     RECT  32.581 1.728 33.301 6.84 ;
     RECT  33.061 35.904 33.329 35.976 ;
     RECT  33.329 35.904 33.781 35.928 ;
     RECT  32.537 28.32 34.261 28.488 ;
     RECT  33.301 1.728 34.409 1.8 ;
     RECT  33.301 2.832 34.477 6.84 ;
     RECT  34.477 2.148 34.513 6.84 ;
     RECT  33.781 35.328 34.597 35.928 ;
     RECT  34.597 34.704 34.733 35.928 ;
     RECT  34.733 34.704 34.787 34.728 ;
     RECT  34.513 2.148 34.808 7.464 ;
     RECT  34.549 21.072 34.808 21.096 ;
     RECT  34.261 28.32 34.808 29.064 ;
     RECT  34.597 33.072 34.808 33.096 ;
     RECT  34.808 2.148 35.104 34.68 ;
     RECT  34.7 0.192 35.219 0.216 ;
     RECT  35.104 18.528 35.219 18.648 ;
     RECT  35.104 20.016 35.219 20.04 ;
     RECT  35.104 34.656 35.219 34.68 ;
     RECT  35.104 2.148 35.477 7.464 ;
     RECT  35.219 18.624 35.525 18.648 ;
     RECT  35.104 28.464 36.229 28.872 ;
     RECT  35.845 0.528 36.332 0.552 ;
     RECT  35.104 33.024 36.353 33.048 ;
     RECT  35.477 1.728 36.529 7.464 ;
     RECT  36.229 28.464 36.709 29.064 ;
     RECT  36.332 0.144 36.899 0.552 ;
     RECT  34.733 35.904 37.037 35.928 ;
     RECT  36.899 0.192 37.109 0.552 ;
     RECT  36.709 28.416 37.189 29.064 ;
     RECT  37.349 34.608 37.388 34.632 ;
     RECT  37.388 34.608 37.475 34.728 ;
     RECT  36.529 1.728 37.508 7.992 ;
     RECT  37.285 9.12 37.508 9.144 ;
     RECT  37.189 27.888 37.508 29.064 ;
     RECT  37.321 33.072 37.508 33.096 ;
     RECT  37.475 34.608 37.508 34.68 ;
     RECT  37.508 1.728 37.804 34.68 ;
     RECT  37.804 1.728 38.003 7.992 ;
     RECT  37.804 10.848 38.051 10.872 ;
     RECT  37.804 34.656 38.051 34.68 ;
     RECT  37.109 0.192 38.125 0.312 ;
     RECT  38.003 1.728 38.195 7.464 ;
     RECT  37.804 18.672 38.225 18.696 ;
     RECT  38.195 1.728 38.405 6.936 ;
     RECT  38.54 0.144 38.627 0.168 ;
     RECT  38.405 1.728 38.675 6.888 ;
     RECT  37.804 27.888 38.873 29.064 ;
     RECT  38.675 1.728 39.233 6.696 ;
     RECT  39.221 0.528 39.305 0.552 ;
     RECT  39.397 35.904 39.701 35.928 ;
     RECT  39.233 2.16 39.781 6.696 ;
     RECT  39.877 0.192 40.019 0.408 ;
     RECT  40.021 34.704 40.049 34.728 ;
     RECT  40.019 0.288 40.163 0.408 ;
     RECT  39.781 2.16 40.208 6.84 ;
     RECT  39.781 8.544 40.208 8.568 ;
     RECT  39.769 10.848 40.208 10.872 ;
     RECT  39.337 18.768 40.208 18.792 ;
     RECT  38.873 27.888 40.208 28.872 ;
     RECT  39.877 33.072 40.208 33.096 ;
     RECT  40.049 34.56 40.208 34.728 ;
     RECT  40.208 2.148 40.312 34.728 ;
     RECT  40.163 0.384 40.403 0.408 ;
     RECT  40.312 2.16 40.403 34.728 ;
     RECT  40.403 2.16 40.504 34.302 ;
     RECT  40.504 27.84 40.853 28.44 ;
     RECT  40.949 0.528 41.033 0.552 ;
     RECT  40.504 2.16 41.068 6.792 ;
     RECT  41.068 2.16 41.105 6.504 ;
     RECT  41.42 0.144 41.507 0.168 ;
     RECT  41.105 2.16 41.605 3.48 ;
     RECT  40.853 27.84 41.825 28.344 ;
     RECT  41.605 1.728 42.073 3.48 ;
     RECT  41.105 4.512 42.073 6.504 ;
     RECT  42.073 1.728 42.085 6.504 ;
     RECT  40.885 35.904 42.805 35.928 ;
     RECT  42.085 1.728 42.908 6.936 ;
     RECT  41.857 10.272 42.908 10.296 ;
     RECT  41.569 18.768 42.908 18.792 ;
     RECT  41.825 27.888 42.908 27.912 ;
     RECT  42.325 28.944 42.908 28.968 ;
     RECT  41.845 31.296 42.908 31.32 ;
     RECT  42.805 35.328 42.908 35.928 ;
     RECT  42.908 1.728 43.012 35.928 ;
     RECT  43.045 0.288 43.189 0.312 ;
     RECT  43.012 1.728 43.204 34.302 ;
     RECT  43.204 1.728 43.265 3.432 ;
     RECT  43.189 0.192 43.331 0.312 ;
     RECT  43.012 35.328 43.337 35.928 ;
     RECT  43.337 35.904 43.525 35.928 ;
     RECT  43.525 35.904 44.273 35.976 ;
     RECT  43.204 28.32 44.293 28.488 ;
     RECT  44.293 28.32 44.533 28.872 ;
     RECT  43.265 2.88 44.557 3.432 ;
     RECT  43.204 4.512 44.557 6.552 ;
     RECT  43.265 1.728 44.629 1.752 ;
     RECT  44.533 27.792 44.633 28.872 ;
     RECT  44.557 2.88 44.917 6.552 ;
     RECT  44.917 2.832 45.445 6.552 ;
     RECT  44.629 1.728 45.452 1.8 ;
     RECT  45.445 2.832 45.452 6.888 ;
     RECT  44.273 35.904 45.497 35.928 ;
     RECT  45.452 1.728 45.608 6.888 ;
     RECT  44.633 27.792 45.608 28.488 ;
     RECT  45.608 1.728 45.733 34.572 ;
     RECT  45.733 1.728 45.904 34.728 ;
     RECT  45.733 0.288 45.973 0.312 ;
     RECT  45.904 34.704 45.973 34.728 ;
     RECT  45.973 0.192 46.019 0.312 ;
     RECT  45.973 34.704 46.019 34.824 ;
     RECT  46.019 0.192 46.115 0.216 ;
     RECT  45.904 10.944 46.145 10.968 ;
     RECT  45.904 33.024 46.163 33.096 ;
     RECT  46.019 34.8 46.163 34.824 ;
     RECT  45.904 17.376 46.181 17.4 ;
     RECT  46.163 33.024 46.433 33.048 ;
     RECT  45.904 28.416 46.505 29.064 ;
     RECT  46.505 28.416 46.613 28.968 ;
     RECT  45.904 1.728 46.933 1.752 ;
     RECT  45.904 2.88 46.933 7.848 ;
     RECT  46.933 1.728 46.937 7.848 ;
     RECT  46.741 35.328 47.221 35.352 ;
     RECT  47.221 35.328 47.297 35.928 ;
     RECT  46.613 28.464 47.701 28.968 ;
     RECT  46.937 1.728 47.801 6.888 ;
     RECT  47.269 0.528 47.987 0.552 ;
     RECT  48.085 33.072 48.113 33.096 ;
     RECT  47.701 27.888 48.133 28.968 ;
     RECT  48.113 33.072 48.14 33.192 ;
     RECT  47.297 35.904 48.161 35.928 ;
     RECT  47.801 2.148 48.308 6.888 ;
     RECT  48.133 7.968 48.308 7.992 ;
     RECT  48.133 27.888 48.308 29.064 ;
     RECT  48.14 33.072 48.308 33.288 ;
     RECT  48.085 34.704 48.308 34.728 ;
     RECT  48.133 0.288 48.467 0.312 ;
     RECT  48.308 2.148 48.467 34.728 ;
     RECT  48.467 2.148 48.604 34.68 ;
     RECT  48.604 34.56 48.748 34.68 ;
     RECT  48.748 34.56 48.781 34.584 ;
     RECT  48.661 0.192 48.803 0.216 ;
     RECT  48.604 7.968 48.851 7.992 ;
     RECT  48.604 2.88 48.899 6.84 ;
     RECT  48.604 10.8 48.953 10.824 ;
     RECT  48.899 5.136 49.061 6.84 ;
     RECT  48.899 2.88 49.097 4.056 ;
     RECT  48.604 28.32 49.669 28.872 ;
     RECT  49.141 1.728 49.741 1.8 ;
     RECT  49.097 2.88 49.741 2.952 ;
     RECT  49.429 35.904 49.909 35.928 ;
     RECT  49.741 1.728 49.955 2.952 ;
     RECT  49.909 35.904 49.961 35.976 ;
     RECT  49.061 5.232 49.997 6.84 ;
     RECT  49.669 28.32 50.149 29.064 ;
     RECT  49.097 4.032 50.281 4.056 ;
     RECT  49.997 5.232 50.281 6.648 ;
     RECT  50.281 4.032 50.569 6.648 ;
     RECT  49.961 35.952 50.609 35.976 ;
     RECT  50.725 0.528 50.812 0.552 ;
     RECT  49.955 2.784 50.821 2.952 ;
     RECT  50.569 3.984 50.821 6.648 ;
     RECT  49.955 1.728 51.008 1.752 ;
     RECT  50.821 2.784 51.008 6.648 ;
     RECT  50.149 27.888 51.008 29.064 ;
     RECT  50.821 0.288 51.155 0.312 ;
     RECT  51.008 1.728 51.304 34.572 ;
     RECT  51.304 34.56 51.349 34.572 ;
     RECT  51.349 34.56 51.437 34.68 ;
     RECT  51.437 34.56 51.481 34.584 ;
     RECT  51.109 35.904 51.829 35.928 ;
     RECT  51.829 35.904 52.121 35.976 ;
     RECT  51.304 28.416 52.193 28.872 ;
     RECT  51.304 1.728 52.316 2.904 ;
     RECT  51.304 4.512 52.316 7.224 ;
     RECT  52.316 1.728 52.403 7.224 ;
     RECT  52.403 3.936 52.553 7.224 ;
     RECT  52.121 35.904 52.553 35.928 ;
     RECT  52.193 28.416 52.597 28.488 ;
     RECT  52.94 0.144 53.027 0.168 ;
     RECT  52.553 3.936 53.372 6.888 ;
     RECT  52.403 1.728 53.708 2.856 ;
     RECT  53.372 3.84 53.708 6.888 ;
     RECT  52.597 27.888 53.708 28.488 ;
     RECT  53.317 31.2 53.708 31.224 ;
     RECT  53.557 35.904 53.797 35.928 ;
     RECT  53.708 1.728 53.812 34.572 ;
     RECT  53.812 1.728 54.004 34.302 ;
     RECT  53.797 35.904 54.037 35.976 ;
     RECT  54.004 16.704 54.131 16.728 ;
     RECT  54.004 18.432 54.131 18.456 ;
     RECT  54.037 35.904 54.533 36.024 ;
     RECT  54.004 30.768 54.707 31.32 ;
     RECT  54.707 30.768 54.749 30.888 ;
     RECT  54.004 28.32 55.285 28.488 ;
     RECT  54.749 30.864 55.325 30.888 ;
     RECT  54.004 1.728 55.501 6.744 ;
     RECT  55.285 27.888 55.765 28.488 ;
     RECT  55.868 0.144 55.955 0.168 ;
     RECT  54.533 35.904 56.005 35.928 ;
     RECT  56.113 8.544 56.197 8.568 ;
     RECT  55.501 1.728 56.245 6.888 ;
     RECT  56.005 35.328 56.261 35.928 ;
     RECT  56.293 0.192 56.405 0.552 ;
     RECT  56.245 1.728 56.408 7.272 ;
     RECT  56.197 8.544 56.408 8.76 ;
     RECT  55.765 27.888 56.408 28.872 ;
     RECT  56.408 1.728 56.704 34.824 ;
     RECT  56.704 34.8 56.819 34.824 ;
     RECT  56.405 0.192 56.867 0.216 ;
     RECT  56.704 33.024 56.909 33.048 ;
     RECT  56.704 1.728 57.125 7.992 ;
     RECT  57.125 1.728 57.269 6.888 ;
     RECT  56.261 35.904 57.305 35.928 ;
     RECT  57.125 7.968 57.457 7.992 ;
     RECT  56.704 10.848 57.491 10.872 ;
     RECT  57.269 1.728 57.587 6.84 ;
     RECT  56.704 28.416 58.213 28.872 ;
     RECT  57.587 1.728 58.259 2.856 ;
     RECT  58.501 0.528 58.601 0.552 ;
     RECT  58.259 2.016 58.693 2.856 ;
     RECT  58.213 27.888 58.693 28.872 ;
     RECT  58.693 2.016 58.885 2.904 ;
     RECT  57.587 3.936 58.885 6.84 ;
     RECT  58.885 2.016 58.933 6.84 ;
     RECT  58.417 9.072 58.981 9.096 ;
     RECT  58.933 2.016 59.108 6.936 ;
     RECT  58.981 8.16 59.108 9.096 ;
     RECT  58.693 27.888 59.108 29.064 ;
     RECT  58.981 34.8 59.108 34.824 ;
     RECT  59.108 2.016 59.219 34.824 ;
     RECT  59.029 0.144 59.357 0.168 ;
     RECT  59.219 2.016 59.404 34.302 ;
     RECT  59.404 2.016 59.413 7.464 ;
     RECT  59.404 28.32 59.609 29.064 ;
     RECT  59.413 1.728 59.617 7.464 ;
     RECT  58.933 35.904 59.653 35.928 ;
     RECT  59.617 1.728 59.789 7.272 ;
     RECT  59.789 2.208 59.933 7.272 ;
     RECT  59.933 2.688 59.969 7.272 ;
     RECT  59.404 9.12 60.131 9.144 ;
     RECT  59.653 35.904 60.133 35.976 ;
     RECT  59.969 2.832 60.172 7.272 ;
     RECT  60.133 35.904 60.257 36.024 ;
     RECT  60.172 2.832 60.374 6.984 ;
     RECT  59.404 10.848 60.437 10.872 ;
     RECT  60.257 35.952 60.437 36.024 ;
     RECT  60.437 36 60.761 36.024 ;
     RECT  59.609 28.32 61.381 28.872 ;
     RECT  61.381 28.272 61.573 28.872 ;
     RECT  61.141 1.728 61.621 1.752 ;
     RECT  61.573 0.288 61.669 0.312 ;
     RECT  61.573 28.272 61.669 28.968 ;
     RECT  61.573 34.848 61.669 34.872 ;
     RECT  61.621 1.728 61.808 1.8 ;
     RECT  60.374 2.88 61.808 6.984 ;
     RECT  61.669 28.272 61.808 29.064 ;
     RECT  60.661 33.024 61.808 33.048 ;
     RECT  61.669 34.8 61.808 34.872 ;
     RECT  61.669 0.288 62.021 0.552 ;
     RECT  61.808 1.728 62.104 34.872 ;
     RECT  62.021 0.288 62.147 0.312 ;
     RECT  62.104 34.848 62.147 34.872 ;
     RECT  62.104 28.272 62.165 29.064 ;
     RECT  62.104 1.728 62.641 7.464 ;
     RECT  62.165 28.464 62.957 29.064 ;
     RECT  62.104 33.024 63.281 33.048 ;
     RECT  62.957 28.464 63.349 28.488 ;
     RECT  62.641 1.728 63.491 6.84 ;
     RECT  62.701 0.144 63.539 0.168 ;
     RECT  63.491 2.736 63.853 6.84 ;
     RECT  63.809 7.968 63.853 7.992 ;
     RECT  63.491 1.728 64.508 1.752 ;
     RECT  63.853 2.736 64.508 7.992 ;
     RECT  63.349 28.32 64.508 28.488 ;
     RECT  64.309 31.2 64.508 31.224 ;
     RECT  64.508 1.728 64.549 34.572 ;
     RECT  64.549 1.728 64.804 34.824 ;
     RECT  64.804 9.12 64.931 9.144 ;
     RECT  64.804 34.8 64.931 34.824 ;
     RECT  64.804 1.728 64.979 7.368 ;
     RECT  64.804 31.2 65.045 31.32 ;
     RECT  64.885 0.528 65.189 0.552 ;
     RECT  64.804 28.464 65.621 28.488 ;
     RECT  64.979 1.728 66.025 6.888 ;
     RECT  66.025 1.728 66.803 2.232 ;
     RECT  65.989 28.32 66.997 28.44 ;
     RECT  66.803 2.016 67.085 2.232 ;
     RECT  66.025 3.36 67.085 6.888 ;
     RECT  62.341 35.904 67.204 35.928 ;
     RECT  67.085 2.016 67.208 6.888 ;
     RECT  66.997 28.32 67.208 28.824 ;
     RECT  65.045 31.296 67.208 31.32 ;
     RECT  64.804 33.024 67.208 33.048 ;
     RECT  67.208 2.016 67.477 34.572 ;
     RECT  67.477 2.016 67.504 34.824 ;
     RECT  67.504 2.016 67.565 7.992 ;
     RECT  67.477 0.192 67.619 0.216 ;
     RECT  67.504 34.8 67.619 34.824 ;
     RECT  67.565 2.88 67.781 7.992 ;
     RECT  67.504 28.272 67.925 28.344 ;
     RECT  67.957 1.824 68.197 1.848 ;
     RECT  67.781 4.128 68.291 7.992 ;
     RECT  68.291 7.968 68.365 7.992 ;
     RECT  67.781 2.88 68.597 3.048 ;
     RECT  68.54 0.144 68.627 0.168 ;
     RECT  67.504 31.296 68.645 31.32 ;
     RECT  67.204 35.904 68.717 35.976 ;
     RECT  68.717 35.952 68.861 35.976 ;
     RECT  68.197 1.728 68.965 1.848 ;
     RECT  68.597 2.832 68.965 3.048 ;
     RECT  68.965 1.728 69.205 3.048 ;
     RECT  68.291 4.128 69.205 6.792 ;
     RECT  67.925 28.32 69.205 28.344 ;
     RECT  69.205 28.32 69.445 28.392 ;
     RECT  69.205 1.728 69.685 6.792 ;
     RECT  69.445 28.32 69.685 28.488 ;
     RECT  69.685 1.728 69.769 6.888 ;
     RECT  69.769 2.148 69.781 6.888 ;
     RECT  69.781 2.148 69.908 6.936 ;
     RECT  69.685 27.888 69.908 28.488 ;
     RECT  68.965 33.024 69.908 33.048 ;
     RECT  69.781 34.8 69.908 34.824 ;
     RECT  69.908 2.148 70.012 34.824 ;
     RECT  70.012 2.148 70.204 34.302 ;
     RECT  69.781 0.192 70.211 0.216 ;
     RECT  70.165 35.328 70.445 35.352 ;
     RECT  70.204 27.888 70.481 28.488 ;
     RECT  70.204 2.148 70.697 6.312 ;
     RECT  70.481 28.416 70.697 28.488 ;
     RECT  70.697 2.148 70.801 2.904 ;
     RECT  70.204 9.12 70.835 9.144 ;
     RECT  70.204 7.392 70.877 7.416 ;
     RECT  70.645 35.904 70.885 35.928 ;
     RECT  70.885 35.904 71.093 35.976 ;
     RECT  71.093 35.952 71.125 35.976 ;
     RECT  70.697 4.128 71.276 6.312 ;
     RECT  71.276 4.128 71.363 7.08 ;
     RECT  71.125 35.952 71.381 36.024 ;
     RECT  70.801 1.728 71.452 2.904 ;
     RECT  71.363 4.128 71.533 6.936 ;
     RECT  71.413 8.544 71.555 8.568 ;
     RECT  70.697 28.464 71.605 28.488 ;
     RECT  71.381 36 71.669 36.024 ;
     RECT  71.452 2.832 71.749 2.904 ;
     RECT  71.533 4.128 71.749 6.888 ;
     RECT  71.708 0.144 71.795 0.168 ;
     RECT  71.605 28.464 72.1 29.064 ;
     RECT  72.313 0.192 72.373 0.552 ;
     RECT  71.452 1.728 72.373 1.8 ;
     RECT  72.421 34.896 72.469 34.92 ;
     RECT  72.373 0.192 72.563 1.8 ;
     RECT  72.563 1.728 72.608 1.8 ;
     RECT  71.749 2.832 72.608 6.888 ;
     RECT  72.1 28.416 72.608 29.064 ;
     RECT  72.469 34.8 72.608 34.92 ;
     RECT  72.563 0.192 72.659 0.312 ;
     RECT  72.608 1.728 72.899 34.92 ;
     RECT  72.899 1.728 72.904 34.302 ;
     RECT  72.659 0.192 73.196 0.216 ;
     RECT  73.196 0.144 73.283 0.216 ;
     RECT  72.904 10.848 73.477 10.872 ;
     RECT  73.283 0.192 73.505 0.216 ;
     RECT  72.904 28.368 73.505 29.064 ;
     RECT  72.373 35.904 73.573 35.928 ;
     RECT  73.505 28.368 73.577 28.872 ;
     RECT  72.904 7.968 73.763 7.992 ;
     RECT  73.573 35.904 73.829 35.976 ;
     RECT  72.904 1.728 73.909 6.888 ;
     RECT  72.904 9.12 73.955 9.144 ;
     RECT  73.909 1.728 73.996 7.272 ;
     RECT  73.577 28.464 74.153 28.872 ;
     RECT  74.153 28.464 74.821 28.488 ;
     RECT  74.629 0.288 74.981 0.312 ;
     RECT  73.996 1.728 75.308 6.84 ;
     RECT  74.821 28.416 75.308 28.488 ;
     RECT  75.301 34.8 75.308 34.824 ;
     RECT  75.308 1.728 75.604 34.824 ;
     RECT  75.541 0.192 75.731 0.216 ;
     RECT  75.604 7.968 75.731 8.04 ;
     RECT  75.604 34.8 75.731 34.824 ;
     RECT  73.829 35.904 75.781 35.928 ;
     RECT  75.731 8.016 75.853 8.04 ;
     RECT  75.781 35.904 76.021 35.976 ;
     RECT  76.021 35.904 76.025 36.024 ;
     RECT  75.604 3.984 76.061 6.84 ;
     RECT  76.025 35.952 76.097 36.024 ;
     RECT  75.604 11.424 76.163 11.448 ;
     RECT  76.061 3.984 76.457 6.696 ;
     RECT  76.097 36 76.637 36.024 ;
     RECT  75.604 27.888 76.741 28.488 ;
     RECT  75.604 1.728 76.787 2.28 ;
     RECT  76.885 3.216 76.997 3.432 ;
     RECT  76.787 1.728 78.008 1.8 ;
     RECT  76.997 3.312 78.008 3.432 ;
     RECT  76.457 4.512 78.008 6.696 ;
     RECT  76.741 27.888 78.008 29.064 ;
     RECT  77.893 34.8 78.008 34.824 ;
     RECT  77.893 0.192 78.035 0.216 ;
     RECT  78.008 1.728 78.035 34.824 ;
     RECT  78.035 1.728 78.112 34.572 ;
     RECT  78.112 1.728 78.304 34.302 ;
     RECT  78.304 1.728 78.365 2.04 ;
     RECT  78.304 3.216 78.419 3.24 ;
     RECT  78.229 35.904 78.469 35.928 ;
     RECT  78.365 1.728 78.685 1.8 ;
     RECT  78.304 28.272 78.689 28.872 ;
     RECT  78.685 1.152 79.235 1.8 ;
     RECT  78.304 4.512 79.292 6.6 ;
     RECT  78.689 28.32 79.301 28.872 ;
     RECT  79.292 3.936 79.369 6.6 ;
     RECT  79.369 3.936 79.379 6.888 ;
     RECT  79.379 4.512 79.453 6.888 ;
     RECT  78.469 35.904 79.553 35.976 ;
     RECT  79.235 1.728 79.733 1.8 ;
     RECT  79.733 1.728 80.197 1.752 ;
     RECT  80.197 1.152 80.281 1.752 ;
     RECT  79.453 4.512 80.485 6.648 ;
     RECT  80.485 4.512 80.549 7.368 ;
     RECT  79.909 2.88 80.593 2.904 ;
     RECT  80.281 1.728 80.708 1.752 ;
     RECT  80.593 2.88 80.708 3.336 ;
     RECT  80.549 4.512 80.708 7.464 ;
     RECT  79.301 28.32 80.708 28.488 ;
     RECT  80.437 33.024 80.708 33.048 ;
     RECT  80.581 34.8 80.708 34.824 ;
     RECT  80.708 1.728 80.749 34.824 ;
     RECT  80.749 2.148 80.812 34.824 ;
     RECT  80.812 2.418 81.004 34.824 ;
     RECT  80.917 0.288 81.155 0.312 ;
     RECT  81.004 34.8 81.155 34.824 ;
     RECT  81.004 33.024 81.173 33.048 ;
     RECT  81.004 2.88 81.484 7.368 ;
     RECT  79.553 35.904 81.637 35.928 ;
     RECT  81.484 2.88 81.749 3.432 ;
     RECT  81.637 35.904 81.877 35.976 ;
     RECT  81.004 27.888 82.357 28.872 ;
     RECT  82.097 1.728 82.573 1.752 ;
     RECT  82.573 1.728 82.577 1.848 ;
     RECT  81.877 35.904 82.649 36.072 ;
     RECT  82.577 1.824 82.657 1.848 ;
     RECT  82.649 35.904 82.829 35.976 ;
     RECT  81.749 3.408 83.105 3.432 ;
     RECT  81.484 4.512 83.221 7.368 ;
     RECT  83.105 2.88 83.269 3.432 ;
     RECT  83.221 4.512 83.269 7.464 ;
     RECT  83.269 2.88 83.408 7.464 ;
     RECT  82.897 18.432 83.408 18.456 ;
     RECT  82.357 27.888 83.408 29.064 ;
     RECT  83.269 33.024 83.408 33.048 ;
     RECT  83.269 34.8 83.408 34.824 ;
     RECT  83.269 0.192 83.411 0.216 ;
     RECT  83.408 2.016 83.411 34.824 ;
     RECT  83.411 2.016 83.512 34.572 ;
     RECT  83.512 2.016 83.704 34.302 ;
     RECT  83.704 30.768 83.765 30.792 ;
     RECT  83.704 33.024 83.765 33.048 ;
     RECT  82.829 35.904 83.845 35.928 ;
     RECT  83.704 18.336 84.089 18.456 ;
     RECT  83.704 4.512 84.179 7.464 ;
     RECT  83.704 2.016 84.233 2.904 ;
     RECT  84.089 18.432 84.413 18.456 ;
     RECT  84.179 4.512 84.733 6.024 ;
     RECT  84.293 1.728 84.985 1.752 ;
     RECT  84.233 2.88 85.057 2.904 ;
     RECT  83.704 28.464 85.061 29.064 ;
     RECT  84.985 1.104 85.091 1.752 ;
     RECT  83.845 35.904 85.097 35.976 ;
     RECT  85.091 1.728 85.237 1.752 ;
     RECT  85.057 2.88 85.237 3 ;
     RECT  85.061 28.464 85.525 28.488 ;
     RECT  85.097 35.904 85.529 35.928 ;
     RECT  84.733 4.416 85.633 6.024 ;
     RECT  84.179 7.152 85.633 7.464 ;
     RECT  85.237 1.728 86.108 3 ;
     RECT  85.633 4.416 86.108 7.464 ;
     RECT  85.525 28.32 86.108 28.488 ;
     RECT  86.053 34.848 86.108 34.872 ;
     RECT  86.108 1.728 86.404 34.872 ;
     RECT  86.404 27.888 86.465 28.44 ;
     RECT  86.293 0.288 86.531 0.312 ;
     RECT  86.404 34.752 86.531 34.872 ;
     RECT  86.531 34.752 86.645 34.776 ;
     RECT  86.465 27.888 86.861 28.248 ;
     RECT  86.404 2.88 86.897 5.304 ;
     RECT  86.897 2.928 87.005 5.304 ;
     RECT  86.293 35.952 87.013 35.976 ;
     RECT  86.404 32.448 87.221 32.472 ;
     RECT  87.005 3.648 87.877 5.304 ;
     RECT  86.404 6.288 87.877 6.312 ;
     RECT  87.013 35.904 87.905 35.976 ;
     RECT  86.861 27.888 87.973 27.912 ;
     RECT  86.404 1.728 88.172 1.8 ;
     RECT  87.973 27.888 88.213 28.296 ;
     RECT  88.172 1.728 88.585 2.28 ;
     RECT  87.877 3.648 88.585 6.312 ;
     RECT  88.585 1.728 88.661 6.312 ;
     RECT  88.661 2.148 88.808 6.312 ;
     RECT  88.213 27.888 88.808 28.44 ;
     RECT  88.808 2.148 88.912 34.572 ;
     RECT  87.905 35.904 88.985 35.928 ;
     RECT  88.912 2.256 89.104 34.302 ;
     RECT  89.104 2.256 89.267 4.68 ;
     RECT  89.104 5.76 89.267 5.784 ;
     RECT  89.267 2.256 89.345 3.72 ;
     RECT  89.345 3.696 89.417 3.72 ;
     RECT  89.345 2.256 89.633 2.28 ;
    LAYER M5 ;
     RECT  23.424 0.133 23.448 0.144 ;
     RECT  25.392 0.133 25.416 0.144 ;
     RECT  31.248 0.133 31.272 0.144 ;
     RECT  36.384 0.133 36.48 0.144 ;
     RECT  36.504 0.133 36.72 0.144 ;
     RECT  36.744 0.133 36.888 0.144 ;
     RECT  38.592 0.133 38.616 0.144 ;
     RECT  41.472 0.133 41.496 0.144 ;
     RECT  52.992 0.133 53.016 0.144 ;
     RECT  55.92 0.133 55.944 0.144 ;
     RECT  62.736 0.133 62.832 0.144 ;
     RECT  62.856 0.133 63.072 0.144 ;
     RECT  63.096 0.133 63.36 0.144 ;
     RECT  63.384 0.133 63.528 0.144 ;
     RECT  68.592 0.133 68.616 0.144 ;
     RECT  71.76 0.133 71.784 0.144 ;
     RECT  73.248 0.133 73.272 0.144 ;
     RECT  4.536 0.144 4.752 0.192 ;
     RECT  4.776 0.144 4.992 0.192 ;
     RECT  5.016 0.144 5.232 0.192 ;
     RECT  5.256 0.144 5.472 0.192 ;
     RECT  5.496 0.144 5.712 0.192 ;
     RECT  5.736 0.144 5.952 0.192 ;
     RECT  5.976 0.144 6.192 0.192 ;
     RECT  6.216 0.144 6.432 0.192 ;
     RECT  6.456 0.144 6.672 0.192 ;
     RECT  6.696 0.144 6.912 0.192 ;
     RECT  6.936 0.144 7.2 0.192 ;
     RECT  7.224 0.144 7.44 0.192 ;
     RECT  7.464 0.144 7.68 0.192 ;
     RECT  7.704 0.144 7.92 0.192 ;
     RECT  7.944 0.144 8.16 0.192 ;
     RECT  8.184 0.144 8.4 0.192 ;
     RECT  8.424 0.144 8.64 0.192 ;
     RECT  8.664 0.144 8.88 0.192 ;
     RECT  8.904 0.144 9.12 0.192 ;
     RECT  9.144 0.144 9.36 0.192 ;
     RECT  9.384 0.144 9.6 0.192 ;
     RECT  9.624 0.144 9.84 0.192 ;
     RECT  9.864 0.144 10.128 0.192 ;
     RECT  10.152 0.144 10.368 0.192 ;
     RECT  10.392 0.144 10.608 0.192 ;
     RECT  10.632 0.144 10.848 0.192 ;
     RECT  10.872 0.144 11.088 0.192 ;
     RECT  11.112 0.144 11.328 0.192 ;
     RECT  11.352 0.144 11.568 0.192 ;
     RECT  11.592 0.144 11.808 0.192 ;
     RECT  11.832 0.144 12.048 0.192 ;
     RECT  12.072 0.144 12.288 0.192 ;
     RECT  12.312 0.144 12.528 0.192 ;
     RECT  12.552 0.144 12.816 0.192 ;
     RECT  12.84 0.144 13.056 0.192 ;
     RECT  13.08 0.144 13.296 0.192 ;
     RECT  13.32 0.144 13.536 0.192 ;
     RECT  13.56 0.144 13.776 0.192 ;
     RECT  13.8 0.144 14.016 0.192 ;
     RECT  14.04 0.144 14.256 0.192 ;
     RECT  14.28 0.144 14.496 0.192 ;
     RECT  14.52 0.144 14.736 0.192 ;
     RECT  14.76 0.144 14.976 0.192 ;
     RECT  15 0.144 15.216 0.192 ;
     RECT  15.24 0.144 15.456 0.192 ;
     RECT  15.48 0.144 15.744 0.192 ;
     RECT  15.768 0.144 15.984 0.192 ;
     RECT  16.008 0.144 16.224 0.192 ;
     RECT  16.248 0.144 16.464 0.192 ;
     RECT  16.488 0.144 16.704 0.192 ;
     RECT  16.728 0.144 16.944 0.192 ;
     RECT  16.968 0.144 17.184 0.192 ;
     RECT  17.208 0.144 17.424 0.192 ;
     RECT  17.448 0.144 17.664 0.192 ;
     RECT  17.688 0.144 17.904 0.192 ;
     RECT  17.928 0.144 18.144 0.192 ;
     RECT  18.168 0.144 18.432 0.192 ;
     RECT  18.456 0.144 18.672 0.192 ;
     RECT  18.696 0.144 18.912 0.192 ;
     RECT  18.936 0.144 19.152 0.192 ;
     RECT  19.176 0.144 19.392 0.192 ;
     RECT  19.416 0.144 19.632 0.192 ;
     RECT  19.656 0.144 19.872 0.192 ;
     RECT  19.896 0.144 20.112 0.192 ;
     RECT  20.136 0.144 20.352 0.192 ;
     RECT  20.376 0.144 20.592 0.192 ;
     RECT  20.616 0.144 20.832 0.192 ;
     RECT  20.856 0.144 21.072 0.192 ;
     RECT  21.096 0.144 21.36 0.192 ;
     RECT  21.384 0.144 21.6 0.192 ;
     RECT  21.624 0.144 21.84 0.192 ;
     RECT  21.864 0.144 22.08 0.192 ;
     RECT  22.104 0.144 22.32 0.192 ;
     RECT  22.344 0.144 22.56 0.192 ;
     RECT  22.584 0.144 22.8 0.192 ;
     RECT  22.824 0.144 23.04 0.192 ;
     RECT  23.064 0.144 23.28 0.192 ;
     RECT  23.304 0.144 23.52 0.192 ;
     RECT  23.544 0.144 23.76 0.192 ;
     RECT  23.784 0.144 24.048 0.192 ;
     RECT  24.072 0.144 24.288 0.192 ;
     RECT  24.312 0.144 24.528 0.192 ;
     RECT  24.552 0.144 24.768 0.192 ;
     RECT  24.792 0.144 25.008 0.192 ;
     RECT  25.032 0.144 25.248 0.192 ;
     RECT  25.272 0.144 25.488 0.192 ;
     RECT  25.512 0.144 25.728 0.192 ;
     RECT  25.752 0.144 25.968 0.192 ;
     RECT  25.992 0.144 26.208 0.192 ;
     RECT  26.232 0.144 26.448 0.192 ;
     RECT  26.472 0.144 26.688 0.192 ;
     RECT  26.712 0.144 26.976 0.192 ;
     RECT  27 0.144 27.216 0.192 ;
     RECT  27.24 0.144 27.456 0.192 ;
     RECT  27.48 0.144 27.696 0.192 ;
     RECT  27.72 0.144 27.936 0.192 ;
     RECT  27.96 0.144 28.176 0.192 ;
     RECT  28.2 0.144 28.416 0.192 ;
     RECT  28.44 0.144 28.656 0.192 ;
     RECT  28.68 0.144 28.896 0.192 ;
     RECT  28.92 0.144 29.136 0.192 ;
     RECT  29.16 0.144 29.376 0.192 ;
     RECT  29.4 0.144 29.664 0.192 ;
     RECT  29.688 0.144 29.904 0.192 ;
     RECT  29.928 0.144 30.144 0.192 ;
     RECT  30.168 0.144 30.384 0.192 ;
     RECT  30.408 0.144 30.624 0.192 ;
     RECT  30.648 0.144 30.864 0.192 ;
     RECT  30.888 0.144 31.104 0.192 ;
     RECT  31.128 0.144 31.344 0.192 ;
     RECT  31.368 0.144 31.584 0.192 ;
     RECT  31.608 0.144 31.824 0.192 ;
     RECT  31.848 0.144 32.064 0.192 ;
     RECT  32.088 0.144 32.304 0.192 ;
     RECT  32.328 0.144 32.592 0.192 ;
     RECT  32.616 0.144 32.832 0.192 ;
     RECT  32.856 0.144 33.072 0.192 ;
     RECT  33.096 0.144 33.312 0.192 ;
     RECT  33.336 0.144 33.552 0.192 ;
     RECT  33.576 0.144 33.792 0.192 ;
     RECT  33.816 0.144 34.032 0.192 ;
     RECT  34.056 0.144 34.272 0.192 ;
     RECT  34.296 0.144 34.512 0.192 ;
     RECT  34.536 0.144 34.752 0.192 ;
     RECT  34.776 0.144 34.992 0.192 ;
     RECT  35.016 0.144 35.28 0.192 ;
     RECT  35.304 0.144 35.52 0.192 ;
     RECT  35.544 0.144 35.76 0.192 ;
     RECT  35.784 0.144 36 0.192 ;
     RECT  36.024 0.144 36.24 0.192 ;
     RECT  36.264 0.144 36.48 0.192 ;
     RECT  36.504 0.144 36.72 0.192 ;
     RECT  36.744 0.144 36.96 0.192 ;
     RECT  36.984 0.144 37.2 0.192 ;
     RECT  37.224 0.144 37.44 0.192 ;
     RECT  37.464 0.144 37.68 0.192 ;
     RECT  37.704 0.144 37.92 0.192 ;
     RECT  37.944 0.144 38.208 0.192 ;
     RECT  38.232 0.144 38.448 0.192 ;
     RECT  38.472 0.144 38.688 0.192 ;
     RECT  38.712 0.144 38.928 0.192 ;
     RECT  38.952 0.144 39.168 0.192 ;
     RECT  39.192 0.144 39.408 0.192 ;
     RECT  39.432 0.144 39.648 0.192 ;
     RECT  39.672 0.144 39.888 0.192 ;
     RECT  39.912 0.144 40.128 0.192 ;
     RECT  40.152 0.144 40.368 0.192 ;
     RECT  40.392 0.144 40.608 0.192 ;
     RECT  40.632 0.144 40.896 0.192 ;
     RECT  40.92 0.144 41.136 0.192 ;
     RECT  41.16 0.144 41.376 0.192 ;
     RECT  41.4 0.144 41.616 0.192 ;
     RECT  41.64 0.144 41.856 0.192 ;
     RECT  41.88 0.144 42.096 0.192 ;
     RECT  42.12 0.144 42.336 0.192 ;
     RECT  42.36 0.144 42.576 0.192 ;
     RECT  42.6 0.144 42.816 0.192 ;
     RECT  42.84 0.144 43.056 0.192 ;
     RECT  43.08 0.144 43.296 0.192 ;
     RECT  43.32 0.144 43.536 0.192 ;
     RECT  43.56 0.144 43.824 0.192 ;
     RECT  43.848 0.144 44.064 0.192 ;
     RECT  44.088 0.144 44.304 0.192 ;
     RECT  44.328 0.144 44.544 0.192 ;
     RECT  44.568 0.144 44.784 0.192 ;
     RECT  44.808 0.144 45.024 0.192 ;
     RECT  45.048 0.144 45.264 0.192 ;
     RECT  45.288 0.144 45.504 0.192 ;
     RECT  45.528 0.144 45.744 0.192 ;
     RECT  45.768 0.144 45.984 0.192 ;
     RECT  46.008 0.144 46.224 0.192 ;
     RECT  46.248 0.144 46.512 0.192 ;
     RECT  46.536 0.144 46.752 0.192 ;
     RECT  46.776 0.144 46.992 0.192 ;
     RECT  47.016 0.144 47.232 0.192 ;
     RECT  47.256 0.144 47.472 0.192 ;
     RECT  47.496 0.144 47.712 0.192 ;
     RECT  47.736 0.144 47.952 0.192 ;
     RECT  47.976 0.144 48.192 0.192 ;
     RECT  48.216 0.144 48.432 0.192 ;
     RECT  48.456 0.144 48.672 0.192 ;
     RECT  48.696 0.144 48.912 0.192 ;
     RECT  48.936 0.144 49.152 0.192 ;
     RECT  49.176 0.144 49.44 0.192 ;
     RECT  49.464 0.144 49.68 0.192 ;
     RECT  49.704 0.144 49.92 0.192 ;
     RECT  49.944 0.144 50.16 0.192 ;
     RECT  50.184 0.144 50.4 0.192 ;
     RECT  50.424 0.144 50.64 0.192 ;
     RECT  50.664 0.144 50.88 0.192 ;
     RECT  50.904 0.144 51.12 0.192 ;
     RECT  51.144 0.144 51.36 0.192 ;
     RECT  51.384 0.144 51.6 0.192 ;
     RECT  51.624 0.144 51.84 0.192 ;
     RECT  51.864 0.144 52.128 0.192 ;
     RECT  52.152 0.144 52.368 0.192 ;
     RECT  52.392 0.144 52.608 0.192 ;
     RECT  52.632 0.144 52.848 0.192 ;
     RECT  52.872 0.144 53.088 0.192 ;
     RECT  53.112 0.144 53.328 0.192 ;
     RECT  53.352 0.144 53.568 0.192 ;
     RECT  53.592 0.144 53.808 0.192 ;
     RECT  53.832 0.144 54.048 0.192 ;
     RECT  54.072 0.144 54.288 0.192 ;
     RECT  54.312 0.144 54.528 0.192 ;
     RECT  54.552 0.144 54.768 0.192 ;
     RECT  54.792 0.144 55.056 0.192 ;
     RECT  55.08 0.144 55.296 0.192 ;
     RECT  55.32 0.144 55.536 0.192 ;
     RECT  55.56 0.144 55.776 0.192 ;
     RECT  55.8 0.144 56.016 0.192 ;
     RECT  56.04 0.144 56.256 0.192 ;
     RECT  56.28 0.144 56.496 0.192 ;
     RECT  56.52 0.144 56.736 0.192 ;
     RECT  56.76 0.144 56.976 0.192 ;
     RECT  57 0.144 57.216 0.192 ;
     RECT  57.24 0.144 57.456 0.192 ;
     RECT  57.48 0.144 57.744 0.192 ;
     RECT  57.768 0.144 57.984 0.192 ;
     RECT  58.008 0.144 58.224 0.192 ;
     RECT  58.248 0.144 58.464 0.192 ;
     RECT  58.488 0.144 58.704 0.192 ;
     RECT  58.728 0.144 58.944 0.192 ;
     RECT  58.968 0.144 59.184 0.192 ;
     RECT  59.208 0.144 59.424 0.192 ;
     RECT  59.448 0.144 59.664 0.192 ;
     RECT  59.688 0.144 59.904 0.192 ;
     RECT  59.928 0.144 60.144 0.192 ;
     RECT  60.168 0.144 60.384 0.192 ;
     RECT  60.408 0.144 60.672 0.192 ;
     RECT  60.696 0.144 60.912 0.192 ;
     RECT  60.936 0.144 61.152 0.192 ;
     RECT  61.176 0.144 61.392 0.192 ;
     RECT  61.416 0.144 61.632 0.192 ;
     RECT  61.656 0.144 61.872 0.192 ;
     RECT  61.896 0.144 62.112 0.192 ;
     RECT  62.136 0.144 62.352 0.192 ;
     RECT  62.376 0.144 62.592 0.192 ;
     RECT  62.616 0.144 62.832 0.192 ;
     RECT  62.856 0.144 63.072 0.192 ;
     RECT  63.096 0.144 63.36 0.192 ;
     RECT  63.384 0.144 63.6 0.192 ;
     RECT  63.624 0.144 63.84 0.192 ;
     RECT  63.864 0.144 64.08 0.192 ;
     RECT  64.104 0.144 64.32 0.192 ;
     RECT  64.344 0.144 64.56 0.192 ;
     RECT  64.584 0.144 64.8 0.192 ;
     RECT  64.824 0.144 65.04 0.192 ;
     RECT  65.064 0.144 65.28 0.192 ;
     RECT  65.304 0.144 65.52 0.192 ;
     RECT  65.544 0.144 65.76 0.192 ;
     RECT  65.784 0.144 66 0.192 ;
     RECT  66.024 0.144 66.288 0.192 ;
     RECT  66.312 0.144 66.528 0.192 ;
     RECT  66.552 0.144 66.768 0.192 ;
     RECT  66.792 0.144 67.008 0.192 ;
     RECT  67.032 0.144 67.248 0.192 ;
     RECT  67.272 0.144 67.488 0.192 ;
     RECT  67.512 0.144 67.728 0.192 ;
     RECT  67.752 0.144 67.968 0.192 ;
     RECT  67.992 0.144 68.208 0.192 ;
     RECT  68.232 0.144 68.448 0.192 ;
     RECT  68.472 0.144 68.688 0.192 ;
     RECT  68.712 0.144 68.976 0.192 ;
     RECT  69 0.144 69.216 0.192 ;
     RECT  69.24 0.144 69.456 0.192 ;
     RECT  69.48 0.144 69.696 0.192 ;
     RECT  69.72 0.144 69.936 0.192 ;
     RECT  69.96 0.144 70.176 0.192 ;
     RECT  70.2 0.144 70.416 0.192 ;
     RECT  70.44 0.144 70.656 0.192 ;
     RECT  70.68 0.144 70.896 0.192 ;
     RECT  70.92 0.144 71.136 0.192 ;
     RECT  71.16 0.144 71.376 0.192 ;
     RECT  71.4 0.144 71.616 0.192 ;
     RECT  71.64 0.144 71.904 0.192 ;
     RECT  71.928 0.144 72.144 0.192 ;
     RECT  72.168 0.144 72.384 0.192 ;
     RECT  72.408 0.144 72.624 0.192 ;
     RECT  72.648 0.144 72.864 0.192 ;
     RECT  72.888 0.144 73.104 0.192 ;
     RECT  73.128 0.144 73.344 0.192 ;
     RECT  73.368 0.144 73.584 0.192 ;
     RECT  73.608 0.144 73.824 0.192 ;
     RECT  73.848 0.144 74.064 0.192 ;
     RECT  74.088 0.144 74.304 0.192 ;
     RECT  74.328 0.144 74.592 0.192 ;
     RECT  74.616 0.144 74.832 0.192 ;
     RECT  74.856 0.144 75.072 0.192 ;
     RECT  75.096 0.144 75.312 0.192 ;
     RECT  75.336 0.144 75.552 0.192 ;
     RECT  75.576 0.144 75.792 0.192 ;
     RECT  75.816 0.144 76.032 0.192 ;
     RECT  76.056 0.144 76.272 0.192 ;
     RECT  76.296 0.144 76.512 0.192 ;
     RECT  76.536 0.144 76.752 0.192 ;
     RECT  76.776 0.144 76.992 0.192 ;
     RECT  77.016 0.144 77.232 0.192 ;
     RECT  77.256 0.144 77.52 0.192 ;
     RECT  77.544 0.144 77.76 0.192 ;
     RECT  77.784 0.144 78 0.192 ;
     RECT  78.024 0.144 78.24 0.192 ;
     RECT  78.264 0.144 78.48 0.192 ;
     RECT  78.504 0.144 78.72 0.192 ;
     RECT  78.744 0.144 78.96 0.192 ;
     RECT  78.984 0.144 79.2 0.192 ;
     RECT  79.224 0.144 79.44 0.192 ;
     RECT  79.464 0.144 79.68 0.192 ;
     RECT  79.704 0.144 79.92 0.192 ;
     RECT  79.944 0.144 80.208 0.192 ;
     RECT  80.232 0.144 80.448 0.192 ;
     RECT  80.472 0.144 80.688 0.192 ;
     RECT  80.712 0.144 80.928 0.192 ;
     RECT  80.952 0.144 81.168 0.192 ;
     RECT  81.192 0.144 81.408 0.192 ;
     RECT  81.432 0.144 81.648 0.192 ;
     RECT  81.672 0.144 81.888 0.192 ;
     RECT  81.912 0.144 82.128 0.192 ;
     RECT  82.152 0.144 82.368 0.192 ;
     RECT  82.392 0.144 82.608 0.192 ;
     RECT  82.632 0.144 82.848 0.192 ;
     RECT  82.872 0.144 83.136 0.192 ;
     RECT  83.16 0.144 83.376 0.192 ;
     RECT  83.4 0.144 83.616 0.192 ;
     RECT  83.64 0.144 83.856 0.192 ;
     RECT  83.88 0.144 84.096 0.192 ;
     RECT  84.12 0.144 84.336 0.192 ;
     RECT  84.36 0.144 84.576 0.192 ;
     RECT  84.6 0.144 84.816 0.192 ;
     RECT  84.84 0.144 85.056 0.192 ;
     RECT  85.08 0.144 85.296 0.192 ;
     RECT  85.32 0.144 85.536 0.192 ;
     RECT  85.56 0.144 85.824 0.192 ;
     RECT  85.848 0.144 86.064 0.192 ;
     RECT  86.088 0.144 86.304 0.192 ;
     RECT  86.328 0.144 86.544 0.192 ;
     RECT  86.568 0.144 86.784 0.192 ;
     RECT  86.808 0.144 87.024 0.192 ;
     RECT  87.048 0.144 87.264 0.192 ;
     RECT  87.288 0.144 87.504 0.192 ;
     RECT  87.528 0.144 87.744 0.192 ;
     RECT  87.768 0.144 87.984 0.192 ;
     RECT  88.008 0.144 88.224 0.192 ;
     RECT  88.248 0.144 88.464 0.192 ;
     RECT  4.512 0.192 88.488 1.763 ;
     RECT  18.384 1.763 88.488 1.811 ;
     RECT  20.352 1.811 33.288 1.859 ;
     RECT  12.288 1.763 17.208 1.907 ;
     RECT  5.1 1.763 5.496 2.099 ;
     RECT  7.2 1.763 11.112 2.099 ;
     RECT  87.504 1.811 88.488 2.137 ;
     RECT  2.4 2.137 2.52 2.151 ;
     RECT  87.504 2.137 88.92 2.151 ;
     RECT  87.504 2.151 89.112 2.245 ;
     RECT  7.2 2.099 10.812 2.291 ;
     RECT  49.92 1.811 78.312 2.291 ;
     RECT  79.92 1.811 86.52 2.291 ;
     RECT  87.504 2.245 89.256 2.291 ;
     RECT  9.84 2.291 10.812 2.339 ;
     RECT  50.16 2.291 75.768 2.339 ;
     RECT  20.928 1.859 33.288 2.821 ;
     RECT  34.512 1.811 44.328 2.821 ;
     RECT  45.504 1.811 48.936 2.821 ;
     RECT  7.2 2.291 8.424 2.915 ;
     RECT  12.288 1.907 13.656 2.915 ;
     RECT  15.216 1.907 17.208 2.915 ;
     RECT  50.16 2.339 52.44 2.915 ;
     RECT  79.92 2.291 84.84 2.915 ;
     RECT  85.824 2.291 86.52 2.915 ;
     RECT  86.1 2.915 86.52 2.917 ;
     RECT  87.504 2.291 87.528 2.917 ;
     RECT  18.384 1.811 19.176 2.963 ;
     RECT  20.928 2.821 48.936 2.963 ;
     RECT  76.896 2.291 78.312 3.205 ;
     RECT  76.896 3.205 78.408 3.347 ;
     RECT  7.44 2.915 8.424 3.443 ;
     RECT  10.368 2.339 10.812 3.443 ;
     RECT  20.928 2.963 48.612 3.443 ;
     RECT  76.896 3.347 77.016 3.443 ;
     RECT  80.7 2.915 83.712 3.443 ;
     RECT  13.2 2.915 13.608 3.635 ;
     RECT  5.1 2.099 5.412 3.829 ;
     RECT  83.28 3.443 83.712 3.875 ;
     RECT  18.384 2.963 18.912 3.925 ;
     RECT  44.928 3.443 48.612 3.925 ;
     RECT  50.4 2.915 52.44 3.925 ;
     RECT  53.424 2.339 75.768 3.925 ;
     RECT  78 3.347 78.408 3.925 ;
     RECT  15.9 2.915 16.536 4.019 ;
     RECT  44.928 3.925 48.888 4.019 ;
     RECT  50.4 3.925 75.768 4.261 ;
     RECT  76.896 3.443 76.92 4.261 ;
     RECT  86.1 2.917 87.528 4.405 ;
     RECT  88.8 2.291 89.256 4.405 ;
     RECT  15.9 4.019 16.488 4.501 ;
     RECT  80.7 3.443 81.432 4.501 ;
     RECT  83.4 3.875 83.712 4.501 ;
     RECT  7.8 3.443 8.424 4.595 ;
     RECT  50.4 4.261 76.92 4.595 ;
     RECT  86.1 4.405 89.256 4.595 ;
     RECT  10.5 3.443 10.812 4.645 ;
     RECT  5.1 3.829 5.88 4.883 ;
     RECT  18.384 3.925 19.08 4.933 ;
     RECT  80.7 4.501 81.48 4.981 ;
     RECT  18.192 4.933 19.08 5.029 ;
     RECT  15.456 4.501 16.488 5.075 ;
     RECT  13.2 3.635 13.512 5.077 ;
     RECT  44.928 4.019 45.912 5.077 ;
     RECT  46.944 4.019 48.888 5.077 ;
     RECT  50.688 4.595 76.92 5.077 ;
     RECT  78 3.925 79.368 5.077 ;
     RECT  50.688 5.077 79.368 5.171 ;
     RECT  83.4 4.501 84.696 5.171 ;
     RECT  13.2 5.077 14.28 5.173 ;
     RECT  69.696 5.171 79.368 5.219 ;
     RECT  15.456 5.075 16.44 5.267 ;
     RECT  86.1 4.595 86.904 5.267 ;
     RECT  20.928 3.443 43.212 5.315 ;
     RECT  20.928 5.315 41.016 5.363 ;
     RECT  44.928 5.077 48.888 5.459 ;
     RECT  69.696 5.219 78.504 5.459 ;
     RECT  87.888 4.595 89.256 5.459 ;
     RECT  44.928 5.459 48.84 5.509 ;
     RECT  13.104 5.173 14.28 5.557 ;
     RECT  50.688 5.171 68.664 5.605 ;
     RECT  83.4 5.171 83.712 5.605 ;
     RECT  23.856 5.363 41.016 5.747 ;
     RECT  49.968 5.605 68.664 5.747 ;
     RECT  84.72 5.269 84.744 5.747 ;
     RECT  34.56 5.747 41.016 5.795 ;
     RECT  44.592 5.509 48.84 5.795 ;
     RECT  88.8 5.459 89.256 5.795 ;
     RECT  23.856 5.747 32.412 5.843 ;
     RECT  10.5 4.645 10.92 5.845 ;
     RECT  10.5 5.845 11.496 5.989 ;
     RECT  12.528 5.557 14.28 5.989 ;
     RECT  17.664 5.029 19.08 6.035 ;
     RECT  55.392 5.747 68.664 6.083 ;
     RECT  77.232 5.459 78.504 6.131 ;
     RECT  80.592 4.981 81.48 6.133 ;
     RECT  17.664 6.035 18.912 6.181 ;
     RECT  20.928 5.363 22.824 6.181 ;
     RECT  10.5 5.989 14.28 6.229 ;
     RECT  15.456 5.267 16.212 6.229 ;
     RECT  10.5 6.229 16.212 6.275 ;
     RECT  49.968 5.747 54.12 6.275 ;
     RECT  80.496 6.133 81.48 6.275 ;
     RECT  55.392 6.083 65.976 6.323 ;
     RECT  69.696 5.459 76.152 6.323 ;
     RECT  44.592 5.795 46.824 6.371 ;
     RECT  20.496 6.181 22.824 6.419 ;
     RECT  34.704 5.795 41.016 6.419 ;
     RECT  56.208 6.323 62.616 6.419 ;
     RECT  67.2 6.083 68.664 6.419 ;
     RECT  71.328 6.323 76.152 6.419 ;
     RECT  78 6.131 78.504 6.517 ;
     RECT  67.2 6.419 68.376 6.563 ;
     RECT  78 6.517 79.416 6.563 ;
     RECT  50.88 6.275 54.012 6.611 ;
     RECT  63.84 6.323 65.256 6.611 ;
     RECT  20.496 6.419 22.056 6.613 ;
     RECT  83.28 5.605 83.712 6.709 ;
     RECT  31.296 5.843 32.412 6.803 ;
     RECT  39.792 6.419 41.016 6.803 ;
     RECT  75.168 6.419 76.152 6.803 ;
     RECT  83.28 6.709 84.168 6.805 ;
     RECT  80.496 6.275 81.384 6.851 ;
     RECT  10.5 6.275 14.52 6.899 ;
     RECT  31.872 6.803 32.412 6.899 ;
     RECT  34.704 6.419 38.664 6.899 ;
     RECT  45.456 6.371 46.824 6.899 ;
     RECT  47.808 5.795 48.84 6.899 ;
     RECT  51 6.611 54.012 6.899 ;
     RECT  69.696 6.323 70.212 6.899 ;
     RECT  71.328 6.419 73.944 6.899 ;
     RECT  79.392 6.563 79.416 6.899 ;
     RECT  12.528 6.899 13.512 6.947 ;
     RECT  15.792 6.275 16.212 6.947 ;
     RECT  20.16 6.613 22.056 6.947 ;
     RECT  34.704 6.899 38.232 6.947 ;
     RECT  58.944 6.419 62.616 6.947 ;
     RECT  69.792 6.899 70.212 6.947 ;
     RECT  58.992 6.947 62.616 6.995 ;
     RECT  17.616 6.181 18.912 7.043 ;
     RECT  23.856 5.843 29.928 7.139 ;
     RECT  23.856 7.139 29.712 7.189 ;
     RECT  52.464 6.899 52.488 7.235 ;
     RECT  21.3 6.947 22.056 7.331 ;
     RECT  63.84 6.611 64.968 7.379 ;
     RECT  80.496 6.851 81.012 7.379 ;
     RECT  69.9 6.947 70.212 7.381 ;
     RECT  71.328 6.899 71.544 7.381 ;
     RECT  14.496 6.899 14.52 7.475 ;
     RECT  23.712 7.189 29.712 7.475 ;
     RECT  34.704 6.947 38.184 7.475 ;
     RECT  45.6 6.899 46.824 7.475 ;
     RECT  61.8 6.995 62.616 7.475 ;
     RECT  80.592 7.379 81.012 7.475 ;
     RECT  83.232 6.805 84.168 7.475 ;
     RECT  20.16 6.947 20.184 7.619 ;
     RECT  23.712 7.475 24.936 7.715 ;
     RECT  45.6 7.475 46.728 7.859 ;
     RECT  36.912 7.475 38.04 8.003 ;
     RECT  48.144 6.899 48.84 8.003 ;
     RECT  63.84 7.379 64.92 8.003 ;
     RECT  67.2 6.563 68.328 8.003 ;
     RECT  58.992 6.995 60.408 8.195 ;
     RECT  26.016 7.475 27.336 8.579 ;
     RECT  28.464 7.475 29.712 8.579 ;
     RECT  39.792 6.803 40.512 8.579 ;
     RECT  69.9 7.381 71.544 8.579 ;
     RECT  56.208 6.419 57.48 8.771 ;
     RECT  24 7.715 24.936 9.155 ;
     RECT  37.344 8.003 38.04 9.155 ;
     RECT  59.1 8.195 60.408 9.155 ;
     RECT  64.5 8.003 64.92 9.155 ;
     RECT  69.9 8.579 70.824 9.155 ;
     RECT  72.6 6.899 73.944 9.155 ;
     RECT  26.16 8.579 27.012 9.731 ;
     RECT  42.048 5.315 43.212 10.307 ;
     RECT  24 9.155 24.408 10.883 ;
     RECT  37.5 9.155 38.04 10.883 ;
     RECT  39.84 8.579 40.512 10.883 ;
     RECT  56.4 8.771 57.48 10.883 ;
     RECT  60.384 9.155 60.408 10.883 ;
     RECT  72.6 9.155 73.464 10.883 ;
     RECT  75.3 6.803 76.152 11.459 ;
     RECT  53.7 6.899 54.012 16.693 ;
     RECT  0.24 6.085 0.264 18.419 ;
     RECT  53.7 16.693 54.12 18.467 ;
     RECT  34.8 7.475 35.112 18.517 ;
     RECT  34.8 18.517 35.208 20.051 ;
     RECT  18.6 7.043 18.912 27.685 ;
     RECT  7.8 4.595 8.112 27.829 ;
     RECT  40.2 10.883 40.512 27.829 ;
     RECT  7.8 27.829 8.232 27.877 ;
     RECT  10.5 6.899 10.812 27.877 ;
     RECT  15.9 6.947 16.212 27.877 ;
     RECT  18.432 27.685 18.912 27.877 ;
     RECT  21.3 7.331 21.612 27.877 ;
     RECT  26.7 9.731 27.012 27.877 ;
     RECT  29.4 8.579 29.712 27.877 ;
     RECT  37.5 10.883 37.812 27.877 ;
     RECT  40.2 27.829 41.16 27.877 ;
     RECT  42.9 10.307 43.212 27.877 ;
     RECT  48.3 8.003 48.612 27.877 ;
     RECT  51 6.899 51.312 27.877 ;
     RECT  59.1 9.155 59.412 27.877 ;
     RECT  69.9 9.155 70.212 27.877 ;
     RECT  75.3 11.459 75.612 27.877 ;
     RECT  86.1 5.267 86.412 27.877 ;
     RECT  32.1 6.899 32.412 28.261 ;
     RECT  61.8 7.475 62.112 28.261 ;
     RECT  67.2 8.003 67.512 28.261 ;
     RECT  78 6.563 78.312 28.261 ;
     RECT  86.1 27.877 87.288 28.261 ;
     RECT  88.8 5.795 89.112 28.261 ;
     RECT  5.1 4.883 5.412 28.309 ;
     RECT  6.432 27.877 6.456 28.309 ;
     RECT  7.632 27.877 8.232 28.309 ;
     RECT  15.9 27.877 16.728 28.309 ;
     RECT  17.904 27.877 18.912 28.309 ;
     RECT  20.592 27.877 22.344 28.309 ;
     RECT  24 10.883 24.312 28.309 ;
     RECT  26.448 27.877 27.012 28.309 ;
     RECT  29.4 27.877 29.832 28.309 ;
     RECT  31.968 28.261 32.412 28.309 ;
     RECT  37.2 27.877 41.16 28.309 ;
     RECT  42.576 27.877 43.212 28.309 ;
     RECT  44.544 27.781 44.568 28.309 ;
     RECT  45.6 7.859 45.912 28.309 ;
     RECT  47.712 27.877 48.612 28.309 ;
     RECT  53.7 18.467 54.012 28.309 ;
     RECT  55.296 27.877 55.32 28.309 ;
     RECT  58.224 27.877 59.412 28.309 ;
     RECT  64.5 9.155 64.812 28.309 ;
     RECT  67.2 28.261 67.608 28.309 ;
     RECT  75.3 27.877 76.296 28.309 ;
     RECT  77.904 28.261 78.312 28.309 ;
     RECT  86.1 28.261 89.112 28.309 ;
     RECT  10.128 27.877 11.352 28.357 ;
     RECT  13.2 6.947 13.512 28.357 ;
     RECT  15.216 28.309 22.344 28.357 ;
     RECT  24 28.309 25.272 28.357 ;
     RECT  26.448 28.309 27.24 28.357 ;
     RECT  67.2 28.309 68.712 28.357 ;
     RECT  69.696 27.877 70.212 28.357 ;
     RECT  72.6 10.883 72.912 28.357 ;
     RECT  77.904 28.309 79.224 28.357 ;
     RECT  80.7 7.475 81.012 28.357 ;
     RECT  14.976 28.357 22.344 28.405 ;
     RECT  24 28.357 27.72 28.405 ;
     RECT  29.4 28.309 30.648 28.405 ;
     RECT  31.968 28.309 33.576 28.405 ;
     RECT  34.8 20.051 35.112 28.405 ;
     RECT  37.2 28.309 41.4 28.405 ;
     RECT  42.576 28.309 45.912 28.405 ;
     RECT  47.712 28.309 48.936 28.405 ;
     RECT  52.608 27.877 52.632 28.405 ;
     RECT  53.7 28.309 55.32 28.405 ;
     RECT  56.4 10.883 56.712 28.405 ;
     RECT  58.224 28.309 59.928 28.405 ;
     RECT  61.392 28.261 62.112 28.405 ;
     RECT  66 28.309 66.024 28.405 ;
     RECT  67.2 28.357 70.212 28.405 ;
     RECT  72.6 28.357 73.128 28.405 ;
     RECT  75.3 28.309 76.536 28.405 ;
     RECT  77.76 28.357 81.012 28.405 ;
     RECT  4.512 28.309 6.456 28.453 ;
     RECT  7.632 28.309 9.144 28.453 ;
     RECT  10.128 28.357 13.512 28.453 ;
     RECT  14.736 28.405 22.344 28.453 ;
     RECT  24 28.405 33.576 28.453 ;
     RECT  34.704 28.405 35.112 28.453 ;
     RECT  36.72 28.405 41.4 28.453 ;
     RECT  42.576 28.405 46.008 28.453 ;
     RECT  50.16 27.877 51.312 28.453 ;
     RECT  52.608 28.405 59.928 28.453 ;
     RECT  61.152 28.405 62.112 28.453 ;
     RECT  63.36 28.309 64.812 28.453 ;
     RECT  66 28.405 70.212 28.453 ;
     RECT  72.144 28.405 73.128 28.453 ;
     RECT  74.832 28.405 76.536 28.453 ;
     RECT  77.52 28.405 81.012 28.453 ;
     RECT  83.4 7.475 83.712 28.453 ;
     RECT  85.536 28.309 89.112 28.453 ;
     RECT  42.576 28.453 46.536 28.837 ;
     RECT  47.712 28.405 49.176 28.837 ;
     RECT  50.16 28.453 59.928 28.837 ;
     RECT  60.912 28.453 73.128 28.837 ;
     RECT  74.304 28.453 81.012 28.837 ;
     RECT  34.704 28.453 41.4 28.933 ;
     RECT  42.576 28.837 49.176 28.933 ;
     RECT  10.128 28.453 33.576 29.029 ;
     RECT  34.704 28.933 49.176 29.029 ;
     RECT  50.16 28.837 81.432 29.029 ;
     RECT  82.848 28.453 89.112 29.029 ;
     RECT  4.512 28.453 9.144 33.013 ;
     RECT  10.128 29.029 89.112 33.013 ;
     RECT  2.4 2.151 2.712 34.569 ;
     RECT  4.512 33.013 89.112 34.569 ;
     RECT  2.4 34.569 2.52 34.583 ;
     RECT  4.512 34.569 88.92 34.583 ;
     RECT  4.512 34.583 42.84 35.893 ;
     RECT  43.824 34.583 88.248 35.893 ;
     RECT  4.512 35.893 88.488 36.528 ;
     RECT  4.536 36.528 4.752 36.56 ;
     RECT  4.776 36.528 4.992 36.56 ;
     RECT  5.016 36.528 5.232 36.56 ;
     RECT  5.256 36.528 5.472 36.56 ;
     RECT  5.496 36.528 5.712 36.56 ;
     RECT  5.736 36.528 5.952 36.56 ;
     RECT  5.976 36.528 6.192 36.56 ;
     RECT  6.216 36.528 6.432 36.56 ;
     RECT  6.456 36.528 6.672 36.56 ;
     RECT  6.696 36.528 6.912 36.56 ;
     RECT  6.936 36.528 7.2 36.56 ;
     RECT  7.224 36.528 7.44 36.56 ;
     RECT  7.464 36.528 7.68 36.56 ;
     RECT  7.704 36.528 7.92 36.56 ;
     RECT  7.944 36.528 8.16 36.56 ;
     RECT  8.184 36.528 8.4 36.56 ;
     RECT  8.424 36.528 8.64 36.56 ;
     RECT  8.664 36.528 8.88 36.56 ;
     RECT  8.904 36.528 9.12 36.56 ;
     RECT  9.144 36.528 9.36 36.56 ;
     RECT  9.384 36.528 9.6 36.56 ;
     RECT  9.624 36.528 9.84 36.56 ;
     RECT  9.864 36.528 10.128 36.56 ;
     RECT  10.152 36.528 10.368 36.56 ;
     RECT  10.392 36.528 10.608 36.56 ;
     RECT  10.632 36.528 10.848 36.56 ;
     RECT  10.872 36.528 11.088 36.56 ;
     RECT  11.112 36.528 11.328 36.56 ;
     RECT  11.352 36.528 11.568 36.56 ;
     RECT  11.592 36.528 11.808 36.56 ;
     RECT  11.832 36.528 12.048 36.56 ;
     RECT  12.072 36.528 12.288 36.56 ;
     RECT  12.312 36.528 12.528 36.56 ;
     RECT  12.552 36.528 12.816 36.56 ;
     RECT  12.84 36.528 13.056 36.56 ;
     RECT  13.08 36.528 13.296 36.56 ;
     RECT  13.32 36.528 13.536 36.56 ;
     RECT  13.56 36.528 13.776 36.56 ;
     RECT  13.8 36.528 14.016 36.56 ;
     RECT  14.04 36.528 14.256 36.56 ;
     RECT  14.28 36.528 14.496 36.56 ;
     RECT  14.52 36.528 14.736 36.56 ;
     RECT  14.76 36.528 14.976 36.56 ;
     RECT  15 36.528 15.216 36.56 ;
     RECT  15.24 36.528 15.456 36.56 ;
     RECT  15.48 36.528 15.744 36.56 ;
     RECT  15.768 36.528 15.984 36.56 ;
     RECT  16.008 36.528 16.224 36.56 ;
     RECT  16.248 36.528 16.464 36.56 ;
     RECT  16.488 36.528 16.704 36.56 ;
     RECT  16.728 36.528 16.944 36.56 ;
     RECT  16.968 36.528 17.184 36.56 ;
     RECT  17.208 36.528 17.424 36.56 ;
     RECT  17.448 36.528 17.664 36.56 ;
     RECT  17.688 36.528 17.904 36.56 ;
     RECT  17.928 36.528 18.144 36.56 ;
     RECT  18.168 36.528 18.432 36.56 ;
     RECT  18.456 36.528 18.672 36.56 ;
     RECT  18.696 36.528 18.912 36.56 ;
     RECT  18.936 36.528 19.152 36.56 ;
     RECT  19.176 36.528 19.392 36.56 ;
     RECT  19.416 36.528 19.632 36.56 ;
     RECT  19.656 36.528 19.872 36.56 ;
     RECT  19.896 36.528 20.112 36.56 ;
     RECT  20.136 36.528 20.352 36.56 ;
     RECT  20.376 36.528 20.592 36.56 ;
     RECT  20.616 36.528 20.832 36.56 ;
     RECT  20.856 36.528 21.072 36.56 ;
     RECT  21.096 36.528 21.36 36.56 ;
     RECT  21.384 36.528 21.6 36.56 ;
     RECT  21.624 36.528 21.84 36.56 ;
     RECT  21.864 36.528 22.08 36.56 ;
     RECT  22.104 36.528 22.32 36.56 ;
     RECT  22.344 36.528 22.56 36.56 ;
     RECT  22.584 36.528 22.8 36.56 ;
     RECT  22.824 36.528 23.04 36.56 ;
     RECT  23.064 36.528 23.28 36.56 ;
     RECT  23.304 36.528 23.52 36.56 ;
     RECT  23.544 36.528 23.76 36.56 ;
     RECT  23.784 36.528 24.048 36.56 ;
     RECT  24.072 36.528 24.288 36.56 ;
     RECT  24.312 36.528 24.528 36.56 ;
     RECT  24.552 36.528 24.768 36.56 ;
     RECT  24.792 36.528 25.008 36.56 ;
     RECT  25.032 36.528 25.248 36.56 ;
     RECT  25.272 36.528 25.488 36.56 ;
     RECT  25.512 36.528 25.728 36.56 ;
     RECT  25.752 36.528 25.968 36.56 ;
     RECT  25.992 36.528 26.208 36.56 ;
     RECT  26.232 36.528 26.448 36.56 ;
     RECT  26.472 36.528 26.688 36.56 ;
     RECT  26.712 36.528 26.976 36.56 ;
     RECT  27 36.528 27.216 36.56 ;
     RECT  27.24 36.528 27.456 36.56 ;
     RECT  27.48 36.528 27.696 36.56 ;
     RECT  27.72 36.528 27.936 36.56 ;
     RECT  27.96 36.528 28.176 36.56 ;
     RECT  28.2 36.528 28.416 36.56 ;
     RECT  28.44 36.528 28.656 36.56 ;
     RECT  28.68 36.528 28.896 36.56 ;
     RECT  28.92 36.528 29.136 36.56 ;
     RECT  29.16 36.528 29.376 36.56 ;
     RECT  29.4 36.528 29.664 36.56 ;
     RECT  29.688 36.528 29.904 36.56 ;
     RECT  29.928 36.528 30.144 36.56 ;
     RECT  30.168 36.528 30.384 36.56 ;
     RECT  30.408 36.528 30.624 36.56 ;
     RECT  30.648 36.528 30.864 36.56 ;
     RECT  30.888 36.528 31.104 36.56 ;
     RECT  31.128 36.528 31.344 36.56 ;
     RECT  31.368 36.528 31.584 36.56 ;
     RECT  31.608 36.528 31.824 36.56 ;
     RECT  31.848 36.528 32.064 36.56 ;
     RECT  32.088 36.528 32.304 36.56 ;
     RECT  32.328 36.528 32.592 36.56 ;
     RECT  32.616 36.528 32.832 36.56 ;
     RECT  32.856 36.528 33.072 36.56 ;
     RECT  33.096 36.528 33.312 36.56 ;
     RECT  33.336 36.528 33.552 36.56 ;
     RECT  33.576 36.528 33.792 36.56 ;
     RECT  33.816 36.528 34.032 36.56 ;
     RECT  34.056 36.528 34.272 36.56 ;
     RECT  34.296 36.528 34.512 36.56 ;
     RECT  34.536 36.528 34.752 36.56 ;
     RECT  34.776 36.528 34.992 36.56 ;
     RECT  35.016 36.528 35.28 36.56 ;
     RECT  35.304 36.528 35.52 36.56 ;
     RECT  35.544 36.528 35.76 36.56 ;
     RECT  35.784 36.528 36 36.56 ;
     RECT  36.024 36.528 36.24 36.56 ;
     RECT  36.264 36.528 36.48 36.56 ;
     RECT  36.504 36.528 36.72 36.56 ;
     RECT  36.744 36.528 36.96 36.56 ;
     RECT  36.984 36.528 37.2 36.56 ;
     RECT  37.224 36.528 37.44 36.56 ;
     RECT  37.464 36.528 37.68 36.56 ;
     RECT  37.704 36.528 37.92 36.56 ;
     RECT  37.944 36.528 38.208 36.56 ;
     RECT  38.232 36.528 38.448 36.56 ;
     RECT  38.472 36.528 38.688 36.56 ;
     RECT  38.712 36.528 38.928 36.56 ;
     RECT  38.952 36.528 39.168 36.56 ;
     RECT  39.192 36.528 39.408 36.56 ;
     RECT  39.432 36.528 39.648 36.56 ;
     RECT  39.672 36.528 39.888 36.56 ;
     RECT  39.912 36.528 40.128 36.56 ;
     RECT  40.152 36.528 40.368 36.56 ;
     RECT  40.392 36.528 40.608 36.56 ;
     RECT  40.632 36.528 40.896 36.56 ;
     RECT  40.92 36.528 41.136 36.56 ;
     RECT  41.16 36.528 41.376 36.56 ;
     RECT  41.4 36.528 41.616 36.56 ;
     RECT  41.64 36.528 41.856 36.56 ;
     RECT  41.88 36.528 42.096 36.56 ;
     RECT  42.12 36.528 42.336 36.56 ;
     RECT  42.36 36.528 42.576 36.56 ;
     RECT  42.6 36.528 42.816 36.56 ;
     RECT  42.84 36.528 43.056 36.56 ;
     RECT  43.08 36.528 43.296 36.56 ;
     RECT  43.32 36.528 43.536 36.56 ;
     RECT  43.56 36.528 43.824 36.56 ;
     RECT  43.848 36.528 44.064 36.56 ;
     RECT  44.088 36.528 44.304 36.56 ;
     RECT  44.328 36.528 44.544 36.56 ;
     RECT  44.568 36.528 44.784 36.56 ;
     RECT  44.808 36.528 45.024 36.56 ;
     RECT  45.048 36.528 45.264 36.56 ;
     RECT  45.288 36.528 45.504 36.56 ;
     RECT  45.528 36.528 45.744 36.56 ;
     RECT  45.768 36.528 45.984 36.56 ;
     RECT  46.008 36.528 46.224 36.56 ;
     RECT  46.248 36.528 46.512 36.56 ;
     RECT  46.536 36.528 46.752 36.56 ;
     RECT  46.776 36.528 46.992 36.56 ;
     RECT  47.016 36.528 47.232 36.56 ;
     RECT  47.256 36.528 47.472 36.56 ;
     RECT  47.496 36.528 47.712 36.56 ;
     RECT  47.736 36.528 47.952 36.56 ;
     RECT  47.976 36.528 48.192 36.56 ;
     RECT  48.216 36.528 48.432 36.56 ;
     RECT  48.456 36.528 48.672 36.56 ;
     RECT  48.696 36.528 48.912 36.56 ;
     RECT  48.936 36.528 49.152 36.56 ;
     RECT  49.176 36.528 49.44 36.56 ;
     RECT  49.464 36.528 49.68 36.56 ;
     RECT  49.704 36.528 49.92 36.56 ;
     RECT  49.944 36.528 50.16 36.56 ;
     RECT  50.184 36.528 50.4 36.56 ;
     RECT  50.424 36.528 50.64 36.56 ;
     RECT  50.664 36.528 50.88 36.56 ;
     RECT  50.904 36.528 51.12 36.56 ;
     RECT  51.144 36.528 51.36 36.56 ;
     RECT  51.384 36.528 51.6 36.56 ;
     RECT  51.624 36.528 51.84 36.56 ;
     RECT  51.864 36.528 52.128 36.56 ;
     RECT  52.152 36.528 52.368 36.56 ;
     RECT  52.392 36.528 52.608 36.56 ;
     RECT  52.632 36.528 52.848 36.56 ;
     RECT  52.872 36.528 53.088 36.56 ;
     RECT  53.112 36.528 53.328 36.56 ;
     RECT  53.352 36.528 53.568 36.56 ;
     RECT  53.592 36.528 53.808 36.56 ;
     RECT  53.832 36.528 54.048 36.56 ;
     RECT  54.072 36.528 54.288 36.56 ;
     RECT  54.312 36.528 54.528 36.56 ;
     RECT  54.552 36.528 54.768 36.56 ;
     RECT  54.792 36.528 55.056 36.56 ;
     RECT  55.08 36.528 55.296 36.56 ;
     RECT  55.32 36.528 55.536 36.56 ;
     RECT  55.56 36.528 55.776 36.56 ;
     RECT  55.8 36.528 56.016 36.56 ;
     RECT  56.04 36.528 56.256 36.56 ;
     RECT  56.28 36.528 56.496 36.56 ;
     RECT  56.52 36.528 56.736 36.56 ;
     RECT  56.76 36.528 56.976 36.56 ;
     RECT  57 36.528 57.216 36.56 ;
     RECT  57.24 36.528 57.456 36.56 ;
     RECT  57.48 36.528 57.744 36.56 ;
     RECT  57.768 36.528 57.984 36.56 ;
     RECT  58.008 36.528 58.224 36.56 ;
     RECT  58.248 36.528 58.464 36.56 ;
     RECT  58.488 36.528 58.704 36.56 ;
     RECT  58.728 36.528 58.944 36.56 ;
     RECT  58.968 36.528 59.184 36.56 ;
     RECT  59.208 36.528 59.424 36.56 ;
     RECT  59.448 36.528 59.664 36.56 ;
     RECT  59.688 36.528 59.904 36.56 ;
     RECT  59.928 36.528 60.144 36.56 ;
     RECT  60.168 36.528 60.384 36.56 ;
     RECT  60.408 36.528 60.672 36.56 ;
     RECT  60.696 36.528 60.912 36.56 ;
     RECT  60.936 36.528 61.152 36.56 ;
     RECT  61.176 36.528 61.392 36.56 ;
     RECT  61.416 36.528 61.632 36.56 ;
     RECT  61.656 36.528 61.872 36.56 ;
     RECT  61.896 36.528 62.112 36.56 ;
     RECT  62.136 36.528 62.352 36.56 ;
     RECT  62.376 36.528 62.592 36.56 ;
     RECT  62.616 36.528 62.832 36.56 ;
     RECT  62.856 36.528 63.072 36.56 ;
     RECT  63.096 36.528 63.36 36.56 ;
     RECT  63.384 36.528 63.6 36.56 ;
     RECT  63.624 36.528 63.84 36.56 ;
     RECT  63.864 36.528 64.08 36.56 ;
     RECT  64.104 36.528 64.32 36.56 ;
     RECT  64.344 36.528 64.56 36.56 ;
     RECT  64.584 36.528 64.8 36.56 ;
     RECT  64.824 36.528 65.04 36.56 ;
     RECT  65.064 36.528 65.28 36.56 ;
     RECT  65.304 36.528 65.52 36.56 ;
     RECT  65.544 36.528 65.76 36.56 ;
     RECT  65.784 36.528 66 36.56 ;
     RECT  66.024 36.528 66.288 36.56 ;
     RECT  66.312 36.528 66.528 36.56 ;
     RECT  66.552 36.528 66.768 36.56 ;
     RECT  66.792 36.528 67.008 36.56 ;
     RECT  67.032 36.528 67.248 36.56 ;
     RECT  67.272 36.528 67.488 36.56 ;
     RECT  67.512 36.528 67.728 36.56 ;
     RECT  67.752 36.528 67.968 36.56 ;
     RECT  67.992 36.528 68.208 36.56 ;
     RECT  68.232 36.528 68.448 36.56 ;
     RECT  68.472 36.528 68.688 36.56 ;
     RECT  68.712 36.528 68.976 36.56 ;
     RECT  69 36.528 69.216 36.56 ;
     RECT  69.24 36.528 69.456 36.56 ;
     RECT  69.48 36.528 69.696 36.56 ;
     RECT  69.72 36.528 69.936 36.56 ;
     RECT  69.96 36.528 70.176 36.56 ;
     RECT  70.2 36.528 70.416 36.56 ;
     RECT  70.44 36.528 70.656 36.56 ;
     RECT  70.68 36.528 70.896 36.56 ;
     RECT  70.92 36.528 71.136 36.56 ;
     RECT  71.16 36.528 71.376 36.56 ;
     RECT  71.4 36.528 71.616 36.56 ;
     RECT  71.64 36.528 71.904 36.56 ;
     RECT  71.928 36.528 72.144 36.56 ;
     RECT  72.168 36.528 72.384 36.56 ;
     RECT  72.408 36.528 72.624 36.56 ;
     RECT  72.648 36.528 72.864 36.56 ;
     RECT  72.888 36.528 73.104 36.56 ;
     RECT  73.128 36.528 73.344 36.56 ;
     RECT  73.368 36.528 73.584 36.56 ;
     RECT  73.608 36.528 73.824 36.56 ;
     RECT  73.848 36.528 74.064 36.56 ;
     RECT  74.088 36.528 74.304 36.56 ;
     RECT  74.328 36.528 74.592 36.56 ;
     RECT  74.616 36.528 74.832 36.56 ;
     RECT  74.856 36.528 75.072 36.56 ;
     RECT  75.096 36.528 75.312 36.56 ;
     RECT  75.336 36.528 75.552 36.56 ;
     RECT  75.576 36.528 75.792 36.56 ;
     RECT  75.816 36.528 76.032 36.56 ;
     RECT  76.056 36.528 76.272 36.56 ;
     RECT  76.296 36.528 76.512 36.56 ;
     RECT  76.536 36.528 76.752 36.56 ;
     RECT  76.776 36.528 76.992 36.56 ;
     RECT  77.016 36.528 77.232 36.56 ;
     RECT  77.256 36.528 77.52 36.56 ;
     RECT  77.544 36.528 77.76 36.56 ;
     RECT  77.784 36.528 78 36.56 ;
     RECT  78.024 36.528 78.24 36.56 ;
     RECT  78.264 36.528 78.48 36.56 ;
     RECT  78.504 36.528 78.72 36.56 ;
     RECT  78.744 36.528 78.96 36.56 ;
     RECT  78.984 36.528 79.2 36.56 ;
     RECT  79.224 36.528 79.44 36.56 ;
     RECT  79.464 36.528 79.68 36.56 ;
     RECT  79.704 36.528 79.92 36.56 ;
     RECT  79.944 36.528 80.208 36.56 ;
     RECT  80.232 36.528 80.448 36.56 ;
     RECT  80.472 36.528 80.688 36.56 ;
     RECT  80.712 36.528 80.928 36.56 ;
     RECT  80.952 36.528 81.168 36.56 ;
     RECT  81.192 36.528 81.408 36.56 ;
     RECT  81.432 36.528 81.648 36.56 ;
     RECT  81.672 36.528 81.888 36.56 ;
     RECT  81.912 36.528 82.128 36.56 ;
     RECT  82.152 36.528 82.368 36.56 ;
     RECT  82.392 36.528 82.608 36.56 ;
     RECT  82.632 36.528 82.848 36.56 ;
     RECT  82.872 36.528 83.136 36.56 ;
     RECT  83.16 36.528 83.376 36.56 ;
     RECT  83.4 36.528 83.616 36.56 ;
     RECT  83.64 36.528 83.856 36.56 ;
     RECT  83.88 36.528 84.096 36.56 ;
     RECT  84.12 36.528 84.336 36.56 ;
     RECT  84.36 36.528 84.576 36.56 ;
     RECT  84.6 36.528 84.816 36.56 ;
     RECT  84.84 36.528 85.056 36.56 ;
     RECT  85.08 36.528 85.296 36.56 ;
     RECT  85.32 36.528 85.536 36.56 ;
     RECT  85.56 36.528 85.824 36.56 ;
     RECT  85.848 36.528 86.064 36.56 ;
     RECT  86.088 36.528 86.304 36.56 ;
     RECT  86.328 36.528 86.544 36.56 ;
     RECT  86.568 36.528 86.784 36.56 ;
     RECT  86.808 36.528 87.024 36.56 ;
     RECT  87.048 36.528 87.264 36.56 ;
     RECT  87.288 36.528 87.504 36.56 ;
     RECT  87.528 36.528 87.744 36.56 ;
     RECT  87.768 36.528 87.984 36.56 ;
     RECT  88.008 36.528 88.224 36.56 ;
     RECT  88.248 36.528 88.464 36.56 ;
     RECT  71.784 0.133 71.856 0.144 ;
     RECT  71.976 0.133 72.096 0.144 ;
     RECT  72.216 0.133 72.336 0.144 ;
     RECT  72.456 0.133 72.576 0.144 ;
     RECT  72.696 0.133 72.816 0.144 ;
     RECT  72.936 0.133 73.056 0.144 ;
     RECT  73.176 0.133 73.248 0.144 ;
     RECT  11.112 1.763 12.288 2.099 ;
     RECT  17.208 1.763 18.384 2.915 ;
     RECT  19.176 1.811 20.352 1.859 ;
     RECT  33.288 1.811 34.512 2.821 ;
     RECT  44.328 1.811 45.504 2.821 ;
     RECT  48.936 1.811 49.92 2.291 ;
     RECT  78.312 1.811 79.92 2.915 ;
     RECT  86.52 1.811 87.504 2.917 ;
     RECT  10.812 2.099 12.288 2.915 ;
     RECT  8.424 2.291 9.84 2.339 ;
     RECT  48.936 2.291 50.16 2.915 ;
     RECT  75.768 2.291 76.896 4.261 ;
     RECT  84.84 2.291 85.824 2.915 ;
     RECT  87.528 2.291 88.8 4.405 ;
     RECT  52.44 2.339 53.424 3.925 ;
     RECT  48.936 2.915 50.4 2.963 ;
     RECT  78.312 2.915 80.7 3.205 ;
     RECT  18.912 2.963 19.08 3.925 ;
     RECT  48.612 2.963 50.4 3.925 ;
     RECT  78.408 3.205 80.7 3.925 ;
     RECT  77.016 3.347 78 3.443 ;
     RECT  76.92 3.443 78 5.077 ;
     RECT  81.432 3.443 81.48 4.501 ;
     RECT  13.512 3.635 13.608 5.077 ;
     RECT  48.888 3.925 50.4 4.595 ;
     RECT  79.368 3.925 80.7 4.981 ;
     RECT  16.488 4.019 16.536 5.029 ;
     RECT  45.912 4.019 46.944 5.077 ;
     RECT  84.696 4.501 86.1 5.171 ;
     RECT  48.888 4.595 50.688 5.459 ;
     RECT  86.904 4.595 87.888 5.267 ;
     RECT  79.368 4.981 80.592 5.219 ;
     RECT  16.488 5.029 17.664 5.075 ;
     RECT  16.44 5.075 17.664 5.267 ;
     RECT  14.28 5.077 15.456 6.229 ;
     RECT  68.664 5.171 69.696 6.419 ;
     RECT  83.712 5.171 86.1 5.269 ;
     RECT  78.504 5.219 80.592 6.133 ;
     RECT  16.212 5.267 17.664 6.181 ;
     RECT  86.412 5.267 87.888 5.459 ;
     RECT  83.712 5.269 84.72 5.747 ;
     RECT  84.744 5.269 86.1 5.747 ;
     RECT  41.016 5.315 42.048 6.803 ;
     RECT  22.824 5.363 23.856 6.419 ;
     RECT  48.84 5.459 50.688 5.605 ;
     RECT  76.152 5.459 77.232 6.131 ;
     RECT  43.212 5.509 44.592 6.371 ;
     RECT  48.84 5.605 49.968 6.275 ;
     RECT  54.12 5.747 55.392 6.275 ;
     RECT  83.712 5.747 84.168 6.709 ;
     RECT  46.824 5.795 47.808 6.899 ;
     RECT  29.928 5.843 31.296 6.803 ;
     RECT  11.496 5.845 12.528 5.989 ;
     RECT  18.912 6.035 19.08 6.181 ;
     RECT  65.976 6.083 67.2 6.323 ;
     RECT  78.504 6.133 80.496 6.517 ;
     RECT  16.212 6.181 17.616 7.043 ;
     RECT  18.912 6.181 20.496 6.613 ;
     RECT  14.52 6.275 15.792 6.947 ;
     RECT  54.012 6.275 55.392 6.323 ;
     RECT  62.616 6.323 63.84 7.475 ;
     RECT  70.212 6.323 71.328 7.381 ;
     RECT  23.712 6.419 23.856 7.189 ;
     RECT  38.664 6.419 39.792 6.899 ;
     RECT  57.48 6.419 58.944 6.947 ;
     RECT  68.376 6.419 69.696 6.563 ;
     RECT  73.944 6.419 75.168 6.803 ;
     RECT  79.416 6.517 80.496 6.899 ;
     RECT  68.328 6.563 69.696 6.899 ;
     RECT  78.312 6.563 79.392 6.899 ;
     RECT  18.912 6.613 20.16 7.619 ;
     RECT  73.944 6.803 75.3 9.155 ;
     RECT  13.512 6.899 14.496 7.475 ;
     RECT  46.824 6.899 48.144 7.475 ;
     RECT  51.312 6.899 52.464 7.235 ;
     RECT  52.488 6.899 53.7 7.235 ;
     RECT  68.328 6.899 69.792 6.947 ;
     RECT  71.544 6.899 72.6 8.579 ;
     RECT  14.52 6.947 15.9 7.475 ;
     RECT  20.184 6.947 21.3 7.619 ;
     RECT  57.48 6.947 58.992 8.195 ;
     RECT  60.408 6.995 61.8 10.883 ;
     RECT  24.936 7.475 26.016 8.579 ;
     RECT  27.336 7.475 28.464 8.579 ;
     RECT  46.728 7.475 48.144 7.859 ;
     RECT  24.936 8.579 26.16 9.155 ;
     RECT  59.412 9.155 60.384 10.883 ;
     RECT  43.212 27.781 44.544 28.309 ;
     RECT  44.568 27.781 45.6 28.309 ;
     RECT  5.412 27.877 6.432 28.309 ;
     RECT  6.456 27.877 7.632 28.453 ;
     RECT  16.728 27.877 17.904 28.309 ;
     RECT  41.16 27.877 42.576 28.309 ;
     RECT  51.312 27.877 52.608 28.453 ;
     RECT  52.632 27.877 53.7 28.405 ;
     RECT  54.012 27.877 55.296 28.309 ;
     RECT  55.32 27.877 56.4 28.405 ;
     RECT  56.712 27.877 58.224 28.405 ;
     RECT  87.288 27.877 88.8 28.261 ;
     RECT  9.144 28.309 10.128 33.013 ;
     RECT  25.272 28.309 26.448 28.357 ;
     RECT  30.648 28.309 31.968 28.405 ;
     RECT  33.576 28.309 34.8 28.405 ;
     RECT  41.4 28.309 42.576 28.933 ;
     RECT  48.936 28.309 50.16 28.405 ;
     RECT  59.928 28.309 61.392 28.405 ;
     RECT  62.112 28.309 63.36 28.453 ;
     RECT  64.812 28.309 66 28.453 ;
     RECT  66.024 28.309 67.2 28.405 ;
     RECT  68.712 28.309 69.696 28.357 ;
     RECT  76.536 28.309 77.904 28.357 ;
     RECT  79.224 28.309 80.7 28.357 ;
     RECT  13.512 28.357 14.976 28.405 ;
     RECT  76.536 28.357 77.76 28.405 ;
     RECT  13.512 28.405 14.736 28.453 ;
     RECT  33.576 28.405 34.704 29.029 ;
     RECT  49.176 28.405 50.16 29.029 ;
     RECT  59.928 28.405 61.152 28.453 ;
     RECT  76.536 28.405 77.52 28.453 ;
     RECT  46.536 28.453 47.712 28.837 ;
     RECT  59.928 28.453 60.912 28.837 ;
     RECT  73.128 28.453 74.304 28.837 ;
     RECT  81.432 28.837 82.848 29.029 ;
     RECT  42.84 34.583 43.824 35.893 ;
     RECT  88.248 34.583 88.488 35.893 ;
  END
END dsfd_hstnv_690
END LIBRARY
